VERSION 5.7 ;
BUSBITCHARS "[]" ;
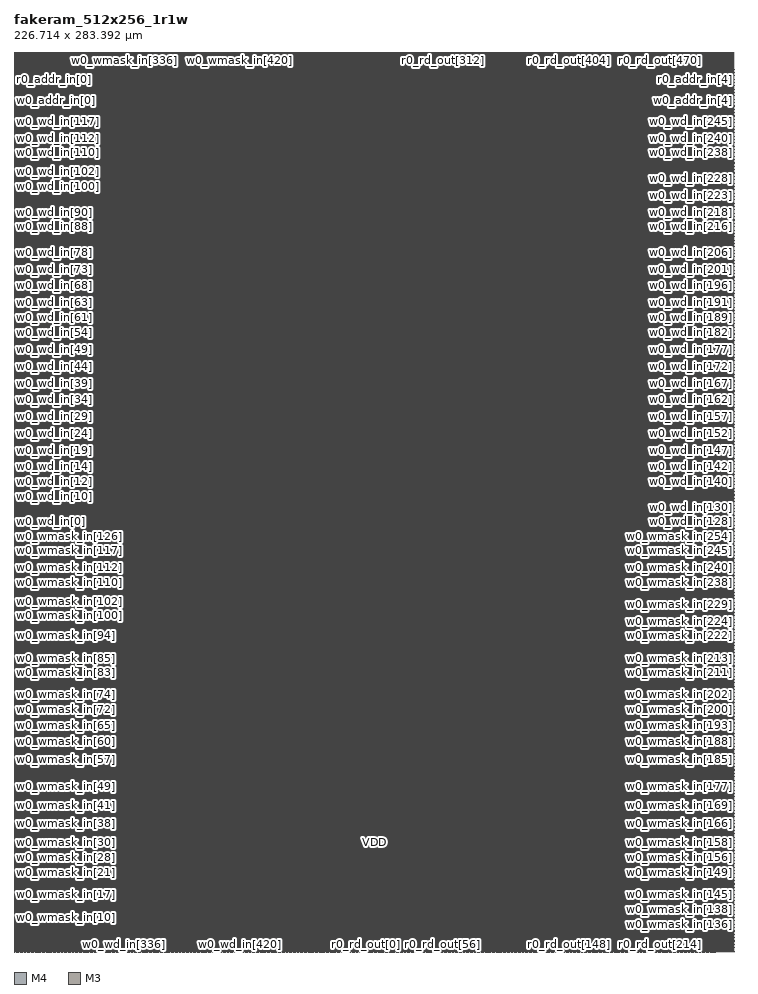
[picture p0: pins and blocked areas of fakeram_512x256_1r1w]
MACRO fakeram_512x256_1r1w
  FOREIGN fakeram_512x256_1r1w 0 0 ;
  SYMMETRY X Y R90 ;
  SIZE 226.714 BY 283.392 ;
  CLASS BLOCK ;
  PIN w0_wmask_in[0]
    DIRECTION INPUT ;
    USE SIGNAL ;
    SHAPE ABUTMENT ;
    PORT
      LAYER M4 ;
      RECT 0.000 0.276 0.072 0.300 ;
    END
  END w0_wmask_in[0]
  PIN w0_wmask_in[1]
    DIRECTION INPUT ;
    USE SIGNAL ;
    SHAPE ABUTMENT ;
    PORT
      LAYER M4 ;
      RECT 0.000 1.332 0.072 1.356 ;
    END
  END w0_wmask_in[1]
  PIN w0_wmask_in[2]
    DIRECTION INPUT ;
    USE SIGNAL ;
    SHAPE ABUTMENT ;
    PORT
      LAYER M4 ;
      RECT 0.000 2.388 0.072 2.412 ;
    END
  END w0_wmask_in[2]
  PIN w0_wmask_in[3]
    DIRECTION INPUT ;
    USE SIGNAL ;
    SHAPE ABUTMENT ;
    PORT
      LAYER M4 ;
      RECT 0.000 3.444 0.072 3.468 ;
    END
  END w0_wmask_in[3]
  PIN w0_wmask_in[4]
    DIRECTION INPUT ;
    USE SIGNAL ;
    SHAPE ABUTMENT ;
    PORT
      LAYER M4 ;
      RECT 0.000 4.500 0.072 4.524 ;
    END
  END w0_wmask_in[4]
  PIN w0_wmask_in[5]
    DIRECTION INPUT ;
    USE SIGNAL ;
    SHAPE ABUTMENT ;
    PORT
      LAYER M4 ;
      RECT 0.000 5.556 0.072 5.580 ;
    END
  END w0_wmask_in[5]
  PIN w0_wmask_in[6]
    DIRECTION INPUT ;
    USE SIGNAL ;
    SHAPE ABUTMENT ;
    PORT
      LAYER M4 ;
      RECT 0.000 6.612 0.072 6.636 ;
    END
  END w0_wmask_in[6]
  PIN w0_wmask_in[7]
    DIRECTION INPUT ;
    USE SIGNAL ;
    SHAPE ABUTMENT ;
    PORT
      LAYER M4 ;
      RECT 0.000 7.668 0.072 7.692 ;
    END
  END w0_wmask_in[7]
  PIN w0_wmask_in[8]
    DIRECTION INPUT ;
    USE SIGNAL ;
    SHAPE ABUTMENT ;
    PORT
      LAYER M4 ;
      RECT 0.000 8.724 0.072 8.748 ;
    END
  END w0_wmask_in[8]
  PIN w0_wmask_in[9]
    DIRECTION INPUT ;
    USE SIGNAL ;
    SHAPE ABUTMENT ;
    PORT
      LAYER M4 ;
      RECT 0.000 9.780 0.072 9.804 ;
    END
  END w0_wmask_in[9]
  PIN w0_wmask_in[10]
    DIRECTION INPUT ;
    USE SIGNAL ;
    SHAPE ABUTMENT ;
    PORT
      LAYER M4 ;
      RECT 0.000 10.836 0.072 10.860 ;
    END
  END w0_wmask_in[10]
  PIN w0_wmask_in[11]
    DIRECTION INPUT ;
    USE SIGNAL ;
    SHAPE ABUTMENT ;
    PORT
      LAYER M4 ;
      RECT 0.000 11.892 0.072 11.916 ;
    END
  END w0_wmask_in[11]
  PIN w0_wmask_in[12]
    DIRECTION INPUT ;
    USE SIGNAL ;
    SHAPE ABUTMENT ;
    PORT
      LAYER M4 ;
      RECT 0.000 12.948 0.072 12.972 ;
    END
  END w0_wmask_in[12]
  PIN w0_wmask_in[13]
    DIRECTION INPUT ;
    USE SIGNAL ;
    SHAPE ABUTMENT ;
    PORT
      LAYER M4 ;
      RECT 0.000 14.004 0.072 14.028 ;
    END
  END w0_wmask_in[13]
  PIN w0_wmask_in[14]
    DIRECTION INPUT ;
    USE SIGNAL ;
    SHAPE ABUTMENT ;
    PORT
      LAYER M4 ;
      RECT 0.000 15.060 0.072 15.084 ;
    END
  END w0_wmask_in[14]
  PIN w0_wmask_in[15]
    DIRECTION INPUT ;
    USE SIGNAL ;
    SHAPE ABUTMENT ;
    PORT
      LAYER M4 ;
      RECT 0.000 16.116 0.072 16.140 ;
    END
  END w0_wmask_in[15]
  PIN w0_wmask_in[16]
    DIRECTION INPUT ;
    USE SIGNAL ;
    SHAPE ABUTMENT ;
    PORT
      LAYER M4 ;
      RECT 0.000 17.172 0.072 17.196 ;
    END
  END w0_wmask_in[16]
  PIN w0_wmask_in[17]
    DIRECTION INPUT ;
    USE SIGNAL ;
    SHAPE ABUTMENT ;
    PORT
      LAYER M4 ;
      RECT 0.000 18.228 0.072 18.252 ;
    END
  END w0_wmask_in[17]
  PIN w0_wmask_in[18]
    DIRECTION INPUT ;
    USE SIGNAL ;
    SHAPE ABUTMENT ;
    PORT
      LAYER M4 ;
      RECT 0.000 19.284 0.072 19.308 ;
    END
  END w0_wmask_in[18]
  PIN w0_wmask_in[19]
    DIRECTION INPUT ;
    USE SIGNAL ;
    SHAPE ABUTMENT ;
    PORT
      LAYER M4 ;
      RECT 0.000 20.340 0.072 20.364 ;
    END
  END w0_wmask_in[19]
  PIN w0_wmask_in[20]
    DIRECTION INPUT ;
    USE SIGNAL ;
    SHAPE ABUTMENT ;
    PORT
      LAYER M4 ;
      RECT 0.000 21.396 0.072 21.420 ;
    END
  END w0_wmask_in[20]
  PIN w0_wmask_in[21]
    DIRECTION INPUT ;
    USE SIGNAL ;
    SHAPE ABUTMENT ;
    PORT
      LAYER M4 ;
      RECT 0.000 22.452 0.072 22.476 ;
    END
  END w0_wmask_in[21]
  PIN w0_wmask_in[22]
    DIRECTION INPUT ;
    USE SIGNAL ;
    SHAPE ABUTMENT ;
    PORT
      LAYER M4 ;
      RECT 0.000 23.508 0.072 23.532 ;
    END
  END w0_wmask_in[22]
  PIN w0_wmask_in[23]
    DIRECTION INPUT ;
    USE SIGNAL ;
    SHAPE ABUTMENT ;
    PORT
      LAYER M4 ;
      RECT 0.000 24.564 0.072 24.588 ;
    END
  END w0_wmask_in[23]
  PIN w0_wmask_in[24]
    DIRECTION INPUT ;
    USE SIGNAL ;
    SHAPE ABUTMENT ;
    PORT
      LAYER M4 ;
      RECT 0.000 25.620 0.072 25.644 ;
    END
  END w0_wmask_in[24]
  PIN w0_wmask_in[25]
    DIRECTION INPUT ;
    USE SIGNAL ;
    SHAPE ABUTMENT ;
    PORT
      LAYER M4 ;
      RECT 0.000 26.676 0.072 26.700 ;
    END
  END w0_wmask_in[25]
  PIN w0_wmask_in[26]
    DIRECTION INPUT ;
    USE SIGNAL ;
    SHAPE ABUTMENT ;
    PORT
      LAYER M4 ;
      RECT 0.000 27.732 0.072 27.756 ;
    END
  END w0_wmask_in[26]
  PIN w0_wmask_in[27]
    DIRECTION INPUT ;
    USE SIGNAL ;
    SHAPE ABUTMENT ;
    PORT
      LAYER M4 ;
      RECT 0.000 28.788 0.072 28.812 ;
    END
  END w0_wmask_in[27]
  PIN w0_wmask_in[28]
    DIRECTION INPUT ;
    USE SIGNAL ;
    SHAPE ABUTMENT ;
    PORT
      LAYER M4 ;
      RECT 0.000 29.844 0.072 29.868 ;
    END
  END w0_wmask_in[28]
  PIN w0_wmask_in[29]
    DIRECTION INPUT ;
    USE SIGNAL ;
    SHAPE ABUTMENT ;
    PORT
      LAYER M4 ;
      RECT 0.000 30.900 0.072 30.924 ;
    END
  END w0_wmask_in[29]
  PIN w0_wmask_in[30]
    DIRECTION INPUT ;
    USE SIGNAL ;
    SHAPE ABUTMENT ;
    PORT
      LAYER M4 ;
      RECT 0.000 31.956 0.072 31.980 ;
    END
  END w0_wmask_in[30]
  PIN w0_wmask_in[31]
    DIRECTION INPUT ;
    USE SIGNAL ;
    SHAPE ABUTMENT ;
    PORT
      LAYER M4 ;
      RECT 0.000 33.012 0.072 33.036 ;
    END
  END w0_wmask_in[31]
  PIN w0_wmask_in[32]
    DIRECTION INPUT ;
    USE SIGNAL ;
    SHAPE ABUTMENT ;
    PORT
      LAYER M4 ;
      RECT 0.000 34.068 0.072 34.092 ;
    END
  END w0_wmask_in[32]
  PIN w0_wmask_in[33]
    DIRECTION INPUT ;
    USE SIGNAL ;
    SHAPE ABUTMENT ;
    PORT
      LAYER M4 ;
      RECT 0.000 35.124 0.072 35.148 ;
    END
  END w0_wmask_in[33]
  PIN w0_wmask_in[34]
    DIRECTION INPUT ;
    USE SIGNAL ;
    SHAPE ABUTMENT ;
    PORT
      LAYER M4 ;
      RECT 0.000 36.180 0.072 36.204 ;
    END
  END w0_wmask_in[34]
  PIN w0_wmask_in[35]
    DIRECTION INPUT ;
    USE SIGNAL ;
    SHAPE ABUTMENT ;
    PORT
      LAYER M4 ;
      RECT 0.000 37.236 0.072 37.260 ;
    END
  END w0_wmask_in[35]
  PIN w0_wmask_in[36]
    DIRECTION INPUT ;
    USE SIGNAL ;
    SHAPE ABUTMENT ;
    PORT
      LAYER M4 ;
      RECT 0.000 38.292 0.072 38.316 ;
    END
  END w0_wmask_in[36]
  PIN w0_wmask_in[37]
    DIRECTION INPUT ;
    USE SIGNAL ;
    SHAPE ABUTMENT ;
    PORT
      LAYER M4 ;
      RECT 0.000 39.348 0.072 39.372 ;
    END
  END w0_wmask_in[37]
  PIN w0_wmask_in[38]
    DIRECTION INPUT ;
    USE SIGNAL ;
    SHAPE ABUTMENT ;
    PORT
      LAYER M4 ;
      RECT 0.000 40.404 0.072 40.428 ;
    END
  END w0_wmask_in[38]
  PIN w0_wmask_in[39]
    DIRECTION INPUT ;
    USE SIGNAL ;
    SHAPE ABUTMENT ;
    PORT
      LAYER M4 ;
      RECT 0.000 41.460 0.072 41.484 ;
    END
  END w0_wmask_in[39]
  PIN w0_wmask_in[40]
    DIRECTION INPUT ;
    USE SIGNAL ;
    SHAPE ABUTMENT ;
    PORT
      LAYER M4 ;
      RECT 0.000 42.516 0.072 42.540 ;
    END
  END w0_wmask_in[40]
  PIN w0_wmask_in[41]
    DIRECTION INPUT ;
    USE SIGNAL ;
    SHAPE ABUTMENT ;
    PORT
      LAYER M4 ;
      RECT 0.000 43.572 0.072 43.596 ;
    END
  END w0_wmask_in[41]
  PIN w0_wmask_in[42]
    DIRECTION INPUT ;
    USE SIGNAL ;
    SHAPE ABUTMENT ;
    PORT
      LAYER M4 ;
      RECT 0.000 44.628 0.072 44.652 ;
    END
  END w0_wmask_in[42]
  PIN w0_wmask_in[43]
    DIRECTION INPUT ;
    USE SIGNAL ;
    SHAPE ABUTMENT ;
    PORT
      LAYER M4 ;
      RECT 0.000 45.684 0.072 45.708 ;
    END
  END w0_wmask_in[43]
  PIN w0_wmask_in[44]
    DIRECTION INPUT ;
    USE SIGNAL ;
    SHAPE ABUTMENT ;
    PORT
      LAYER M4 ;
      RECT 0.000 46.740 0.072 46.764 ;
    END
  END w0_wmask_in[44]
  PIN w0_wmask_in[45]
    DIRECTION INPUT ;
    USE SIGNAL ;
    SHAPE ABUTMENT ;
    PORT
      LAYER M4 ;
      RECT 0.000 47.796 0.072 47.820 ;
    END
  END w0_wmask_in[45]
  PIN w0_wmask_in[46]
    DIRECTION INPUT ;
    USE SIGNAL ;
    SHAPE ABUTMENT ;
    PORT
      LAYER M4 ;
      RECT 0.000 48.852 0.072 48.876 ;
    END
  END w0_wmask_in[46]
  PIN w0_wmask_in[47]
    DIRECTION INPUT ;
    USE SIGNAL ;
    SHAPE ABUTMENT ;
    PORT
      LAYER M4 ;
      RECT 0.000 49.908 0.072 49.932 ;
    END
  END w0_wmask_in[47]
  PIN w0_wmask_in[48]
    DIRECTION INPUT ;
    USE SIGNAL ;
    SHAPE ABUTMENT ;
    PORT
      LAYER M4 ;
      RECT 0.000 50.964 0.072 50.988 ;
    END
  END w0_wmask_in[48]
  PIN w0_wmask_in[49]
    DIRECTION INPUT ;
    USE SIGNAL ;
    SHAPE ABUTMENT ;
    PORT
      LAYER M4 ;
      RECT 0.000 52.020 0.072 52.044 ;
    END
  END w0_wmask_in[49]
  PIN w0_wmask_in[50]
    DIRECTION INPUT ;
    USE SIGNAL ;
    SHAPE ABUTMENT ;
    PORT
      LAYER M4 ;
      RECT 0.000 53.076 0.072 53.100 ;
    END
  END w0_wmask_in[50]
  PIN w0_wmask_in[51]
    DIRECTION INPUT ;
    USE SIGNAL ;
    SHAPE ABUTMENT ;
    PORT
      LAYER M4 ;
      RECT 0.000 54.132 0.072 54.156 ;
    END
  END w0_wmask_in[51]
  PIN w0_wmask_in[52]
    DIRECTION INPUT ;
    USE SIGNAL ;
    SHAPE ABUTMENT ;
    PORT
      LAYER M4 ;
      RECT 0.000 55.188 0.072 55.212 ;
    END
  END w0_wmask_in[52]
  PIN w0_wmask_in[53]
    DIRECTION INPUT ;
    USE SIGNAL ;
    SHAPE ABUTMENT ;
    PORT
      LAYER M4 ;
      RECT 0.000 56.244 0.072 56.268 ;
    END
  END w0_wmask_in[53]
  PIN w0_wmask_in[54]
    DIRECTION INPUT ;
    USE SIGNAL ;
    SHAPE ABUTMENT ;
    PORT
      LAYER M4 ;
      RECT 0.000 57.300 0.072 57.324 ;
    END
  END w0_wmask_in[54]
  PIN w0_wmask_in[55]
    DIRECTION INPUT ;
    USE SIGNAL ;
    SHAPE ABUTMENT ;
    PORT
      LAYER M4 ;
      RECT 0.000 58.356 0.072 58.380 ;
    END
  END w0_wmask_in[55]
  PIN w0_wmask_in[56]
    DIRECTION INPUT ;
    USE SIGNAL ;
    SHAPE ABUTMENT ;
    PORT
      LAYER M4 ;
      RECT 0.000 59.412 0.072 59.436 ;
    END
  END w0_wmask_in[56]
  PIN w0_wmask_in[57]
    DIRECTION INPUT ;
    USE SIGNAL ;
    SHAPE ABUTMENT ;
    PORT
      LAYER M4 ;
      RECT 0.000 60.468 0.072 60.492 ;
    END
  END w0_wmask_in[57]
  PIN w0_wmask_in[58]
    DIRECTION INPUT ;
    USE SIGNAL ;
    SHAPE ABUTMENT ;
    PORT
      LAYER M4 ;
      RECT 0.000 61.524 0.072 61.548 ;
    END
  END w0_wmask_in[58]
  PIN w0_wmask_in[59]
    DIRECTION INPUT ;
    USE SIGNAL ;
    SHAPE ABUTMENT ;
    PORT
      LAYER M4 ;
      RECT 0.000 62.580 0.072 62.604 ;
    END
  END w0_wmask_in[59]
  PIN w0_wmask_in[60]
    DIRECTION INPUT ;
    USE SIGNAL ;
    SHAPE ABUTMENT ;
    PORT
      LAYER M4 ;
      RECT 0.000 63.636 0.072 63.660 ;
    END
  END w0_wmask_in[60]
  PIN w0_wmask_in[61]
    DIRECTION INPUT ;
    USE SIGNAL ;
    SHAPE ABUTMENT ;
    PORT
      LAYER M4 ;
      RECT 0.000 64.692 0.072 64.716 ;
    END
  END w0_wmask_in[61]
  PIN w0_wmask_in[62]
    DIRECTION INPUT ;
    USE SIGNAL ;
    SHAPE ABUTMENT ;
    PORT
      LAYER M4 ;
      RECT 0.000 65.748 0.072 65.772 ;
    END
  END w0_wmask_in[62]
  PIN w0_wmask_in[63]
    DIRECTION INPUT ;
    USE SIGNAL ;
    SHAPE ABUTMENT ;
    PORT
      LAYER M4 ;
      RECT 0.000 66.804 0.072 66.828 ;
    END
  END w0_wmask_in[63]
  PIN w0_wmask_in[64]
    DIRECTION INPUT ;
    USE SIGNAL ;
    SHAPE ABUTMENT ;
    PORT
      LAYER M4 ;
      RECT 0.000 67.860 0.072 67.884 ;
    END
  END w0_wmask_in[64]
  PIN w0_wmask_in[65]
    DIRECTION INPUT ;
    USE SIGNAL ;
    SHAPE ABUTMENT ;
    PORT
      LAYER M4 ;
      RECT 0.000 68.916 0.072 68.940 ;
    END
  END w0_wmask_in[65]
  PIN w0_wmask_in[66]
    DIRECTION INPUT ;
    USE SIGNAL ;
    SHAPE ABUTMENT ;
    PORT
      LAYER M4 ;
      RECT 0.000 69.972 0.072 69.996 ;
    END
  END w0_wmask_in[66]
  PIN w0_wmask_in[67]
    DIRECTION INPUT ;
    USE SIGNAL ;
    SHAPE ABUTMENT ;
    PORT
      LAYER M4 ;
      RECT 0.000 71.028 0.072 71.052 ;
    END
  END w0_wmask_in[67]
  PIN w0_wmask_in[68]
    DIRECTION INPUT ;
    USE SIGNAL ;
    SHAPE ABUTMENT ;
    PORT
      LAYER M4 ;
      RECT 0.000 72.084 0.072 72.108 ;
    END
  END w0_wmask_in[68]
  PIN w0_wmask_in[69]
    DIRECTION INPUT ;
    USE SIGNAL ;
    SHAPE ABUTMENT ;
    PORT
      LAYER M4 ;
      RECT 0.000 73.140 0.072 73.164 ;
    END
  END w0_wmask_in[69]
  PIN w0_wmask_in[70]
    DIRECTION INPUT ;
    USE SIGNAL ;
    SHAPE ABUTMENT ;
    PORT
      LAYER M4 ;
      RECT 0.000 74.196 0.072 74.220 ;
    END
  END w0_wmask_in[70]
  PIN w0_wmask_in[71]
    DIRECTION INPUT ;
    USE SIGNAL ;
    SHAPE ABUTMENT ;
    PORT
      LAYER M4 ;
      RECT 0.000 75.252 0.072 75.276 ;
    END
  END w0_wmask_in[71]
  PIN w0_wmask_in[72]
    DIRECTION INPUT ;
    USE SIGNAL ;
    SHAPE ABUTMENT ;
    PORT
      LAYER M4 ;
      RECT 0.000 76.308 0.072 76.332 ;
    END
  END w0_wmask_in[72]
  PIN w0_wmask_in[73]
    DIRECTION INPUT ;
    USE SIGNAL ;
    SHAPE ABUTMENT ;
    PORT
      LAYER M4 ;
      RECT 0.000 77.364 0.072 77.388 ;
    END
  END w0_wmask_in[73]
  PIN w0_wmask_in[74]
    DIRECTION INPUT ;
    USE SIGNAL ;
    SHAPE ABUTMENT ;
    PORT
      LAYER M4 ;
      RECT 0.000 78.420 0.072 78.444 ;
    END
  END w0_wmask_in[74]
  PIN w0_wmask_in[75]
    DIRECTION INPUT ;
    USE SIGNAL ;
    SHAPE ABUTMENT ;
    PORT
      LAYER M4 ;
      RECT 0.000 79.476 0.072 79.500 ;
    END
  END w0_wmask_in[75]
  PIN w0_wmask_in[76]
    DIRECTION INPUT ;
    USE SIGNAL ;
    SHAPE ABUTMENT ;
    PORT
      LAYER M4 ;
      RECT 0.000 80.532 0.072 80.556 ;
    END
  END w0_wmask_in[76]
  PIN w0_wmask_in[77]
    DIRECTION INPUT ;
    USE SIGNAL ;
    SHAPE ABUTMENT ;
    PORT
      LAYER M4 ;
      RECT 0.000 81.588 0.072 81.612 ;
    END
  END w0_wmask_in[77]
  PIN w0_wmask_in[78]
    DIRECTION INPUT ;
    USE SIGNAL ;
    SHAPE ABUTMENT ;
    PORT
      LAYER M4 ;
      RECT 0.000 82.644 0.072 82.668 ;
    END
  END w0_wmask_in[78]
  PIN w0_wmask_in[79]
    DIRECTION INPUT ;
    USE SIGNAL ;
    SHAPE ABUTMENT ;
    PORT
      LAYER M4 ;
      RECT 0.000 83.700 0.072 83.724 ;
    END
  END w0_wmask_in[79]
  PIN w0_wmask_in[80]
    DIRECTION INPUT ;
    USE SIGNAL ;
    SHAPE ABUTMENT ;
    PORT
      LAYER M4 ;
      RECT 0.000 84.756 0.072 84.780 ;
    END
  END w0_wmask_in[80]
  PIN w0_wmask_in[81]
    DIRECTION INPUT ;
    USE SIGNAL ;
    SHAPE ABUTMENT ;
    PORT
      LAYER M4 ;
      RECT 0.000 85.812 0.072 85.836 ;
    END
  END w0_wmask_in[81]
  PIN w0_wmask_in[82]
    DIRECTION INPUT ;
    USE SIGNAL ;
    SHAPE ABUTMENT ;
    PORT
      LAYER M4 ;
      RECT 0.000 86.868 0.072 86.892 ;
    END
  END w0_wmask_in[82]
  PIN w0_wmask_in[83]
    DIRECTION INPUT ;
    USE SIGNAL ;
    SHAPE ABUTMENT ;
    PORT
      LAYER M4 ;
      RECT 0.000 87.924 0.072 87.948 ;
    END
  END w0_wmask_in[83]
  PIN w0_wmask_in[84]
    DIRECTION INPUT ;
    USE SIGNAL ;
    SHAPE ABUTMENT ;
    PORT
      LAYER M4 ;
      RECT 0.000 88.980 0.072 89.004 ;
    END
  END w0_wmask_in[84]
  PIN w0_wmask_in[85]
    DIRECTION INPUT ;
    USE SIGNAL ;
    SHAPE ABUTMENT ;
    PORT
      LAYER M4 ;
      RECT 0.000 90.036 0.072 90.060 ;
    END
  END w0_wmask_in[85]
  PIN w0_wmask_in[86]
    DIRECTION INPUT ;
    USE SIGNAL ;
    SHAPE ABUTMENT ;
    PORT
      LAYER M4 ;
      RECT 0.000 91.092 0.072 91.116 ;
    END
  END w0_wmask_in[86]
  PIN w0_wmask_in[87]
    DIRECTION INPUT ;
    USE SIGNAL ;
    SHAPE ABUTMENT ;
    PORT
      LAYER M4 ;
      RECT 0.000 92.148 0.072 92.172 ;
    END
  END w0_wmask_in[87]
  PIN w0_wmask_in[88]
    DIRECTION INPUT ;
    USE SIGNAL ;
    SHAPE ABUTMENT ;
    PORT
      LAYER M4 ;
      RECT 0.000 93.204 0.072 93.228 ;
    END
  END w0_wmask_in[88]
  PIN w0_wmask_in[89]
    DIRECTION INPUT ;
    USE SIGNAL ;
    SHAPE ABUTMENT ;
    PORT
      LAYER M4 ;
      RECT 0.000 94.260 0.072 94.284 ;
    END
  END w0_wmask_in[89]
  PIN w0_wmask_in[90]
    DIRECTION INPUT ;
    USE SIGNAL ;
    SHAPE ABUTMENT ;
    PORT
      LAYER M4 ;
      RECT 0.000 95.316 0.072 95.340 ;
    END
  END w0_wmask_in[90]
  PIN w0_wmask_in[91]
    DIRECTION INPUT ;
    USE SIGNAL ;
    SHAPE ABUTMENT ;
    PORT
      LAYER M4 ;
      RECT 0.000 96.372 0.072 96.396 ;
    END
  END w0_wmask_in[91]
  PIN w0_wmask_in[92]
    DIRECTION INPUT ;
    USE SIGNAL ;
    SHAPE ABUTMENT ;
    PORT
      LAYER M4 ;
      RECT 0.000 97.428 0.072 97.452 ;
    END
  END w0_wmask_in[92]
  PIN w0_wmask_in[93]
    DIRECTION INPUT ;
    USE SIGNAL ;
    SHAPE ABUTMENT ;
    PORT
      LAYER M4 ;
      RECT 0.000 98.484 0.072 98.508 ;
    END
  END w0_wmask_in[93]
  PIN w0_wmask_in[94]
    DIRECTION INPUT ;
    USE SIGNAL ;
    SHAPE ABUTMENT ;
    PORT
      LAYER M4 ;
      RECT 0.000 99.540 0.072 99.564 ;
    END
  END w0_wmask_in[94]
  PIN w0_wmask_in[95]
    DIRECTION INPUT ;
    USE SIGNAL ;
    SHAPE ABUTMENT ;
    PORT
      LAYER M4 ;
      RECT 0.000 100.596 0.072 100.620 ;
    END
  END w0_wmask_in[95]
  PIN w0_wmask_in[96]
    DIRECTION INPUT ;
    USE SIGNAL ;
    SHAPE ABUTMENT ;
    PORT
      LAYER M4 ;
      RECT 0.000 101.652 0.072 101.676 ;
    END
  END w0_wmask_in[96]
  PIN w0_wmask_in[97]
    DIRECTION INPUT ;
    USE SIGNAL ;
    SHAPE ABUTMENT ;
    PORT
      LAYER M4 ;
      RECT 0.000 102.708 0.072 102.732 ;
    END
  END w0_wmask_in[97]
  PIN w0_wmask_in[98]
    DIRECTION INPUT ;
    USE SIGNAL ;
    SHAPE ABUTMENT ;
    PORT
      LAYER M4 ;
      RECT 0.000 103.764 0.072 103.788 ;
    END
  END w0_wmask_in[98]
  PIN w0_wmask_in[99]
    DIRECTION INPUT ;
    USE SIGNAL ;
    SHAPE ABUTMENT ;
    PORT
      LAYER M4 ;
      RECT 0.000 104.820 0.072 104.844 ;
    END
  END w0_wmask_in[99]
  PIN w0_wmask_in[100]
    DIRECTION INPUT ;
    USE SIGNAL ;
    SHAPE ABUTMENT ;
    PORT
      LAYER M4 ;
      RECT 0.000 105.876 0.072 105.900 ;
    END
  END w0_wmask_in[100]
  PIN w0_wmask_in[101]
    DIRECTION INPUT ;
    USE SIGNAL ;
    SHAPE ABUTMENT ;
    PORT
      LAYER M4 ;
      RECT 0.000 106.932 0.072 106.956 ;
    END
  END w0_wmask_in[101]
  PIN w0_wmask_in[102]
    DIRECTION INPUT ;
    USE SIGNAL ;
    SHAPE ABUTMENT ;
    PORT
      LAYER M4 ;
      RECT 0.000 107.988 0.072 108.012 ;
    END
  END w0_wmask_in[102]
  PIN w0_wmask_in[103]
    DIRECTION INPUT ;
    USE SIGNAL ;
    SHAPE ABUTMENT ;
    PORT
      LAYER M4 ;
      RECT 0.000 109.044 0.072 109.068 ;
    END
  END w0_wmask_in[103]
  PIN w0_wmask_in[104]
    DIRECTION INPUT ;
    USE SIGNAL ;
    SHAPE ABUTMENT ;
    PORT
      LAYER M4 ;
      RECT 0.000 110.100 0.072 110.124 ;
    END
  END w0_wmask_in[104]
  PIN w0_wmask_in[105]
    DIRECTION INPUT ;
    USE SIGNAL ;
    SHAPE ABUTMENT ;
    PORT
      LAYER M4 ;
      RECT 0.000 111.156 0.072 111.180 ;
    END
  END w0_wmask_in[105]
  PIN w0_wmask_in[106]
    DIRECTION INPUT ;
    USE SIGNAL ;
    SHAPE ABUTMENT ;
    PORT
      LAYER M4 ;
      RECT 0.000 112.212 0.072 112.236 ;
    END
  END w0_wmask_in[106]
  PIN w0_wmask_in[107]
    DIRECTION INPUT ;
    USE SIGNAL ;
    SHAPE ABUTMENT ;
    PORT
      LAYER M4 ;
      RECT 0.000 113.268 0.072 113.292 ;
    END
  END w0_wmask_in[107]
  PIN w0_wmask_in[108]
    DIRECTION INPUT ;
    USE SIGNAL ;
    SHAPE ABUTMENT ;
    PORT
      LAYER M4 ;
      RECT 0.000 114.324 0.072 114.348 ;
    END
  END w0_wmask_in[108]
  PIN w0_wmask_in[109]
    DIRECTION INPUT ;
    USE SIGNAL ;
    SHAPE ABUTMENT ;
    PORT
      LAYER M4 ;
      RECT 0.000 115.380 0.072 115.404 ;
    END
  END w0_wmask_in[109]
  PIN w0_wmask_in[110]
    DIRECTION INPUT ;
    USE SIGNAL ;
    SHAPE ABUTMENT ;
    PORT
      LAYER M4 ;
      RECT 0.000 116.436 0.072 116.460 ;
    END
  END w0_wmask_in[110]
  PIN w0_wmask_in[111]
    DIRECTION INPUT ;
    USE SIGNAL ;
    SHAPE ABUTMENT ;
    PORT
      LAYER M4 ;
      RECT 0.000 117.492 0.072 117.516 ;
    END
  END w0_wmask_in[111]
  PIN w0_wmask_in[112]
    DIRECTION INPUT ;
    USE SIGNAL ;
    SHAPE ABUTMENT ;
    PORT
      LAYER M4 ;
      RECT 0.000 118.548 0.072 118.572 ;
    END
  END w0_wmask_in[112]
  PIN w0_wmask_in[113]
    DIRECTION INPUT ;
    USE SIGNAL ;
    SHAPE ABUTMENT ;
    PORT
      LAYER M4 ;
      RECT 0.000 119.604 0.072 119.628 ;
    END
  END w0_wmask_in[113]
  PIN w0_wmask_in[114]
    DIRECTION INPUT ;
    USE SIGNAL ;
    SHAPE ABUTMENT ;
    PORT
      LAYER M4 ;
      RECT 0.000 120.660 0.072 120.684 ;
    END
  END w0_wmask_in[114]
  PIN w0_wmask_in[115]
    DIRECTION INPUT ;
    USE SIGNAL ;
    SHAPE ABUTMENT ;
    PORT
      LAYER M4 ;
      RECT 0.000 121.716 0.072 121.740 ;
    END
  END w0_wmask_in[115]
  PIN w0_wmask_in[116]
    DIRECTION INPUT ;
    USE SIGNAL ;
    SHAPE ABUTMENT ;
    PORT
      LAYER M4 ;
      RECT 0.000 122.772 0.072 122.796 ;
    END
  END w0_wmask_in[116]
  PIN w0_wmask_in[117]
    DIRECTION INPUT ;
    USE SIGNAL ;
    SHAPE ABUTMENT ;
    PORT
      LAYER M4 ;
      RECT 0.000 123.828 0.072 123.852 ;
    END
  END w0_wmask_in[117]
  PIN w0_wmask_in[118]
    DIRECTION INPUT ;
    USE SIGNAL ;
    SHAPE ABUTMENT ;
    PORT
      LAYER M4 ;
      RECT 0.000 124.884 0.072 124.908 ;
    END
  END w0_wmask_in[118]
  PIN w0_wmask_in[119]
    DIRECTION INPUT ;
    USE SIGNAL ;
    SHAPE ABUTMENT ;
    PORT
      LAYER M4 ;
      RECT 0.000 125.940 0.072 125.964 ;
    END
  END w0_wmask_in[119]
  PIN w0_wmask_in[120]
    DIRECTION INPUT ;
    USE SIGNAL ;
    SHAPE ABUTMENT ;
    PORT
      LAYER M4 ;
      RECT 0.000 126.996 0.072 127.020 ;
    END
  END w0_wmask_in[120]
  PIN w0_wmask_in[121]
    DIRECTION INPUT ;
    USE SIGNAL ;
    SHAPE ABUTMENT ;
    PORT
      LAYER M4 ;
      RECT 0.000 128.052 0.072 128.076 ;
    END
  END w0_wmask_in[121]
  PIN w0_wmask_in[122]
    DIRECTION INPUT ;
    USE SIGNAL ;
    SHAPE ABUTMENT ;
    PORT
      LAYER M4 ;
      RECT 0.000 129.108 0.072 129.132 ;
    END
  END w0_wmask_in[122]
  PIN w0_wmask_in[123]
    DIRECTION INPUT ;
    USE SIGNAL ;
    SHAPE ABUTMENT ;
    PORT
      LAYER M4 ;
      RECT 0.000 130.164 0.072 130.188 ;
    END
  END w0_wmask_in[123]
  PIN w0_wmask_in[124]
    DIRECTION INPUT ;
    USE SIGNAL ;
    SHAPE ABUTMENT ;
    PORT
      LAYER M4 ;
      RECT 0.000 131.220 0.072 131.244 ;
    END
  END w0_wmask_in[124]
  PIN w0_wmask_in[125]
    DIRECTION INPUT ;
    USE SIGNAL ;
    SHAPE ABUTMENT ;
    PORT
      LAYER M4 ;
      RECT 0.000 132.276 0.072 132.300 ;
    END
  END w0_wmask_in[125]
  PIN w0_wmask_in[126]
    DIRECTION INPUT ;
    USE SIGNAL ;
    SHAPE ABUTMENT ;
    PORT
      LAYER M4 ;
      RECT 0.000 133.332 0.072 133.356 ;
    END
  END w0_wmask_in[126]
  PIN w0_wmask_in[127]
    DIRECTION INPUT ;
    USE SIGNAL ;
    SHAPE ABUTMENT ;
    PORT
      LAYER M4 ;
      RECT 0.000 134.388 0.072 134.412 ;
    END
  END w0_wmask_in[127]
  PIN w0_wmask_in[128]
    DIRECTION INPUT ;
    USE SIGNAL ;
    SHAPE ABUTMENT ;
    PORT
      LAYER M4 ;
      RECT 226.642 0.276 226.714 0.300 ;
    END
  END w0_wmask_in[128]
  PIN w0_wmask_in[129]
    DIRECTION INPUT ;
    USE SIGNAL ;
    SHAPE ABUTMENT ;
    PORT
      LAYER M4 ;
      RECT 226.642 1.332 226.714 1.356 ;
    END
  END w0_wmask_in[129]
  PIN w0_wmask_in[130]
    DIRECTION INPUT ;
    USE SIGNAL ;
    SHAPE ABUTMENT ;
    PORT
      LAYER M4 ;
      RECT 226.642 2.388 226.714 2.412 ;
    END
  END w0_wmask_in[130]
  PIN w0_wmask_in[131]
    DIRECTION INPUT ;
    USE SIGNAL ;
    SHAPE ABUTMENT ;
    PORT
      LAYER M4 ;
      RECT 226.642 3.444 226.714 3.468 ;
    END
  END w0_wmask_in[131]
  PIN w0_wmask_in[132]
    DIRECTION INPUT ;
    USE SIGNAL ;
    SHAPE ABUTMENT ;
    PORT
      LAYER M4 ;
      RECT 226.642 4.500 226.714 4.524 ;
    END
  END w0_wmask_in[132]
  PIN w0_wmask_in[133]
    DIRECTION INPUT ;
    USE SIGNAL ;
    SHAPE ABUTMENT ;
    PORT
      LAYER M4 ;
      RECT 226.642 5.556 226.714 5.580 ;
    END
  END w0_wmask_in[133]
  PIN w0_wmask_in[134]
    DIRECTION INPUT ;
    USE SIGNAL ;
    SHAPE ABUTMENT ;
    PORT
      LAYER M4 ;
      RECT 226.642 6.612 226.714 6.636 ;
    END
  END w0_wmask_in[134]
  PIN w0_wmask_in[135]
    DIRECTION INPUT ;
    USE SIGNAL ;
    SHAPE ABUTMENT ;
    PORT
      LAYER M4 ;
      RECT 226.642 7.668 226.714 7.692 ;
    END
  END w0_wmask_in[135]
  PIN w0_wmask_in[136]
    DIRECTION INPUT ;
    USE SIGNAL ;
    SHAPE ABUTMENT ;
    PORT
      LAYER M4 ;
      RECT 226.642 8.724 226.714 8.748 ;
    END
  END w0_wmask_in[136]
  PIN w0_wmask_in[137]
    DIRECTION INPUT ;
    USE SIGNAL ;
    SHAPE ABUTMENT ;
    PORT
      LAYER M4 ;
      RECT 226.642 9.780 226.714 9.804 ;
    END
  END w0_wmask_in[137]
  PIN w0_wmask_in[138]
    DIRECTION INPUT ;
    USE SIGNAL ;
    SHAPE ABUTMENT ;
    PORT
      LAYER M4 ;
      RECT 226.642 10.836 226.714 10.860 ;
    END
  END w0_wmask_in[138]
  PIN w0_wmask_in[139]
    DIRECTION INPUT ;
    USE SIGNAL ;
    SHAPE ABUTMENT ;
    PORT
      LAYER M4 ;
      RECT 226.642 11.892 226.714 11.916 ;
    END
  END w0_wmask_in[139]
  PIN w0_wmask_in[140]
    DIRECTION INPUT ;
    USE SIGNAL ;
    SHAPE ABUTMENT ;
    PORT
      LAYER M4 ;
      RECT 226.642 12.948 226.714 12.972 ;
    END
  END w0_wmask_in[140]
  PIN w0_wmask_in[141]
    DIRECTION INPUT ;
    USE SIGNAL ;
    SHAPE ABUTMENT ;
    PORT
      LAYER M4 ;
      RECT 226.642 14.004 226.714 14.028 ;
    END
  END w0_wmask_in[141]
  PIN w0_wmask_in[142]
    DIRECTION INPUT ;
    USE SIGNAL ;
    SHAPE ABUTMENT ;
    PORT
      LAYER M4 ;
      RECT 226.642 15.060 226.714 15.084 ;
    END
  END w0_wmask_in[142]
  PIN w0_wmask_in[143]
    DIRECTION INPUT ;
    USE SIGNAL ;
    SHAPE ABUTMENT ;
    PORT
      LAYER M4 ;
      RECT 226.642 16.116 226.714 16.140 ;
    END
  END w0_wmask_in[143]
  PIN w0_wmask_in[144]
    DIRECTION INPUT ;
    USE SIGNAL ;
    SHAPE ABUTMENT ;
    PORT
      LAYER M4 ;
      RECT 226.642 17.172 226.714 17.196 ;
    END
  END w0_wmask_in[144]
  PIN w0_wmask_in[145]
    DIRECTION INPUT ;
    USE SIGNAL ;
    SHAPE ABUTMENT ;
    PORT
      LAYER M4 ;
      RECT 226.642 18.228 226.714 18.252 ;
    END
  END w0_wmask_in[145]
  PIN w0_wmask_in[146]
    DIRECTION INPUT ;
    USE SIGNAL ;
    SHAPE ABUTMENT ;
    PORT
      LAYER M4 ;
      RECT 226.642 19.284 226.714 19.308 ;
    END
  END w0_wmask_in[146]
  PIN w0_wmask_in[147]
    DIRECTION INPUT ;
    USE SIGNAL ;
    SHAPE ABUTMENT ;
    PORT
      LAYER M4 ;
      RECT 226.642 20.340 226.714 20.364 ;
    END
  END w0_wmask_in[147]
  PIN w0_wmask_in[148]
    DIRECTION INPUT ;
    USE SIGNAL ;
    SHAPE ABUTMENT ;
    PORT
      LAYER M4 ;
      RECT 226.642 21.396 226.714 21.420 ;
    END
  END w0_wmask_in[148]
  PIN w0_wmask_in[149]
    DIRECTION INPUT ;
    USE SIGNAL ;
    SHAPE ABUTMENT ;
    PORT
      LAYER M4 ;
      RECT 226.642 22.452 226.714 22.476 ;
    END
  END w0_wmask_in[149]
  PIN w0_wmask_in[150]
    DIRECTION INPUT ;
    USE SIGNAL ;
    SHAPE ABUTMENT ;
    PORT
      LAYER M4 ;
      RECT 226.642 23.508 226.714 23.532 ;
    END
  END w0_wmask_in[150]
  PIN w0_wmask_in[151]
    DIRECTION INPUT ;
    USE SIGNAL ;
    SHAPE ABUTMENT ;
    PORT
      LAYER M4 ;
      RECT 226.642 24.564 226.714 24.588 ;
    END
  END w0_wmask_in[151]
  PIN w0_wmask_in[152]
    DIRECTION INPUT ;
    USE SIGNAL ;
    SHAPE ABUTMENT ;
    PORT
      LAYER M4 ;
      RECT 226.642 25.620 226.714 25.644 ;
    END
  END w0_wmask_in[152]
  PIN w0_wmask_in[153]
    DIRECTION INPUT ;
    USE SIGNAL ;
    SHAPE ABUTMENT ;
    PORT
      LAYER M4 ;
      RECT 226.642 26.676 226.714 26.700 ;
    END
  END w0_wmask_in[153]
  PIN w0_wmask_in[154]
    DIRECTION INPUT ;
    USE SIGNAL ;
    SHAPE ABUTMENT ;
    PORT
      LAYER M4 ;
      RECT 226.642 27.732 226.714 27.756 ;
    END
  END w0_wmask_in[154]
  PIN w0_wmask_in[155]
    DIRECTION INPUT ;
    USE SIGNAL ;
    SHAPE ABUTMENT ;
    PORT
      LAYER M4 ;
      RECT 226.642 28.788 226.714 28.812 ;
    END
  END w0_wmask_in[155]
  PIN w0_wmask_in[156]
    DIRECTION INPUT ;
    USE SIGNAL ;
    SHAPE ABUTMENT ;
    PORT
      LAYER M4 ;
      RECT 226.642 29.844 226.714 29.868 ;
    END
  END w0_wmask_in[156]
  PIN w0_wmask_in[157]
    DIRECTION INPUT ;
    USE SIGNAL ;
    SHAPE ABUTMENT ;
    PORT
      LAYER M4 ;
      RECT 226.642 30.900 226.714 30.924 ;
    END
  END w0_wmask_in[157]
  PIN w0_wmask_in[158]
    DIRECTION INPUT ;
    USE SIGNAL ;
    SHAPE ABUTMENT ;
    PORT
      LAYER M4 ;
      RECT 226.642 31.956 226.714 31.980 ;
    END
  END w0_wmask_in[158]
  PIN w0_wmask_in[159]
    DIRECTION INPUT ;
    USE SIGNAL ;
    SHAPE ABUTMENT ;
    PORT
      LAYER M4 ;
      RECT 226.642 33.012 226.714 33.036 ;
    END
  END w0_wmask_in[159]
  PIN w0_wmask_in[160]
    DIRECTION INPUT ;
    USE SIGNAL ;
    SHAPE ABUTMENT ;
    PORT
      LAYER M4 ;
      RECT 226.642 34.068 226.714 34.092 ;
    END
  END w0_wmask_in[160]
  PIN w0_wmask_in[161]
    DIRECTION INPUT ;
    USE SIGNAL ;
    SHAPE ABUTMENT ;
    PORT
      LAYER M4 ;
      RECT 226.642 35.124 226.714 35.148 ;
    END
  END w0_wmask_in[161]
  PIN w0_wmask_in[162]
    DIRECTION INPUT ;
    USE SIGNAL ;
    SHAPE ABUTMENT ;
    PORT
      LAYER M4 ;
      RECT 226.642 36.180 226.714 36.204 ;
    END
  END w0_wmask_in[162]
  PIN w0_wmask_in[163]
    DIRECTION INPUT ;
    USE SIGNAL ;
    SHAPE ABUTMENT ;
    PORT
      LAYER M4 ;
      RECT 226.642 37.236 226.714 37.260 ;
    END
  END w0_wmask_in[163]
  PIN w0_wmask_in[164]
    DIRECTION INPUT ;
    USE SIGNAL ;
    SHAPE ABUTMENT ;
    PORT
      LAYER M4 ;
      RECT 226.642 38.292 226.714 38.316 ;
    END
  END w0_wmask_in[164]
  PIN w0_wmask_in[165]
    DIRECTION INPUT ;
    USE SIGNAL ;
    SHAPE ABUTMENT ;
    PORT
      LAYER M4 ;
      RECT 226.642 39.348 226.714 39.372 ;
    END
  END w0_wmask_in[165]
  PIN w0_wmask_in[166]
    DIRECTION INPUT ;
    USE SIGNAL ;
    SHAPE ABUTMENT ;
    PORT
      LAYER M4 ;
      RECT 226.642 40.404 226.714 40.428 ;
    END
  END w0_wmask_in[166]
  PIN w0_wmask_in[167]
    DIRECTION INPUT ;
    USE SIGNAL ;
    SHAPE ABUTMENT ;
    PORT
      LAYER M4 ;
      RECT 226.642 41.460 226.714 41.484 ;
    END
  END w0_wmask_in[167]
  PIN w0_wmask_in[168]
    DIRECTION INPUT ;
    USE SIGNAL ;
    SHAPE ABUTMENT ;
    PORT
      LAYER M4 ;
      RECT 226.642 42.516 226.714 42.540 ;
    END
  END w0_wmask_in[168]
  PIN w0_wmask_in[169]
    DIRECTION INPUT ;
    USE SIGNAL ;
    SHAPE ABUTMENT ;
    PORT
      LAYER M4 ;
      RECT 226.642 43.572 226.714 43.596 ;
    END
  END w0_wmask_in[169]
  PIN w0_wmask_in[170]
    DIRECTION INPUT ;
    USE SIGNAL ;
    SHAPE ABUTMENT ;
    PORT
      LAYER M4 ;
      RECT 226.642 44.628 226.714 44.652 ;
    END
  END w0_wmask_in[170]
  PIN w0_wmask_in[171]
    DIRECTION INPUT ;
    USE SIGNAL ;
    SHAPE ABUTMENT ;
    PORT
      LAYER M4 ;
      RECT 226.642 45.684 226.714 45.708 ;
    END
  END w0_wmask_in[171]
  PIN w0_wmask_in[172]
    DIRECTION INPUT ;
    USE SIGNAL ;
    SHAPE ABUTMENT ;
    PORT
      LAYER M4 ;
      RECT 226.642 46.740 226.714 46.764 ;
    END
  END w0_wmask_in[172]
  PIN w0_wmask_in[173]
    DIRECTION INPUT ;
    USE SIGNAL ;
    SHAPE ABUTMENT ;
    PORT
      LAYER M4 ;
      RECT 226.642 47.796 226.714 47.820 ;
    END
  END w0_wmask_in[173]
  PIN w0_wmask_in[174]
    DIRECTION INPUT ;
    USE SIGNAL ;
    SHAPE ABUTMENT ;
    PORT
      LAYER M4 ;
      RECT 226.642 48.852 226.714 48.876 ;
    END
  END w0_wmask_in[174]
  PIN w0_wmask_in[175]
    DIRECTION INPUT ;
    USE SIGNAL ;
    SHAPE ABUTMENT ;
    PORT
      LAYER M4 ;
      RECT 226.642 49.908 226.714 49.932 ;
    END
  END w0_wmask_in[175]
  PIN w0_wmask_in[176]
    DIRECTION INPUT ;
    USE SIGNAL ;
    SHAPE ABUTMENT ;
    PORT
      LAYER M4 ;
      RECT 226.642 50.964 226.714 50.988 ;
    END
  END w0_wmask_in[176]
  PIN w0_wmask_in[177]
    DIRECTION INPUT ;
    USE SIGNAL ;
    SHAPE ABUTMENT ;
    PORT
      LAYER M4 ;
      RECT 226.642 52.020 226.714 52.044 ;
    END
  END w0_wmask_in[177]
  PIN w0_wmask_in[178]
    DIRECTION INPUT ;
    USE SIGNAL ;
    SHAPE ABUTMENT ;
    PORT
      LAYER M4 ;
      RECT 226.642 53.076 226.714 53.100 ;
    END
  END w0_wmask_in[178]
  PIN w0_wmask_in[179]
    DIRECTION INPUT ;
    USE SIGNAL ;
    SHAPE ABUTMENT ;
    PORT
      LAYER M4 ;
      RECT 226.642 54.132 226.714 54.156 ;
    END
  END w0_wmask_in[179]
  PIN w0_wmask_in[180]
    DIRECTION INPUT ;
    USE SIGNAL ;
    SHAPE ABUTMENT ;
    PORT
      LAYER M4 ;
      RECT 226.642 55.188 226.714 55.212 ;
    END
  END w0_wmask_in[180]
  PIN w0_wmask_in[181]
    DIRECTION INPUT ;
    USE SIGNAL ;
    SHAPE ABUTMENT ;
    PORT
      LAYER M4 ;
      RECT 226.642 56.244 226.714 56.268 ;
    END
  END w0_wmask_in[181]
  PIN w0_wmask_in[182]
    DIRECTION INPUT ;
    USE SIGNAL ;
    SHAPE ABUTMENT ;
    PORT
      LAYER M4 ;
      RECT 226.642 57.300 226.714 57.324 ;
    END
  END w0_wmask_in[182]
  PIN w0_wmask_in[183]
    DIRECTION INPUT ;
    USE SIGNAL ;
    SHAPE ABUTMENT ;
    PORT
      LAYER M4 ;
      RECT 226.642 58.356 226.714 58.380 ;
    END
  END w0_wmask_in[183]
  PIN w0_wmask_in[184]
    DIRECTION INPUT ;
    USE SIGNAL ;
    SHAPE ABUTMENT ;
    PORT
      LAYER M4 ;
      RECT 226.642 59.412 226.714 59.436 ;
    END
  END w0_wmask_in[184]
  PIN w0_wmask_in[185]
    DIRECTION INPUT ;
    USE SIGNAL ;
    SHAPE ABUTMENT ;
    PORT
      LAYER M4 ;
      RECT 226.642 60.468 226.714 60.492 ;
    END
  END w0_wmask_in[185]
  PIN w0_wmask_in[186]
    DIRECTION INPUT ;
    USE SIGNAL ;
    SHAPE ABUTMENT ;
    PORT
      LAYER M4 ;
      RECT 226.642 61.524 226.714 61.548 ;
    END
  END w0_wmask_in[186]
  PIN w0_wmask_in[187]
    DIRECTION INPUT ;
    USE SIGNAL ;
    SHAPE ABUTMENT ;
    PORT
      LAYER M4 ;
      RECT 226.642 62.580 226.714 62.604 ;
    END
  END w0_wmask_in[187]
  PIN w0_wmask_in[188]
    DIRECTION INPUT ;
    USE SIGNAL ;
    SHAPE ABUTMENT ;
    PORT
      LAYER M4 ;
      RECT 226.642 63.636 226.714 63.660 ;
    END
  END w0_wmask_in[188]
  PIN w0_wmask_in[189]
    DIRECTION INPUT ;
    USE SIGNAL ;
    SHAPE ABUTMENT ;
    PORT
      LAYER M4 ;
      RECT 226.642 64.692 226.714 64.716 ;
    END
  END w0_wmask_in[189]
  PIN w0_wmask_in[190]
    DIRECTION INPUT ;
    USE SIGNAL ;
    SHAPE ABUTMENT ;
    PORT
      LAYER M4 ;
      RECT 226.642 65.748 226.714 65.772 ;
    END
  END w0_wmask_in[190]
  PIN w0_wmask_in[191]
    DIRECTION INPUT ;
    USE SIGNAL ;
    SHAPE ABUTMENT ;
    PORT
      LAYER M4 ;
      RECT 226.642 66.804 226.714 66.828 ;
    END
  END w0_wmask_in[191]
  PIN w0_wmask_in[192]
    DIRECTION INPUT ;
    USE SIGNAL ;
    SHAPE ABUTMENT ;
    PORT
      LAYER M4 ;
      RECT 226.642 67.860 226.714 67.884 ;
    END
  END w0_wmask_in[192]
  PIN w0_wmask_in[193]
    DIRECTION INPUT ;
    USE SIGNAL ;
    SHAPE ABUTMENT ;
    PORT
      LAYER M4 ;
      RECT 226.642 68.916 226.714 68.940 ;
    END
  END w0_wmask_in[193]
  PIN w0_wmask_in[194]
    DIRECTION INPUT ;
    USE SIGNAL ;
    SHAPE ABUTMENT ;
    PORT
      LAYER M4 ;
      RECT 226.642 69.972 226.714 69.996 ;
    END
  END w0_wmask_in[194]
  PIN w0_wmask_in[195]
    DIRECTION INPUT ;
    USE SIGNAL ;
    SHAPE ABUTMENT ;
    PORT
      LAYER M4 ;
      RECT 226.642 71.028 226.714 71.052 ;
    END
  END w0_wmask_in[195]
  PIN w0_wmask_in[196]
    DIRECTION INPUT ;
    USE SIGNAL ;
    SHAPE ABUTMENT ;
    PORT
      LAYER M4 ;
      RECT 226.642 72.084 226.714 72.108 ;
    END
  END w0_wmask_in[196]
  PIN w0_wmask_in[197]
    DIRECTION INPUT ;
    USE SIGNAL ;
    SHAPE ABUTMENT ;
    PORT
      LAYER M4 ;
      RECT 226.642 73.140 226.714 73.164 ;
    END
  END w0_wmask_in[197]
  PIN w0_wmask_in[198]
    DIRECTION INPUT ;
    USE SIGNAL ;
    SHAPE ABUTMENT ;
    PORT
      LAYER M4 ;
      RECT 226.642 74.196 226.714 74.220 ;
    END
  END w0_wmask_in[198]
  PIN w0_wmask_in[199]
    DIRECTION INPUT ;
    USE SIGNAL ;
    SHAPE ABUTMENT ;
    PORT
      LAYER M4 ;
      RECT 226.642 75.252 226.714 75.276 ;
    END
  END w0_wmask_in[199]
  PIN w0_wmask_in[200]
    DIRECTION INPUT ;
    USE SIGNAL ;
    SHAPE ABUTMENT ;
    PORT
      LAYER M4 ;
      RECT 226.642 76.308 226.714 76.332 ;
    END
  END w0_wmask_in[200]
  PIN w0_wmask_in[201]
    DIRECTION INPUT ;
    USE SIGNAL ;
    SHAPE ABUTMENT ;
    PORT
      LAYER M4 ;
      RECT 226.642 77.364 226.714 77.388 ;
    END
  END w0_wmask_in[201]
  PIN w0_wmask_in[202]
    DIRECTION INPUT ;
    USE SIGNAL ;
    SHAPE ABUTMENT ;
    PORT
      LAYER M4 ;
      RECT 226.642 78.420 226.714 78.444 ;
    END
  END w0_wmask_in[202]
  PIN w0_wmask_in[203]
    DIRECTION INPUT ;
    USE SIGNAL ;
    SHAPE ABUTMENT ;
    PORT
      LAYER M4 ;
      RECT 226.642 79.476 226.714 79.500 ;
    END
  END w0_wmask_in[203]
  PIN w0_wmask_in[204]
    DIRECTION INPUT ;
    USE SIGNAL ;
    SHAPE ABUTMENT ;
    PORT
      LAYER M4 ;
      RECT 226.642 80.532 226.714 80.556 ;
    END
  END w0_wmask_in[204]
  PIN w0_wmask_in[205]
    DIRECTION INPUT ;
    USE SIGNAL ;
    SHAPE ABUTMENT ;
    PORT
      LAYER M4 ;
      RECT 226.642 81.588 226.714 81.612 ;
    END
  END w0_wmask_in[205]
  PIN w0_wmask_in[206]
    DIRECTION INPUT ;
    USE SIGNAL ;
    SHAPE ABUTMENT ;
    PORT
      LAYER M4 ;
      RECT 226.642 82.644 226.714 82.668 ;
    END
  END w0_wmask_in[206]
  PIN w0_wmask_in[207]
    DIRECTION INPUT ;
    USE SIGNAL ;
    SHAPE ABUTMENT ;
    PORT
      LAYER M4 ;
      RECT 226.642 83.700 226.714 83.724 ;
    END
  END w0_wmask_in[207]
  PIN w0_wmask_in[208]
    DIRECTION INPUT ;
    USE SIGNAL ;
    SHAPE ABUTMENT ;
    PORT
      LAYER M4 ;
      RECT 226.642 84.756 226.714 84.780 ;
    END
  END w0_wmask_in[208]
  PIN w0_wmask_in[209]
    DIRECTION INPUT ;
    USE SIGNAL ;
    SHAPE ABUTMENT ;
    PORT
      LAYER M4 ;
      RECT 226.642 85.812 226.714 85.836 ;
    END
  END w0_wmask_in[209]
  PIN w0_wmask_in[210]
    DIRECTION INPUT ;
    USE SIGNAL ;
    SHAPE ABUTMENT ;
    PORT
      LAYER M4 ;
      RECT 226.642 86.868 226.714 86.892 ;
    END
  END w0_wmask_in[210]
  PIN w0_wmask_in[211]
    DIRECTION INPUT ;
    USE SIGNAL ;
    SHAPE ABUTMENT ;
    PORT
      LAYER M4 ;
      RECT 226.642 87.924 226.714 87.948 ;
    END
  END w0_wmask_in[211]
  PIN w0_wmask_in[212]
    DIRECTION INPUT ;
    USE SIGNAL ;
    SHAPE ABUTMENT ;
    PORT
      LAYER M4 ;
      RECT 226.642 88.980 226.714 89.004 ;
    END
  END w0_wmask_in[212]
  PIN w0_wmask_in[213]
    DIRECTION INPUT ;
    USE SIGNAL ;
    SHAPE ABUTMENT ;
    PORT
      LAYER M4 ;
      RECT 226.642 90.036 226.714 90.060 ;
    END
  END w0_wmask_in[213]
  PIN w0_wmask_in[214]
    DIRECTION INPUT ;
    USE SIGNAL ;
    SHAPE ABUTMENT ;
    PORT
      LAYER M4 ;
      RECT 226.642 91.092 226.714 91.116 ;
    END
  END w0_wmask_in[214]
  PIN w0_wmask_in[215]
    DIRECTION INPUT ;
    USE SIGNAL ;
    SHAPE ABUTMENT ;
    PORT
      LAYER M4 ;
      RECT 226.642 92.148 226.714 92.172 ;
    END
  END w0_wmask_in[215]
  PIN w0_wmask_in[216]
    DIRECTION INPUT ;
    USE SIGNAL ;
    SHAPE ABUTMENT ;
    PORT
      LAYER M4 ;
      RECT 226.642 93.204 226.714 93.228 ;
    END
  END w0_wmask_in[216]
  PIN w0_wmask_in[217]
    DIRECTION INPUT ;
    USE SIGNAL ;
    SHAPE ABUTMENT ;
    PORT
      LAYER M4 ;
      RECT 226.642 94.260 226.714 94.284 ;
    END
  END w0_wmask_in[217]
  PIN w0_wmask_in[218]
    DIRECTION INPUT ;
    USE SIGNAL ;
    SHAPE ABUTMENT ;
    PORT
      LAYER M4 ;
      RECT 226.642 95.316 226.714 95.340 ;
    END
  END w0_wmask_in[218]
  PIN w0_wmask_in[219]
    DIRECTION INPUT ;
    USE SIGNAL ;
    SHAPE ABUTMENT ;
    PORT
      LAYER M4 ;
      RECT 226.642 96.372 226.714 96.396 ;
    END
  END w0_wmask_in[219]
  PIN w0_wmask_in[220]
    DIRECTION INPUT ;
    USE SIGNAL ;
    SHAPE ABUTMENT ;
    PORT
      LAYER M4 ;
      RECT 226.642 97.428 226.714 97.452 ;
    END
  END w0_wmask_in[220]
  PIN w0_wmask_in[221]
    DIRECTION INPUT ;
    USE SIGNAL ;
    SHAPE ABUTMENT ;
    PORT
      LAYER M4 ;
      RECT 226.642 98.484 226.714 98.508 ;
    END
  END w0_wmask_in[221]
  PIN w0_wmask_in[222]
    DIRECTION INPUT ;
    USE SIGNAL ;
    SHAPE ABUTMENT ;
    PORT
      LAYER M4 ;
      RECT 226.642 99.540 226.714 99.564 ;
    END
  END w0_wmask_in[222]
  PIN w0_wmask_in[223]
    DIRECTION INPUT ;
    USE SIGNAL ;
    SHAPE ABUTMENT ;
    PORT
      LAYER M4 ;
      RECT 226.642 100.596 226.714 100.620 ;
    END
  END w0_wmask_in[223]
  PIN w0_wmask_in[224]
    DIRECTION INPUT ;
    USE SIGNAL ;
    SHAPE ABUTMENT ;
    PORT
      LAYER M4 ;
      RECT 226.642 101.652 226.714 101.676 ;
    END
  END w0_wmask_in[224]
  PIN w0_wmask_in[225]
    DIRECTION INPUT ;
    USE SIGNAL ;
    SHAPE ABUTMENT ;
    PORT
      LAYER M4 ;
      RECT 226.642 102.708 226.714 102.732 ;
    END
  END w0_wmask_in[225]
  PIN w0_wmask_in[226]
    DIRECTION INPUT ;
    USE SIGNAL ;
    SHAPE ABUTMENT ;
    PORT
      LAYER M4 ;
      RECT 226.642 103.764 226.714 103.788 ;
    END
  END w0_wmask_in[226]
  PIN w0_wmask_in[227]
    DIRECTION INPUT ;
    USE SIGNAL ;
    SHAPE ABUTMENT ;
    PORT
      LAYER M4 ;
      RECT 226.642 104.820 226.714 104.844 ;
    END
  END w0_wmask_in[227]
  PIN w0_wmask_in[228]
    DIRECTION INPUT ;
    USE SIGNAL ;
    SHAPE ABUTMENT ;
    PORT
      LAYER M4 ;
      RECT 226.642 105.876 226.714 105.900 ;
    END
  END w0_wmask_in[228]
  PIN w0_wmask_in[229]
    DIRECTION INPUT ;
    USE SIGNAL ;
    SHAPE ABUTMENT ;
    PORT
      LAYER M4 ;
      RECT 226.642 106.932 226.714 106.956 ;
    END
  END w0_wmask_in[229]
  PIN w0_wmask_in[230]
    DIRECTION INPUT ;
    USE SIGNAL ;
    SHAPE ABUTMENT ;
    PORT
      LAYER M4 ;
      RECT 226.642 107.988 226.714 108.012 ;
    END
  END w0_wmask_in[230]
  PIN w0_wmask_in[231]
    DIRECTION INPUT ;
    USE SIGNAL ;
    SHAPE ABUTMENT ;
    PORT
      LAYER M4 ;
      RECT 226.642 109.044 226.714 109.068 ;
    END
  END w0_wmask_in[231]
  PIN w0_wmask_in[232]
    DIRECTION INPUT ;
    USE SIGNAL ;
    SHAPE ABUTMENT ;
    PORT
      LAYER M4 ;
      RECT 226.642 110.100 226.714 110.124 ;
    END
  END w0_wmask_in[232]
  PIN w0_wmask_in[233]
    DIRECTION INPUT ;
    USE SIGNAL ;
    SHAPE ABUTMENT ;
    PORT
      LAYER M4 ;
      RECT 226.642 111.156 226.714 111.180 ;
    END
  END w0_wmask_in[233]
  PIN w0_wmask_in[234]
    DIRECTION INPUT ;
    USE SIGNAL ;
    SHAPE ABUTMENT ;
    PORT
      LAYER M4 ;
      RECT 226.642 112.212 226.714 112.236 ;
    END
  END w0_wmask_in[234]
  PIN w0_wmask_in[235]
    DIRECTION INPUT ;
    USE SIGNAL ;
    SHAPE ABUTMENT ;
    PORT
      LAYER M4 ;
      RECT 226.642 113.268 226.714 113.292 ;
    END
  END w0_wmask_in[235]
  PIN w0_wmask_in[236]
    DIRECTION INPUT ;
    USE SIGNAL ;
    SHAPE ABUTMENT ;
    PORT
      LAYER M4 ;
      RECT 226.642 114.324 226.714 114.348 ;
    END
  END w0_wmask_in[236]
  PIN w0_wmask_in[237]
    DIRECTION INPUT ;
    USE SIGNAL ;
    SHAPE ABUTMENT ;
    PORT
      LAYER M4 ;
      RECT 226.642 115.380 226.714 115.404 ;
    END
  END w0_wmask_in[237]
  PIN w0_wmask_in[238]
    DIRECTION INPUT ;
    USE SIGNAL ;
    SHAPE ABUTMENT ;
    PORT
      LAYER M4 ;
      RECT 226.642 116.436 226.714 116.460 ;
    END
  END w0_wmask_in[238]
  PIN w0_wmask_in[239]
    DIRECTION INPUT ;
    USE SIGNAL ;
    SHAPE ABUTMENT ;
    PORT
      LAYER M4 ;
      RECT 226.642 117.492 226.714 117.516 ;
    END
  END w0_wmask_in[239]
  PIN w0_wmask_in[240]
    DIRECTION INPUT ;
    USE SIGNAL ;
    SHAPE ABUTMENT ;
    PORT
      LAYER M4 ;
      RECT 226.642 118.548 226.714 118.572 ;
    END
  END w0_wmask_in[240]
  PIN w0_wmask_in[241]
    DIRECTION INPUT ;
    USE SIGNAL ;
    SHAPE ABUTMENT ;
    PORT
      LAYER M4 ;
      RECT 226.642 119.604 226.714 119.628 ;
    END
  END w0_wmask_in[241]
  PIN w0_wmask_in[242]
    DIRECTION INPUT ;
    USE SIGNAL ;
    SHAPE ABUTMENT ;
    PORT
      LAYER M4 ;
      RECT 226.642 120.660 226.714 120.684 ;
    END
  END w0_wmask_in[242]
  PIN w0_wmask_in[243]
    DIRECTION INPUT ;
    USE SIGNAL ;
    SHAPE ABUTMENT ;
    PORT
      LAYER M4 ;
      RECT 226.642 121.716 226.714 121.740 ;
    END
  END w0_wmask_in[243]
  PIN w0_wmask_in[244]
    DIRECTION INPUT ;
    USE SIGNAL ;
    SHAPE ABUTMENT ;
    PORT
      LAYER M4 ;
      RECT 226.642 122.772 226.714 122.796 ;
    END
  END w0_wmask_in[244]
  PIN w0_wmask_in[245]
    DIRECTION INPUT ;
    USE SIGNAL ;
    SHAPE ABUTMENT ;
    PORT
      LAYER M4 ;
      RECT 226.642 123.828 226.714 123.852 ;
    END
  END w0_wmask_in[245]
  PIN w0_wmask_in[246]
    DIRECTION INPUT ;
    USE SIGNAL ;
    SHAPE ABUTMENT ;
    PORT
      LAYER M4 ;
      RECT 226.642 124.884 226.714 124.908 ;
    END
  END w0_wmask_in[246]
  PIN w0_wmask_in[247]
    DIRECTION INPUT ;
    USE SIGNAL ;
    SHAPE ABUTMENT ;
    PORT
      LAYER M4 ;
      RECT 226.642 125.940 226.714 125.964 ;
    END
  END w0_wmask_in[247]
  PIN w0_wmask_in[248]
    DIRECTION INPUT ;
    USE SIGNAL ;
    SHAPE ABUTMENT ;
    PORT
      LAYER M4 ;
      RECT 226.642 126.996 226.714 127.020 ;
    END
  END w0_wmask_in[248]
  PIN w0_wmask_in[249]
    DIRECTION INPUT ;
    USE SIGNAL ;
    SHAPE ABUTMENT ;
    PORT
      LAYER M4 ;
      RECT 226.642 128.052 226.714 128.076 ;
    END
  END w0_wmask_in[249]
  PIN w0_wmask_in[250]
    DIRECTION INPUT ;
    USE SIGNAL ;
    SHAPE ABUTMENT ;
    PORT
      LAYER M4 ;
      RECT 226.642 129.108 226.714 129.132 ;
    END
  END w0_wmask_in[250]
  PIN w0_wmask_in[251]
    DIRECTION INPUT ;
    USE SIGNAL ;
    SHAPE ABUTMENT ;
    PORT
      LAYER M4 ;
      RECT 226.642 130.164 226.714 130.188 ;
    END
  END w0_wmask_in[251]
  PIN w0_wmask_in[252]
    DIRECTION INPUT ;
    USE SIGNAL ;
    SHAPE ABUTMENT ;
    PORT
      LAYER M4 ;
      RECT 226.642 131.220 226.714 131.244 ;
    END
  END w0_wmask_in[252]
  PIN w0_wmask_in[253]
    DIRECTION INPUT ;
    USE SIGNAL ;
    SHAPE ABUTMENT ;
    PORT
      LAYER M4 ;
      RECT 226.642 132.276 226.714 132.300 ;
    END
  END w0_wmask_in[253]
  PIN w0_wmask_in[254]
    DIRECTION INPUT ;
    USE SIGNAL ;
    SHAPE ABUTMENT ;
    PORT
      LAYER M4 ;
      RECT 226.642 133.332 226.714 133.356 ;
    END
  END w0_wmask_in[254]
  PIN w0_wmask_in[255]
    DIRECTION INPUT ;
    USE SIGNAL ;
    SHAPE ABUTMENT ;
    PORT
      LAYER M4 ;
      RECT 226.642 134.388 226.714 134.412 ;
    END
  END w0_wmask_in[255]
  PIN w0_wmask_in[256]
    DIRECTION INPUT ;
    USE SIGNAL ;
    SHAPE ABUTMENT ;
    PORT
      LAYER M3 ;
      RECT 0.207 283.338 0.225 283.392 ;
    END
  END w0_wmask_in[256]
  PIN w0_wmask_in[257]
    DIRECTION INPUT ;
    USE SIGNAL ;
    SHAPE ABUTMENT ;
    PORT
      LAYER M3 ;
      RECT 0.639 283.338 0.657 283.392 ;
    END
  END w0_wmask_in[257]
  PIN w0_wmask_in[258]
    DIRECTION INPUT ;
    USE SIGNAL ;
    SHAPE ABUTMENT ;
    PORT
      LAYER M3 ;
      RECT 1.071 283.338 1.089 283.392 ;
    END
  END w0_wmask_in[258]
  PIN w0_wmask_in[259]
    DIRECTION INPUT ;
    USE SIGNAL ;
    SHAPE ABUTMENT ;
    PORT
      LAYER M3 ;
      RECT 1.503 283.338 1.521 283.392 ;
    END
  END w0_wmask_in[259]
  PIN w0_wmask_in[260]
    DIRECTION INPUT ;
    USE SIGNAL ;
    SHAPE ABUTMENT ;
    PORT
      LAYER M3 ;
      RECT 1.935 283.338 1.953 283.392 ;
    END
  END w0_wmask_in[260]
  PIN w0_wmask_in[261]
    DIRECTION INPUT ;
    USE SIGNAL ;
    SHAPE ABUTMENT ;
    PORT
      LAYER M3 ;
      RECT 2.367 283.338 2.385 283.392 ;
    END
  END w0_wmask_in[261]
  PIN w0_wmask_in[262]
    DIRECTION INPUT ;
    USE SIGNAL ;
    SHAPE ABUTMENT ;
    PORT
      LAYER M3 ;
      RECT 2.799 283.338 2.817 283.392 ;
    END
  END w0_wmask_in[262]
  PIN w0_wmask_in[263]
    DIRECTION INPUT ;
    USE SIGNAL ;
    SHAPE ABUTMENT ;
    PORT
      LAYER M3 ;
      RECT 3.231 283.338 3.249 283.392 ;
    END
  END w0_wmask_in[263]
  PIN w0_wmask_in[264]
    DIRECTION INPUT ;
    USE SIGNAL ;
    SHAPE ABUTMENT ;
    PORT
      LAYER M3 ;
      RECT 3.663 283.338 3.681 283.392 ;
    END
  END w0_wmask_in[264]
  PIN w0_wmask_in[265]
    DIRECTION INPUT ;
    USE SIGNAL ;
    SHAPE ABUTMENT ;
    PORT
      LAYER M3 ;
      RECT 4.095 283.338 4.113 283.392 ;
    END
  END w0_wmask_in[265]
  PIN w0_wmask_in[266]
    DIRECTION INPUT ;
    USE SIGNAL ;
    SHAPE ABUTMENT ;
    PORT
      LAYER M3 ;
      RECT 4.527 283.338 4.545 283.392 ;
    END
  END w0_wmask_in[266]
  PIN w0_wmask_in[267]
    DIRECTION INPUT ;
    USE SIGNAL ;
    SHAPE ABUTMENT ;
    PORT
      LAYER M3 ;
      RECT 4.959 283.338 4.977 283.392 ;
    END
  END w0_wmask_in[267]
  PIN w0_wmask_in[268]
    DIRECTION INPUT ;
    USE SIGNAL ;
    SHAPE ABUTMENT ;
    PORT
      LAYER M3 ;
      RECT 5.391 283.338 5.409 283.392 ;
    END
  END w0_wmask_in[268]
  PIN w0_wmask_in[269]
    DIRECTION INPUT ;
    USE SIGNAL ;
    SHAPE ABUTMENT ;
    PORT
      LAYER M3 ;
      RECT 5.823 283.338 5.841 283.392 ;
    END
  END w0_wmask_in[269]
  PIN w0_wmask_in[270]
    DIRECTION INPUT ;
    USE SIGNAL ;
    SHAPE ABUTMENT ;
    PORT
      LAYER M3 ;
      RECT 6.255 283.338 6.273 283.392 ;
    END
  END w0_wmask_in[270]
  PIN w0_wmask_in[271]
    DIRECTION INPUT ;
    USE SIGNAL ;
    SHAPE ABUTMENT ;
    PORT
      LAYER M3 ;
      RECT 6.687 283.338 6.705 283.392 ;
    END
  END w0_wmask_in[271]
  PIN w0_wmask_in[272]
    DIRECTION INPUT ;
    USE SIGNAL ;
    SHAPE ABUTMENT ;
    PORT
      LAYER M3 ;
      RECT 7.119 283.338 7.137 283.392 ;
    END
  END w0_wmask_in[272]
  PIN w0_wmask_in[273]
    DIRECTION INPUT ;
    USE SIGNAL ;
    SHAPE ABUTMENT ;
    PORT
      LAYER M3 ;
      RECT 7.551 283.338 7.569 283.392 ;
    END
  END w0_wmask_in[273]
  PIN w0_wmask_in[274]
    DIRECTION INPUT ;
    USE SIGNAL ;
    SHAPE ABUTMENT ;
    PORT
      LAYER M3 ;
      RECT 7.983 283.338 8.001 283.392 ;
    END
  END w0_wmask_in[274]
  PIN w0_wmask_in[275]
    DIRECTION INPUT ;
    USE SIGNAL ;
    SHAPE ABUTMENT ;
    PORT
      LAYER M3 ;
      RECT 8.415 283.338 8.433 283.392 ;
    END
  END w0_wmask_in[275]
  PIN w0_wmask_in[276]
    DIRECTION INPUT ;
    USE SIGNAL ;
    SHAPE ABUTMENT ;
    PORT
      LAYER M3 ;
      RECT 8.847 283.338 8.865 283.392 ;
    END
  END w0_wmask_in[276]
  PIN w0_wmask_in[277]
    DIRECTION INPUT ;
    USE SIGNAL ;
    SHAPE ABUTMENT ;
    PORT
      LAYER M3 ;
      RECT 9.279 283.338 9.297 283.392 ;
    END
  END w0_wmask_in[277]
  PIN w0_wmask_in[278]
    DIRECTION INPUT ;
    USE SIGNAL ;
    SHAPE ABUTMENT ;
    PORT
      LAYER M3 ;
      RECT 9.711 283.338 9.729 283.392 ;
    END
  END w0_wmask_in[278]
  PIN w0_wmask_in[279]
    DIRECTION INPUT ;
    USE SIGNAL ;
    SHAPE ABUTMENT ;
    PORT
      LAYER M3 ;
      RECT 10.143 283.338 10.161 283.392 ;
    END
  END w0_wmask_in[279]
  PIN w0_wmask_in[280]
    DIRECTION INPUT ;
    USE SIGNAL ;
    SHAPE ABUTMENT ;
    PORT
      LAYER M3 ;
      RECT 10.575 283.338 10.593 283.392 ;
    END
  END w0_wmask_in[280]
  PIN w0_wmask_in[281]
    DIRECTION INPUT ;
    USE SIGNAL ;
    SHAPE ABUTMENT ;
    PORT
      LAYER M3 ;
      RECT 11.007 283.338 11.025 283.392 ;
    END
  END w0_wmask_in[281]
  PIN w0_wmask_in[282]
    DIRECTION INPUT ;
    USE SIGNAL ;
    SHAPE ABUTMENT ;
    PORT
      LAYER M3 ;
      RECT 11.439 283.338 11.457 283.392 ;
    END
  END w0_wmask_in[282]
  PIN w0_wmask_in[283]
    DIRECTION INPUT ;
    USE SIGNAL ;
    SHAPE ABUTMENT ;
    PORT
      LAYER M3 ;
      RECT 11.871 283.338 11.889 283.392 ;
    END
  END w0_wmask_in[283]
  PIN w0_wmask_in[284]
    DIRECTION INPUT ;
    USE SIGNAL ;
    SHAPE ABUTMENT ;
    PORT
      LAYER M3 ;
      RECT 12.303 283.338 12.321 283.392 ;
    END
  END w0_wmask_in[284]
  PIN w0_wmask_in[285]
    DIRECTION INPUT ;
    USE SIGNAL ;
    SHAPE ABUTMENT ;
    PORT
      LAYER M3 ;
      RECT 12.735 283.338 12.753 283.392 ;
    END
  END w0_wmask_in[285]
  PIN w0_wmask_in[286]
    DIRECTION INPUT ;
    USE SIGNAL ;
    SHAPE ABUTMENT ;
    PORT
      LAYER M3 ;
      RECT 13.167 283.338 13.185 283.392 ;
    END
  END w0_wmask_in[286]
  PIN w0_wmask_in[287]
    DIRECTION INPUT ;
    USE SIGNAL ;
    SHAPE ABUTMENT ;
    PORT
      LAYER M3 ;
      RECT 13.599 283.338 13.617 283.392 ;
    END
  END w0_wmask_in[287]
  PIN w0_wmask_in[288]
    DIRECTION INPUT ;
    USE SIGNAL ;
    SHAPE ABUTMENT ;
    PORT
      LAYER M3 ;
      RECT 14.031 283.338 14.049 283.392 ;
    END
  END w0_wmask_in[288]
  PIN w0_wmask_in[289]
    DIRECTION INPUT ;
    USE SIGNAL ;
    SHAPE ABUTMENT ;
    PORT
      LAYER M3 ;
      RECT 14.463 283.338 14.481 283.392 ;
    END
  END w0_wmask_in[289]
  PIN w0_wmask_in[290]
    DIRECTION INPUT ;
    USE SIGNAL ;
    SHAPE ABUTMENT ;
    PORT
      LAYER M3 ;
      RECT 14.895 283.338 14.913 283.392 ;
    END
  END w0_wmask_in[290]
  PIN w0_wmask_in[291]
    DIRECTION INPUT ;
    USE SIGNAL ;
    SHAPE ABUTMENT ;
    PORT
      LAYER M3 ;
      RECT 15.327 283.338 15.345 283.392 ;
    END
  END w0_wmask_in[291]
  PIN w0_wmask_in[292]
    DIRECTION INPUT ;
    USE SIGNAL ;
    SHAPE ABUTMENT ;
    PORT
      LAYER M3 ;
      RECT 15.759 283.338 15.777 283.392 ;
    END
  END w0_wmask_in[292]
  PIN w0_wmask_in[293]
    DIRECTION INPUT ;
    USE SIGNAL ;
    SHAPE ABUTMENT ;
    PORT
      LAYER M3 ;
      RECT 16.191 283.338 16.209 283.392 ;
    END
  END w0_wmask_in[293]
  PIN w0_wmask_in[294]
    DIRECTION INPUT ;
    USE SIGNAL ;
    SHAPE ABUTMENT ;
    PORT
      LAYER M3 ;
      RECT 16.623 283.338 16.641 283.392 ;
    END
  END w0_wmask_in[294]
  PIN w0_wmask_in[295]
    DIRECTION INPUT ;
    USE SIGNAL ;
    SHAPE ABUTMENT ;
    PORT
      LAYER M3 ;
      RECT 17.055 283.338 17.073 283.392 ;
    END
  END w0_wmask_in[295]
  PIN w0_wmask_in[296]
    DIRECTION INPUT ;
    USE SIGNAL ;
    SHAPE ABUTMENT ;
    PORT
      LAYER M3 ;
      RECT 17.487 283.338 17.505 283.392 ;
    END
  END w0_wmask_in[296]
  PIN w0_wmask_in[297]
    DIRECTION INPUT ;
    USE SIGNAL ;
    SHAPE ABUTMENT ;
    PORT
      LAYER M3 ;
      RECT 17.919 283.338 17.937 283.392 ;
    END
  END w0_wmask_in[297]
  PIN w0_wmask_in[298]
    DIRECTION INPUT ;
    USE SIGNAL ;
    SHAPE ABUTMENT ;
    PORT
      LAYER M3 ;
      RECT 18.351 283.338 18.369 283.392 ;
    END
  END w0_wmask_in[298]
  PIN w0_wmask_in[299]
    DIRECTION INPUT ;
    USE SIGNAL ;
    SHAPE ABUTMENT ;
    PORT
      LAYER M3 ;
      RECT 18.783 283.338 18.801 283.392 ;
    END
  END w0_wmask_in[299]
  PIN w0_wmask_in[300]
    DIRECTION INPUT ;
    USE SIGNAL ;
    SHAPE ABUTMENT ;
    PORT
      LAYER M3 ;
      RECT 19.215 283.338 19.233 283.392 ;
    END
  END w0_wmask_in[300]
  PIN w0_wmask_in[301]
    DIRECTION INPUT ;
    USE SIGNAL ;
    SHAPE ABUTMENT ;
    PORT
      LAYER M3 ;
      RECT 19.647 283.338 19.665 283.392 ;
    END
  END w0_wmask_in[301]
  PIN w0_wmask_in[302]
    DIRECTION INPUT ;
    USE SIGNAL ;
    SHAPE ABUTMENT ;
    PORT
      LAYER M3 ;
      RECT 20.079 283.338 20.097 283.392 ;
    END
  END w0_wmask_in[302]
  PIN w0_wmask_in[303]
    DIRECTION INPUT ;
    USE SIGNAL ;
    SHAPE ABUTMENT ;
    PORT
      LAYER M3 ;
      RECT 20.511 283.338 20.529 283.392 ;
    END
  END w0_wmask_in[303]
  PIN w0_wmask_in[304]
    DIRECTION INPUT ;
    USE SIGNAL ;
    SHAPE ABUTMENT ;
    PORT
      LAYER M3 ;
      RECT 20.943 283.338 20.961 283.392 ;
    END
  END w0_wmask_in[304]
  PIN w0_wmask_in[305]
    DIRECTION INPUT ;
    USE SIGNAL ;
    SHAPE ABUTMENT ;
    PORT
      LAYER M3 ;
      RECT 21.375 283.338 21.393 283.392 ;
    END
  END w0_wmask_in[305]
  PIN w0_wmask_in[306]
    DIRECTION INPUT ;
    USE SIGNAL ;
    SHAPE ABUTMENT ;
    PORT
      LAYER M3 ;
      RECT 21.807 283.338 21.825 283.392 ;
    END
  END w0_wmask_in[306]
  PIN w0_wmask_in[307]
    DIRECTION INPUT ;
    USE SIGNAL ;
    SHAPE ABUTMENT ;
    PORT
      LAYER M3 ;
      RECT 22.239 283.338 22.257 283.392 ;
    END
  END w0_wmask_in[307]
  PIN w0_wmask_in[308]
    DIRECTION INPUT ;
    USE SIGNAL ;
    SHAPE ABUTMENT ;
    PORT
      LAYER M3 ;
      RECT 22.671 283.338 22.689 283.392 ;
    END
  END w0_wmask_in[308]
  PIN w0_wmask_in[309]
    DIRECTION INPUT ;
    USE SIGNAL ;
    SHAPE ABUTMENT ;
    PORT
      LAYER M3 ;
      RECT 23.103 283.338 23.121 283.392 ;
    END
  END w0_wmask_in[309]
  PIN w0_wmask_in[310]
    DIRECTION INPUT ;
    USE SIGNAL ;
    SHAPE ABUTMENT ;
    PORT
      LAYER M3 ;
      RECT 23.535 283.338 23.553 283.392 ;
    END
  END w0_wmask_in[310]
  PIN w0_wmask_in[311]
    DIRECTION INPUT ;
    USE SIGNAL ;
    SHAPE ABUTMENT ;
    PORT
      LAYER M3 ;
      RECT 23.967 283.338 23.985 283.392 ;
    END
  END w0_wmask_in[311]
  PIN w0_wmask_in[312]
    DIRECTION INPUT ;
    USE SIGNAL ;
    SHAPE ABUTMENT ;
    PORT
      LAYER M3 ;
      RECT 24.399 283.338 24.417 283.392 ;
    END
  END w0_wmask_in[312]
  PIN w0_wmask_in[313]
    DIRECTION INPUT ;
    USE SIGNAL ;
    SHAPE ABUTMENT ;
    PORT
      LAYER M3 ;
      RECT 24.831 283.338 24.849 283.392 ;
    END
  END w0_wmask_in[313]
  PIN w0_wmask_in[314]
    DIRECTION INPUT ;
    USE SIGNAL ;
    SHAPE ABUTMENT ;
    PORT
      LAYER M3 ;
      RECT 25.263 283.338 25.281 283.392 ;
    END
  END w0_wmask_in[314]
  PIN w0_wmask_in[315]
    DIRECTION INPUT ;
    USE SIGNAL ;
    SHAPE ABUTMENT ;
    PORT
      LAYER M3 ;
      RECT 25.695 283.338 25.713 283.392 ;
    END
  END w0_wmask_in[315]
  PIN w0_wmask_in[316]
    DIRECTION INPUT ;
    USE SIGNAL ;
    SHAPE ABUTMENT ;
    PORT
      LAYER M3 ;
      RECT 26.127 283.338 26.145 283.392 ;
    END
  END w0_wmask_in[316]
  PIN w0_wmask_in[317]
    DIRECTION INPUT ;
    USE SIGNAL ;
    SHAPE ABUTMENT ;
    PORT
      LAYER M3 ;
      RECT 26.559 283.338 26.577 283.392 ;
    END
  END w0_wmask_in[317]
  PIN w0_wmask_in[318]
    DIRECTION INPUT ;
    USE SIGNAL ;
    SHAPE ABUTMENT ;
    PORT
      LAYER M3 ;
      RECT 26.991 283.338 27.009 283.392 ;
    END
  END w0_wmask_in[318]
  PIN w0_wmask_in[319]
    DIRECTION INPUT ;
    USE SIGNAL ;
    SHAPE ABUTMENT ;
    PORT
      LAYER M3 ;
      RECT 27.423 283.338 27.441 283.392 ;
    END
  END w0_wmask_in[319]
  PIN w0_wmask_in[320]
    DIRECTION INPUT ;
    USE SIGNAL ;
    SHAPE ABUTMENT ;
    PORT
      LAYER M3 ;
      RECT 27.855 283.338 27.873 283.392 ;
    END
  END w0_wmask_in[320]
  PIN w0_wmask_in[321]
    DIRECTION INPUT ;
    USE SIGNAL ;
    SHAPE ABUTMENT ;
    PORT
      LAYER M3 ;
      RECT 28.287 283.338 28.305 283.392 ;
    END
  END w0_wmask_in[321]
  PIN w0_wmask_in[322]
    DIRECTION INPUT ;
    USE SIGNAL ;
    SHAPE ABUTMENT ;
    PORT
      LAYER M3 ;
      RECT 28.719 283.338 28.737 283.392 ;
    END
  END w0_wmask_in[322]
  PIN w0_wmask_in[323]
    DIRECTION INPUT ;
    USE SIGNAL ;
    SHAPE ABUTMENT ;
    PORT
      LAYER M3 ;
      RECT 29.151 283.338 29.169 283.392 ;
    END
  END w0_wmask_in[323]
  PIN w0_wmask_in[324]
    DIRECTION INPUT ;
    USE SIGNAL ;
    SHAPE ABUTMENT ;
    PORT
      LAYER M3 ;
      RECT 29.583 283.338 29.601 283.392 ;
    END
  END w0_wmask_in[324]
  PIN w0_wmask_in[325]
    DIRECTION INPUT ;
    USE SIGNAL ;
    SHAPE ABUTMENT ;
    PORT
      LAYER M3 ;
      RECT 30.015 283.338 30.033 283.392 ;
    END
  END w0_wmask_in[325]
  PIN w0_wmask_in[326]
    DIRECTION INPUT ;
    USE SIGNAL ;
    SHAPE ABUTMENT ;
    PORT
      LAYER M3 ;
      RECT 30.447 283.338 30.465 283.392 ;
    END
  END w0_wmask_in[326]
  PIN w0_wmask_in[327]
    DIRECTION INPUT ;
    USE SIGNAL ;
    SHAPE ABUTMENT ;
    PORT
      LAYER M3 ;
      RECT 30.879 283.338 30.897 283.392 ;
    END
  END w0_wmask_in[327]
  PIN w0_wmask_in[328]
    DIRECTION INPUT ;
    USE SIGNAL ;
    SHAPE ABUTMENT ;
    PORT
      LAYER M3 ;
      RECT 31.311 283.338 31.329 283.392 ;
    END
  END w0_wmask_in[328]
  PIN w0_wmask_in[329]
    DIRECTION INPUT ;
    USE SIGNAL ;
    SHAPE ABUTMENT ;
    PORT
      LAYER M3 ;
      RECT 31.743 283.338 31.761 283.392 ;
    END
  END w0_wmask_in[329]
  PIN w0_wmask_in[330]
    DIRECTION INPUT ;
    USE SIGNAL ;
    SHAPE ABUTMENT ;
    PORT
      LAYER M3 ;
      RECT 32.175 283.338 32.193 283.392 ;
    END
  END w0_wmask_in[330]
  PIN w0_wmask_in[331]
    DIRECTION INPUT ;
    USE SIGNAL ;
    SHAPE ABUTMENT ;
    PORT
      LAYER M3 ;
      RECT 32.607 283.338 32.625 283.392 ;
    END
  END w0_wmask_in[331]
  PIN w0_wmask_in[332]
    DIRECTION INPUT ;
    USE SIGNAL ;
    SHAPE ABUTMENT ;
    PORT
      LAYER M3 ;
      RECT 33.039 283.338 33.057 283.392 ;
    END
  END w0_wmask_in[332]
  PIN w0_wmask_in[333]
    DIRECTION INPUT ;
    USE SIGNAL ;
    SHAPE ABUTMENT ;
    PORT
      LAYER M3 ;
      RECT 33.471 283.338 33.489 283.392 ;
    END
  END w0_wmask_in[333]
  PIN w0_wmask_in[334]
    DIRECTION INPUT ;
    USE SIGNAL ;
    SHAPE ABUTMENT ;
    PORT
      LAYER M3 ;
      RECT 33.903 283.338 33.921 283.392 ;
    END
  END w0_wmask_in[334]
  PIN w0_wmask_in[335]
    DIRECTION INPUT ;
    USE SIGNAL ;
    SHAPE ABUTMENT ;
    PORT
      LAYER M3 ;
      RECT 34.335 283.338 34.353 283.392 ;
    END
  END w0_wmask_in[335]
  PIN w0_wmask_in[336]
    DIRECTION INPUT ;
    USE SIGNAL ;
    SHAPE ABUTMENT ;
    PORT
      LAYER M3 ;
      RECT 34.767 283.338 34.785 283.392 ;
    END
  END w0_wmask_in[336]
  PIN w0_wmask_in[337]
    DIRECTION INPUT ;
    USE SIGNAL ;
    SHAPE ABUTMENT ;
    PORT
      LAYER M3 ;
      RECT 35.199 283.338 35.217 283.392 ;
    END
  END w0_wmask_in[337]
  PIN w0_wmask_in[338]
    DIRECTION INPUT ;
    USE SIGNAL ;
    SHAPE ABUTMENT ;
    PORT
      LAYER M3 ;
      RECT 35.631 283.338 35.649 283.392 ;
    END
  END w0_wmask_in[338]
  PIN w0_wmask_in[339]
    DIRECTION INPUT ;
    USE SIGNAL ;
    SHAPE ABUTMENT ;
    PORT
      LAYER M3 ;
      RECT 36.063 283.338 36.081 283.392 ;
    END
  END w0_wmask_in[339]
  PIN w0_wmask_in[340]
    DIRECTION INPUT ;
    USE SIGNAL ;
    SHAPE ABUTMENT ;
    PORT
      LAYER M3 ;
      RECT 36.495 283.338 36.513 283.392 ;
    END
  END w0_wmask_in[340]
  PIN w0_wmask_in[341]
    DIRECTION INPUT ;
    USE SIGNAL ;
    SHAPE ABUTMENT ;
    PORT
      LAYER M3 ;
      RECT 36.927 283.338 36.945 283.392 ;
    END
  END w0_wmask_in[341]
  PIN w0_wmask_in[342]
    DIRECTION INPUT ;
    USE SIGNAL ;
    SHAPE ABUTMENT ;
    PORT
      LAYER M3 ;
      RECT 37.359 283.338 37.377 283.392 ;
    END
  END w0_wmask_in[342]
  PIN w0_wmask_in[343]
    DIRECTION INPUT ;
    USE SIGNAL ;
    SHAPE ABUTMENT ;
    PORT
      LAYER M3 ;
      RECT 37.791 283.338 37.809 283.392 ;
    END
  END w0_wmask_in[343]
  PIN w0_wmask_in[344]
    DIRECTION INPUT ;
    USE SIGNAL ;
    SHAPE ABUTMENT ;
    PORT
      LAYER M3 ;
      RECT 38.223 283.338 38.241 283.392 ;
    END
  END w0_wmask_in[344]
  PIN w0_wmask_in[345]
    DIRECTION INPUT ;
    USE SIGNAL ;
    SHAPE ABUTMENT ;
    PORT
      LAYER M3 ;
      RECT 38.655 283.338 38.673 283.392 ;
    END
  END w0_wmask_in[345]
  PIN w0_wmask_in[346]
    DIRECTION INPUT ;
    USE SIGNAL ;
    SHAPE ABUTMENT ;
    PORT
      LAYER M3 ;
      RECT 39.087 283.338 39.105 283.392 ;
    END
  END w0_wmask_in[346]
  PIN w0_wmask_in[347]
    DIRECTION INPUT ;
    USE SIGNAL ;
    SHAPE ABUTMENT ;
    PORT
      LAYER M3 ;
      RECT 39.519 283.338 39.537 283.392 ;
    END
  END w0_wmask_in[347]
  PIN w0_wmask_in[348]
    DIRECTION INPUT ;
    USE SIGNAL ;
    SHAPE ABUTMENT ;
    PORT
      LAYER M3 ;
      RECT 39.951 283.338 39.969 283.392 ;
    END
  END w0_wmask_in[348]
  PIN w0_wmask_in[349]
    DIRECTION INPUT ;
    USE SIGNAL ;
    SHAPE ABUTMENT ;
    PORT
      LAYER M3 ;
      RECT 40.383 283.338 40.401 283.392 ;
    END
  END w0_wmask_in[349]
  PIN w0_wmask_in[350]
    DIRECTION INPUT ;
    USE SIGNAL ;
    SHAPE ABUTMENT ;
    PORT
      LAYER M3 ;
      RECT 40.815 283.338 40.833 283.392 ;
    END
  END w0_wmask_in[350]
  PIN w0_wmask_in[351]
    DIRECTION INPUT ;
    USE SIGNAL ;
    SHAPE ABUTMENT ;
    PORT
      LAYER M3 ;
      RECT 41.247 283.338 41.265 283.392 ;
    END
  END w0_wmask_in[351]
  PIN w0_wmask_in[352]
    DIRECTION INPUT ;
    USE SIGNAL ;
    SHAPE ABUTMENT ;
    PORT
      LAYER M3 ;
      RECT 41.679 283.338 41.697 283.392 ;
    END
  END w0_wmask_in[352]
  PIN w0_wmask_in[353]
    DIRECTION INPUT ;
    USE SIGNAL ;
    SHAPE ABUTMENT ;
    PORT
      LAYER M3 ;
      RECT 42.111 283.338 42.129 283.392 ;
    END
  END w0_wmask_in[353]
  PIN w0_wmask_in[354]
    DIRECTION INPUT ;
    USE SIGNAL ;
    SHAPE ABUTMENT ;
    PORT
      LAYER M3 ;
      RECT 42.543 283.338 42.561 283.392 ;
    END
  END w0_wmask_in[354]
  PIN w0_wmask_in[355]
    DIRECTION INPUT ;
    USE SIGNAL ;
    SHAPE ABUTMENT ;
    PORT
      LAYER M3 ;
      RECT 42.975 283.338 42.993 283.392 ;
    END
  END w0_wmask_in[355]
  PIN w0_wmask_in[356]
    DIRECTION INPUT ;
    USE SIGNAL ;
    SHAPE ABUTMENT ;
    PORT
      LAYER M3 ;
      RECT 43.407 283.338 43.425 283.392 ;
    END
  END w0_wmask_in[356]
  PIN w0_wmask_in[357]
    DIRECTION INPUT ;
    USE SIGNAL ;
    SHAPE ABUTMENT ;
    PORT
      LAYER M3 ;
      RECT 43.839 283.338 43.857 283.392 ;
    END
  END w0_wmask_in[357]
  PIN w0_wmask_in[358]
    DIRECTION INPUT ;
    USE SIGNAL ;
    SHAPE ABUTMENT ;
    PORT
      LAYER M3 ;
      RECT 44.271 283.338 44.289 283.392 ;
    END
  END w0_wmask_in[358]
  PIN w0_wmask_in[359]
    DIRECTION INPUT ;
    USE SIGNAL ;
    SHAPE ABUTMENT ;
    PORT
      LAYER M3 ;
      RECT 44.703 283.338 44.721 283.392 ;
    END
  END w0_wmask_in[359]
  PIN w0_wmask_in[360]
    DIRECTION INPUT ;
    USE SIGNAL ;
    SHAPE ABUTMENT ;
    PORT
      LAYER M3 ;
      RECT 45.135 283.338 45.153 283.392 ;
    END
  END w0_wmask_in[360]
  PIN w0_wmask_in[361]
    DIRECTION INPUT ;
    USE SIGNAL ;
    SHAPE ABUTMENT ;
    PORT
      LAYER M3 ;
      RECT 45.567 283.338 45.585 283.392 ;
    END
  END w0_wmask_in[361]
  PIN w0_wmask_in[362]
    DIRECTION INPUT ;
    USE SIGNAL ;
    SHAPE ABUTMENT ;
    PORT
      LAYER M3 ;
      RECT 45.999 283.338 46.017 283.392 ;
    END
  END w0_wmask_in[362]
  PIN w0_wmask_in[363]
    DIRECTION INPUT ;
    USE SIGNAL ;
    SHAPE ABUTMENT ;
    PORT
      LAYER M3 ;
      RECT 46.431 283.338 46.449 283.392 ;
    END
  END w0_wmask_in[363]
  PIN w0_wmask_in[364]
    DIRECTION INPUT ;
    USE SIGNAL ;
    SHAPE ABUTMENT ;
    PORT
      LAYER M3 ;
      RECT 46.863 283.338 46.881 283.392 ;
    END
  END w0_wmask_in[364]
  PIN w0_wmask_in[365]
    DIRECTION INPUT ;
    USE SIGNAL ;
    SHAPE ABUTMENT ;
    PORT
      LAYER M3 ;
      RECT 47.295 283.338 47.313 283.392 ;
    END
  END w0_wmask_in[365]
  PIN w0_wmask_in[366]
    DIRECTION INPUT ;
    USE SIGNAL ;
    SHAPE ABUTMENT ;
    PORT
      LAYER M3 ;
      RECT 47.727 283.338 47.745 283.392 ;
    END
  END w0_wmask_in[366]
  PIN w0_wmask_in[367]
    DIRECTION INPUT ;
    USE SIGNAL ;
    SHAPE ABUTMENT ;
    PORT
      LAYER M3 ;
      RECT 48.159 283.338 48.177 283.392 ;
    END
  END w0_wmask_in[367]
  PIN w0_wmask_in[368]
    DIRECTION INPUT ;
    USE SIGNAL ;
    SHAPE ABUTMENT ;
    PORT
      LAYER M3 ;
      RECT 48.591 283.338 48.609 283.392 ;
    END
  END w0_wmask_in[368]
  PIN w0_wmask_in[369]
    DIRECTION INPUT ;
    USE SIGNAL ;
    SHAPE ABUTMENT ;
    PORT
      LAYER M3 ;
      RECT 49.023 283.338 49.041 283.392 ;
    END
  END w0_wmask_in[369]
  PIN w0_wmask_in[370]
    DIRECTION INPUT ;
    USE SIGNAL ;
    SHAPE ABUTMENT ;
    PORT
      LAYER M3 ;
      RECT 49.455 283.338 49.473 283.392 ;
    END
  END w0_wmask_in[370]
  PIN w0_wmask_in[371]
    DIRECTION INPUT ;
    USE SIGNAL ;
    SHAPE ABUTMENT ;
    PORT
      LAYER M3 ;
      RECT 49.887 283.338 49.905 283.392 ;
    END
  END w0_wmask_in[371]
  PIN w0_wmask_in[372]
    DIRECTION INPUT ;
    USE SIGNAL ;
    SHAPE ABUTMENT ;
    PORT
      LAYER M3 ;
      RECT 50.319 283.338 50.337 283.392 ;
    END
  END w0_wmask_in[372]
  PIN w0_wmask_in[373]
    DIRECTION INPUT ;
    USE SIGNAL ;
    SHAPE ABUTMENT ;
    PORT
      LAYER M3 ;
      RECT 50.751 283.338 50.769 283.392 ;
    END
  END w0_wmask_in[373]
  PIN w0_wmask_in[374]
    DIRECTION INPUT ;
    USE SIGNAL ;
    SHAPE ABUTMENT ;
    PORT
      LAYER M3 ;
      RECT 51.183 283.338 51.201 283.392 ;
    END
  END w0_wmask_in[374]
  PIN w0_wmask_in[375]
    DIRECTION INPUT ;
    USE SIGNAL ;
    SHAPE ABUTMENT ;
    PORT
      LAYER M3 ;
      RECT 51.615 283.338 51.633 283.392 ;
    END
  END w0_wmask_in[375]
  PIN w0_wmask_in[376]
    DIRECTION INPUT ;
    USE SIGNAL ;
    SHAPE ABUTMENT ;
    PORT
      LAYER M3 ;
      RECT 52.047 283.338 52.065 283.392 ;
    END
  END w0_wmask_in[376]
  PIN w0_wmask_in[377]
    DIRECTION INPUT ;
    USE SIGNAL ;
    SHAPE ABUTMENT ;
    PORT
      LAYER M3 ;
      RECT 52.479 283.338 52.497 283.392 ;
    END
  END w0_wmask_in[377]
  PIN w0_wmask_in[378]
    DIRECTION INPUT ;
    USE SIGNAL ;
    SHAPE ABUTMENT ;
    PORT
      LAYER M3 ;
      RECT 52.911 283.338 52.929 283.392 ;
    END
  END w0_wmask_in[378]
  PIN w0_wmask_in[379]
    DIRECTION INPUT ;
    USE SIGNAL ;
    SHAPE ABUTMENT ;
    PORT
      LAYER M3 ;
      RECT 53.343 283.338 53.361 283.392 ;
    END
  END w0_wmask_in[379]
  PIN w0_wmask_in[380]
    DIRECTION INPUT ;
    USE SIGNAL ;
    SHAPE ABUTMENT ;
    PORT
      LAYER M3 ;
      RECT 53.775 283.338 53.793 283.392 ;
    END
  END w0_wmask_in[380]
  PIN w0_wmask_in[381]
    DIRECTION INPUT ;
    USE SIGNAL ;
    SHAPE ABUTMENT ;
    PORT
      LAYER M3 ;
      RECT 54.207 283.338 54.225 283.392 ;
    END
  END w0_wmask_in[381]
  PIN w0_wmask_in[382]
    DIRECTION INPUT ;
    USE SIGNAL ;
    SHAPE ABUTMENT ;
    PORT
      LAYER M3 ;
      RECT 54.639 283.338 54.657 283.392 ;
    END
  END w0_wmask_in[382]
  PIN w0_wmask_in[383]
    DIRECTION INPUT ;
    USE SIGNAL ;
    SHAPE ABUTMENT ;
    PORT
      LAYER M3 ;
      RECT 55.071 283.338 55.089 283.392 ;
    END
  END w0_wmask_in[383]
  PIN w0_wmask_in[384]
    DIRECTION INPUT ;
    USE SIGNAL ;
    SHAPE ABUTMENT ;
    PORT
      LAYER M3 ;
      RECT 55.503 283.338 55.521 283.392 ;
    END
  END w0_wmask_in[384]
  PIN w0_wmask_in[385]
    DIRECTION INPUT ;
    USE SIGNAL ;
    SHAPE ABUTMENT ;
    PORT
      LAYER M3 ;
      RECT 55.935 283.338 55.953 283.392 ;
    END
  END w0_wmask_in[385]
  PIN w0_wmask_in[386]
    DIRECTION INPUT ;
    USE SIGNAL ;
    SHAPE ABUTMENT ;
    PORT
      LAYER M3 ;
      RECT 56.367 283.338 56.385 283.392 ;
    END
  END w0_wmask_in[386]
  PIN w0_wmask_in[387]
    DIRECTION INPUT ;
    USE SIGNAL ;
    SHAPE ABUTMENT ;
    PORT
      LAYER M3 ;
      RECT 56.799 283.338 56.817 283.392 ;
    END
  END w0_wmask_in[387]
  PIN w0_wmask_in[388]
    DIRECTION INPUT ;
    USE SIGNAL ;
    SHAPE ABUTMENT ;
    PORT
      LAYER M3 ;
      RECT 57.231 283.338 57.249 283.392 ;
    END
  END w0_wmask_in[388]
  PIN w0_wmask_in[389]
    DIRECTION INPUT ;
    USE SIGNAL ;
    SHAPE ABUTMENT ;
    PORT
      LAYER M3 ;
      RECT 57.663 283.338 57.681 283.392 ;
    END
  END w0_wmask_in[389]
  PIN w0_wmask_in[390]
    DIRECTION INPUT ;
    USE SIGNAL ;
    SHAPE ABUTMENT ;
    PORT
      LAYER M3 ;
      RECT 58.095 283.338 58.113 283.392 ;
    END
  END w0_wmask_in[390]
  PIN w0_wmask_in[391]
    DIRECTION INPUT ;
    USE SIGNAL ;
    SHAPE ABUTMENT ;
    PORT
      LAYER M3 ;
      RECT 58.527 283.338 58.545 283.392 ;
    END
  END w0_wmask_in[391]
  PIN w0_wmask_in[392]
    DIRECTION INPUT ;
    USE SIGNAL ;
    SHAPE ABUTMENT ;
    PORT
      LAYER M3 ;
      RECT 58.959 283.338 58.977 283.392 ;
    END
  END w0_wmask_in[392]
  PIN w0_wmask_in[393]
    DIRECTION INPUT ;
    USE SIGNAL ;
    SHAPE ABUTMENT ;
    PORT
      LAYER M3 ;
      RECT 59.391 283.338 59.409 283.392 ;
    END
  END w0_wmask_in[393]
  PIN w0_wmask_in[394]
    DIRECTION INPUT ;
    USE SIGNAL ;
    SHAPE ABUTMENT ;
    PORT
      LAYER M3 ;
      RECT 59.823 283.338 59.841 283.392 ;
    END
  END w0_wmask_in[394]
  PIN w0_wmask_in[395]
    DIRECTION INPUT ;
    USE SIGNAL ;
    SHAPE ABUTMENT ;
    PORT
      LAYER M3 ;
      RECT 60.255 283.338 60.273 283.392 ;
    END
  END w0_wmask_in[395]
  PIN w0_wmask_in[396]
    DIRECTION INPUT ;
    USE SIGNAL ;
    SHAPE ABUTMENT ;
    PORT
      LAYER M3 ;
      RECT 60.687 283.338 60.705 283.392 ;
    END
  END w0_wmask_in[396]
  PIN w0_wmask_in[397]
    DIRECTION INPUT ;
    USE SIGNAL ;
    SHAPE ABUTMENT ;
    PORT
      LAYER M3 ;
      RECT 61.119 283.338 61.137 283.392 ;
    END
  END w0_wmask_in[397]
  PIN w0_wmask_in[398]
    DIRECTION INPUT ;
    USE SIGNAL ;
    SHAPE ABUTMENT ;
    PORT
      LAYER M3 ;
      RECT 61.551 283.338 61.569 283.392 ;
    END
  END w0_wmask_in[398]
  PIN w0_wmask_in[399]
    DIRECTION INPUT ;
    USE SIGNAL ;
    SHAPE ABUTMENT ;
    PORT
      LAYER M3 ;
      RECT 61.983 283.338 62.001 283.392 ;
    END
  END w0_wmask_in[399]
  PIN w0_wmask_in[400]
    DIRECTION INPUT ;
    USE SIGNAL ;
    SHAPE ABUTMENT ;
    PORT
      LAYER M3 ;
      RECT 62.415 283.338 62.433 283.392 ;
    END
  END w0_wmask_in[400]
  PIN w0_wmask_in[401]
    DIRECTION INPUT ;
    USE SIGNAL ;
    SHAPE ABUTMENT ;
    PORT
      LAYER M3 ;
      RECT 62.847 283.338 62.865 283.392 ;
    END
  END w0_wmask_in[401]
  PIN w0_wmask_in[402]
    DIRECTION INPUT ;
    USE SIGNAL ;
    SHAPE ABUTMENT ;
    PORT
      LAYER M3 ;
      RECT 63.279 283.338 63.297 283.392 ;
    END
  END w0_wmask_in[402]
  PIN w0_wmask_in[403]
    DIRECTION INPUT ;
    USE SIGNAL ;
    SHAPE ABUTMENT ;
    PORT
      LAYER M3 ;
      RECT 63.711 283.338 63.729 283.392 ;
    END
  END w0_wmask_in[403]
  PIN w0_wmask_in[404]
    DIRECTION INPUT ;
    USE SIGNAL ;
    SHAPE ABUTMENT ;
    PORT
      LAYER M3 ;
      RECT 64.143 283.338 64.161 283.392 ;
    END
  END w0_wmask_in[404]
  PIN w0_wmask_in[405]
    DIRECTION INPUT ;
    USE SIGNAL ;
    SHAPE ABUTMENT ;
    PORT
      LAYER M3 ;
      RECT 64.575 283.338 64.593 283.392 ;
    END
  END w0_wmask_in[405]
  PIN w0_wmask_in[406]
    DIRECTION INPUT ;
    USE SIGNAL ;
    SHAPE ABUTMENT ;
    PORT
      LAYER M3 ;
      RECT 65.007 283.338 65.025 283.392 ;
    END
  END w0_wmask_in[406]
  PIN w0_wmask_in[407]
    DIRECTION INPUT ;
    USE SIGNAL ;
    SHAPE ABUTMENT ;
    PORT
      LAYER M3 ;
      RECT 65.439 283.338 65.457 283.392 ;
    END
  END w0_wmask_in[407]
  PIN w0_wmask_in[408]
    DIRECTION INPUT ;
    USE SIGNAL ;
    SHAPE ABUTMENT ;
    PORT
      LAYER M3 ;
      RECT 65.871 283.338 65.889 283.392 ;
    END
  END w0_wmask_in[408]
  PIN w0_wmask_in[409]
    DIRECTION INPUT ;
    USE SIGNAL ;
    SHAPE ABUTMENT ;
    PORT
      LAYER M3 ;
      RECT 66.303 283.338 66.321 283.392 ;
    END
  END w0_wmask_in[409]
  PIN w0_wmask_in[410]
    DIRECTION INPUT ;
    USE SIGNAL ;
    SHAPE ABUTMENT ;
    PORT
      LAYER M3 ;
      RECT 66.735 283.338 66.753 283.392 ;
    END
  END w0_wmask_in[410]
  PIN w0_wmask_in[411]
    DIRECTION INPUT ;
    USE SIGNAL ;
    SHAPE ABUTMENT ;
    PORT
      LAYER M3 ;
      RECT 67.167 283.338 67.185 283.392 ;
    END
  END w0_wmask_in[411]
  PIN w0_wmask_in[412]
    DIRECTION INPUT ;
    USE SIGNAL ;
    SHAPE ABUTMENT ;
    PORT
      LAYER M3 ;
      RECT 67.599 283.338 67.617 283.392 ;
    END
  END w0_wmask_in[412]
  PIN w0_wmask_in[413]
    DIRECTION INPUT ;
    USE SIGNAL ;
    SHAPE ABUTMENT ;
    PORT
      LAYER M3 ;
      RECT 68.031 283.338 68.049 283.392 ;
    END
  END w0_wmask_in[413]
  PIN w0_wmask_in[414]
    DIRECTION INPUT ;
    USE SIGNAL ;
    SHAPE ABUTMENT ;
    PORT
      LAYER M3 ;
      RECT 68.463 283.338 68.481 283.392 ;
    END
  END w0_wmask_in[414]
  PIN w0_wmask_in[415]
    DIRECTION INPUT ;
    USE SIGNAL ;
    SHAPE ABUTMENT ;
    PORT
      LAYER M3 ;
      RECT 68.895 283.338 68.913 283.392 ;
    END
  END w0_wmask_in[415]
  PIN w0_wmask_in[416]
    DIRECTION INPUT ;
    USE SIGNAL ;
    SHAPE ABUTMENT ;
    PORT
      LAYER M3 ;
      RECT 69.327 283.338 69.345 283.392 ;
    END
  END w0_wmask_in[416]
  PIN w0_wmask_in[417]
    DIRECTION INPUT ;
    USE SIGNAL ;
    SHAPE ABUTMENT ;
    PORT
      LAYER M3 ;
      RECT 69.759 283.338 69.777 283.392 ;
    END
  END w0_wmask_in[417]
  PIN w0_wmask_in[418]
    DIRECTION INPUT ;
    USE SIGNAL ;
    SHAPE ABUTMENT ;
    PORT
      LAYER M3 ;
      RECT 70.191 283.338 70.209 283.392 ;
    END
  END w0_wmask_in[418]
  PIN w0_wmask_in[419]
    DIRECTION INPUT ;
    USE SIGNAL ;
    SHAPE ABUTMENT ;
    PORT
      LAYER M3 ;
      RECT 70.623 283.338 70.641 283.392 ;
    END
  END w0_wmask_in[419]
  PIN w0_wmask_in[420]
    DIRECTION INPUT ;
    USE SIGNAL ;
    SHAPE ABUTMENT ;
    PORT
      LAYER M3 ;
      RECT 71.055 283.338 71.073 283.392 ;
    END
  END w0_wmask_in[420]
  PIN w0_wmask_in[421]
    DIRECTION INPUT ;
    USE SIGNAL ;
    SHAPE ABUTMENT ;
    PORT
      LAYER M3 ;
      RECT 71.487 283.338 71.505 283.392 ;
    END
  END w0_wmask_in[421]
  PIN w0_wmask_in[422]
    DIRECTION INPUT ;
    USE SIGNAL ;
    SHAPE ABUTMENT ;
    PORT
      LAYER M3 ;
      RECT 71.919 283.338 71.937 283.392 ;
    END
  END w0_wmask_in[422]
  PIN w0_wmask_in[423]
    DIRECTION INPUT ;
    USE SIGNAL ;
    SHAPE ABUTMENT ;
    PORT
      LAYER M3 ;
      RECT 72.351 283.338 72.369 283.392 ;
    END
  END w0_wmask_in[423]
  PIN w0_wmask_in[424]
    DIRECTION INPUT ;
    USE SIGNAL ;
    SHAPE ABUTMENT ;
    PORT
      LAYER M3 ;
      RECT 72.783 283.338 72.801 283.392 ;
    END
  END w0_wmask_in[424]
  PIN w0_wmask_in[425]
    DIRECTION INPUT ;
    USE SIGNAL ;
    SHAPE ABUTMENT ;
    PORT
      LAYER M3 ;
      RECT 73.215 283.338 73.233 283.392 ;
    END
  END w0_wmask_in[425]
  PIN w0_wmask_in[426]
    DIRECTION INPUT ;
    USE SIGNAL ;
    SHAPE ABUTMENT ;
    PORT
      LAYER M3 ;
      RECT 73.647 283.338 73.665 283.392 ;
    END
  END w0_wmask_in[426]
  PIN w0_wmask_in[427]
    DIRECTION INPUT ;
    USE SIGNAL ;
    SHAPE ABUTMENT ;
    PORT
      LAYER M3 ;
      RECT 74.079 283.338 74.097 283.392 ;
    END
  END w0_wmask_in[427]
  PIN w0_wmask_in[428]
    DIRECTION INPUT ;
    USE SIGNAL ;
    SHAPE ABUTMENT ;
    PORT
      LAYER M3 ;
      RECT 74.511 283.338 74.529 283.392 ;
    END
  END w0_wmask_in[428]
  PIN w0_wmask_in[429]
    DIRECTION INPUT ;
    USE SIGNAL ;
    SHAPE ABUTMENT ;
    PORT
      LAYER M3 ;
      RECT 74.943 283.338 74.961 283.392 ;
    END
  END w0_wmask_in[429]
  PIN w0_wmask_in[430]
    DIRECTION INPUT ;
    USE SIGNAL ;
    SHAPE ABUTMENT ;
    PORT
      LAYER M3 ;
      RECT 75.375 283.338 75.393 283.392 ;
    END
  END w0_wmask_in[430]
  PIN w0_wmask_in[431]
    DIRECTION INPUT ;
    USE SIGNAL ;
    SHAPE ABUTMENT ;
    PORT
      LAYER M3 ;
      RECT 75.807 283.338 75.825 283.392 ;
    END
  END w0_wmask_in[431]
  PIN w0_wmask_in[432]
    DIRECTION INPUT ;
    USE SIGNAL ;
    SHAPE ABUTMENT ;
    PORT
      LAYER M3 ;
      RECT 76.239 283.338 76.257 283.392 ;
    END
  END w0_wmask_in[432]
  PIN w0_wmask_in[433]
    DIRECTION INPUT ;
    USE SIGNAL ;
    SHAPE ABUTMENT ;
    PORT
      LAYER M3 ;
      RECT 76.671 283.338 76.689 283.392 ;
    END
  END w0_wmask_in[433]
  PIN w0_wmask_in[434]
    DIRECTION INPUT ;
    USE SIGNAL ;
    SHAPE ABUTMENT ;
    PORT
      LAYER M3 ;
      RECT 77.103 283.338 77.121 283.392 ;
    END
  END w0_wmask_in[434]
  PIN w0_wmask_in[435]
    DIRECTION INPUT ;
    USE SIGNAL ;
    SHAPE ABUTMENT ;
    PORT
      LAYER M3 ;
      RECT 77.535 283.338 77.553 283.392 ;
    END
  END w0_wmask_in[435]
  PIN w0_wmask_in[436]
    DIRECTION INPUT ;
    USE SIGNAL ;
    SHAPE ABUTMENT ;
    PORT
      LAYER M3 ;
      RECT 77.967 283.338 77.985 283.392 ;
    END
  END w0_wmask_in[436]
  PIN w0_wmask_in[437]
    DIRECTION INPUT ;
    USE SIGNAL ;
    SHAPE ABUTMENT ;
    PORT
      LAYER M3 ;
      RECT 78.399 283.338 78.417 283.392 ;
    END
  END w0_wmask_in[437]
  PIN w0_wmask_in[438]
    DIRECTION INPUT ;
    USE SIGNAL ;
    SHAPE ABUTMENT ;
    PORT
      LAYER M3 ;
      RECT 78.831 283.338 78.849 283.392 ;
    END
  END w0_wmask_in[438]
  PIN w0_wmask_in[439]
    DIRECTION INPUT ;
    USE SIGNAL ;
    SHAPE ABUTMENT ;
    PORT
      LAYER M3 ;
      RECT 79.263 283.338 79.281 283.392 ;
    END
  END w0_wmask_in[439]
  PIN w0_wmask_in[440]
    DIRECTION INPUT ;
    USE SIGNAL ;
    SHAPE ABUTMENT ;
    PORT
      LAYER M3 ;
      RECT 79.695 283.338 79.713 283.392 ;
    END
  END w0_wmask_in[440]
  PIN w0_wmask_in[441]
    DIRECTION INPUT ;
    USE SIGNAL ;
    SHAPE ABUTMENT ;
    PORT
      LAYER M3 ;
      RECT 80.127 283.338 80.145 283.392 ;
    END
  END w0_wmask_in[441]
  PIN w0_wmask_in[442]
    DIRECTION INPUT ;
    USE SIGNAL ;
    SHAPE ABUTMENT ;
    PORT
      LAYER M3 ;
      RECT 80.559 283.338 80.577 283.392 ;
    END
  END w0_wmask_in[442]
  PIN w0_wmask_in[443]
    DIRECTION INPUT ;
    USE SIGNAL ;
    SHAPE ABUTMENT ;
    PORT
      LAYER M3 ;
      RECT 80.991 283.338 81.009 283.392 ;
    END
  END w0_wmask_in[443]
  PIN w0_wmask_in[444]
    DIRECTION INPUT ;
    USE SIGNAL ;
    SHAPE ABUTMENT ;
    PORT
      LAYER M3 ;
      RECT 81.423 283.338 81.441 283.392 ;
    END
  END w0_wmask_in[444]
  PIN w0_wmask_in[445]
    DIRECTION INPUT ;
    USE SIGNAL ;
    SHAPE ABUTMENT ;
    PORT
      LAYER M3 ;
      RECT 81.855 283.338 81.873 283.392 ;
    END
  END w0_wmask_in[445]
  PIN w0_wmask_in[446]
    DIRECTION INPUT ;
    USE SIGNAL ;
    SHAPE ABUTMENT ;
    PORT
      LAYER M3 ;
      RECT 82.287 283.338 82.305 283.392 ;
    END
  END w0_wmask_in[446]
  PIN w0_wmask_in[447]
    DIRECTION INPUT ;
    USE SIGNAL ;
    SHAPE ABUTMENT ;
    PORT
      LAYER M3 ;
      RECT 82.719 283.338 82.737 283.392 ;
    END
  END w0_wmask_in[447]
  PIN w0_wmask_in[448]
    DIRECTION INPUT ;
    USE SIGNAL ;
    SHAPE ABUTMENT ;
    PORT
      LAYER M3 ;
      RECT 83.151 283.338 83.169 283.392 ;
    END
  END w0_wmask_in[448]
  PIN w0_wmask_in[449]
    DIRECTION INPUT ;
    USE SIGNAL ;
    SHAPE ABUTMENT ;
    PORT
      LAYER M3 ;
      RECT 83.583 283.338 83.601 283.392 ;
    END
  END w0_wmask_in[449]
  PIN w0_wmask_in[450]
    DIRECTION INPUT ;
    USE SIGNAL ;
    SHAPE ABUTMENT ;
    PORT
      LAYER M3 ;
      RECT 84.015 283.338 84.033 283.392 ;
    END
  END w0_wmask_in[450]
  PIN w0_wmask_in[451]
    DIRECTION INPUT ;
    USE SIGNAL ;
    SHAPE ABUTMENT ;
    PORT
      LAYER M3 ;
      RECT 84.447 283.338 84.465 283.392 ;
    END
  END w0_wmask_in[451]
  PIN w0_wmask_in[452]
    DIRECTION INPUT ;
    USE SIGNAL ;
    SHAPE ABUTMENT ;
    PORT
      LAYER M3 ;
      RECT 84.879 283.338 84.897 283.392 ;
    END
  END w0_wmask_in[452]
  PIN w0_wmask_in[453]
    DIRECTION INPUT ;
    USE SIGNAL ;
    SHAPE ABUTMENT ;
    PORT
      LAYER M3 ;
      RECT 85.311 283.338 85.329 283.392 ;
    END
  END w0_wmask_in[453]
  PIN w0_wmask_in[454]
    DIRECTION INPUT ;
    USE SIGNAL ;
    SHAPE ABUTMENT ;
    PORT
      LAYER M3 ;
      RECT 85.743 283.338 85.761 283.392 ;
    END
  END w0_wmask_in[454]
  PIN w0_wmask_in[455]
    DIRECTION INPUT ;
    USE SIGNAL ;
    SHAPE ABUTMENT ;
    PORT
      LAYER M3 ;
      RECT 86.175 283.338 86.193 283.392 ;
    END
  END w0_wmask_in[455]
  PIN w0_wmask_in[456]
    DIRECTION INPUT ;
    USE SIGNAL ;
    SHAPE ABUTMENT ;
    PORT
      LAYER M3 ;
      RECT 86.607 283.338 86.625 283.392 ;
    END
  END w0_wmask_in[456]
  PIN w0_wmask_in[457]
    DIRECTION INPUT ;
    USE SIGNAL ;
    SHAPE ABUTMENT ;
    PORT
      LAYER M3 ;
      RECT 87.039 283.338 87.057 283.392 ;
    END
  END w0_wmask_in[457]
  PIN w0_wmask_in[458]
    DIRECTION INPUT ;
    USE SIGNAL ;
    SHAPE ABUTMENT ;
    PORT
      LAYER M3 ;
      RECT 87.471 283.338 87.489 283.392 ;
    END
  END w0_wmask_in[458]
  PIN w0_wmask_in[459]
    DIRECTION INPUT ;
    USE SIGNAL ;
    SHAPE ABUTMENT ;
    PORT
      LAYER M3 ;
      RECT 87.903 283.338 87.921 283.392 ;
    END
  END w0_wmask_in[459]
  PIN w0_wmask_in[460]
    DIRECTION INPUT ;
    USE SIGNAL ;
    SHAPE ABUTMENT ;
    PORT
      LAYER M3 ;
      RECT 88.335 283.338 88.353 283.392 ;
    END
  END w0_wmask_in[460]
  PIN w0_wmask_in[461]
    DIRECTION INPUT ;
    USE SIGNAL ;
    SHAPE ABUTMENT ;
    PORT
      LAYER M3 ;
      RECT 88.767 283.338 88.785 283.392 ;
    END
  END w0_wmask_in[461]
  PIN w0_wmask_in[462]
    DIRECTION INPUT ;
    USE SIGNAL ;
    SHAPE ABUTMENT ;
    PORT
      LAYER M3 ;
      RECT 89.199 283.338 89.217 283.392 ;
    END
  END w0_wmask_in[462]
  PIN w0_wmask_in[463]
    DIRECTION INPUT ;
    USE SIGNAL ;
    SHAPE ABUTMENT ;
    PORT
      LAYER M3 ;
      RECT 89.631 283.338 89.649 283.392 ;
    END
  END w0_wmask_in[463]
  PIN w0_wmask_in[464]
    DIRECTION INPUT ;
    USE SIGNAL ;
    SHAPE ABUTMENT ;
    PORT
      LAYER M3 ;
      RECT 90.063 283.338 90.081 283.392 ;
    END
  END w0_wmask_in[464]
  PIN w0_wmask_in[465]
    DIRECTION INPUT ;
    USE SIGNAL ;
    SHAPE ABUTMENT ;
    PORT
      LAYER M3 ;
      RECT 90.495 283.338 90.513 283.392 ;
    END
  END w0_wmask_in[465]
  PIN w0_wmask_in[466]
    DIRECTION INPUT ;
    USE SIGNAL ;
    SHAPE ABUTMENT ;
    PORT
      LAYER M3 ;
      RECT 90.927 283.338 90.945 283.392 ;
    END
  END w0_wmask_in[466]
  PIN w0_wmask_in[467]
    DIRECTION INPUT ;
    USE SIGNAL ;
    SHAPE ABUTMENT ;
    PORT
      LAYER M3 ;
      RECT 91.359 283.338 91.377 283.392 ;
    END
  END w0_wmask_in[467]
  PIN w0_wmask_in[468]
    DIRECTION INPUT ;
    USE SIGNAL ;
    SHAPE ABUTMENT ;
    PORT
      LAYER M3 ;
      RECT 91.791 283.338 91.809 283.392 ;
    END
  END w0_wmask_in[468]
  PIN w0_wmask_in[469]
    DIRECTION INPUT ;
    USE SIGNAL ;
    SHAPE ABUTMENT ;
    PORT
      LAYER M3 ;
      RECT 92.223 283.338 92.241 283.392 ;
    END
  END w0_wmask_in[469]
  PIN w0_wmask_in[470]
    DIRECTION INPUT ;
    USE SIGNAL ;
    SHAPE ABUTMENT ;
    PORT
      LAYER M3 ;
      RECT 92.655 283.338 92.673 283.392 ;
    END
  END w0_wmask_in[470]
  PIN w0_wmask_in[471]
    DIRECTION INPUT ;
    USE SIGNAL ;
    SHAPE ABUTMENT ;
    PORT
      LAYER M3 ;
      RECT 93.087 283.338 93.105 283.392 ;
    END
  END w0_wmask_in[471]
  PIN w0_wmask_in[472]
    DIRECTION INPUT ;
    USE SIGNAL ;
    SHAPE ABUTMENT ;
    PORT
      LAYER M3 ;
      RECT 93.519 283.338 93.537 283.392 ;
    END
  END w0_wmask_in[472]
  PIN w0_wmask_in[473]
    DIRECTION INPUT ;
    USE SIGNAL ;
    SHAPE ABUTMENT ;
    PORT
      LAYER M3 ;
      RECT 93.951 283.338 93.969 283.392 ;
    END
  END w0_wmask_in[473]
  PIN w0_wmask_in[474]
    DIRECTION INPUT ;
    USE SIGNAL ;
    SHAPE ABUTMENT ;
    PORT
      LAYER M3 ;
      RECT 94.383 283.338 94.401 283.392 ;
    END
  END w0_wmask_in[474]
  PIN w0_wmask_in[475]
    DIRECTION INPUT ;
    USE SIGNAL ;
    SHAPE ABUTMENT ;
    PORT
      LAYER M3 ;
      RECT 94.815 283.338 94.833 283.392 ;
    END
  END w0_wmask_in[475]
  PIN w0_wmask_in[476]
    DIRECTION INPUT ;
    USE SIGNAL ;
    SHAPE ABUTMENT ;
    PORT
      LAYER M3 ;
      RECT 95.247 283.338 95.265 283.392 ;
    END
  END w0_wmask_in[476]
  PIN w0_wmask_in[477]
    DIRECTION INPUT ;
    USE SIGNAL ;
    SHAPE ABUTMENT ;
    PORT
      LAYER M3 ;
      RECT 95.679 283.338 95.697 283.392 ;
    END
  END w0_wmask_in[477]
  PIN w0_wmask_in[478]
    DIRECTION INPUT ;
    USE SIGNAL ;
    SHAPE ABUTMENT ;
    PORT
      LAYER M3 ;
      RECT 96.111 283.338 96.129 283.392 ;
    END
  END w0_wmask_in[478]
  PIN w0_wmask_in[479]
    DIRECTION INPUT ;
    USE SIGNAL ;
    SHAPE ABUTMENT ;
    PORT
      LAYER M3 ;
      RECT 96.543 283.338 96.561 283.392 ;
    END
  END w0_wmask_in[479]
  PIN w0_wmask_in[480]
    DIRECTION INPUT ;
    USE SIGNAL ;
    SHAPE ABUTMENT ;
    PORT
      LAYER M3 ;
      RECT 96.975 283.338 96.993 283.392 ;
    END
  END w0_wmask_in[480]
  PIN w0_wmask_in[481]
    DIRECTION INPUT ;
    USE SIGNAL ;
    SHAPE ABUTMENT ;
    PORT
      LAYER M3 ;
      RECT 97.407 283.338 97.425 283.392 ;
    END
  END w0_wmask_in[481]
  PIN w0_wmask_in[482]
    DIRECTION INPUT ;
    USE SIGNAL ;
    SHAPE ABUTMENT ;
    PORT
      LAYER M3 ;
      RECT 97.839 283.338 97.857 283.392 ;
    END
  END w0_wmask_in[482]
  PIN w0_wmask_in[483]
    DIRECTION INPUT ;
    USE SIGNAL ;
    SHAPE ABUTMENT ;
    PORT
      LAYER M3 ;
      RECT 98.271 283.338 98.289 283.392 ;
    END
  END w0_wmask_in[483]
  PIN w0_wmask_in[484]
    DIRECTION INPUT ;
    USE SIGNAL ;
    SHAPE ABUTMENT ;
    PORT
      LAYER M3 ;
      RECT 98.703 283.338 98.721 283.392 ;
    END
  END w0_wmask_in[484]
  PIN w0_wmask_in[485]
    DIRECTION INPUT ;
    USE SIGNAL ;
    SHAPE ABUTMENT ;
    PORT
      LAYER M3 ;
      RECT 99.135 283.338 99.153 283.392 ;
    END
  END w0_wmask_in[485]
  PIN w0_wmask_in[486]
    DIRECTION INPUT ;
    USE SIGNAL ;
    SHAPE ABUTMENT ;
    PORT
      LAYER M3 ;
      RECT 99.567 283.338 99.585 283.392 ;
    END
  END w0_wmask_in[486]
  PIN w0_wmask_in[487]
    DIRECTION INPUT ;
    USE SIGNAL ;
    SHAPE ABUTMENT ;
    PORT
      LAYER M3 ;
      RECT 99.999 283.338 100.017 283.392 ;
    END
  END w0_wmask_in[487]
  PIN w0_wmask_in[488]
    DIRECTION INPUT ;
    USE SIGNAL ;
    SHAPE ABUTMENT ;
    PORT
      LAYER M3 ;
      RECT 100.431 283.338 100.449 283.392 ;
    END
  END w0_wmask_in[488]
  PIN w0_wmask_in[489]
    DIRECTION INPUT ;
    USE SIGNAL ;
    SHAPE ABUTMENT ;
    PORT
      LAYER M3 ;
      RECT 100.863 283.338 100.881 283.392 ;
    END
  END w0_wmask_in[489]
  PIN w0_wmask_in[490]
    DIRECTION INPUT ;
    USE SIGNAL ;
    SHAPE ABUTMENT ;
    PORT
      LAYER M3 ;
      RECT 101.295 283.338 101.313 283.392 ;
    END
  END w0_wmask_in[490]
  PIN w0_wmask_in[491]
    DIRECTION INPUT ;
    USE SIGNAL ;
    SHAPE ABUTMENT ;
    PORT
      LAYER M3 ;
      RECT 101.727 283.338 101.745 283.392 ;
    END
  END w0_wmask_in[491]
  PIN w0_wmask_in[492]
    DIRECTION INPUT ;
    USE SIGNAL ;
    SHAPE ABUTMENT ;
    PORT
      LAYER M3 ;
      RECT 102.159 283.338 102.177 283.392 ;
    END
  END w0_wmask_in[492]
  PIN w0_wmask_in[493]
    DIRECTION INPUT ;
    USE SIGNAL ;
    SHAPE ABUTMENT ;
    PORT
      LAYER M3 ;
      RECT 102.591 283.338 102.609 283.392 ;
    END
  END w0_wmask_in[493]
  PIN w0_wmask_in[494]
    DIRECTION INPUT ;
    USE SIGNAL ;
    SHAPE ABUTMENT ;
    PORT
      LAYER M3 ;
      RECT 103.023 283.338 103.041 283.392 ;
    END
  END w0_wmask_in[494]
  PIN w0_wmask_in[495]
    DIRECTION INPUT ;
    USE SIGNAL ;
    SHAPE ABUTMENT ;
    PORT
      LAYER M3 ;
      RECT 103.455 283.338 103.473 283.392 ;
    END
  END w0_wmask_in[495]
  PIN w0_wmask_in[496]
    DIRECTION INPUT ;
    USE SIGNAL ;
    SHAPE ABUTMENT ;
    PORT
      LAYER M3 ;
      RECT 103.887 283.338 103.905 283.392 ;
    END
  END w0_wmask_in[496]
  PIN w0_wmask_in[497]
    DIRECTION INPUT ;
    USE SIGNAL ;
    SHAPE ABUTMENT ;
    PORT
      LAYER M3 ;
      RECT 104.319 283.338 104.337 283.392 ;
    END
  END w0_wmask_in[497]
  PIN w0_wmask_in[498]
    DIRECTION INPUT ;
    USE SIGNAL ;
    SHAPE ABUTMENT ;
    PORT
      LAYER M3 ;
      RECT 104.751 283.338 104.769 283.392 ;
    END
  END w0_wmask_in[498]
  PIN w0_wmask_in[499]
    DIRECTION INPUT ;
    USE SIGNAL ;
    SHAPE ABUTMENT ;
    PORT
      LAYER M3 ;
      RECT 105.183 283.338 105.201 283.392 ;
    END
  END w0_wmask_in[499]
  PIN w0_wmask_in[500]
    DIRECTION INPUT ;
    USE SIGNAL ;
    SHAPE ABUTMENT ;
    PORT
      LAYER M3 ;
      RECT 105.615 283.338 105.633 283.392 ;
    END
  END w0_wmask_in[500]
  PIN w0_wmask_in[501]
    DIRECTION INPUT ;
    USE SIGNAL ;
    SHAPE ABUTMENT ;
    PORT
      LAYER M3 ;
      RECT 106.047 283.338 106.065 283.392 ;
    END
  END w0_wmask_in[501]
  PIN w0_wmask_in[502]
    DIRECTION INPUT ;
    USE SIGNAL ;
    SHAPE ABUTMENT ;
    PORT
      LAYER M3 ;
      RECT 106.479 283.338 106.497 283.392 ;
    END
  END w0_wmask_in[502]
  PIN w0_wmask_in[503]
    DIRECTION INPUT ;
    USE SIGNAL ;
    SHAPE ABUTMENT ;
    PORT
      LAYER M3 ;
      RECT 106.911 283.338 106.929 283.392 ;
    END
  END w0_wmask_in[503]
  PIN w0_wmask_in[504]
    DIRECTION INPUT ;
    USE SIGNAL ;
    SHAPE ABUTMENT ;
    PORT
      LAYER M3 ;
      RECT 107.343 283.338 107.361 283.392 ;
    END
  END w0_wmask_in[504]
  PIN w0_wmask_in[505]
    DIRECTION INPUT ;
    USE SIGNAL ;
    SHAPE ABUTMENT ;
    PORT
      LAYER M3 ;
      RECT 107.775 283.338 107.793 283.392 ;
    END
  END w0_wmask_in[505]
  PIN w0_wmask_in[506]
    DIRECTION INPUT ;
    USE SIGNAL ;
    SHAPE ABUTMENT ;
    PORT
      LAYER M3 ;
      RECT 108.207 283.338 108.225 283.392 ;
    END
  END w0_wmask_in[506]
  PIN w0_wmask_in[507]
    DIRECTION INPUT ;
    USE SIGNAL ;
    SHAPE ABUTMENT ;
    PORT
      LAYER M3 ;
      RECT 108.639 283.338 108.657 283.392 ;
    END
  END w0_wmask_in[507]
  PIN w0_wmask_in[508]
    DIRECTION INPUT ;
    USE SIGNAL ;
    SHAPE ABUTMENT ;
    PORT
      LAYER M3 ;
      RECT 109.071 283.338 109.089 283.392 ;
    END
  END w0_wmask_in[508]
  PIN w0_wmask_in[509]
    DIRECTION INPUT ;
    USE SIGNAL ;
    SHAPE ABUTMENT ;
    PORT
      LAYER M3 ;
      RECT 109.503 283.338 109.521 283.392 ;
    END
  END w0_wmask_in[509]
  PIN w0_wmask_in[510]
    DIRECTION INPUT ;
    USE SIGNAL ;
    SHAPE ABUTMENT ;
    PORT
      LAYER M3 ;
      RECT 109.935 283.338 109.953 283.392 ;
    END
  END w0_wmask_in[510]
  PIN w0_wmask_in[511]
    DIRECTION INPUT ;
    USE SIGNAL ;
    SHAPE ABUTMENT ;
    PORT
      LAYER M3 ;
      RECT 110.367 283.338 110.385 283.392 ;
    END
  END w0_wmask_in[511]
  PIN w0_wd_in[0]
    DIRECTION INPUT ;
    USE SIGNAL ;
    SHAPE ABUTMENT ;
    PORT
      LAYER M4 ;
      RECT 0.000 135.444 0.072 135.468 ;
    END
  END w0_wd_in[0]
  PIN w0_wd_in[1]
    DIRECTION INPUT ;
    USE SIGNAL ;
    SHAPE ABUTMENT ;
    PORT
      LAYER M4 ;
      RECT 0.000 136.500 0.072 136.524 ;
    END
  END w0_wd_in[1]
  PIN w0_wd_in[2]
    DIRECTION INPUT ;
    USE SIGNAL ;
    SHAPE ABUTMENT ;
    PORT
      LAYER M4 ;
      RECT 0.000 137.556 0.072 137.580 ;
    END
  END w0_wd_in[2]
  PIN w0_wd_in[3]
    DIRECTION INPUT ;
    USE SIGNAL ;
    SHAPE ABUTMENT ;
    PORT
      LAYER M4 ;
      RECT 0.000 138.612 0.072 138.636 ;
    END
  END w0_wd_in[3]
  PIN w0_wd_in[4]
    DIRECTION INPUT ;
    USE SIGNAL ;
    SHAPE ABUTMENT ;
    PORT
      LAYER M4 ;
      RECT 0.000 139.668 0.072 139.692 ;
    END
  END w0_wd_in[4]
  PIN w0_wd_in[5]
    DIRECTION INPUT ;
    USE SIGNAL ;
    SHAPE ABUTMENT ;
    PORT
      LAYER M4 ;
      RECT 0.000 140.724 0.072 140.748 ;
    END
  END w0_wd_in[5]
  PIN w0_wd_in[6]
    DIRECTION INPUT ;
    USE SIGNAL ;
    SHAPE ABUTMENT ;
    PORT
      LAYER M4 ;
      RECT 0.000 141.780 0.072 141.804 ;
    END
  END w0_wd_in[6]
  PIN w0_wd_in[7]
    DIRECTION INPUT ;
    USE SIGNAL ;
    SHAPE ABUTMENT ;
    PORT
      LAYER M4 ;
      RECT 0.000 142.836 0.072 142.860 ;
    END
  END w0_wd_in[7]
  PIN w0_wd_in[8]
    DIRECTION INPUT ;
    USE SIGNAL ;
    SHAPE ABUTMENT ;
    PORT
      LAYER M4 ;
      RECT 0.000 143.892 0.072 143.916 ;
    END
  END w0_wd_in[8]
  PIN w0_wd_in[9]
    DIRECTION INPUT ;
    USE SIGNAL ;
    SHAPE ABUTMENT ;
    PORT
      LAYER M4 ;
      RECT 0.000 144.948 0.072 144.972 ;
    END
  END w0_wd_in[9]
  PIN w0_wd_in[10]
    DIRECTION INPUT ;
    USE SIGNAL ;
    SHAPE ABUTMENT ;
    PORT
      LAYER M4 ;
      RECT 0.000 146.004 0.072 146.028 ;
    END
  END w0_wd_in[10]
  PIN w0_wd_in[11]
    DIRECTION INPUT ;
    USE SIGNAL ;
    SHAPE ABUTMENT ;
    PORT
      LAYER M4 ;
      RECT 0.000 147.060 0.072 147.084 ;
    END
  END w0_wd_in[11]
  PIN w0_wd_in[12]
    DIRECTION INPUT ;
    USE SIGNAL ;
    SHAPE ABUTMENT ;
    PORT
      LAYER M4 ;
      RECT 0.000 148.116 0.072 148.140 ;
    END
  END w0_wd_in[12]
  PIN w0_wd_in[13]
    DIRECTION INPUT ;
    USE SIGNAL ;
    SHAPE ABUTMENT ;
    PORT
      LAYER M4 ;
      RECT 0.000 149.172 0.072 149.196 ;
    END
  END w0_wd_in[13]
  PIN w0_wd_in[14]
    DIRECTION INPUT ;
    USE SIGNAL ;
    SHAPE ABUTMENT ;
    PORT
      LAYER M4 ;
      RECT 0.000 150.228 0.072 150.252 ;
    END
  END w0_wd_in[14]
  PIN w0_wd_in[15]
    DIRECTION INPUT ;
    USE SIGNAL ;
    SHAPE ABUTMENT ;
    PORT
      LAYER M4 ;
      RECT 0.000 151.284 0.072 151.308 ;
    END
  END w0_wd_in[15]
  PIN w0_wd_in[16]
    DIRECTION INPUT ;
    USE SIGNAL ;
    SHAPE ABUTMENT ;
    PORT
      LAYER M4 ;
      RECT 0.000 152.340 0.072 152.364 ;
    END
  END w0_wd_in[16]
  PIN w0_wd_in[17]
    DIRECTION INPUT ;
    USE SIGNAL ;
    SHAPE ABUTMENT ;
    PORT
      LAYER M4 ;
      RECT 0.000 153.396 0.072 153.420 ;
    END
  END w0_wd_in[17]
  PIN w0_wd_in[18]
    DIRECTION INPUT ;
    USE SIGNAL ;
    SHAPE ABUTMENT ;
    PORT
      LAYER M4 ;
      RECT 0.000 154.452 0.072 154.476 ;
    END
  END w0_wd_in[18]
  PIN w0_wd_in[19]
    DIRECTION INPUT ;
    USE SIGNAL ;
    SHAPE ABUTMENT ;
    PORT
      LAYER M4 ;
      RECT 0.000 155.508 0.072 155.532 ;
    END
  END w0_wd_in[19]
  PIN w0_wd_in[20]
    DIRECTION INPUT ;
    USE SIGNAL ;
    SHAPE ABUTMENT ;
    PORT
      LAYER M4 ;
      RECT 0.000 156.564 0.072 156.588 ;
    END
  END w0_wd_in[20]
  PIN w0_wd_in[21]
    DIRECTION INPUT ;
    USE SIGNAL ;
    SHAPE ABUTMENT ;
    PORT
      LAYER M4 ;
      RECT 0.000 157.620 0.072 157.644 ;
    END
  END w0_wd_in[21]
  PIN w0_wd_in[22]
    DIRECTION INPUT ;
    USE SIGNAL ;
    SHAPE ABUTMENT ;
    PORT
      LAYER M4 ;
      RECT 0.000 158.676 0.072 158.700 ;
    END
  END w0_wd_in[22]
  PIN w0_wd_in[23]
    DIRECTION INPUT ;
    USE SIGNAL ;
    SHAPE ABUTMENT ;
    PORT
      LAYER M4 ;
      RECT 0.000 159.732 0.072 159.756 ;
    END
  END w0_wd_in[23]
  PIN w0_wd_in[24]
    DIRECTION INPUT ;
    USE SIGNAL ;
    SHAPE ABUTMENT ;
    PORT
      LAYER M4 ;
      RECT 0.000 160.788 0.072 160.812 ;
    END
  END w0_wd_in[24]
  PIN w0_wd_in[25]
    DIRECTION INPUT ;
    USE SIGNAL ;
    SHAPE ABUTMENT ;
    PORT
      LAYER M4 ;
      RECT 0.000 161.844 0.072 161.868 ;
    END
  END w0_wd_in[25]
  PIN w0_wd_in[26]
    DIRECTION INPUT ;
    USE SIGNAL ;
    SHAPE ABUTMENT ;
    PORT
      LAYER M4 ;
      RECT 0.000 162.900 0.072 162.924 ;
    END
  END w0_wd_in[26]
  PIN w0_wd_in[27]
    DIRECTION INPUT ;
    USE SIGNAL ;
    SHAPE ABUTMENT ;
    PORT
      LAYER M4 ;
      RECT 0.000 163.956 0.072 163.980 ;
    END
  END w0_wd_in[27]
  PIN w0_wd_in[28]
    DIRECTION INPUT ;
    USE SIGNAL ;
    SHAPE ABUTMENT ;
    PORT
      LAYER M4 ;
      RECT 0.000 165.012 0.072 165.036 ;
    END
  END w0_wd_in[28]
  PIN w0_wd_in[29]
    DIRECTION INPUT ;
    USE SIGNAL ;
    SHAPE ABUTMENT ;
    PORT
      LAYER M4 ;
      RECT 0.000 166.068 0.072 166.092 ;
    END
  END w0_wd_in[29]
  PIN w0_wd_in[30]
    DIRECTION INPUT ;
    USE SIGNAL ;
    SHAPE ABUTMENT ;
    PORT
      LAYER M4 ;
      RECT 0.000 167.124 0.072 167.148 ;
    END
  END w0_wd_in[30]
  PIN w0_wd_in[31]
    DIRECTION INPUT ;
    USE SIGNAL ;
    SHAPE ABUTMENT ;
    PORT
      LAYER M4 ;
      RECT 0.000 168.180 0.072 168.204 ;
    END
  END w0_wd_in[31]
  PIN w0_wd_in[32]
    DIRECTION INPUT ;
    USE SIGNAL ;
    SHAPE ABUTMENT ;
    PORT
      LAYER M4 ;
      RECT 0.000 169.236 0.072 169.260 ;
    END
  END w0_wd_in[32]
  PIN w0_wd_in[33]
    DIRECTION INPUT ;
    USE SIGNAL ;
    SHAPE ABUTMENT ;
    PORT
      LAYER M4 ;
      RECT 0.000 170.292 0.072 170.316 ;
    END
  END w0_wd_in[33]
  PIN w0_wd_in[34]
    DIRECTION INPUT ;
    USE SIGNAL ;
    SHAPE ABUTMENT ;
    PORT
      LAYER M4 ;
      RECT 0.000 171.348 0.072 171.372 ;
    END
  END w0_wd_in[34]
  PIN w0_wd_in[35]
    DIRECTION INPUT ;
    USE SIGNAL ;
    SHAPE ABUTMENT ;
    PORT
      LAYER M4 ;
      RECT 0.000 172.404 0.072 172.428 ;
    END
  END w0_wd_in[35]
  PIN w0_wd_in[36]
    DIRECTION INPUT ;
    USE SIGNAL ;
    SHAPE ABUTMENT ;
    PORT
      LAYER M4 ;
      RECT 0.000 173.460 0.072 173.484 ;
    END
  END w0_wd_in[36]
  PIN w0_wd_in[37]
    DIRECTION INPUT ;
    USE SIGNAL ;
    SHAPE ABUTMENT ;
    PORT
      LAYER M4 ;
      RECT 0.000 174.516 0.072 174.540 ;
    END
  END w0_wd_in[37]
  PIN w0_wd_in[38]
    DIRECTION INPUT ;
    USE SIGNAL ;
    SHAPE ABUTMENT ;
    PORT
      LAYER M4 ;
      RECT 0.000 175.572 0.072 175.596 ;
    END
  END w0_wd_in[38]
  PIN w0_wd_in[39]
    DIRECTION INPUT ;
    USE SIGNAL ;
    SHAPE ABUTMENT ;
    PORT
      LAYER M4 ;
      RECT 0.000 176.628 0.072 176.652 ;
    END
  END w0_wd_in[39]
  PIN w0_wd_in[40]
    DIRECTION INPUT ;
    USE SIGNAL ;
    SHAPE ABUTMENT ;
    PORT
      LAYER M4 ;
      RECT 0.000 177.684 0.072 177.708 ;
    END
  END w0_wd_in[40]
  PIN w0_wd_in[41]
    DIRECTION INPUT ;
    USE SIGNAL ;
    SHAPE ABUTMENT ;
    PORT
      LAYER M4 ;
      RECT 0.000 178.740 0.072 178.764 ;
    END
  END w0_wd_in[41]
  PIN w0_wd_in[42]
    DIRECTION INPUT ;
    USE SIGNAL ;
    SHAPE ABUTMENT ;
    PORT
      LAYER M4 ;
      RECT 0.000 179.796 0.072 179.820 ;
    END
  END w0_wd_in[42]
  PIN w0_wd_in[43]
    DIRECTION INPUT ;
    USE SIGNAL ;
    SHAPE ABUTMENT ;
    PORT
      LAYER M4 ;
      RECT 0.000 180.852 0.072 180.876 ;
    END
  END w0_wd_in[43]
  PIN w0_wd_in[44]
    DIRECTION INPUT ;
    USE SIGNAL ;
    SHAPE ABUTMENT ;
    PORT
      LAYER M4 ;
      RECT 0.000 181.908 0.072 181.932 ;
    END
  END w0_wd_in[44]
  PIN w0_wd_in[45]
    DIRECTION INPUT ;
    USE SIGNAL ;
    SHAPE ABUTMENT ;
    PORT
      LAYER M4 ;
      RECT 0.000 182.964 0.072 182.988 ;
    END
  END w0_wd_in[45]
  PIN w0_wd_in[46]
    DIRECTION INPUT ;
    USE SIGNAL ;
    SHAPE ABUTMENT ;
    PORT
      LAYER M4 ;
      RECT 0.000 184.020 0.072 184.044 ;
    END
  END w0_wd_in[46]
  PIN w0_wd_in[47]
    DIRECTION INPUT ;
    USE SIGNAL ;
    SHAPE ABUTMENT ;
    PORT
      LAYER M4 ;
      RECT 0.000 185.076 0.072 185.100 ;
    END
  END w0_wd_in[47]
  PIN w0_wd_in[48]
    DIRECTION INPUT ;
    USE SIGNAL ;
    SHAPE ABUTMENT ;
    PORT
      LAYER M4 ;
      RECT 0.000 186.132 0.072 186.156 ;
    END
  END w0_wd_in[48]
  PIN w0_wd_in[49]
    DIRECTION INPUT ;
    USE SIGNAL ;
    SHAPE ABUTMENT ;
    PORT
      LAYER M4 ;
      RECT 0.000 187.188 0.072 187.212 ;
    END
  END w0_wd_in[49]
  PIN w0_wd_in[50]
    DIRECTION INPUT ;
    USE SIGNAL ;
    SHAPE ABUTMENT ;
    PORT
      LAYER M4 ;
      RECT 0.000 188.244 0.072 188.268 ;
    END
  END w0_wd_in[50]
  PIN w0_wd_in[51]
    DIRECTION INPUT ;
    USE SIGNAL ;
    SHAPE ABUTMENT ;
    PORT
      LAYER M4 ;
      RECT 0.000 189.300 0.072 189.324 ;
    END
  END w0_wd_in[51]
  PIN w0_wd_in[52]
    DIRECTION INPUT ;
    USE SIGNAL ;
    SHAPE ABUTMENT ;
    PORT
      LAYER M4 ;
      RECT 0.000 190.356 0.072 190.380 ;
    END
  END w0_wd_in[52]
  PIN w0_wd_in[53]
    DIRECTION INPUT ;
    USE SIGNAL ;
    SHAPE ABUTMENT ;
    PORT
      LAYER M4 ;
      RECT 0.000 191.412 0.072 191.436 ;
    END
  END w0_wd_in[53]
  PIN w0_wd_in[54]
    DIRECTION INPUT ;
    USE SIGNAL ;
    SHAPE ABUTMENT ;
    PORT
      LAYER M4 ;
      RECT 0.000 192.468 0.072 192.492 ;
    END
  END w0_wd_in[54]
  PIN w0_wd_in[55]
    DIRECTION INPUT ;
    USE SIGNAL ;
    SHAPE ABUTMENT ;
    PORT
      LAYER M4 ;
      RECT 0.000 193.524 0.072 193.548 ;
    END
  END w0_wd_in[55]
  PIN w0_wd_in[56]
    DIRECTION INPUT ;
    USE SIGNAL ;
    SHAPE ABUTMENT ;
    PORT
      LAYER M4 ;
      RECT 0.000 194.580 0.072 194.604 ;
    END
  END w0_wd_in[56]
  PIN w0_wd_in[57]
    DIRECTION INPUT ;
    USE SIGNAL ;
    SHAPE ABUTMENT ;
    PORT
      LAYER M4 ;
      RECT 0.000 195.636 0.072 195.660 ;
    END
  END w0_wd_in[57]
  PIN w0_wd_in[58]
    DIRECTION INPUT ;
    USE SIGNAL ;
    SHAPE ABUTMENT ;
    PORT
      LAYER M4 ;
      RECT 0.000 196.692 0.072 196.716 ;
    END
  END w0_wd_in[58]
  PIN w0_wd_in[59]
    DIRECTION INPUT ;
    USE SIGNAL ;
    SHAPE ABUTMENT ;
    PORT
      LAYER M4 ;
      RECT 0.000 197.748 0.072 197.772 ;
    END
  END w0_wd_in[59]
  PIN w0_wd_in[60]
    DIRECTION INPUT ;
    USE SIGNAL ;
    SHAPE ABUTMENT ;
    PORT
      LAYER M4 ;
      RECT 0.000 198.804 0.072 198.828 ;
    END
  END w0_wd_in[60]
  PIN w0_wd_in[61]
    DIRECTION INPUT ;
    USE SIGNAL ;
    SHAPE ABUTMENT ;
    PORT
      LAYER M4 ;
      RECT 0.000 199.860 0.072 199.884 ;
    END
  END w0_wd_in[61]
  PIN w0_wd_in[62]
    DIRECTION INPUT ;
    USE SIGNAL ;
    SHAPE ABUTMENT ;
    PORT
      LAYER M4 ;
      RECT 0.000 200.916 0.072 200.940 ;
    END
  END w0_wd_in[62]
  PIN w0_wd_in[63]
    DIRECTION INPUT ;
    USE SIGNAL ;
    SHAPE ABUTMENT ;
    PORT
      LAYER M4 ;
      RECT 0.000 201.972 0.072 201.996 ;
    END
  END w0_wd_in[63]
  PIN w0_wd_in[64]
    DIRECTION INPUT ;
    USE SIGNAL ;
    SHAPE ABUTMENT ;
    PORT
      LAYER M4 ;
      RECT 0.000 203.028 0.072 203.052 ;
    END
  END w0_wd_in[64]
  PIN w0_wd_in[65]
    DIRECTION INPUT ;
    USE SIGNAL ;
    SHAPE ABUTMENT ;
    PORT
      LAYER M4 ;
      RECT 0.000 204.084 0.072 204.108 ;
    END
  END w0_wd_in[65]
  PIN w0_wd_in[66]
    DIRECTION INPUT ;
    USE SIGNAL ;
    SHAPE ABUTMENT ;
    PORT
      LAYER M4 ;
      RECT 0.000 205.140 0.072 205.164 ;
    END
  END w0_wd_in[66]
  PIN w0_wd_in[67]
    DIRECTION INPUT ;
    USE SIGNAL ;
    SHAPE ABUTMENT ;
    PORT
      LAYER M4 ;
      RECT 0.000 206.196 0.072 206.220 ;
    END
  END w0_wd_in[67]
  PIN w0_wd_in[68]
    DIRECTION INPUT ;
    USE SIGNAL ;
    SHAPE ABUTMENT ;
    PORT
      LAYER M4 ;
      RECT 0.000 207.252 0.072 207.276 ;
    END
  END w0_wd_in[68]
  PIN w0_wd_in[69]
    DIRECTION INPUT ;
    USE SIGNAL ;
    SHAPE ABUTMENT ;
    PORT
      LAYER M4 ;
      RECT 0.000 208.308 0.072 208.332 ;
    END
  END w0_wd_in[69]
  PIN w0_wd_in[70]
    DIRECTION INPUT ;
    USE SIGNAL ;
    SHAPE ABUTMENT ;
    PORT
      LAYER M4 ;
      RECT 0.000 209.364 0.072 209.388 ;
    END
  END w0_wd_in[70]
  PIN w0_wd_in[71]
    DIRECTION INPUT ;
    USE SIGNAL ;
    SHAPE ABUTMENT ;
    PORT
      LAYER M4 ;
      RECT 0.000 210.420 0.072 210.444 ;
    END
  END w0_wd_in[71]
  PIN w0_wd_in[72]
    DIRECTION INPUT ;
    USE SIGNAL ;
    SHAPE ABUTMENT ;
    PORT
      LAYER M4 ;
      RECT 0.000 211.476 0.072 211.500 ;
    END
  END w0_wd_in[72]
  PIN w0_wd_in[73]
    DIRECTION INPUT ;
    USE SIGNAL ;
    SHAPE ABUTMENT ;
    PORT
      LAYER M4 ;
      RECT 0.000 212.532 0.072 212.556 ;
    END
  END w0_wd_in[73]
  PIN w0_wd_in[74]
    DIRECTION INPUT ;
    USE SIGNAL ;
    SHAPE ABUTMENT ;
    PORT
      LAYER M4 ;
      RECT 0.000 213.588 0.072 213.612 ;
    END
  END w0_wd_in[74]
  PIN w0_wd_in[75]
    DIRECTION INPUT ;
    USE SIGNAL ;
    SHAPE ABUTMENT ;
    PORT
      LAYER M4 ;
      RECT 0.000 214.644 0.072 214.668 ;
    END
  END w0_wd_in[75]
  PIN w0_wd_in[76]
    DIRECTION INPUT ;
    USE SIGNAL ;
    SHAPE ABUTMENT ;
    PORT
      LAYER M4 ;
      RECT 0.000 215.700 0.072 215.724 ;
    END
  END w0_wd_in[76]
  PIN w0_wd_in[77]
    DIRECTION INPUT ;
    USE SIGNAL ;
    SHAPE ABUTMENT ;
    PORT
      LAYER M4 ;
      RECT 0.000 216.756 0.072 216.780 ;
    END
  END w0_wd_in[77]
  PIN w0_wd_in[78]
    DIRECTION INPUT ;
    USE SIGNAL ;
    SHAPE ABUTMENT ;
    PORT
      LAYER M4 ;
      RECT 0.000 217.812 0.072 217.836 ;
    END
  END w0_wd_in[78]
  PIN w0_wd_in[79]
    DIRECTION INPUT ;
    USE SIGNAL ;
    SHAPE ABUTMENT ;
    PORT
      LAYER M4 ;
      RECT 0.000 218.868 0.072 218.892 ;
    END
  END w0_wd_in[79]
  PIN w0_wd_in[80]
    DIRECTION INPUT ;
    USE SIGNAL ;
    SHAPE ABUTMENT ;
    PORT
      LAYER M4 ;
      RECT 0.000 219.924 0.072 219.948 ;
    END
  END w0_wd_in[80]
  PIN w0_wd_in[81]
    DIRECTION INPUT ;
    USE SIGNAL ;
    SHAPE ABUTMENT ;
    PORT
      LAYER M4 ;
      RECT 0.000 220.980 0.072 221.004 ;
    END
  END w0_wd_in[81]
  PIN w0_wd_in[82]
    DIRECTION INPUT ;
    USE SIGNAL ;
    SHAPE ABUTMENT ;
    PORT
      LAYER M4 ;
      RECT 0.000 222.036 0.072 222.060 ;
    END
  END w0_wd_in[82]
  PIN w0_wd_in[83]
    DIRECTION INPUT ;
    USE SIGNAL ;
    SHAPE ABUTMENT ;
    PORT
      LAYER M4 ;
      RECT 0.000 223.092 0.072 223.116 ;
    END
  END w0_wd_in[83]
  PIN w0_wd_in[84]
    DIRECTION INPUT ;
    USE SIGNAL ;
    SHAPE ABUTMENT ;
    PORT
      LAYER M4 ;
      RECT 0.000 224.148 0.072 224.172 ;
    END
  END w0_wd_in[84]
  PIN w0_wd_in[85]
    DIRECTION INPUT ;
    USE SIGNAL ;
    SHAPE ABUTMENT ;
    PORT
      LAYER M4 ;
      RECT 0.000 225.204 0.072 225.228 ;
    END
  END w0_wd_in[85]
  PIN w0_wd_in[86]
    DIRECTION INPUT ;
    USE SIGNAL ;
    SHAPE ABUTMENT ;
    PORT
      LAYER M4 ;
      RECT 0.000 226.260 0.072 226.284 ;
    END
  END w0_wd_in[86]
  PIN w0_wd_in[87]
    DIRECTION INPUT ;
    USE SIGNAL ;
    SHAPE ABUTMENT ;
    PORT
      LAYER M4 ;
      RECT 0.000 227.316 0.072 227.340 ;
    END
  END w0_wd_in[87]
  PIN w0_wd_in[88]
    DIRECTION INPUT ;
    USE SIGNAL ;
    SHAPE ABUTMENT ;
    PORT
      LAYER M4 ;
      RECT 0.000 228.372 0.072 228.396 ;
    END
  END w0_wd_in[88]
  PIN w0_wd_in[89]
    DIRECTION INPUT ;
    USE SIGNAL ;
    SHAPE ABUTMENT ;
    PORT
      LAYER M4 ;
      RECT 0.000 229.428 0.072 229.452 ;
    END
  END w0_wd_in[89]
  PIN w0_wd_in[90]
    DIRECTION INPUT ;
    USE SIGNAL ;
    SHAPE ABUTMENT ;
    PORT
      LAYER M4 ;
      RECT 0.000 230.484 0.072 230.508 ;
    END
  END w0_wd_in[90]
  PIN w0_wd_in[91]
    DIRECTION INPUT ;
    USE SIGNAL ;
    SHAPE ABUTMENT ;
    PORT
      LAYER M4 ;
      RECT 0.000 231.540 0.072 231.564 ;
    END
  END w0_wd_in[91]
  PIN w0_wd_in[92]
    DIRECTION INPUT ;
    USE SIGNAL ;
    SHAPE ABUTMENT ;
    PORT
      LAYER M4 ;
      RECT 0.000 232.596 0.072 232.620 ;
    END
  END w0_wd_in[92]
  PIN w0_wd_in[93]
    DIRECTION INPUT ;
    USE SIGNAL ;
    SHAPE ABUTMENT ;
    PORT
      LAYER M4 ;
      RECT 0.000 233.652 0.072 233.676 ;
    END
  END w0_wd_in[93]
  PIN w0_wd_in[94]
    DIRECTION INPUT ;
    USE SIGNAL ;
    SHAPE ABUTMENT ;
    PORT
      LAYER M4 ;
      RECT 0.000 234.708 0.072 234.732 ;
    END
  END w0_wd_in[94]
  PIN w0_wd_in[95]
    DIRECTION INPUT ;
    USE SIGNAL ;
    SHAPE ABUTMENT ;
    PORT
      LAYER M4 ;
      RECT 0.000 235.764 0.072 235.788 ;
    END
  END w0_wd_in[95]
  PIN w0_wd_in[96]
    DIRECTION INPUT ;
    USE SIGNAL ;
    SHAPE ABUTMENT ;
    PORT
      LAYER M4 ;
      RECT 0.000 236.820 0.072 236.844 ;
    END
  END w0_wd_in[96]
  PIN w0_wd_in[97]
    DIRECTION INPUT ;
    USE SIGNAL ;
    SHAPE ABUTMENT ;
    PORT
      LAYER M4 ;
      RECT 0.000 237.876 0.072 237.900 ;
    END
  END w0_wd_in[97]
  PIN w0_wd_in[98]
    DIRECTION INPUT ;
    USE SIGNAL ;
    SHAPE ABUTMENT ;
    PORT
      LAYER M4 ;
      RECT 0.000 238.932 0.072 238.956 ;
    END
  END w0_wd_in[98]
  PIN w0_wd_in[99]
    DIRECTION INPUT ;
    USE SIGNAL ;
    SHAPE ABUTMENT ;
    PORT
      LAYER M4 ;
      RECT 0.000 239.988 0.072 240.012 ;
    END
  END w0_wd_in[99]
  PIN w0_wd_in[100]
    DIRECTION INPUT ;
    USE SIGNAL ;
    SHAPE ABUTMENT ;
    PORT
      LAYER M4 ;
      RECT 0.000 241.044 0.072 241.068 ;
    END
  END w0_wd_in[100]
  PIN w0_wd_in[101]
    DIRECTION INPUT ;
    USE SIGNAL ;
    SHAPE ABUTMENT ;
    PORT
      LAYER M4 ;
      RECT 0.000 242.100 0.072 242.124 ;
    END
  END w0_wd_in[101]
  PIN w0_wd_in[102]
    DIRECTION INPUT ;
    USE SIGNAL ;
    SHAPE ABUTMENT ;
    PORT
      LAYER M4 ;
      RECT 0.000 243.156 0.072 243.180 ;
    END
  END w0_wd_in[102]
  PIN w0_wd_in[103]
    DIRECTION INPUT ;
    USE SIGNAL ;
    SHAPE ABUTMENT ;
    PORT
      LAYER M4 ;
      RECT 0.000 244.212 0.072 244.236 ;
    END
  END w0_wd_in[103]
  PIN w0_wd_in[104]
    DIRECTION INPUT ;
    USE SIGNAL ;
    SHAPE ABUTMENT ;
    PORT
      LAYER M4 ;
      RECT 0.000 245.268 0.072 245.292 ;
    END
  END w0_wd_in[104]
  PIN w0_wd_in[105]
    DIRECTION INPUT ;
    USE SIGNAL ;
    SHAPE ABUTMENT ;
    PORT
      LAYER M4 ;
      RECT 0.000 246.324 0.072 246.348 ;
    END
  END w0_wd_in[105]
  PIN w0_wd_in[106]
    DIRECTION INPUT ;
    USE SIGNAL ;
    SHAPE ABUTMENT ;
    PORT
      LAYER M4 ;
      RECT 0.000 247.380 0.072 247.404 ;
    END
  END w0_wd_in[106]
  PIN w0_wd_in[107]
    DIRECTION INPUT ;
    USE SIGNAL ;
    SHAPE ABUTMENT ;
    PORT
      LAYER M4 ;
      RECT 0.000 248.436 0.072 248.460 ;
    END
  END w0_wd_in[107]
  PIN w0_wd_in[108]
    DIRECTION INPUT ;
    USE SIGNAL ;
    SHAPE ABUTMENT ;
    PORT
      LAYER M4 ;
      RECT 0.000 249.492 0.072 249.516 ;
    END
  END w0_wd_in[108]
  PIN w0_wd_in[109]
    DIRECTION INPUT ;
    USE SIGNAL ;
    SHAPE ABUTMENT ;
    PORT
      LAYER M4 ;
      RECT 0.000 250.548 0.072 250.572 ;
    END
  END w0_wd_in[109]
  PIN w0_wd_in[110]
    DIRECTION INPUT ;
    USE SIGNAL ;
    SHAPE ABUTMENT ;
    PORT
      LAYER M4 ;
      RECT 0.000 251.604 0.072 251.628 ;
    END
  END w0_wd_in[110]
  PIN w0_wd_in[111]
    DIRECTION INPUT ;
    USE SIGNAL ;
    SHAPE ABUTMENT ;
    PORT
      LAYER M4 ;
      RECT 0.000 252.660 0.072 252.684 ;
    END
  END w0_wd_in[111]
  PIN w0_wd_in[112]
    DIRECTION INPUT ;
    USE SIGNAL ;
    SHAPE ABUTMENT ;
    PORT
      LAYER M4 ;
      RECT 0.000 253.716 0.072 253.740 ;
    END
  END w0_wd_in[112]
  PIN w0_wd_in[113]
    DIRECTION INPUT ;
    USE SIGNAL ;
    SHAPE ABUTMENT ;
    PORT
      LAYER M4 ;
      RECT 0.000 254.772 0.072 254.796 ;
    END
  END w0_wd_in[113]
  PIN w0_wd_in[114]
    DIRECTION INPUT ;
    USE SIGNAL ;
    SHAPE ABUTMENT ;
    PORT
      LAYER M4 ;
      RECT 0.000 255.828 0.072 255.852 ;
    END
  END w0_wd_in[114]
  PIN w0_wd_in[115]
    DIRECTION INPUT ;
    USE SIGNAL ;
    SHAPE ABUTMENT ;
    PORT
      LAYER M4 ;
      RECT 0.000 256.884 0.072 256.908 ;
    END
  END w0_wd_in[115]
  PIN w0_wd_in[116]
    DIRECTION INPUT ;
    USE SIGNAL ;
    SHAPE ABUTMENT ;
    PORT
      LAYER M4 ;
      RECT 0.000 257.940 0.072 257.964 ;
    END
  END w0_wd_in[116]
  PIN w0_wd_in[117]
    DIRECTION INPUT ;
    USE SIGNAL ;
    SHAPE ABUTMENT ;
    PORT
      LAYER M4 ;
      RECT 0.000 258.996 0.072 259.020 ;
    END
  END w0_wd_in[117]
  PIN w0_wd_in[118]
    DIRECTION INPUT ;
    USE SIGNAL ;
    SHAPE ABUTMENT ;
    PORT
      LAYER M4 ;
      RECT 0.000 260.052 0.072 260.076 ;
    END
  END w0_wd_in[118]
  PIN w0_wd_in[119]
    DIRECTION INPUT ;
    USE SIGNAL ;
    SHAPE ABUTMENT ;
    PORT
      LAYER M4 ;
      RECT 0.000 261.108 0.072 261.132 ;
    END
  END w0_wd_in[119]
  PIN w0_wd_in[120]
    DIRECTION INPUT ;
    USE SIGNAL ;
    SHAPE ABUTMENT ;
    PORT
      LAYER M4 ;
      RECT 0.000 262.164 0.072 262.188 ;
    END
  END w0_wd_in[120]
  PIN w0_wd_in[121]
    DIRECTION INPUT ;
    USE SIGNAL ;
    SHAPE ABUTMENT ;
    PORT
      LAYER M4 ;
      RECT 0.000 263.220 0.072 263.244 ;
    END
  END w0_wd_in[121]
  PIN w0_wd_in[122]
    DIRECTION INPUT ;
    USE SIGNAL ;
    SHAPE ABUTMENT ;
    PORT
      LAYER M4 ;
      RECT 0.000 264.276 0.072 264.300 ;
    END
  END w0_wd_in[122]
  PIN w0_wd_in[123]
    DIRECTION INPUT ;
    USE SIGNAL ;
    SHAPE ABUTMENT ;
    PORT
      LAYER M4 ;
      RECT 0.000 265.332 0.072 265.356 ;
    END
  END w0_wd_in[123]
  PIN w0_wd_in[124]
    DIRECTION INPUT ;
    USE SIGNAL ;
    SHAPE ABUTMENT ;
    PORT
      LAYER M4 ;
      RECT 0.000 266.388 0.072 266.412 ;
    END
  END w0_wd_in[124]
  PIN w0_wd_in[125]
    DIRECTION INPUT ;
    USE SIGNAL ;
    SHAPE ABUTMENT ;
    PORT
      LAYER M4 ;
      RECT 0.000 267.444 0.072 267.468 ;
    END
  END w0_wd_in[125]
  PIN w0_wd_in[126]
    DIRECTION INPUT ;
    USE SIGNAL ;
    SHAPE ABUTMENT ;
    PORT
      LAYER M4 ;
      RECT 0.000 268.500 0.072 268.524 ;
    END
  END w0_wd_in[126]
  PIN w0_wd_in[127]
    DIRECTION INPUT ;
    USE SIGNAL ;
    SHAPE ABUTMENT ;
    PORT
      LAYER M4 ;
      RECT 0.000 269.556 0.072 269.580 ;
    END
  END w0_wd_in[127]
  PIN w0_wd_in[128]
    DIRECTION INPUT ;
    USE SIGNAL ;
    SHAPE ABUTMENT ;
    PORT
      LAYER M4 ;
      RECT 226.642 135.444 226.714 135.468 ;
    END
  END w0_wd_in[128]
  PIN w0_wd_in[129]
    DIRECTION INPUT ;
    USE SIGNAL ;
    SHAPE ABUTMENT ;
    PORT
      LAYER M4 ;
      RECT 226.642 136.500 226.714 136.524 ;
    END
  END w0_wd_in[129]
  PIN w0_wd_in[130]
    DIRECTION INPUT ;
    USE SIGNAL ;
    SHAPE ABUTMENT ;
    PORT
      LAYER M4 ;
      RECT 226.642 137.556 226.714 137.580 ;
    END
  END w0_wd_in[130]
  PIN w0_wd_in[131]
    DIRECTION INPUT ;
    USE SIGNAL ;
    SHAPE ABUTMENT ;
    PORT
      LAYER M4 ;
      RECT 226.642 138.612 226.714 138.636 ;
    END
  END w0_wd_in[131]
  PIN w0_wd_in[132]
    DIRECTION INPUT ;
    USE SIGNAL ;
    SHAPE ABUTMENT ;
    PORT
      LAYER M4 ;
      RECT 226.642 139.668 226.714 139.692 ;
    END
  END w0_wd_in[132]
  PIN w0_wd_in[133]
    DIRECTION INPUT ;
    USE SIGNAL ;
    SHAPE ABUTMENT ;
    PORT
      LAYER M4 ;
      RECT 226.642 140.724 226.714 140.748 ;
    END
  END w0_wd_in[133]
  PIN w0_wd_in[134]
    DIRECTION INPUT ;
    USE SIGNAL ;
    SHAPE ABUTMENT ;
    PORT
      LAYER M4 ;
      RECT 226.642 141.780 226.714 141.804 ;
    END
  END w0_wd_in[134]
  PIN w0_wd_in[135]
    DIRECTION INPUT ;
    USE SIGNAL ;
    SHAPE ABUTMENT ;
    PORT
      LAYER M4 ;
      RECT 226.642 142.836 226.714 142.860 ;
    END
  END w0_wd_in[135]
  PIN w0_wd_in[136]
    DIRECTION INPUT ;
    USE SIGNAL ;
    SHAPE ABUTMENT ;
    PORT
      LAYER M4 ;
      RECT 226.642 143.892 226.714 143.916 ;
    END
  END w0_wd_in[136]
  PIN w0_wd_in[137]
    DIRECTION INPUT ;
    USE SIGNAL ;
    SHAPE ABUTMENT ;
    PORT
      LAYER M4 ;
      RECT 226.642 144.948 226.714 144.972 ;
    END
  END w0_wd_in[137]
  PIN w0_wd_in[138]
    DIRECTION INPUT ;
    USE SIGNAL ;
    SHAPE ABUTMENT ;
    PORT
      LAYER M4 ;
      RECT 226.642 146.004 226.714 146.028 ;
    END
  END w0_wd_in[138]
  PIN w0_wd_in[139]
    DIRECTION INPUT ;
    USE SIGNAL ;
    SHAPE ABUTMENT ;
    PORT
      LAYER M4 ;
      RECT 226.642 147.060 226.714 147.084 ;
    END
  END w0_wd_in[139]
  PIN w0_wd_in[140]
    DIRECTION INPUT ;
    USE SIGNAL ;
    SHAPE ABUTMENT ;
    PORT
      LAYER M4 ;
      RECT 226.642 148.116 226.714 148.140 ;
    END
  END w0_wd_in[140]
  PIN w0_wd_in[141]
    DIRECTION INPUT ;
    USE SIGNAL ;
    SHAPE ABUTMENT ;
    PORT
      LAYER M4 ;
      RECT 226.642 149.172 226.714 149.196 ;
    END
  END w0_wd_in[141]
  PIN w0_wd_in[142]
    DIRECTION INPUT ;
    USE SIGNAL ;
    SHAPE ABUTMENT ;
    PORT
      LAYER M4 ;
      RECT 226.642 150.228 226.714 150.252 ;
    END
  END w0_wd_in[142]
  PIN w0_wd_in[143]
    DIRECTION INPUT ;
    USE SIGNAL ;
    SHAPE ABUTMENT ;
    PORT
      LAYER M4 ;
      RECT 226.642 151.284 226.714 151.308 ;
    END
  END w0_wd_in[143]
  PIN w0_wd_in[144]
    DIRECTION INPUT ;
    USE SIGNAL ;
    SHAPE ABUTMENT ;
    PORT
      LAYER M4 ;
      RECT 226.642 152.340 226.714 152.364 ;
    END
  END w0_wd_in[144]
  PIN w0_wd_in[145]
    DIRECTION INPUT ;
    USE SIGNAL ;
    SHAPE ABUTMENT ;
    PORT
      LAYER M4 ;
      RECT 226.642 153.396 226.714 153.420 ;
    END
  END w0_wd_in[145]
  PIN w0_wd_in[146]
    DIRECTION INPUT ;
    USE SIGNAL ;
    SHAPE ABUTMENT ;
    PORT
      LAYER M4 ;
      RECT 226.642 154.452 226.714 154.476 ;
    END
  END w0_wd_in[146]
  PIN w0_wd_in[147]
    DIRECTION INPUT ;
    USE SIGNAL ;
    SHAPE ABUTMENT ;
    PORT
      LAYER M4 ;
      RECT 226.642 155.508 226.714 155.532 ;
    END
  END w0_wd_in[147]
  PIN w0_wd_in[148]
    DIRECTION INPUT ;
    USE SIGNAL ;
    SHAPE ABUTMENT ;
    PORT
      LAYER M4 ;
      RECT 226.642 156.564 226.714 156.588 ;
    END
  END w0_wd_in[148]
  PIN w0_wd_in[149]
    DIRECTION INPUT ;
    USE SIGNAL ;
    SHAPE ABUTMENT ;
    PORT
      LAYER M4 ;
      RECT 226.642 157.620 226.714 157.644 ;
    END
  END w0_wd_in[149]
  PIN w0_wd_in[150]
    DIRECTION INPUT ;
    USE SIGNAL ;
    SHAPE ABUTMENT ;
    PORT
      LAYER M4 ;
      RECT 226.642 158.676 226.714 158.700 ;
    END
  END w0_wd_in[150]
  PIN w0_wd_in[151]
    DIRECTION INPUT ;
    USE SIGNAL ;
    SHAPE ABUTMENT ;
    PORT
      LAYER M4 ;
      RECT 226.642 159.732 226.714 159.756 ;
    END
  END w0_wd_in[151]
  PIN w0_wd_in[152]
    DIRECTION INPUT ;
    USE SIGNAL ;
    SHAPE ABUTMENT ;
    PORT
      LAYER M4 ;
      RECT 226.642 160.788 226.714 160.812 ;
    END
  END w0_wd_in[152]
  PIN w0_wd_in[153]
    DIRECTION INPUT ;
    USE SIGNAL ;
    SHAPE ABUTMENT ;
    PORT
      LAYER M4 ;
      RECT 226.642 161.844 226.714 161.868 ;
    END
  END w0_wd_in[153]
  PIN w0_wd_in[154]
    DIRECTION INPUT ;
    USE SIGNAL ;
    SHAPE ABUTMENT ;
    PORT
      LAYER M4 ;
      RECT 226.642 162.900 226.714 162.924 ;
    END
  END w0_wd_in[154]
  PIN w0_wd_in[155]
    DIRECTION INPUT ;
    USE SIGNAL ;
    SHAPE ABUTMENT ;
    PORT
      LAYER M4 ;
      RECT 226.642 163.956 226.714 163.980 ;
    END
  END w0_wd_in[155]
  PIN w0_wd_in[156]
    DIRECTION INPUT ;
    USE SIGNAL ;
    SHAPE ABUTMENT ;
    PORT
      LAYER M4 ;
      RECT 226.642 165.012 226.714 165.036 ;
    END
  END w0_wd_in[156]
  PIN w0_wd_in[157]
    DIRECTION INPUT ;
    USE SIGNAL ;
    SHAPE ABUTMENT ;
    PORT
      LAYER M4 ;
      RECT 226.642 166.068 226.714 166.092 ;
    END
  END w0_wd_in[157]
  PIN w0_wd_in[158]
    DIRECTION INPUT ;
    USE SIGNAL ;
    SHAPE ABUTMENT ;
    PORT
      LAYER M4 ;
      RECT 226.642 167.124 226.714 167.148 ;
    END
  END w0_wd_in[158]
  PIN w0_wd_in[159]
    DIRECTION INPUT ;
    USE SIGNAL ;
    SHAPE ABUTMENT ;
    PORT
      LAYER M4 ;
      RECT 226.642 168.180 226.714 168.204 ;
    END
  END w0_wd_in[159]
  PIN w0_wd_in[160]
    DIRECTION INPUT ;
    USE SIGNAL ;
    SHAPE ABUTMENT ;
    PORT
      LAYER M4 ;
      RECT 226.642 169.236 226.714 169.260 ;
    END
  END w0_wd_in[160]
  PIN w0_wd_in[161]
    DIRECTION INPUT ;
    USE SIGNAL ;
    SHAPE ABUTMENT ;
    PORT
      LAYER M4 ;
      RECT 226.642 170.292 226.714 170.316 ;
    END
  END w0_wd_in[161]
  PIN w0_wd_in[162]
    DIRECTION INPUT ;
    USE SIGNAL ;
    SHAPE ABUTMENT ;
    PORT
      LAYER M4 ;
      RECT 226.642 171.348 226.714 171.372 ;
    END
  END w0_wd_in[162]
  PIN w0_wd_in[163]
    DIRECTION INPUT ;
    USE SIGNAL ;
    SHAPE ABUTMENT ;
    PORT
      LAYER M4 ;
      RECT 226.642 172.404 226.714 172.428 ;
    END
  END w0_wd_in[163]
  PIN w0_wd_in[164]
    DIRECTION INPUT ;
    USE SIGNAL ;
    SHAPE ABUTMENT ;
    PORT
      LAYER M4 ;
      RECT 226.642 173.460 226.714 173.484 ;
    END
  END w0_wd_in[164]
  PIN w0_wd_in[165]
    DIRECTION INPUT ;
    USE SIGNAL ;
    SHAPE ABUTMENT ;
    PORT
      LAYER M4 ;
      RECT 226.642 174.516 226.714 174.540 ;
    END
  END w0_wd_in[165]
  PIN w0_wd_in[166]
    DIRECTION INPUT ;
    USE SIGNAL ;
    SHAPE ABUTMENT ;
    PORT
      LAYER M4 ;
      RECT 226.642 175.572 226.714 175.596 ;
    END
  END w0_wd_in[166]
  PIN w0_wd_in[167]
    DIRECTION INPUT ;
    USE SIGNAL ;
    SHAPE ABUTMENT ;
    PORT
      LAYER M4 ;
      RECT 226.642 176.628 226.714 176.652 ;
    END
  END w0_wd_in[167]
  PIN w0_wd_in[168]
    DIRECTION INPUT ;
    USE SIGNAL ;
    SHAPE ABUTMENT ;
    PORT
      LAYER M4 ;
      RECT 226.642 177.684 226.714 177.708 ;
    END
  END w0_wd_in[168]
  PIN w0_wd_in[169]
    DIRECTION INPUT ;
    USE SIGNAL ;
    SHAPE ABUTMENT ;
    PORT
      LAYER M4 ;
      RECT 226.642 178.740 226.714 178.764 ;
    END
  END w0_wd_in[169]
  PIN w0_wd_in[170]
    DIRECTION INPUT ;
    USE SIGNAL ;
    SHAPE ABUTMENT ;
    PORT
      LAYER M4 ;
      RECT 226.642 179.796 226.714 179.820 ;
    END
  END w0_wd_in[170]
  PIN w0_wd_in[171]
    DIRECTION INPUT ;
    USE SIGNAL ;
    SHAPE ABUTMENT ;
    PORT
      LAYER M4 ;
      RECT 226.642 180.852 226.714 180.876 ;
    END
  END w0_wd_in[171]
  PIN w0_wd_in[172]
    DIRECTION INPUT ;
    USE SIGNAL ;
    SHAPE ABUTMENT ;
    PORT
      LAYER M4 ;
      RECT 226.642 181.908 226.714 181.932 ;
    END
  END w0_wd_in[172]
  PIN w0_wd_in[173]
    DIRECTION INPUT ;
    USE SIGNAL ;
    SHAPE ABUTMENT ;
    PORT
      LAYER M4 ;
      RECT 226.642 182.964 226.714 182.988 ;
    END
  END w0_wd_in[173]
  PIN w0_wd_in[174]
    DIRECTION INPUT ;
    USE SIGNAL ;
    SHAPE ABUTMENT ;
    PORT
      LAYER M4 ;
      RECT 226.642 184.020 226.714 184.044 ;
    END
  END w0_wd_in[174]
  PIN w0_wd_in[175]
    DIRECTION INPUT ;
    USE SIGNAL ;
    SHAPE ABUTMENT ;
    PORT
      LAYER M4 ;
      RECT 226.642 185.076 226.714 185.100 ;
    END
  END w0_wd_in[175]
  PIN w0_wd_in[176]
    DIRECTION INPUT ;
    USE SIGNAL ;
    SHAPE ABUTMENT ;
    PORT
      LAYER M4 ;
      RECT 226.642 186.132 226.714 186.156 ;
    END
  END w0_wd_in[176]
  PIN w0_wd_in[177]
    DIRECTION INPUT ;
    USE SIGNAL ;
    SHAPE ABUTMENT ;
    PORT
      LAYER M4 ;
      RECT 226.642 187.188 226.714 187.212 ;
    END
  END w0_wd_in[177]
  PIN w0_wd_in[178]
    DIRECTION INPUT ;
    USE SIGNAL ;
    SHAPE ABUTMENT ;
    PORT
      LAYER M4 ;
      RECT 226.642 188.244 226.714 188.268 ;
    END
  END w0_wd_in[178]
  PIN w0_wd_in[179]
    DIRECTION INPUT ;
    USE SIGNAL ;
    SHAPE ABUTMENT ;
    PORT
      LAYER M4 ;
      RECT 226.642 189.300 226.714 189.324 ;
    END
  END w0_wd_in[179]
  PIN w0_wd_in[180]
    DIRECTION INPUT ;
    USE SIGNAL ;
    SHAPE ABUTMENT ;
    PORT
      LAYER M4 ;
      RECT 226.642 190.356 226.714 190.380 ;
    END
  END w0_wd_in[180]
  PIN w0_wd_in[181]
    DIRECTION INPUT ;
    USE SIGNAL ;
    SHAPE ABUTMENT ;
    PORT
      LAYER M4 ;
      RECT 226.642 191.412 226.714 191.436 ;
    END
  END w0_wd_in[181]
  PIN w0_wd_in[182]
    DIRECTION INPUT ;
    USE SIGNAL ;
    SHAPE ABUTMENT ;
    PORT
      LAYER M4 ;
      RECT 226.642 192.468 226.714 192.492 ;
    END
  END w0_wd_in[182]
  PIN w0_wd_in[183]
    DIRECTION INPUT ;
    USE SIGNAL ;
    SHAPE ABUTMENT ;
    PORT
      LAYER M4 ;
      RECT 226.642 193.524 226.714 193.548 ;
    END
  END w0_wd_in[183]
  PIN w0_wd_in[184]
    DIRECTION INPUT ;
    USE SIGNAL ;
    SHAPE ABUTMENT ;
    PORT
      LAYER M4 ;
      RECT 226.642 194.580 226.714 194.604 ;
    END
  END w0_wd_in[184]
  PIN w0_wd_in[185]
    DIRECTION INPUT ;
    USE SIGNAL ;
    SHAPE ABUTMENT ;
    PORT
      LAYER M4 ;
      RECT 226.642 195.636 226.714 195.660 ;
    END
  END w0_wd_in[185]
  PIN w0_wd_in[186]
    DIRECTION INPUT ;
    USE SIGNAL ;
    SHAPE ABUTMENT ;
    PORT
      LAYER M4 ;
      RECT 226.642 196.692 226.714 196.716 ;
    END
  END w0_wd_in[186]
  PIN w0_wd_in[187]
    DIRECTION INPUT ;
    USE SIGNAL ;
    SHAPE ABUTMENT ;
    PORT
      LAYER M4 ;
      RECT 226.642 197.748 226.714 197.772 ;
    END
  END w0_wd_in[187]
  PIN w0_wd_in[188]
    DIRECTION INPUT ;
    USE SIGNAL ;
    SHAPE ABUTMENT ;
    PORT
      LAYER M4 ;
      RECT 226.642 198.804 226.714 198.828 ;
    END
  END w0_wd_in[188]
  PIN w0_wd_in[189]
    DIRECTION INPUT ;
    USE SIGNAL ;
    SHAPE ABUTMENT ;
    PORT
      LAYER M4 ;
      RECT 226.642 199.860 226.714 199.884 ;
    END
  END w0_wd_in[189]
  PIN w0_wd_in[190]
    DIRECTION INPUT ;
    USE SIGNAL ;
    SHAPE ABUTMENT ;
    PORT
      LAYER M4 ;
      RECT 226.642 200.916 226.714 200.940 ;
    END
  END w0_wd_in[190]
  PIN w0_wd_in[191]
    DIRECTION INPUT ;
    USE SIGNAL ;
    SHAPE ABUTMENT ;
    PORT
      LAYER M4 ;
      RECT 226.642 201.972 226.714 201.996 ;
    END
  END w0_wd_in[191]
  PIN w0_wd_in[192]
    DIRECTION INPUT ;
    USE SIGNAL ;
    SHAPE ABUTMENT ;
    PORT
      LAYER M4 ;
      RECT 226.642 203.028 226.714 203.052 ;
    END
  END w0_wd_in[192]
  PIN w0_wd_in[193]
    DIRECTION INPUT ;
    USE SIGNAL ;
    SHAPE ABUTMENT ;
    PORT
      LAYER M4 ;
      RECT 226.642 204.084 226.714 204.108 ;
    END
  END w0_wd_in[193]
  PIN w0_wd_in[194]
    DIRECTION INPUT ;
    USE SIGNAL ;
    SHAPE ABUTMENT ;
    PORT
      LAYER M4 ;
      RECT 226.642 205.140 226.714 205.164 ;
    END
  END w0_wd_in[194]
  PIN w0_wd_in[195]
    DIRECTION INPUT ;
    USE SIGNAL ;
    SHAPE ABUTMENT ;
    PORT
      LAYER M4 ;
      RECT 226.642 206.196 226.714 206.220 ;
    END
  END w0_wd_in[195]
  PIN w0_wd_in[196]
    DIRECTION INPUT ;
    USE SIGNAL ;
    SHAPE ABUTMENT ;
    PORT
      LAYER M4 ;
      RECT 226.642 207.252 226.714 207.276 ;
    END
  END w0_wd_in[196]
  PIN w0_wd_in[197]
    DIRECTION INPUT ;
    USE SIGNAL ;
    SHAPE ABUTMENT ;
    PORT
      LAYER M4 ;
      RECT 226.642 208.308 226.714 208.332 ;
    END
  END w0_wd_in[197]
  PIN w0_wd_in[198]
    DIRECTION INPUT ;
    USE SIGNAL ;
    SHAPE ABUTMENT ;
    PORT
      LAYER M4 ;
      RECT 226.642 209.364 226.714 209.388 ;
    END
  END w0_wd_in[198]
  PIN w0_wd_in[199]
    DIRECTION INPUT ;
    USE SIGNAL ;
    SHAPE ABUTMENT ;
    PORT
      LAYER M4 ;
      RECT 226.642 210.420 226.714 210.444 ;
    END
  END w0_wd_in[199]
  PIN w0_wd_in[200]
    DIRECTION INPUT ;
    USE SIGNAL ;
    SHAPE ABUTMENT ;
    PORT
      LAYER M4 ;
      RECT 226.642 211.476 226.714 211.500 ;
    END
  END w0_wd_in[200]
  PIN w0_wd_in[201]
    DIRECTION INPUT ;
    USE SIGNAL ;
    SHAPE ABUTMENT ;
    PORT
      LAYER M4 ;
      RECT 226.642 212.532 226.714 212.556 ;
    END
  END w0_wd_in[201]
  PIN w0_wd_in[202]
    DIRECTION INPUT ;
    USE SIGNAL ;
    SHAPE ABUTMENT ;
    PORT
      LAYER M4 ;
      RECT 226.642 213.588 226.714 213.612 ;
    END
  END w0_wd_in[202]
  PIN w0_wd_in[203]
    DIRECTION INPUT ;
    USE SIGNAL ;
    SHAPE ABUTMENT ;
    PORT
      LAYER M4 ;
      RECT 226.642 214.644 226.714 214.668 ;
    END
  END w0_wd_in[203]
  PIN w0_wd_in[204]
    DIRECTION INPUT ;
    USE SIGNAL ;
    SHAPE ABUTMENT ;
    PORT
      LAYER M4 ;
      RECT 226.642 215.700 226.714 215.724 ;
    END
  END w0_wd_in[204]
  PIN w0_wd_in[205]
    DIRECTION INPUT ;
    USE SIGNAL ;
    SHAPE ABUTMENT ;
    PORT
      LAYER M4 ;
      RECT 226.642 216.756 226.714 216.780 ;
    END
  END w0_wd_in[205]
  PIN w0_wd_in[206]
    DIRECTION INPUT ;
    USE SIGNAL ;
    SHAPE ABUTMENT ;
    PORT
      LAYER M4 ;
      RECT 226.642 217.812 226.714 217.836 ;
    END
  END w0_wd_in[206]
  PIN w0_wd_in[207]
    DIRECTION INPUT ;
    USE SIGNAL ;
    SHAPE ABUTMENT ;
    PORT
      LAYER M4 ;
      RECT 226.642 218.868 226.714 218.892 ;
    END
  END w0_wd_in[207]
  PIN w0_wd_in[208]
    DIRECTION INPUT ;
    USE SIGNAL ;
    SHAPE ABUTMENT ;
    PORT
      LAYER M4 ;
      RECT 226.642 219.924 226.714 219.948 ;
    END
  END w0_wd_in[208]
  PIN w0_wd_in[209]
    DIRECTION INPUT ;
    USE SIGNAL ;
    SHAPE ABUTMENT ;
    PORT
      LAYER M4 ;
      RECT 226.642 220.980 226.714 221.004 ;
    END
  END w0_wd_in[209]
  PIN w0_wd_in[210]
    DIRECTION INPUT ;
    USE SIGNAL ;
    SHAPE ABUTMENT ;
    PORT
      LAYER M4 ;
      RECT 226.642 222.036 226.714 222.060 ;
    END
  END w0_wd_in[210]
  PIN w0_wd_in[211]
    DIRECTION INPUT ;
    USE SIGNAL ;
    SHAPE ABUTMENT ;
    PORT
      LAYER M4 ;
      RECT 226.642 223.092 226.714 223.116 ;
    END
  END w0_wd_in[211]
  PIN w0_wd_in[212]
    DIRECTION INPUT ;
    USE SIGNAL ;
    SHAPE ABUTMENT ;
    PORT
      LAYER M4 ;
      RECT 226.642 224.148 226.714 224.172 ;
    END
  END w0_wd_in[212]
  PIN w0_wd_in[213]
    DIRECTION INPUT ;
    USE SIGNAL ;
    SHAPE ABUTMENT ;
    PORT
      LAYER M4 ;
      RECT 226.642 225.204 226.714 225.228 ;
    END
  END w0_wd_in[213]
  PIN w0_wd_in[214]
    DIRECTION INPUT ;
    USE SIGNAL ;
    SHAPE ABUTMENT ;
    PORT
      LAYER M4 ;
      RECT 226.642 226.260 226.714 226.284 ;
    END
  END w0_wd_in[214]
  PIN w0_wd_in[215]
    DIRECTION INPUT ;
    USE SIGNAL ;
    SHAPE ABUTMENT ;
    PORT
      LAYER M4 ;
      RECT 226.642 227.316 226.714 227.340 ;
    END
  END w0_wd_in[215]
  PIN w0_wd_in[216]
    DIRECTION INPUT ;
    USE SIGNAL ;
    SHAPE ABUTMENT ;
    PORT
      LAYER M4 ;
      RECT 226.642 228.372 226.714 228.396 ;
    END
  END w0_wd_in[216]
  PIN w0_wd_in[217]
    DIRECTION INPUT ;
    USE SIGNAL ;
    SHAPE ABUTMENT ;
    PORT
      LAYER M4 ;
      RECT 226.642 229.428 226.714 229.452 ;
    END
  END w0_wd_in[217]
  PIN w0_wd_in[218]
    DIRECTION INPUT ;
    USE SIGNAL ;
    SHAPE ABUTMENT ;
    PORT
      LAYER M4 ;
      RECT 226.642 230.484 226.714 230.508 ;
    END
  END w0_wd_in[218]
  PIN w0_wd_in[219]
    DIRECTION INPUT ;
    USE SIGNAL ;
    SHAPE ABUTMENT ;
    PORT
      LAYER M4 ;
      RECT 226.642 231.540 226.714 231.564 ;
    END
  END w0_wd_in[219]
  PIN w0_wd_in[220]
    DIRECTION INPUT ;
    USE SIGNAL ;
    SHAPE ABUTMENT ;
    PORT
      LAYER M4 ;
      RECT 226.642 232.596 226.714 232.620 ;
    END
  END w0_wd_in[220]
  PIN w0_wd_in[221]
    DIRECTION INPUT ;
    USE SIGNAL ;
    SHAPE ABUTMENT ;
    PORT
      LAYER M4 ;
      RECT 226.642 233.652 226.714 233.676 ;
    END
  END w0_wd_in[221]
  PIN w0_wd_in[222]
    DIRECTION INPUT ;
    USE SIGNAL ;
    SHAPE ABUTMENT ;
    PORT
      LAYER M4 ;
      RECT 226.642 234.708 226.714 234.732 ;
    END
  END w0_wd_in[222]
  PIN w0_wd_in[223]
    DIRECTION INPUT ;
    USE SIGNAL ;
    SHAPE ABUTMENT ;
    PORT
      LAYER M4 ;
      RECT 226.642 235.764 226.714 235.788 ;
    END
  END w0_wd_in[223]
  PIN w0_wd_in[224]
    DIRECTION INPUT ;
    USE SIGNAL ;
    SHAPE ABUTMENT ;
    PORT
      LAYER M4 ;
      RECT 226.642 236.820 226.714 236.844 ;
    END
  END w0_wd_in[224]
  PIN w0_wd_in[225]
    DIRECTION INPUT ;
    USE SIGNAL ;
    SHAPE ABUTMENT ;
    PORT
      LAYER M4 ;
      RECT 226.642 237.876 226.714 237.900 ;
    END
  END w0_wd_in[225]
  PIN w0_wd_in[226]
    DIRECTION INPUT ;
    USE SIGNAL ;
    SHAPE ABUTMENT ;
    PORT
      LAYER M4 ;
      RECT 226.642 238.932 226.714 238.956 ;
    END
  END w0_wd_in[226]
  PIN w0_wd_in[227]
    DIRECTION INPUT ;
    USE SIGNAL ;
    SHAPE ABUTMENT ;
    PORT
      LAYER M4 ;
      RECT 226.642 239.988 226.714 240.012 ;
    END
  END w0_wd_in[227]
  PIN w0_wd_in[228]
    DIRECTION INPUT ;
    USE SIGNAL ;
    SHAPE ABUTMENT ;
    PORT
      LAYER M4 ;
      RECT 226.642 241.044 226.714 241.068 ;
    END
  END w0_wd_in[228]
  PIN w0_wd_in[229]
    DIRECTION INPUT ;
    USE SIGNAL ;
    SHAPE ABUTMENT ;
    PORT
      LAYER M4 ;
      RECT 226.642 242.100 226.714 242.124 ;
    END
  END w0_wd_in[229]
  PIN w0_wd_in[230]
    DIRECTION INPUT ;
    USE SIGNAL ;
    SHAPE ABUTMENT ;
    PORT
      LAYER M4 ;
      RECT 226.642 243.156 226.714 243.180 ;
    END
  END w0_wd_in[230]
  PIN w0_wd_in[231]
    DIRECTION INPUT ;
    USE SIGNAL ;
    SHAPE ABUTMENT ;
    PORT
      LAYER M4 ;
      RECT 226.642 244.212 226.714 244.236 ;
    END
  END w0_wd_in[231]
  PIN w0_wd_in[232]
    DIRECTION INPUT ;
    USE SIGNAL ;
    SHAPE ABUTMENT ;
    PORT
      LAYER M4 ;
      RECT 226.642 245.268 226.714 245.292 ;
    END
  END w0_wd_in[232]
  PIN w0_wd_in[233]
    DIRECTION INPUT ;
    USE SIGNAL ;
    SHAPE ABUTMENT ;
    PORT
      LAYER M4 ;
      RECT 226.642 246.324 226.714 246.348 ;
    END
  END w0_wd_in[233]
  PIN w0_wd_in[234]
    DIRECTION INPUT ;
    USE SIGNAL ;
    SHAPE ABUTMENT ;
    PORT
      LAYER M4 ;
      RECT 226.642 247.380 226.714 247.404 ;
    END
  END w0_wd_in[234]
  PIN w0_wd_in[235]
    DIRECTION INPUT ;
    USE SIGNAL ;
    SHAPE ABUTMENT ;
    PORT
      LAYER M4 ;
      RECT 226.642 248.436 226.714 248.460 ;
    END
  END w0_wd_in[235]
  PIN w0_wd_in[236]
    DIRECTION INPUT ;
    USE SIGNAL ;
    SHAPE ABUTMENT ;
    PORT
      LAYER M4 ;
      RECT 226.642 249.492 226.714 249.516 ;
    END
  END w0_wd_in[236]
  PIN w0_wd_in[237]
    DIRECTION INPUT ;
    USE SIGNAL ;
    SHAPE ABUTMENT ;
    PORT
      LAYER M4 ;
      RECT 226.642 250.548 226.714 250.572 ;
    END
  END w0_wd_in[237]
  PIN w0_wd_in[238]
    DIRECTION INPUT ;
    USE SIGNAL ;
    SHAPE ABUTMENT ;
    PORT
      LAYER M4 ;
      RECT 226.642 251.604 226.714 251.628 ;
    END
  END w0_wd_in[238]
  PIN w0_wd_in[239]
    DIRECTION INPUT ;
    USE SIGNAL ;
    SHAPE ABUTMENT ;
    PORT
      LAYER M4 ;
      RECT 226.642 252.660 226.714 252.684 ;
    END
  END w0_wd_in[239]
  PIN w0_wd_in[240]
    DIRECTION INPUT ;
    USE SIGNAL ;
    SHAPE ABUTMENT ;
    PORT
      LAYER M4 ;
      RECT 226.642 253.716 226.714 253.740 ;
    END
  END w0_wd_in[240]
  PIN w0_wd_in[241]
    DIRECTION INPUT ;
    USE SIGNAL ;
    SHAPE ABUTMENT ;
    PORT
      LAYER M4 ;
      RECT 226.642 254.772 226.714 254.796 ;
    END
  END w0_wd_in[241]
  PIN w0_wd_in[242]
    DIRECTION INPUT ;
    USE SIGNAL ;
    SHAPE ABUTMENT ;
    PORT
      LAYER M4 ;
      RECT 226.642 255.828 226.714 255.852 ;
    END
  END w0_wd_in[242]
  PIN w0_wd_in[243]
    DIRECTION INPUT ;
    USE SIGNAL ;
    SHAPE ABUTMENT ;
    PORT
      LAYER M4 ;
      RECT 226.642 256.884 226.714 256.908 ;
    END
  END w0_wd_in[243]
  PIN w0_wd_in[244]
    DIRECTION INPUT ;
    USE SIGNAL ;
    SHAPE ABUTMENT ;
    PORT
      LAYER M4 ;
      RECT 226.642 257.940 226.714 257.964 ;
    END
  END w0_wd_in[244]
  PIN w0_wd_in[245]
    DIRECTION INPUT ;
    USE SIGNAL ;
    SHAPE ABUTMENT ;
    PORT
      LAYER M4 ;
      RECT 226.642 258.996 226.714 259.020 ;
    END
  END w0_wd_in[245]
  PIN w0_wd_in[246]
    DIRECTION INPUT ;
    USE SIGNAL ;
    SHAPE ABUTMENT ;
    PORT
      LAYER M4 ;
      RECT 226.642 260.052 226.714 260.076 ;
    END
  END w0_wd_in[246]
  PIN w0_wd_in[247]
    DIRECTION INPUT ;
    USE SIGNAL ;
    SHAPE ABUTMENT ;
    PORT
      LAYER M4 ;
      RECT 226.642 261.108 226.714 261.132 ;
    END
  END w0_wd_in[247]
  PIN w0_wd_in[248]
    DIRECTION INPUT ;
    USE SIGNAL ;
    SHAPE ABUTMENT ;
    PORT
      LAYER M4 ;
      RECT 226.642 262.164 226.714 262.188 ;
    END
  END w0_wd_in[248]
  PIN w0_wd_in[249]
    DIRECTION INPUT ;
    USE SIGNAL ;
    SHAPE ABUTMENT ;
    PORT
      LAYER M4 ;
      RECT 226.642 263.220 226.714 263.244 ;
    END
  END w0_wd_in[249]
  PIN w0_wd_in[250]
    DIRECTION INPUT ;
    USE SIGNAL ;
    SHAPE ABUTMENT ;
    PORT
      LAYER M4 ;
      RECT 226.642 264.276 226.714 264.300 ;
    END
  END w0_wd_in[250]
  PIN w0_wd_in[251]
    DIRECTION INPUT ;
    USE SIGNAL ;
    SHAPE ABUTMENT ;
    PORT
      LAYER M4 ;
      RECT 226.642 265.332 226.714 265.356 ;
    END
  END w0_wd_in[251]
  PIN w0_wd_in[252]
    DIRECTION INPUT ;
    USE SIGNAL ;
    SHAPE ABUTMENT ;
    PORT
      LAYER M4 ;
      RECT 226.642 266.388 226.714 266.412 ;
    END
  END w0_wd_in[252]
  PIN w0_wd_in[253]
    DIRECTION INPUT ;
    USE SIGNAL ;
    SHAPE ABUTMENT ;
    PORT
      LAYER M4 ;
      RECT 226.642 267.444 226.714 267.468 ;
    END
  END w0_wd_in[253]
  PIN w0_wd_in[254]
    DIRECTION INPUT ;
    USE SIGNAL ;
    SHAPE ABUTMENT ;
    PORT
      LAYER M4 ;
      RECT 226.642 268.500 226.714 268.524 ;
    END
  END w0_wd_in[254]
  PIN w0_wd_in[255]
    DIRECTION INPUT ;
    USE SIGNAL ;
    SHAPE ABUTMENT ;
    PORT
      LAYER M4 ;
      RECT 226.642 269.556 226.714 269.580 ;
    END
  END w0_wd_in[255]
  PIN w0_wd_in[256]
    DIRECTION INPUT ;
    USE SIGNAL ;
    SHAPE ABUTMENT ;
    PORT
      LAYER M3 ;
      RECT 0.207 0.000 0.225 0.054 ;
    END
  END w0_wd_in[256]
  PIN w0_wd_in[257]
    DIRECTION INPUT ;
    USE SIGNAL ;
    SHAPE ABUTMENT ;
    PORT
      LAYER M3 ;
      RECT 0.639 0.000 0.657 0.054 ;
    END
  END w0_wd_in[257]
  PIN w0_wd_in[258]
    DIRECTION INPUT ;
    USE SIGNAL ;
    SHAPE ABUTMENT ;
    PORT
      LAYER M3 ;
      RECT 1.071 0.000 1.089 0.054 ;
    END
  END w0_wd_in[258]
  PIN w0_wd_in[259]
    DIRECTION INPUT ;
    USE SIGNAL ;
    SHAPE ABUTMENT ;
    PORT
      LAYER M3 ;
      RECT 1.503 0.000 1.521 0.054 ;
    END
  END w0_wd_in[259]
  PIN w0_wd_in[260]
    DIRECTION INPUT ;
    USE SIGNAL ;
    SHAPE ABUTMENT ;
    PORT
      LAYER M3 ;
      RECT 1.935 0.000 1.953 0.054 ;
    END
  END w0_wd_in[260]
  PIN w0_wd_in[261]
    DIRECTION INPUT ;
    USE SIGNAL ;
    SHAPE ABUTMENT ;
    PORT
      LAYER M3 ;
      RECT 2.367 0.000 2.385 0.054 ;
    END
  END w0_wd_in[261]
  PIN w0_wd_in[262]
    DIRECTION INPUT ;
    USE SIGNAL ;
    SHAPE ABUTMENT ;
    PORT
      LAYER M3 ;
      RECT 2.799 0.000 2.817 0.054 ;
    END
  END w0_wd_in[262]
  PIN w0_wd_in[263]
    DIRECTION INPUT ;
    USE SIGNAL ;
    SHAPE ABUTMENT ;
    PORT
      LAYER M3 ;
      RECT 3.231 0.000 3.249 0.054 ;
    END
  END w0_wd_in[263]
  PIN w0_wd_in[264]
    DIRECTION INPUT ;
    USE SIGNAL ;
    SHAPE ABUTMENT ;
    PORT
      LAYER M3 ;
      RECT 3.663 0.000 3.681 0.054 ;
    END
  END w0_wd_in[264]
  PIN w0_wd_in[265]
    DIRECTION INPUT ;
    USE SIGNAL ;
    SHAPE ABUTMENT ;
    PORT
      LAYER M3 ;
      RECT 4.095 0.000 4.113 0.054 ;
    END
  END w0_wd_in[265]
  PIN w0_wd_in[266]
    DIRECTION INPUT ;
    USE SIGNAL ;
    SHAPE ABUTMENT ;
    PORT
      LAYER M3 ;
      RECT 4.527 0.000 4.545 0.054 ;
    END
  END w0_wd_in[266]
  PIN w0_wd_in[267]
    DIRECTION INPUT ;
    USE SIGNAL ;
    SHAPE ABUTMENT ;
    PORT
      LAYER M3 ;
      RECT 4.959 0.000 4.977 0.054 ;
    END
  END w0_wd_in[267]
  PIN w0_wd_in[268]
    DIRECTION INPUT ;
    USE SIGNAL ;
    SHAPE ABUTMENT ;
    PORT
      LAYER M3 ;
      RECT 5.391 0.000 5.409 0.054 ;
    END
  END w0_wd_in[268]
  PIN w0_wd_in[269]
    DIRECTION INPUT ;
    USE SIGNAL ;
    SHAPE ABUTMENT ;
    PORT
      LAYER M3 ;
      RECT 5.823 0.000 5.841 0.054 ;
    END
  END w0_wd_in[269]
  PIN w0_wd_in[270]
    DIRECTION INPUT ;
    USE SIGNAL ;
    SHAPE ABUTMENT ;
    PORT
      LAYER M3 ;
      RECT 6.255 0.000 6.273 0.054 ;
    END
  END w0_wd_in[270]
  PIN w0_wd_in[271]
    DIRECTION INPUT ;
    USE SIGNAL ;
    SHAPE ABUTMENT ;
    PORT
      LAYER M3 ;
      RECT 6.687 0.000 6.705 0.054 ;
    END
  END w0_wd_in[271]
  PIN w0_wd_in[272]
    DIRECTION INPUT ;
    USE SIGNAL ;
    SHAPE ABUTMENT ;
    PORT
      LAYER M3 ;
      RECT 7.119 0.000 7.137 0.054 ;
    END
  END w0_wd_in[272]
  PIN w0_wd_in[273]
    DIRECTION INPUT ;
    USE SIGNAL ;
    SHAPE ABUTMENT ;
    PORT
      LAYER M3 ;
      RECT 7.551 0.000 7.569 0.054 ;
    END
  END w0_wd_in[273]
  PIN w0_wd_in[274]
    DIRECTION INPUT ;
    USE SIGNAL ;
    SHAPE ABUTMENT ;
    PORT
      LAYER M3 ;
      RECT 7.983 0.000 8.001 0.054 ;
    END
  END w0_wd_in[274]
  PIN w0_wd_in[275]
    DIRECTION INPUT ;
    USE SIGNAL ;
    SHAPE ABUTMENT ;
    PORT
      LAYER M3 ;
      RECT 8.415 0.000 8.433 0.054 ;
    END
  END w0_wd_in[275]
  PIN w0_wd_in[276]
    DIRECTION INPUT ;
    USE SIGNAL ;
    SHAPE ABUTMENT ;
    PORT
      LAYER M3 ;
      RECT 8.847 0.000 8.865 0.054 ;
    END
  END w0_wd_in[276]
  PIN w0_wd_in[277]
    DIRECTION INPUT ;
    USE SIGNAL ;
    SHAPE ABUTMENT ;
    PORT
      LAYER M3 ;
      RECT 9.279 0.000 9.297 0.054 ;
    END
  END w0_wd_in[277]
  PIN w0_wd_in[278]
    DIRECTION INPUT ;
    USE SIGNAL ;
    SHAPE ABUTMENT ;
    PORT
      LAYER M3 ;
      RECT 9.711 0.000 9.729 0.054 ;
    END
  END w0_wd_in[278]
  PIN w0_wd_in[279]
    DIRECTION INPUT ;
    USE SIGNAL ;
    SHAPE ABUTMENT ;
    PORT
      LAYER M3 ;
      RECT 10.143 0.000 10.161 0.054 ;
    END
  END w0_wd_in[279]
  PIN w0_wd_in[280]
    DIRECTION INPUT ;
    USE SIGNAL ;
    SHAPE ABUTMENT ;
    PORT
      LAYER M3 ;
      RECT 10.575 0.000 10.593 0.054 ;
    END
  END w0_wd_in[280]
  PIN w0_wd_in[281]
    DIRECTION INPUT ;
    USE SIGNAL ;
    SHAPE ABUTMENT ;
    PORT
      LAYER M3 ;
      RECT 11.007 0.000 11.025 0.054 ;
    END
  END w0_wd_in[281]
  PIN w0_wd_in[282]
    DIRECTION INPUT ;
    USE SIGNAL ;
    SHAPE ABUTMENT ;
    PORT
      LAYER M3 ;
      RECT 11.439 0.000 11.457 0.054 ;
    END
  END w0_wd_in[282]
  PIN w0_wd_in[283]
    DIRECTION INPUT ;
    USE SIGNAL ;
    SHAPE ABUTMENT ;
    PORT
      LAYER M3 ;
      RECT 11.871 0.000 11.889 0.054 ;
    END
  END w0_wd_in[283]
  PIN w0_wd_in[284]
    DIRECTION INPUT ;
    USE SIGNAL ;
    SHAPE ABUTMENT ;
    PORT
      LAYER M3 ;
      RECT 12.303 0.000 12.321 0.054 ;
    END
  END w0_wd_in[284]
  PIN w0_wd_in[285]
    DIRECTION INPUT ;
    USE SIGNAL ;
    SHAPE ABUTMENT ;
    PORT
      LAYER M3 ;
      RECT 12.735 0.000 12.753 0.054 ;
    END
  END w0_wd_in[285]
  PIN w0_wd_in[286]
    DIRECTION INPUT ;
    USE SIGNAL ;
    SHAPE ABUTMENT ;
    PORT
      LAYER M3 ;
      RECT 13.167 0.000 13.185 0.054 ;
    END
  END w0_wd_in[286]
  PIN w0_wd_in[287]
    DIRECTION INPUT ;
    USE SIGNAL ;
    SHAPE ABUTMENT ;
    PORT
      LAYER M3 ;
      RECT 13.599 0.000 13.617 0.054 ;
    END
  END w0_wd_in[287]
  PIN w0_wd_in[288]
    DIRECTION INPUT ;
    USE SIGNAL ;
    SHAPE ABUTMENT ;
    PORT
      LAYER M3 ;
      RECT 14.031 0.000 14.049 0.054 ;
    END
  END w0_wd_in[288]
  PIN w0_wd_in[289]
    DIRECTION INPUT ;
    USE SIGNAL ;
    SHAPE ABUTMENT ;
    PORT
      LAYER M3 ;
      RECT 14.463 0.000 14.481 0.054 ;
    END
  END w0_wd_in[289]
  PIN w0_wd_in[290]
    DIRECTION INPUT ;
    USE SIGNAL ;
    SHAPE ABUTMENT ;
    PORT
      LAYER M3 ;
      RECT 14.895 0.000 14.913 0.054 ;
    END
  END w0_wd_in[290]
  PIN w0_wd_in[291]
    DIRECTION INPUT ;
    USE SIGNAL ;
    SHAPE ABUTMENT ;
    PORT
      LAYER M3 ;
      RECT 15.327 0.000 15.345 0.054 ;
    END
  END w0_wd_in[291]
  PIN w0_wd_in[292]
    DIRECTION INPUT ;
    USE SIGNAL ;
    SHAPE ABUTMENT ;
    PORT
      LAYER M3 ;
      RECT 15.759 0.000 15.777 0.054 ;
    END
  END w0_wd_in[292]
  PIN w0_wd_in[293]
    DIRECTION INPUT ;
    USE SIGNAL ;
    SHAPE ABUTMENT ;
    PORT
      LAYER M3 ;
      RECT 16.191 0.000 16.209 0.054 ;
    END
  END w0_wd_in[293]
  PIN w0_wd_in[294]
    DIRECTION INPUT ;
    USE SIGNAL ;
    SHAPE ABUTMENT ;
    PORT
      LAYER M3 ;
      RECT 16.623 0.000 16.641 0.054 ;
    END
  END w0_wd_in[294]
  PIN w0_wd_in[295]
    DIRECTION INPUT ;
    USE SIGNAL ;
    SHAPE ABUTMENT ;
    PORT
      LAYER M3 ;
      RECT 17.055 0.000 17.073 0.054 ;
    END
  END w0_wd_in[295]
  PIN w0_wd_in[296]
    DIRECTION INPUT ;
    USE SIGNAL ;
    SHAPE ABUTMENT ;
    PORT
      LAYER M3 ;
      RECT 17.487 0.000 17.505 0.054 ;
    END
  END w0_wd_in[296]
  PIN w0_wd_in[297]
    DIRECTION INPUT ;
    USE SIGNAL ;
    SHAPE ABUTMENT ;
    PORT
      LAYER M3 ;
      RECT 17.919 0.000 17.937 0.054 ;
    END
  END w0_wd_in[297]
  PIN w0_wd_in[298]
    DIRECTION INPUT ;
    USE SIGNAL ;
    SHAPE ABUTMENT ;
    PORT
      LAYER M3 ;
      RECT 18.351 0.000 18.369 0.054 ;
    END
  END w0_wd_in[298]
  PIN w0_wd_in[299]
    DIRECTION INPUT ;
    USE SIGNAL ;
    SHAPE ABUTMENT ;
    PORT
      LAYER M3 ;
      RECT 18.783 0.000 18.801 0.054 ;
    END
  END w0_wd_in[299]
  PIN w0_wd_in[300]
    DIRECTION INPUT ;
    USE SIGNAL ;
    SHAPE ABUTMENT ;
    PORT
      LAYER M3 ;
      RECT 19.215 0.000 19.233 0.054 ;
    END
  END w0_wd_in[300]
  PIN w0_wd_in[301]
    DIRECTION INPUT ;
    USE SIGNAL ;
    SHAPE ABUTMENT ;
    PORT
      LAYER M3 ;
      RECT 19.647 0.000 19.665 0.054 ;
    END
  END w0_wd_in[301]
  PIN w0_wd_in[302]
    DIRECTION INPUT ;
    USE SIGNAL ;
    SHAPE ABUTMENT ;
    PORT
      LAYER M3 ;
      RECT 20.079 0.000 20.097 0.054 ;
    END
  END w0_wd_in[302]
  PIN w0_wd_in[303]
    DIRECTION INPUT ;
    USE SIGNAL ;
    SHAPE ABUTMENT ;
    PORT
      LAYER M3 ;
      RECT 20.511 0.000 20.529 0.054 ;
    END
  END w0_wd_in[303]
  PIN w0_wd_in[304]
    DIRECTION INPUT ;
    USE SIGNAL ;
    SHAPE ABUTMENT ;
    PORT
      LAYER M3 ;
      RECT 20.943 0.000 20.961 0.054 ;
    END
  END w0_wd_in[304]
  PIN w0_wd_in[305]
    DIRECTION INPUT ;
    USE SIGNAL ;
    SHAPE ABUTMENT ;
    PORT
      LAYER M3 ;
      RECT 21.375 0.000 21.393 0.054 ;
    END
  END w0_wd_in[305]
  PIN w0_wd_in[306]
    DIRECTION INPUT ;
    USE SIGNAL ;
    SHAPE ABUTMENT ;
    PORT
      LAYER M3 ;
      RECT 21.807 0.000 21.825 0.054 ;
    END
  END w0_wd_in[306]
  PIN w0_wd_in[307]
    DIRECTION INPUT ;
    USE SIGNAL ;
    SHAPE ABUTMENT ;
    PORT
      LAYER M3 ;
      RECT 22.239 0.000 22.257 0.054 ;
    END
  END w0_wd_in[307]
  PIN w0_wd_in[308]
    DIRECTION INPUT ;
    USE SIGNAL ;
    SHAPE ABUTMENT ;
    PORT
      LAYER M3 ;
      RECT 22.671 0.000 22.689 0.054 ;
    END
  END w0_wd_in[308]
  PIN w0_wd_in[309]
    DIRECTION INPUT ;
    USE SIGNAL ;
    SHAPE ABUTMENT ;
    PORT
      LAYER M3 ;
      RECT 23.103 0.000 23.121 0.054 ;
    END
  END w0_wd_in[309]
  PIN w0_wd_in[310]
    DIRECTION INPUT ;
    USE SIGNAL ;
    SHAPE ABUTMENT ;
    PORT
      LAYER M3 ;
      RECT 23.535 0.000 23.553 0.054 ;
    END
  END w0_wd_in[310]
  PIN w0_wd_in[311]
    DIRECTION INPUT ;
    USE SIGNAL ;
    SHAPE ABUTMENT ;
    PORT
      LAYER M3 ;
      RECT 23.967 0.000 23.985 0.054 ;
    END
  END w0_wd_in[311]
  PIN w0_wd_in[312]
    DIRECTION INPUT ;
    USE SIGNAL ;
    SHAPE ABUTMENT ;
    PORT
      LAYER M3 ;
      RECT 24.399 0.000 24.417 0.054 ;
    END
  END w0_wd_in[312]
  PIN w0_wd_in[313]
    DIRECTION INPUT ;
    USE SIGNAL ;
    SHAPE ABUTMENT ;
    PORT
      LAYER M3 ;
      RECT 24.831 0.000 24.849 0.054 ;
    END
  END w0_wd_in[313]
  PIN w0_wd_in[314]
    DIRECTION INPUT ;
    USE SIGNAL ;
    SHAPE ABUTMENT ;
    PORT
      LAYER M3 ;
      RECT 25.263 0.000 25.281 0.054 ;
    END
  END w0_wd_in[314]
  PIN w0_wd_in[315]
    DIRECTION INPUT ;
    USE SIGNAL ;
    SHAPE ABUTMENT ;
    PORT
      LAYER M3 ;
      RECT 25.695 0.000 25.713 0.054 ;
    END
  END w0_wd_in[315]
  PIN w0_wd_in[316]
    DIRECTION INPUT ;
    USE SIGNAL ;
    SHAPE ABUTMENT ;
    PORT
      LAYER M3 ;
      RECT 26.127 0.000 26.145 0.054 ;
    END
  END w0_wd_in[316]
  PIN w0_wd_in[317]
    DIRECTION INPUT ;
    USE SIGNAL ;
    SHAPE ABUTMENT ;
    PORT
      LAYER M3 ;
      RECT 26.559 0.000 26.577 0.054 ;
    END
  END w0_wd_in[317]
  PIN w0_wd_in[318]
    DIRECTION INPUT ;
    USE SIGNAL ;
    SHAPE ABUTMENT ;
    PORT
      LAYER M3 ;
      RECT 26.991 0.000 27.009 0.054 ;
    END
  END w0_wd_in[318]
  PIN w0_wd_in[319]
    DIRECTION INPUT ;
    USE SIGNAL ;
    SHAPE ABUTMENT ;
    PORT
      LAYER M3 ;
      RECT 27.423 0.000 27.441 0.054 ;
    END
  END w0_wd_in[319]
  PIN w0_wd_in[320]
    DIRECTION INPUT ;
    USE SIGNAL ;
    SHAPE ABUTMENT ;
    PORT
      LAYER M3 ;
      RECT 27.855 0.000 27.873 0.054 ;
    END
  END w0_wd_in[320]
  PIN w0_wd_in[321]
    DIRECTION INPUT ;
    USE SIGNAL ;
    SHAPE ABUTMENT ;
    PORT
      LAYER M3 ;
      RECT 28.287 0.000 28.305 0.054 ;
    END
  END w0_wd_in[321]
  PIN w0_wd_in[322]
    DIRECTION INPUT ;
    USE SIGNAL ;
    SHAPE ABUTMENT ;
    PORT
      LAYER M3 ;
      RECT 28.719 0.000 28.737 0.054 ;
    END
  END w0_wd_in[322]
  PIN w0_wd_in[323]
    DIRECTION INPUT ;
    USE SIGNAL ;
    SHAPE ABUTMENT ;
    PORT
      LAYER M3 ;
      RECT 29.151 0.000 29.169 0.054 ;
    END
  END w0_wd_in[323]
  PIN w0_wd_in[324]
    DIRECTION INPUT ;
    USE SIGNAL ;
    SHAPE ABUTMENT ;
    PORT
      LAYER M3 ;
      RECT 29.583 0.000 29.601 0.054 ;
    END
  END w0_wd_in[324]
  PIN w0_wd_in[325]
    DIRECTION INPUT ;
    USE SIGNAL ;
    SHAPE ABUTMENT ;
    PORT
      LAYER M3 ;
      RECT 30.015 0.000 30.033 0.054 ;
    END
  END w0_wd_in[325]
  PIN w0_wd_in[326]
    DIRECTION INPUT ;
    USE SIGNAL ;
    SHAPE ABUTMENT ;
    PORT
      LAYER M3 ;
      RECT 30.447 0.000 30.465 0.054 ;
    END
  END w0_wd_in[326]
  PIN w0_wd_in[327]
    DIRECTION INPUT ;
    USE SIGNAL ;
    SHAPE ABUTMENT ;
    PORT
      LAYER M3 ;
      RECT 30.879 0.000 30.897 0.054 ;
    END
  END w0_wd_in[327]
  PIN w0_wd_in[328]
    DIRECTION INPUT ;
    USE SIGNAL ;
    SHAPE ABUTMENT ;
    PORT
      LAYER M3 ;
      RECT 31.311 0.000 31.329 0.054 ;
    END
  END w0_wd_in[328]
  PIN w0_wd_in[329]
    DIRECTION INPUT ;
    USE SIGNAL ;
    SHAPE ABUTMENT ;
    PORT
      LAYER M3 ;
      RECT 31.743 0.000 31.761 0.054 ;
    END
  END w0_wd_in[329]
  PIN w0_wd_in[330]
    DIRECTION INPUT ;
    USE SIGNAL ;
    SHAPE ABUTMENT ;
    PORT
      LAYER M3 ;
      RECT 32.175 0.000 32.193 0.054 ;
    END
  END w0_wd_in[330]
  PIN w0_wd_in[331]
    DIRECTION INPUT ;
    USE SIGNAL ;
    SHAPE ABUTMENT ;
    PORT
      LAYER M3 ;
      RECT 32.607 0.000 32.625 0.054 ;
    END
  END w0_wd_in[331]
  PIN w0_wd_in[332]
    DIRECTION INPUT ;
    USE SIGNAL ;
    SHAPE ABUTMENT ;
    PORT
      LAYER M3 ;
      RECT 33.039 0.000 33.057 0.054 ;
    END
  END w0_wd_in[332]
  PIN w0_wd_in[333]
    DIRECTION INPUT ;
    USE SIGNAL ;
    SHAPE ABUTMENT ;
    PORT
      LAYER M3 ;
      RECT 33.471 0.000 33.489 0.054 ;
    END
  END w0_wd_in[333]
  PIN w0_wd_in[334]
    DIRECTION INPUT ;
    USE SIGNAL ;
    SHAPE ABUTMENT ;
    PORT
      LAYER M3 ;
      RECT 33.903 0.000 33.921 0.054 ;
    END
  END w0_wd_in[334]
  PIN w0_wd_in[335]
    DIRECTION INPUT ;
    USE SIGNAL ;
    SHAPE ABUTMENT ;
    PORT
      LAYER M3 ;
      RECT 34.335 0.000 34.353 0.054 ;
    END
  END w0_wd_in[335]
  PIN w0_wd_in[336]
    DIRECTION INPUT ;
    USE SIGNAL ;
    SHAPE ABUTMENT ;
    PORT
      LAYER M3 ;
      RECT 34.767 0.000 34.785 0.054 ;
    END
  END w0_wd_in[336]
  PIN w0_wd_in[337]
    DIRECTION INPUT ;
    USE SIGNAL ;
    SHAPE ABUTMENT ;
    PORT
      LAYER M3 ;
      RECT 35.199 0.000 35.217 0.054 ;
    END
  END w0_wd_in[337]
  PIN w0_wd_in[338]
    DIRECTION INPUT ;
    USE SIGNAL ;
    SHAPE ABUTMENT ;
    PORT
      LAYER M3 ;
      RECT 35.631 0.000 35.649 0.054 ;
    END
  END w0_wd_in[338]
  PIN w0_wd_in[339]
    DIRECTION INPUT ;
    USE SIGNAL ;
    SHAPE ABUTMENT ;
    PORT
      LAYER M3 ;
      RECT 36.063 0.000 36.081 0.054 ;
    END
  END w0_wd_in[339]
  PIN w0_wd_in[340]
    DIRECTION INPUT ;
    USE SIGNAL ;
    SHAPE ABUTMENT ;
    PORT
      LAYER M3 ;
      RECT 36.495 0.000 36.513 0.054 ;
    END
  END w0_wd_in[340]
  PIN w0_wd_in[341]
    DIRECTION INPUT ;
    USE SIGNAL ;
    SHAPE ABUTMENT ;
    PORT
      LAYER M3 ;
      RECT 36.927 0.000 36.945 0.054 ;
    END
  END w0_wd_in[341]
  PIN w0_wd_in[342]
    DIRECTION INPUT ;
    USE SIGNAL ;
    SHAPE ABUTMENT ;
    PORT
      LAYER M3 ;
      RECT 37.359 0.000 37.377 0.054 ;
    END
  END w0_wd_in[342]
  PIN w0_wd_in[343]
    DIRECTION INPUT ;
    USE SIGNAL ;
    SHAPE ABUTMENT ;
    PORT
      LAYER M3 ;
      RECT 37.791 0.000 37.809 0.054 ;
    END
  END w0_wd_in[343]
  PIN w0_wd_in[344]
    DIRECTION INPUT ;
    USE SIGNAL ;
    SHAPE ABUTMENT ;
    PORT
      LAYER M3 ;
      RECT 38.223 0.000 38.241 0.054 ;
    END
  END w0_wd_in[344]
  PIN w0_wd_in[345]
    DIRECTION INPUT ;
    USE SIGNAL ;
    SHAPE ABUTMENT ;
    PORT
      LAYER M3 ;
      RECT 38.655 0.000 38.673 0.054 ;
    END
  END w0_wd_in[345]
  PIN w0_wd_in[346]
    DIRECTION INPUT ;
    USE SIGNAL ;
    SHAPE ABUTMENT ;
    PORT
      LAYER M3 ;
      RECT 39.087 0.000 39.105 0.054 ;
    END
  END w0_wd_in[346]
  PIN w0_wd_in[347]
    DIRECTION INPUT ;
    USE SIGNAL ;
    SHAPE ABUTMENT ;
    PORT
      LAYER M3 ;
      RECT 39.519 0.000 39.537 0.054 ;
    END
  END w0_wd_in[347]
  PIN w0_wd_in[348]
    DIRECTION INPUT ;
    USE SIGNAL ;
    SHAPE ABUTMENT ;
    PORT
      LAYER M3 ;
      RECT 39.951 0.000 39.969 0.054 ;
    END
  END w0_wd_in[348]
  PIN w0_wd_in[349]
    DIRECTION INPUT ;
    USE SIGNAL ;
    SHAPE ABUTMENT ;
    PORT
      LAYER M3 ;
      RECT 40.383 0.000 40.401 0.054 ;
    END
  END w0_wd_in[349]
  PIN w0_wd_in[350]
    DIRECTION INPUT ;
    USE SIGNAL ;
    SHAPE ABUTMENT ;
    PORT
      LAYER M3 ;
      RECT 40.815 0.000 40.833 0.054 ;
    END
  END w0_wd_in[350]
  PIN w0_wd_in[351]
    DIRECTION INPUT ;
    USE SIGNAL ;
    SHAPE ABUTMENT ;
    PORT
      LAYER M3 ;
      RECT 41.247 0.000 41.265 0.054 ;
    END
  END w0_wd_in[351]
  PIN w0_wd_in[352]
    DIRECTION INPUT ;
    USE SIGNAL ;
    SHAPE ABUTMENT ;
    PORT
      LAYER M3 ;
      RECT 41.679 0.000 41.697 0.054 ;
    END
  END w0_wd_in[352]
  PIN w0_wd_in[353]
    DIRECTION INPUT ;
    USE SIGNAL ;
    SHAPE ABUTMENT ;
    PORT
      LAYER M3 ;
      RECT 42.111 0.000 42.129 0.054 ;
    END
  END w0_wd_in[353]
  PIN w0_wd_in[354]
    DIRECTION INPUT ;
    USE SIGNAL ;
    SHAPE ABUTMENT ;
    PORT
      LAYER M3 ;
      RECT 42.543 0.000 42.561 0.054 ;
    END
  END w0_wd_in[354]
  PIN w0_wd_in[355]
    DIRECTION INPUT ;
    USE SIGNAL ;
    SHAPE ABUTMENT ;
    PORT
      LAYER M3 ;
      RECT 42.975 0.000 42.993 0.054 ;
    END
  END w0_wd_in[355]
  PIN w0_wd_in[356]
    DIRECTION INPUT ;
    USE SIGNAL ;
    SHAPE ABUTMENT ;
    PORT
      LAYER M3 ;
      RECT 43.407 0.000 43.425 0.054 ;
    END
  END w0_wd_in[356]
  PIN w0_wd_in[357]
    DIRECTION INPUT ;
    USE SIGNAL ;
    SHAPE ABUTMENT ;
    PORT
      LAYER M3 ;
      RECT 43.839 0.000 43.857 0.054 ;
    END
  END w0_wd_in[357]
  PIN w0_wd_in[358]
    DIRECTION INPUT ;
    USE SIGNAL ;
    SHAPE ABUTMENT ;
    PORT
      LAYER M3 ;
      RECT 44.271 0.000 44.289 0.054 ;
    END
  END w0_wd_in[358]
  PIN w0_wd_in[359]
    DIRECTION INPUT ;
    USE SIGNAL ;
    SHAPE ABUTMENT ;
    PORT
      LAYER M3 ;
      RECT 44.703 0.000 44.721 0.054 ;
    END
  END w0_wd_in[359]
  PIN w0_wd_in[360]
    DIRECTION INPUT ;
    USE SIGNAL ;
    SHAPE ABUTMENT ;
    PORT
      LAYER M3 ;
      RECT 45.135 0.000 45.153 0.054 ;
    END
  END w0_wd_in[360]
  PIN w0_wd_in[361]
    DIRECTION INPUT ;
    USE SIGNAL ;
    SHAPE ABUTMENT ;
    PORT
      LAYER M3 ;
      RECT 45.567 0.000 45.585 0.054 ;
    END
  END w0_wd_in[361]
  PIN w0_wd_in[362]
    DIRECTION INPUT ;
    USE SIGNAL ;
    SHAPE ABUTMENT ;
    PORT
      LAYER M3 ;
      RECT 45.999 0.000 46.017 0.054 ;
    END
  END w0_wd_in[362]
  PIN w0_wd_in[363]
    DIRECTION INPUT ;
    USE SIGNAL ;
    SHAPE ABUTMENT ;
    PORT
      LAYER M3 ;
      RECT 46.431 0.000 46.449 0.054 ;
    END
  END w0_wd_in[363]
  PIN w0_wd_in[364]
    DIRECTION INPUT ;
    USE SIGNAL ;
    SHAPE ABUTMENT ;
    PORT
      LAYER M3 ;
      RECT 46.863 0.000 46.881 0.054 ;
    END
  END w0_wd_in[364]
  PIN w0_wd_in[365]
    DIRECTION INPUT ;
    USE SIGNAL ;
    SHAPE ABUTMENT ;
    PORT
      LAYER M3 ;
      RECT 47.295 0.000 47.313 0.054 ;
    END
  END w0_wd_in[365]
  PIN w0_wd_in[366]
    DIRECTION INPUT ;
    USE SIGNAL ;
    SHAPE ABUTMENT ;
    PORT
      LAYER M3 ;
      RECT 47.727 0.000 47.745 0.054 ;
    END
  END w0_wd_in[366]
  PIN w0_wd_in[367]
    DIRECTION INPUT ;
    USE SIGNAL ;
    SHAPE ABUTMENT ;
    PORT
      LAYER M3 ;
      RECT 48.159 0.000 48.177 0.054 ;
    END
  END w0_wd_in[367]
  PIN w0_wd_in[368]
    DIRECTION INPUT ;
    USE SIGNAL ;
    SHAPE ABUTMENT ;
    PORT
      LAYER M3 ;
      RECT 48.591 0.000 48.609 0.054 ;
    END
  END w0_wd_in[368]
  PIN w0_wd_in[369]
    DIRECTION INPUT ;
    USE SIGNAL ;
    SHAPE ABUTMENT ;
    PORT
      LAYER M3 ;
      RECT 49.023 0.000 49.041 0.054 ;
    END
  END w0_wd_in[369]
  PIN w0_wd_in[370]
    DIRECTION INPUT ;
    USE SIGNAL ;
    SHAPE ABUTMENT ;
    PORT
      LAYER M3 ;
      RECT 49.455 0.000 49.473 0.054 ;
    END
  END w0_wd_in[370]
  PIN w0_wd_in[371]
    DIRECTION INPUT ;
    USE SIGNAL ;
    SHAPE ABUTMENT ;
    PORT
      LAYER M3 ;
      RECT 49.887 0.000 49.905 0.054 ;
    END
  END w0_wd_in[371]
  PIN w0_wd_in[372]
    DIRECTION INPUT ;
    USE SIGNAL ;
    SHAPE ABUTMENT ;
    PORT
      LAYER M3 ;
      RECT 50.319 0.000 50.337 0.054 ;
    END
  END w0_wd_in[372]
  PIN w0_wd_in[373]
    DIRECTION INPUT ;
    USE SIGNAL ;
    SHAPE ABUTMENT ;
    PORT
      LAYER M3 ;
      RECT 50.751 0.000 50.769 0.054 ;
    END
  END w0_wd_in[373]
  PIN w0_wd_in[374]
    DIRECTION INPUT ;
    USE SIGNAL ;
    SHAPE ABUTMENT ;
    PORT
      LAYER M3 ;
      RECT 51.183 0.000 51.201 0.054 ;
    END
  END w0_wd_in[374]
  PIN w0_wd_in[375]
    DIRECTION INPUT ;
    USE SIGNAL ;
    SHAPE ABUTMENT ;
    PORT
      LAYER M3 ;
      RECT 51.615 0.000 51.633 0.054 ;
    END
  END w0_wd_in[375]
  PIN w0_wd_in[376]
    DIRECTION INPUT ;
    USE SIGNAL ;
    SHAPE ABUTMENT ;
    PORT
      LAYER M3 ;
      RECT 52.047 0.000 52.065 0.054 ;
    END
  END w0_wd_in[376]
  PIN w0_wd_in[377]
    DIRECTION INPUT ;
    USE SIGNAL ;
    SHAPE ABUTMENT ;
    PORT
      LAYER M3 ;
      RECT 52.479 0.000 52.497 0.054 ;
    END
  END w0_wd_in[377]
  PIN w0_wd_in[378]
    DIRECTION INPUT ;
    USE SIGNAL ;
    SHAPE ABUTMENT ;
    PORT
      LAYER M3 ;
      RECT 52.911 0.000 52.929 0.054 ;
    END
  END w0_wd_in[378]
  PIN w0_wd_in[379]
    DIRECTION INPUT ;
    USE SIGNAL ;
    SHAPE ABUTMENT ;
    PORT
      LAYER M3 ;
      RECT 53.343 0.000 53.361 0.054 ;
    END
  END w0_wd_in[379]
  PIN w0_wd_in[380]
    DIRECTION INPUT ;
    USE SIGNAL ;
    SHAPE ABUTMENT ;
    PORT
      LAYER M3 ;
      RECT 53.775 0.000 53.793 0.054 ;
    END
  END w0_wd_in[380]
  PIN w0_wd_in[381]
    DIRECTION INPUT ;
    USE SIGNAL ;
    SHAPE ABUTMENT ;
    PORT
      LAYER M3 ;
      RECT 54.207 0.000 54.225 0.054 ;
    END
  END w0_wd_in[381]
  PIN w0_wd_in[382]
    DIRECTION INPUT ;
    USE SIGNAL ;
    SHAPE ABUTMENT ;
    PORT
      LAYER M3 ;
      RECT 54.639 0.000 54.657 0.054 ;
    END
  END w0_wd_in[382]
  PIN w0_wd_in[383]
    DIRECTION INPUT ;
    USE SIGNAL ;
    SHAPE ABUTMENT ;
    PORT
      LAYER M3 ;
      RECT 55.071 0.000 55.089 0.054 ;
    END
  END w0_wd_in[383]
  PIN w0_wd_in[384]
    DIRECTION INPUT ;
    USE SIGNAL ;
    SHAPE ABUTMENT ;
    PORT
      LAYER M3 ;
      RECT 55.503 0.000 55.521 0.054 ;
    END
  END w0_wd_in[384]
  PIN w0_wd_in[385]
    DIRECTION INPUT ;
    USE SIGNAL ;
    SHAPE ABUTMENT ;
    PORT
      LAYER M3 ;
      RECT 55.935 0.000 55.953 0.054 ;
    END
  END w0_wd_in[385]
  PIN w0_wd_in[386]
    DIRECTION INPUT ;
    USE SIGNAL ;
    SHAPE ABUTMENT ;
    PORT
      LAYER M3 ;
      RECT 56.367 0.000 56.385 0.054 ;
    END
  END w0_wd_in[386]
  PIN w0_wd_in[387]
    DIRECTION INPUT ;
    USE SIGNAL ;
    SHAPE ABUTMENT ;
    PORT
      LAYER M3 ;
      RECT 56.799 0.000 56.817 0.054 ;
    END
  END w0_wd_in[387]
  PIN w0_wd_in[388]
    DIRECTION INPUT ;
    USE SIGNAL ;
    SHAPE ABUTMENT ;
    PORT
      LAYER M3 ;
      RECT 57.231 0.000 57.249 0.054 ;
    END
  END w0_wd_in[388]
  PIN w0_wd_in[389]
    DIRECTION INPUT ;
    USE SIGNAL ;
    SHAPE ABUTMENT ;
    PORT
      LAYER M3 ;
      RECT 57.663 0.000 57.681 0.054 ;
    END
  END w0_wd_in[389]
  PIN w0_wd_in[390]
    DIRECTION INPUT ;
    USE SIGNAL ;
    SHAPE ABUTMENT ;
    PORT
      LAYER M3 ;
      RECT 58.095 0.000 58.113 0.054 ;
    END
  END w0_wd_in[390]
  PIN w0_wd_in[391]
    DIRECTION INPUT ;
    USE SIGNAL ;
    SHAPE ABUTMENT ;
    PORT
      LAYER M3 ;
      RECT 58.527 0.000 58.545 0.054 ;
    END
  END w0_wd_in[391]
  PIN w0_wd_in[392]
    DIRECTION INPUT ;
    USE SIGNAL ;
    SHAPE ABUTMENT ;
    PORT
      LAYER M3 ;
      RECT 58.959 0.000 58.977 0.054 ;
    END
  END w0_wd_in[392]
  PIN w0_wd_in[393]
    DIRECTION INPUT ;
    USE SIGNAL ;
    SHAPE ABUTMENT ;
    PORT
      LAYER M3 ;
      RECT 59.391 0.000 59.409 0.054 ;
    END
  END w0_wd_in[393]
  PIN w0_wd_in[394]
    DIRECTION INPUT ;
    USE SIGNAL ;
    SHAPE ABUTMENT ;
    PORT
      LAYER M3 ;
      RECT 59.823 0.000 59.841 0.054 ;
    END
  END w0_wd_in[394]
  PIN w0_wd_in[395]
    DIRECTION INPUT ;
    USE SIGNAL ;
    SHAPE ABUTMENT ;
    PORT
      LAYER M3 ;
      RECT 60.255 0.000 60.273 0.054 ;
    END
  END w0_wd_in[395]
  PIN w0_wd_in[396]
    DIRECTION INPUT ;
    USE SIGNAL ;
    SHAPE ABUTMENT ;
    PORT
      LAYER M3 ;
      RECT 60.687 0.000 60.705 0.054 ;
    END
  END w0_wd_in[396]
  PIN w0_wd_in[397]
    DIRECTION INPUT ;
    USE SIGNAL ;
    SHAPE ABUTMENT ;
    PORT
      LAYER M3 ;
      RECT 61.119 0.000 61.137 0.054 ;
    END
  END w0_wd_in[397]
  PIN w0_wd_in[398]
    DIRECTION INPUT ;
    USE SIGNAL ;
    SHAPE ABUTMENT ;
    PORT
      LAYER M3 ;
      RECT 61.551 0.000 61.569 0.054 ;
    END
  END w0_wd_in[398]
  PIN w0_wd_in[399]
    DIRECTION INPUT ;
    USE SIGNAL ;
    SHAPE ABUTMENT ;
    PORT
      LAYER M3 ;
      RECT 61.983 0.000 62.001 0.054 ;
    END
  END w0_wd_in[399]
  PIN w0_wd_in[400]
    DIRECTION INPUT ;
    USE SIGNAL ;
    SHAPE ABUTMENT ;
    PORT
      LAYER M3 ;
      RECT 62.415 0.000 62.433 0.054 ;
    END
  END w0_wd_in[400]
  PIN w0_wd_in[401]
    DIRECTION INPUT ;
    USE SIGNAL ;
    SHAPE ABUTMENT ;
    PORT
      LAYER M3 ;
      RECT 62.847 0.000 62.865 0.054 ;
    END
  END w0_wd_in[401]
  PIN w0_wd_in[402]
    DIRECTION INPUT ;
    USE SIGNAL ;
    SHAPE ABUTMENT ;
    PORT
      LAYER M3 ;
      RECT 63.279 0.000 63.297 0.054 ;
    END
  END w0_wd_in[402]
  PIN w0_wd_in[403]
    DIRECTION INPUT ;
    USE SIGNAL ;
    SHAPE ABUTMENT ;
    PORT
      LAYER M3 ;
      RECT 63.711 0.000 63.729 0.054 ;
    END
  END w0_wd_in[403]
  PIN w0_wd_in[404]
    DIRECTION INPUT ;
    USE SIGNAL ;
    SHAPE ABUTMENT ;
    PORT
      LAYER M3 ;
      RECT 64.143 0.000 64.161 0.054 ;
    END
  END w0_wd_in[404]
  PIN w0_wd_in[405]
    DIRECTION INPUT ;
    USE SIGNAL ;
    SHAPE ABUTMENT ;
    PORT
      LAYER M3 ;
      RECT 64.575 0.000 64.593 0.054 ;
    END
  END w0_wd_in[405]
  PIN w0_wd_in[406]
    DIRECTION INPUT ;
    USE SIGNAL ;
    SHAPE ABUTMENT ;
    PORT
      LAYER M3 ;
      RECT 65.007 0.000 65.025 0.054 ;
    END
  END w0_wd_in[406]
  PIN w0_wd_in[407]
    DIRECTION INPUT ;
    USE SIGNAL ;
    SHAPE ABUTMENT ;
    PORT
      LAYER M3 ;
      RECT 65.439 0.000 65.457 0.054 ;
    END
  END w0_wd_in[407]
  PIN w0_wd_in[408]
    DIRECTION INPUT ;
    USE SIGNAL ;
    SHAPE ABUTMENT ;
    PORT
      LAYER M3 ;
      RECT 65.871 0.000 65.889 0.054 ;
    END
  END w0_wd_in[408]
  PIN w0_wd_in[409]
    DIRECTION INPUT ;
    USE SIGNAL ;
    SHAPE ABUTMENT ;
    PORT
      LAYER M3 ;
      RECT 66.303 0.000 66.321 0.054 ;
    END
  END w0_wd_in[409]
  PIN w0_wd_in[410]
    DIRECTION INPUT ;
    USE SIGNAL ;
    SHAPE ABUTMENT ;
    PORT
      LAYER M3 ;
      RECT 66.735 0.000 66.753 0.054 ;
    END
  END w0_wd_in[410]
  PIN w0_wd_in[411]
    DIRECTION INPUT ;
    USE SIGNAL ;
    SHAPE ABUTMENT ;
    PORT
      LAYER M3 ;
      RECT 67.167 0.000 67.185 0.054 ;
    END
  END w0_wd_in[411]
  PIN w0_wd_in[412]
    DIRECTION INPUT ;
    USE SIGNAL ;
    SHAPE ABUTMENT ;
    PORT
      LAYER M3 ;
      RECT 67.599 0.000 67.617 0.054 ;
    END
  END w0_wd_in[412]
  PIN w0_wd_in[413]
    DIRECTION INPUT ;
    USE SIGNAL ;
    SHAPE ABUTMENT ;
    PORT
      LAYER M3 ;
      RECT 68.031 0.000 68.049 0.054 ;
    END
  END w0_wd_in[413]
  PIN w0_wd_in[414]
    DIRECTION INPUT ;
    USE SIGNAL ;
    SHAPE ABUTMENT ;
    PORT
      LAYER M3 ;
      RECT 68.463 0.000 68.481 0.054 ;
    END
  END w0_wd_in[414]
  PIN w0_wd_in[415]
    DIRECTION INPUT ;
    USE SIGNAL ;
    SHAPE ABUTMENT ;
    PORT
      LAYER M3 ;
      RECT 68.895 0.000 68.913 0.054 ;
    END
  END w0_wd_in[415]
  PIN w0_wd_in[416]
    DIRECTION INPUT ;
    USE SIGNAL ;
    SHAPE ABUTMENT ;
    PORT
      LAYER M3 ;
      RECT 69.327 0.000 69.345 0.054 ;
    END
  END w0_wd_in[416]
  PIN w0_wd_in[417]
    DIRECTION INPUT ;
    USE SIGNAL ;
    SHAPE ABUTMENT ;
    PORT
      LAYER M3 ;
      RECT 69.759 0.000 69.777 0.054 ;
    END
  END w0_wd_in[417]
  PIN w0_wd_in[418]
    DIRECTION INPUT ;
    USE SIGNAL ;
    SHAPE ABUTMENT ;
    PORT
      LAYER M3 ;
      RECT 70.191 0.000 70.209 0.054 ;
    END
  END w0_wd_in[418]
  PIN w0_wd_in[419]
    DIRECTION INPUT ;
    USE SIGNAL ;
    SHAPE ABUTMENT ;
    PORT
      LAYER M3 ;
      RECT 70.623 0.000 70.641 0.054 ;
    END
  END w0_wd_in[419]
  PIN w0_wd_in[420]
    DIRECTION INPUT ;
    USE SIGNAL ;
    SHAPE ABUTMENT ;
    PORT
      LAYER M3 ;
      RECT 71.055 0.000 71.073 0.054 ;
    END
  END w0_wd_in[420]
  PIN w0_wd_in[421]
    DIRECTION INPUT ;
    USE SIGNAL ;
    SHAPE ABUTMENT ;
    PORT
      LAYER M3 ;
      RECT 71.487 0.000 71.505 0.054 ;
    END
  END w0_wd_in[421]
  PIN w0_wd_in[422]
    DIRECTION INPUT ;
    USE SIGNAL ;
    SHAPE ABUTMENT ;
    PORT
      LAYER M3 ;
      RECT 71.919 0.000 71.937 0.054 ;
    END
  END w0_wd_in[422]
  PIN w0_wd_in[423]
    DIRECTION INPUT ;
    USE SIGNAL ;
    SHAPE ABUTMENT ;
    PORT
      LAYER M3 ;
      RECT 72.351 0.000 72.369 0.054 ;
    END
  END w0_wd_in[423]
  PIN w0_wd_in[424]
    DIRECTION INPUT ;
    USE SIGNAL ;
    SHAPE ABUTMENT ;
    PORT
      LAYER M3 ;
      RECT 72.783 0.000 72.801 0.054 ;
    END
  END w0_wd_in[424]
  PIN w0_wd_in[425]
    DIRECTION INPUT ;
    USE SIGNAL ;
    SHAPE ABUTMENT ;
    PORT
      LAYER M3 ;
      RECT 73.215 0.000 73.233 0.054 ;
    END
  END w0_wd_in[425]
  PIN w0_wd_in[426]
    DIRECTION INPUT ;
    USE SIGNAL ;
    SHAPE ABUTMENT ;
    PORT
      LAYER M3 ;
      RECT 73.647 0.000 73.665 0.054 ;
    END
  END w0_wd_in[426]
  PIN w0_wd_in[427]
    DIRECTION INPUT ;
    USE SIGNAL ;
    SHAPE ABUTMENT ;
    PORT
      LAYER M3 ;
      RECT 74.079 0.000 74.097 0.054 ;
    END
  END w0_wd_in[427]
  PIN w0_wd_in[428]
    DIRECTION INPUT ;
    USE SIGNAL ;
    SHAPE ABUTMENT ;
    PORT
      LAYER M3 ;
      RECT 74.511 0.000 74.529 0.054 ;
    END
  END w0_wd_in[428]
  PIN w0_wd_in[429]
    DIRECTION INPUT ;
    USE SIGNAL ;
    SHAPE ABUTMENT ;
    PORT
      LAYER M3 ;
      RECT 74.943 0.000 74.961 0.054 ;
    END
  END w0_wd_in[429]
  PIN w0_wd_in[430]
    DIRECTION INPUT ;
    USE SIGNAL ;
    SHAPE ABUTMENT ;
    PORT
      LAYER M3 ;
      RECT 75.375 0.000 75.393 0.054 ;
    END
  END w0_wd_in[430]
  PIN w0_wd_in[431]
    DIRECTION INPUT ;
    USE SIGNAL ;
    SHAPE ABUTMENT ;
    PORT
      LAYER M3 ;
      RECT 75.807 0.000 75.825 0.054 ;
    END
  END w0_wd_in[431]
  PIN w0_wd_in[432]
    DIRECTION INPUT ;
    USE SIGNAL ;
    SHAPE ABUTMENT ;
    PORT
      LAYER M3 ;
      RECT 76.239 0.000 76.257 0.054 ;
    END
  END w0_wd_in[432]
  PIN w0_wd_in[433]
    DIRECTION INPUT ;
    USE SIGNAL ;
    SHAPE ABUTMENT ;
    PORT
      LAYER M3 ;
      RECT 76.671 0.000 76.689 0.054 ;
    END
  END w0_wd_in[433]
  PIN w0_wd_in[434]
    DIRECTION INPUT ;
    USE SIGNAL ;
    SHAPE ABUTMENT ;
    PORT
      LAYER M3 ;
      RECT 77.103 0.000 77.121 0.054 ;
    END
  END w0_wd_in[434]
  PIN w0_wd_in[435]
    DIRECTION INPUT ;
    USE SIGNAL ;
    SHAPE ABUTMENT ;
    PORT
      LAYER M3 ;
      RECT 77.535 0.000 77.553 0.054 ;
    END
  END w0_wd_in[435]
  PIN w0_wd_in[436]
    DIRECTION INPUT ;
    USE SIGNAL ;
    SHAPE ABUTMENT ;
    PORT
      LAYER M3 ;
      RECT 77.967 0.000 77.985 0.054 ;
    END
  END w0_wd_in[436]
  PIN w0_wd_in[437]
    DIRECTION INPUT ;
    USE SIGNAL ;
    SHAPE ABUTMENT ;
    PORT
      LAYER M3 ;
      RECT 78.399 0.000 78.417 0.054 ;
    END
  END w0_wd_in[437]
  PIN w0_wd_in[438]
    DIRECTION INPUT ;
    USE SIGNAL ;
    SHAPE ABUTMENT ;
    PORT
      LAYER M3 ;
      RECT 78.831 0.000 78.849 0.054 ;
    END
  END w0_wd_in[438]
  PIN w0_wd_in[439]
    DIRECTION INPUT ;
    USE SIGNAL ;
    SHAPE ABUTMENT ;
    PORT
      LAYER M3 ;
      RECT 79.263 0.000 79.281 0.054 ;
    END
  END w0_wd_in[439]
  PIN w0_wd_in[440]
    DIRECTION INPUT ;
    USE SIGNAL ;
    SHAPE ABUTMENT ;
    PORT
      LAYER M3 ;
      RECT 79.695 0.000 79.713 0.054 ;
    END
  END w0_wd_in[440]
  PIN w0_wd_in[441]
    DIRECTION INPUT ;
    USE SIGNAL ;
    SHAPE ABUTMENT ;
    PORT
      LAYER M3 ;
      RECT 80.127 0.000 80.145 0.054 ;
    END
  END w0_wd_in[441]
  PIN w0_wd_in[442]
    DIRECTION INPUT ;
    USE SIGNAL ;
    SHAPE ABUTMENT ;
    PORT
      LAYER M3 ;
      RECT 80.559 0.000 80.577 0.054 ;
    END
  END w0_wd_in[442]
  PIN w0_wd_in[443]
    DIRECTION INPUT ;
    USE SIGNAL ;
    SHAPE ABUTMENT ;
    PORT
      LAYER M3 ;
      RECT 80.991 0.000 81.009 0.054 ;
    END
  END w0_wd_in[443]
  PIN w0_wd_in[444]
    DIRECTION INPUT ;
    USE SIGNAL ;
    SHAPE ABUTMENT ;
    PORT
      LAYER M3 ;
      RECT 81.423 0.000 81.441 0.054 ;
    END
  END w0_wd_in[444]
  PIN w0_wd_in[445]
    DIRECTION INPUT ;
    USE SIGNAL ;
    SHAPE ABUTMENT ;
    PORT
      LAYER M3 ;
      RECT 81.855 0.000 81.873 0.054 ;
    END
  END w0_wd_in[445]
  PIN w0_wd_in[446]
    DIRECTION INPUT ;
    USE SIGNAL ;
    SHAPE ABUTMENT ;
    PORT
      LAYER M3 ;
      RECT 82.287 0.000 82.305 0.054 ;
    END
  END w0_wd_in[446]
  PIN w0_wd_in[447]
    DIRECTION INPUT ;
    USE SIGNAL ;
    SHAPE ABUTMENT ;
    PORT
      LAYER M3 ;
      RECT 82.719 0.000 82.737 0.054 ;
    END
  END w0_wd_in[447]
  PIN w0_wd_in[448]
    DIRECTION INPUT ;
    USE SIGNAL ;
    SHAPE ABUTMENT ;
    PORT
      LAYER M3 ;
      RECT 83.151 0.000 83.169 0.054 ;
    END
  END w0_wd_in[448]
  PIN w0_wd_in[449]
    DIRECTION INPUT ;
    USE SIGNAL ;
    SHAPE ABUTMENT ;
    PORT
      LAYER M3 ;
      RECT 83.583 0.000 83.601 0.054 ;
    END
  END w0_wd_in[449]
  PIN w0_wd_in[450]
    DIRECTION INPUT ;
    USE SIGNAL ;
    SHAPE ABUTMENT ;
    PORT
      LAYER M3 ;
      RECT 84.015 0.000 84.033 0.054 ;
    END
  END w0_wd_in[450]
  PIN w0_wd_in[451]
    DIRECTION INPUT ;
    USE SIGNAL ;
    SHAPE ABUTMENT ;
    PORT
      LAYER M3 ;
      RECT 84.447 0.000 84.465 0.054 ;
    END
  END w0_wd_in[451]
  PIN w0_wd_in[452]
    DIRECTION INPUT ;
    USE SIGNAL ;
    SHAPE ABUTMENT ;
    PORT
      LAYER M3 ;
      RECT 84.879 0.000 84.897 0.054 ;
    END
  END w0_wd_in[452]
  PIN w0_wd_in[453]
    DIRECTION INPUT ;
    USE SIGNAL ;
    SHAPE ABUTMENT ;
    PORT
      LAYER M3 ;
      RECT 85.311 0.000 85.329 0.054 ;
    END
  END w0_wd_in[453]
  PIN w0_wd_in[454]
    DIRECTION INPUT ;
    USE SIGNAL ;
    SHAPE ABUTMENT ;
    PORT
      LAYER M3 ;
      RECT 85.743 0.000 85.761 0.054 ;
    END
  END w0_wd_in[454]
  PIN w0_wd_in[455]
    DIRECTION INPUT ;
    USE SIGNAL ;
    SHAPE ABUTMENT ;
    PORT
      LAYER M3 ;
      RECT 86.175 0.000 86.193 0.054 ;
    END
  END w0_wd_in[455]
  PIN w0_wd_in[456]
    DIRECTION INPUT ;
    USE SIGNAL ;
    SHAPE ABUTMENT ;
    PORT
      LAYER M3 ;
      RECT 86.607 0.000 86.625 0.054 ;
    END
  END w0_wd_in[456]
  PIN w0_wd_in[457]
    DIRECTION INPUT ;
    USE SIGNAL ;
    SHAPE ABUTMENT ;
    PORT
      LAYER M3 ;
      RECT 87.039 0.000 87.057 0.054 ;
    END
  END w0_wd_in[457]
  PIN w0_wd_in[458]
    DIRECTION INPUT ;
    USE SIGNAL ;
    SHAPE ABUTMENT ;
    PORT
      LAYER M3 ;
      RECT 87.471 0.000 87.489 0.054 ;
    END
  END w0_wd_in[458]
  PIN w0_wd_in[459]
    DIRECTION INPUT ;
    USE SIGNAL ;
    SHAPE ABUTMENT ;
    PORT
      LAYER M3 ;
      RECT 87.903 0.000 87.921 0.054 ;
    END
  END w0_wd_in[459]
  PIN w0_wd_in[460]
    DIRECTION INPUT ;
    USE SIGNAL ;
    SHAPE ABUTMENT ;
    PORT
      LAYER M3 ;
      RECT 88.335 0.000 88.353 0.054 ;
    END
  END w0_wd_in[460]
  PIN w0_wd_in[461]
    DIRECTION INPUT ;
    USE SIGNAL ;
    SHAPE ABUTMENT ;
    PORT
      LAYER M3 ;
      RECT 88.767 0.000 88.785 0.054 ;
    END
  END w0_wd_in[461]
  PIN w0_wd_in[462]
    DIRECTION INPUT ;
    USE SIGNAL ;
    SHAPE ABUTMENT ;
    PORT
      LAYER M3 ;
      RECT 89.199 0.000 89.217 0.054 ;
    END
  END w0_wd_in[462]
  PIN w0_wd_in[463]
    DIRECTION INPUT ;
    USE SIGNAL ;
    SHAPE ABUTMENT ;
    PORT
      LAYER M3 ;
      RECT 89.631 0.000 89.649 0.054 ;
    END
  END w0_wd_in[463]
  PIN w0_wd_in[464]
    DIRECTION INPUT ;
    USE SIGNAL ;
    SHAPE ABUTMENT ;
    PORT
      LAYER M3 ;
      RECT 90.063 0.000 90.081 0.054 ;
    END
  END w0_wd_in[464]
  PIN w0_wd_in[465]
    DIRECTION INPUT ;
    USE SIGNAL ;
    SHAPE ABUTMENT ;
    PORT
      LAYER M3 ;
      RECT 90.495 0.000 90.513 0.054 ;
    END
  END w0_wd_in[465]
  PIN w0_wd_in[466]
    DIRECTION INPUT ;
    USE SIGNAL ;
    SHAPE ABUTMENT ;
    PORT
      LAYER M3 ;
      RECT 90.927 0.000 90.945 0.054 ;
    END
  END w0_wd_in[466]
  PIN w0_wd_in[467]
    DIRECTION INPUT ;
    USE SIGNAL ;
    SHAPE ABUTMENT ;
    PORT
      LAYER M3 ;
      RECT 91.359 0.000 91.377 0.054 ;
    END
  END w0_wd_in[467]
  PIN w0_wd_in[468]
    DIRECTION INPUT ;
    USE SIGNAL ;
    SHAPE ABUTMENT ;
    PORT
      LAYER M3 ;
      RECT 91.791 0.000 91.809 0.054 ;
    END
  END w0_wd_in[468]
  PIN w0_wd_in[469]
    DIRECTION INPUT ;
    USE SIGNAL ;
    SHAPE ABUTMENT ;
    PORT
      LAYER M3 ;
      RECT 92.223 0.000 92.241 0.054 ;
    END
  END w0_wd_in[469]
  PIN w0_wd_in[470]
    DIRECTION INPUT ;
    USE SIGNAL ;
    SHAPE ABUTMENT ;
    PORT
      LAYER M3 ;
      RECT 92.655 0.000 92.673 0.054 ;
    END
  END w0_wd_in[470]
  PIN w0_wd_in[471]
    DIRECTION INPUT ;
    USE SIGNAL ;
    SHAPE ABUTMENT ;
    PORT
      LAYER M3 ;
      RECT 93.087 0.000 93.105 0.054 ;
    END
  END w0_wd_in[471]
  PIN w0_wd_in[472]
    DIRECTION INPUT ;
    USE SIGNAL ;
    SHAPE ABUTMENT ;
    PORT
      LAYER M3 ;
      RECT 93.519 0.000 93.537 0.054 ;
    END
  END w0_wd_in[472]
  PIN w0_wd_in[473]
    DIRECTION INPUT ;
    USE SIGNAL ;
    SHAPE ABUTMENT ;
    PORT
      LAYER M3 ;
      RECT 93.951 0.000 93.969 0.054 ;
    END
  END w0_wd_in[473]
  PIN w0_wd_in[474]
    DIRECTION INPUT ;
    USE SIGNAL ;
    SHAPE ABUTMENT ;
    PORT
      LAYER M3 ;
      RECT 94.383 0.000 94.401 0.054 ;
    END
  END w0_wd_in[474]
  PIN w0_wd_in[475]
    DIRECTION INPUT ;
    USE SIGNAL ;
    SHAPE ABUTMENT ;
    PORT
      LAYER M3 ;
      RECT 94.815 0.000 94.833 0.054 ;
    END
  END w0_wd_in[475]
  PIN w0_wd_in[476]
    DIRECTION INPUT ;
    USE SIGNAL ;
    SHAPE ABUTMENT ;
    PORT
      LAYER M3 ;
      RECT 95.247 0.000 95.265 0.054 ;
    END
  END w0_wd_in[476]
  PIN w0_wd_in[477]
    DIRECTION INPUT ;
    USE SIGNAL ;
    SHAPE ABUTMENT ;
    PORT
      LAYER M3 ;
      RECT 95.679 0.000 95.697 0.054 ;
    END
  END w0_wd_in[477]
  PIN w0_wd_in[478]
    DIRECTION INPUT ;
    USE SIGNAL ;
    SHAPE ABUTMENT ;
    PORT
      LAYER M3 ;
      RECT 96.111 0.000 96.129 0.054 ;
    END
  END w0_wd_in[478]
  PIN w0_wd_in[479]
    DIRECTION INPUT ;
    USE SIGNAL ;
    SHAPE ABUTMENT ;
    PORT
      LAYER M3 ;
      RECT 96.543 0.000 96.561 0.054 ;
    END
  END w0_wd_in[479]
  PIN w0_wd_in[480]
    DIRECTION INPUT ;
    USE SIGNAL ;
    SHAPE ABUTMENT ;
    PORT
      LAYER M3 ;
      RECT 96.975 0.000 96.993 0.054 ;
    END
  END w0_wd_in[480]
  PIN w0_wd_in[481]
    DIRECTION INPUT ;
    USE SIGNAL ;
    SHAPE ABUTMENT ;
    PORT
      LAYER M3 ;
      RECT 97.407 0.000 97.425 0.054 ;
    END
  END w0_wd_in[481]
  PIN w0_wd_in[482]
    DIRECTION INPUT ;
    USE SIGNAL ;
    SHAPE ABUTMENT ;
    PORT
      LAYER M3 ;
      RECT 97.839 0.000 97.857 0.054 ;
    END
  END w0_wd_in[482]
  PIN w0_wd_in[483]
    DIRECTION INPUT ;
    USE SIGNAL ;
    SHAPE ABUTMENT ;
    PORT
      LAYER M3 ;
      RECT 98.271 0.000 98.289 0.054 ;
    END
  END w0_wd_in[483]
  PIN w0_wd_in[484]
    DIRECTION INPUT ;
    USE SIGNAL ;
    SHAPE ABUTMENT ;
    PORT
      LAYER M3 ;
      RECT 98.703 0.000 98.721 0.054 ;
    END
  END w0_wd_in[484]
  PIN w0_wd_in[485]
    DIRECTION INPUT ;
    USE SIGNAL ;
    SHAPE ABUTMENT ;
    PORT
      LAYER M3 ;
      RECT 99.135 0.000 99.153 0.054 ;
    END
  END w0_wd_in[485]
  PIN w0_wd_in[486]
    DIRECTION INPUT ;
    USE SIGNAL ;
    SHAPE ABUTMENT ;
    PORT
      LAYER M3 ;
      RECT 99.567 0.000 99.585 0.054 ;
    END
  END w0_wd_in[486]
  PIN w0_wd_in[487]
    DIRECTION INPUT ;
    USE SIGNAL ;
    SHAPE ABUTMENT ;
    PORT
      LAYER M3 ;
      RECT 99.999 0.000 100.017 0.054 ;
    END
  END w0_wd_in[487]
  PIN w0_wd_in[488]
    DIRECTION INPUT ;
    USE SIGNAL ;
    SHAPE ABUTMENT ;
    PORT
      LAYER M3 ;
      RECT 100.431 0.000 100.449 0.054 ;
    END
  END w0_wd_in[488]
  PIN w0_wd_in[489]
    DIRECTION INPUT ;
    USE SIGNAL ;
    SHAPE ABUTMENT ;
    PORT
      LAYER M3 ;
      RECT 100.863 0.000 100.881 0.054 ;
    END
  END w0_wd_in[489]
  PIN w0_wd_in[490]
    DIRECTION INPUT ;
    USE SIGNAL ;
    SHAPE ABUTMENT ;
    PORT
      LAYER M3 ;
      RECT 101.295 0.000 101.313 0.054 ;
    END
  END w0_wd_in[490]
  PIN w0_wd_in[491]
    DIRECTION INPUT ;
    USE SIGNAL ;
    SHAPE ABUTMENT ;
    PORT
      LAYER M3 ;
      RECT 101.727 0.000 101.745 0.054 ;
    END
  END w0_wd_in[491]
  PIN w0_wd_in[492]
    DIRECTION INPUT ;
    USE SIGNAL ;
    SHAPE ABUTMENT ;
    PORT
      LAYER M3 ;
      RECT 102.159 0.000 102.177 0.054 ;
    END
  END w0_wd_in[492]
  PIN w0_wd_in[493]
    DIRECTION INPUT ;
    USE SIGNAL ;
    SHAPE ABUTMENT ;
    PORT
      LAYER M3 ;
      RECT 102.591 0.000 102.609 0.054 ;
    END
  END w0_wd_in[493]
  PIN w0_wd_in[494]
    DIRECTION INPUT ;
    USE SIGNAL ;
    SHAPE ABUTMENT ;
    PORT
      LAYER M3 ;
      RECT 103.023 0.000 103.041 0.054 ;
    END
  END w0_wd_in[494]
  PIN w0_wd_in[495]
    DIRECTION INPUT ;
    USE SIGNAL ;
    SHAPE ABUTMENT ;
    PORT
      LAYER M3 ;
      RECT 103.455 0.000 103.473 0.054 ;
    END
  END w0_wd_in[495]
  PIN w0_wd_in[496]
    DIRECTION INPUT ;
    USE SIGNAL ;
    SHAPE ABUTMENT ;
    PORT
      LAYER M3 ;
      RECT 103.887 0.000 103.905 0.054 ;
    END
  END w0_wd_in[496]
  PIN w0_wd_in[497]
    DIRECTION INPUT ;
    USE SIGNAL ;
    SHAPE ABUTMENT ;
    PORT
      LAYER M3 ;
      RECT 104.319 0.000 104.337 0.054 ;
    END
  END w0_wd_in[497]
  PIN w0_wd_in[498]
    DIRECTION INPUT ;
    USE SIGNAL ;
    SHAPE ABUTMENT ;
    PORT
      LAYER M3 ;
      RECT 104.751 0.000 104.769 0.054 ;
    END
  END w0_wd_in[498]
  PIN w0_wd_in[499]
    DIRECTION INPUT ;
    USE SIGNAL ;
    SHAPE ABUTMENT ;
    PORT
      LAYER M3 ;
      RECT 105.183 0.000 105.201 0.054 ;
    END
  END w0_wd_in[499]
  PIN w0_wd_in[500]
    DIRECTION INPUT ;
    USE SIGNAL ;
    SHAPE ABUTMENT ;
    PORT
      LAYER M3 ;
      RECT 105.615 0.000 105.633 0.054 ;
    END
  END w0_wd_in[500]
  PIN w0_wd_in[501]
    DIRECTION INPUT ;
    USE SIGNAL ;
    SHAPE ABUTMENT ;
    PORT
      LAYER M3 ;
      RECT 106.047 0.000 106.065 0.054 ;
    END
  END w0_wd_in[501]
  PIN w0_wd_in[502]
    DIRECTION INPUT ;
    USE SIGNAL ;
    SHAPE ABUTMENT ;
    PORT
      LAYER M3 ;
      RECT 106.479 0.000 106.497 0.054 ;
    END
  END w0_wd_in[502]
  PIN w0_wd_in[503]
    DIRECTION INPUT ;
    USE SIGNAL ;
    SHAPE ABUTMENT ;
    PORT
      LAYER M3 ;
      RECT 106.911 0.000 106.929 0.054 ;
    END
  END w0_wd_in[503]
  PIN w0_wd_in[504]
    DIRECTION INPUT ;
    USE SIGNAL ;
    SHAPE ABUTMENT ;
    PORT
      LAYER M3 ;
      RECT 107.343 0.000 107.361 0.054 ;
    END
  END w0_wd_in[504]
  PIN w0_wd_in[505]
    DIRECTION INPUT ;
    USE SIGNAL ;
    SHAPE ABUTMENT ;
    PORT
      LAYER M3 ;
      RECT 107.775 0.000 107.793 0.054 ;
    END
  END w0_wd_in[505]
  PIN w0_wd_in[506]
    DIRECTION INPUT ;
    USE SIGNAL ;
    SHAPE ABUTMENT ;
    PORT
      LAYER M3 ;
      RECT 108.207 0.000 108.225 0.054 ;
    END
  END w0_wd_in[506]
  PIN w0_wd_in[507]
    DIRECTION INPUT ;
    USE SIGNAL ;
    SHAPE ABUTMENT ;
    PORT
      LAYER M3 ;
      RECT 108.639 0.000 108.657 0.054 ;
    END
  END w0_wd_in[507]
  PIN w0_wd_in[508]
    DIRECTION INPUT ;
    USE SIGNAL ;
    SHAPE ABUTMENT ;
    PORT
      LAYER M3 ;
      RECT 109.071 0.000 109.089 0.054 ;
    END
  END w0_wd_in[508]
  PIN w0_wd_in[509]
    DIRECTION INPUT ;
    USE SIGNAL ;
    SHAPE ABUTMENT ;
    PORT
      LAYER M3 ;
      RECT 109.503 0.000 109.521 0.054 ;
    END
  END w0_wd_in[509]
  PIN w0_wd_in[510]
    DIRECTION INPUT ;
    USE SIGNAL ;
    SHAPE ABUTMENT ;
    PORT
      LAYER M3 ;
      RECT 109.935 0.000 109.953 0.054 ;
    END
  END w0_wd_in[510]
  PIN w0_wd_in[511]
    DIRECTION INPUT ;
    USE SIGNAL ;
    SHAPE ABUTMENT ;
    PORT
      LAYER M3 ;
      RECT 110.367 0.000 110.385 0.054 ;
    END
  END w0_wd_in[511]
  PIN r0_rd_out[0]
    DIRECTION OUTPUT ;
    USE SIGNAL ;
    SHAPE ABUTMENT ;
    PORT
      LAYER M3 ;
      RECT 110.799 0.000 110.817 0.054 ;
    END
  END r0_rd_out[0]
  PIN r0_rd_out[1]
    DIRECTION OUTPUT ;
    USE SIGNAL ;
    SHAPE ABUTMENT ;
    PORT
      LAYER M3 ;
      RECT 111.231 0.000 111.249 0.054 ;
    END
  END r0_rd_out[1]
  PIN r0_rd_out[2]
    DIRECTION OUTPUT ;
    USE SIGNAL ;
    SHAPE ABUTMENT ;
    PORT
      LAYER M3 ;
      RECT 111.663 0.000 111.681 0.054 ;
    END
  END r0_rd_out[2]
  PIN r0_rd_out[3]
    DIRECTION OUTPUT ;
    USE SIGNAL ;
    SHAPE ABUTMENT ;
    PORT
      LAYER M3 ;
      RECT 112.095 0.000 112.113 0.054 ;
    END
  END r0_rd_out[3]
  PIN r0_rd_out[4]
    DIRECTION OUTPUT ;
    USE SIGNAL ;
    SHAPE ABUTMENT ;
    PORT
      LAYER M3 ;
      RECT 112.527 0.000 112.545 0.054 ;
    END
  END r0_rd_out[4]
  PIN r0_rd_out[5]
    DIRECTION OUTPUT ;
    USE SIGNAL ;
    SHAPE ABUTMENT ;
    PORT
      LAYER M3 ;
      RECT 112.959 0.000 112.977 0.054 ;
    END
  END r0_rd_out[5]
  PIN r0_rd_out[6]
    DIRECTION OUTPUT ;
    USE SIGNAL ;
    SHAPE ABUTMENT ;
    PORT
      LAYER M3 ;
      RECT 113.391 0.000 113.409 0.054 ;
    END
  END r0_rd_out[6]
  PIN r0_rd_out[7]
    DIRECTION OUTPUT ;
    USE SIGNAL ;
    SHAPE ABUTMENT ;
    PORT
      LAYER M3 ;
      RECT 113.823 0.000 113.841 0.054 ;
    END
  END r0_rd_out[7]
  PIN r0_rd_out[8]
    DIRECTION OUTPUT ;
    USE SIGNAL ;
    SHAPE ABUTMENT ;
    PORT
      LAYER M3 ;
      RECT 114.255 0.000 114.273 0.054 ;
    END
  END r0_rd_out[8]
  PIN r0_rd_out[9]
    DIRECTION OUTPUT ;
    USE SIGNAL ;
    SHAPE ABUTMENT ;
    PORT
      LAYER M3 ;
      RECT 114.687 0.000 114.705 0.054 ;
    END
  END r0_rd_out[9]
  PIN r0_rd_out[10]
    DIRECTION OUTPUT ;
    USE SIGNAL ;
    SHAPE ABUTMENT ;
    PORT
      LAYER M3 ;
      RECT 115.119 0.000 115.137 0.054 ;
    END
  END r0_rd_out[10]
  PIN r0_rd_out[11]
    DIRECTION OUTPUT ;
    USE SIGNAL ;
    SHAPE ABUTMENT ;
    PORT
      LAYER M3 ;
      RECT 115.551 0.000 115.569 0.054 ;
    END
  END r0_rd_out[11]
  PIN r0_rd_out[12]
    DIRECTION OUTPUT ;
    USE SIGNAL ;
    SHAPE ABUTMENT ;
    PORT
      LAYER M3 ;
      RECT 115.983 0.000 116.001 0.054 ;
    END
  END r0_rd_out[12]
  PIN r0_rd_out[13]
    DIRECTION OUTPUT ;
    USE SIGNAL ;
    SHAPE ABUTMENT ;
    PORT
      LAYER M3 ;
      RECT 116.415 0.000 116.433 0.054 ;
    END
  END r0_rd_out[13]
  PIN r0_rd_out[14]
    DIRECTION OUTPUT ;
    USE SIGNAL ;
    SHAPE ABUTMENT ;
    PORT
      LAYER M3 ;
      RECT 116.847 0.000 116.865 0.054 ;
    END
  END r0_rd_out[14]
  PIN r0_rd_out[15]
    DIRECTION OUTPUT ;
    USE SIGNAL ;
    SHAPE ABUTMENT ;
    PORT
      LAYER M3 ;
      RECT 117.279 0.000 117.297 0.054 ;
    END
  END r0_rd_out[15]
  PIN r0_rd_out[16]
    DIRECTION OUTPUT ;
    USE SIGNAL ;
    SHAPE ABUTMENT ;
    PORT
      LAYER M3 ;
      RECT 117.711 0.000 117.729 0.054 ;
    END
  END r0_rd_out[16]
  PIN r0_rd_out[17]
    DIRECTION OUTPUT ;
    USE SIGNAL ;
    SHAPE ABUTMENT ;
    PORT
      LAYER M3 ;
      RECT 118.143 0.000 118.161 0.054 ;
    END
  END r0_rd_out[17]
  PIN r0_rd_out[18]
    DIRECTION OUTPUT ;
    USE SIGNAL ;
    SHAPE ABUTMENT ;
    PORT
      LAYER M3 ;
      RECT 118.575 0.000 118.593 0.054 ;
    END
  END r0_rd_out[18]
  PIN r0_rd_out[19]
    DIRECTION OUTPUT ;
    USE SIGNAL ;
    SHAPE ABUTMENT ;
    PORT
      LAYER M3 ;
      RECT 119.007 0.000 119.025 0.054 ;
    END
  END r0_rd_out[19]
  PIN r0_rd_out[20]
    DIRECTION OUTPUT ;
    USE SIGNAL ;
    SHAPE ABUTMENT ;
    PORT
      LAYER M3 ;
      RECT 119.439 0.000 119.457 0.054 ;
    END
  END r0_rd_out[20]
  PIN r0_rd_out[21]
    DIRECTION OUTPUT ;
    USE SIGNAL ;
    SHAPE ABUTMENT ;
    PORT
      LAYER M3 ;
      RECT 119.871 0.000 119.889 0.054 ;
    END
  END r0_rd_out[21]
  PIN r0_rd_out[22]
    DIRECTION OUTPUT ;
    USE SIGNAL ;
    SHAPE ABUTMENT ;
    PORT
      LAYER M3 ;
      RECT 120.303 0.000 120.321 0.054 ;
    END
  END r0_rd_out[22]
  PIN r0_rd_out[23]
    DIRECTION OUTPUT ;
    USE SIGNAL ;
    SHAPE ABUTMENT ;
    PORT
      LAYER M3 ;
      RECT 120.735 0.000 120.753 0.054 ;
    END
  END r0_rd_out[23]
  PIN r0_rd_out[24]
    DIRECTION OUTPUT ;
    USE SIGNAL ;
    SHAPE ABUTMENT ;
    PORT
      LAYER M3 ;
      RECT 121.167 0.000 121.185 0.054 ;
    END
  END r0_rd_out[24]
  PIN r0_rd_out[25]
    DIRECTION OUTPUT ;
    USE SIGNAL ;
    SHAPE ABUTMENT ;
    PORT
      LAYER M3 ;
      RECT 121.599 0.000 121.617 0.054 ;
    END
  END r0_rd_out[25]
  PIN r0_rd_out[26]
    DIRECTION OUTPUT ;
    USE SIGNAL ;
    SHAPE ABUTMENT ;
    PORT
      LAYER M3 ;
      RECT 122.031 0.000 122.049 0.054 ;
    END
  END r0_rd_out[26]
  PIN r0_rd_out[27]
    DIRECTION OUTPUT ;
    USE SIGNAL ;
    SHAPE ABUTMENT ;
    PORT
      LAYER M3 ;
      RECT 122.463 0.000 122.481 0.054 ;
    END
  END r0_rd_out[27]
  PIN r0_rd_out[28]
    DIRECTION OUTPUT ;
    USE SIGNAL ;
    SHAPE ABUTMENT ;
    PORT
      LAYER M3 ;
      RECT 122.895 0.000 122.913 0.054 ;
    END
  END r0_rd_out[28]
  PIN r0_rd_out[29]
    DIRECTION OUTPUT ;
    USE SIGNAL ;
    SHAPE ABUTMENT ;
    PORT
      LAYER M3 ;
      RECT 123.327 0.000 123.345 0.054 ;
    END
  END r0_rd_out[29]
  PIN r0_rd_out[30]
    DIRECTION OUTPUT ;
    USE SIGNAL ;
    SHAPE ABUTMENT ;
    PORT
      LAYER M3 ;
      RECT 123.759 0.000 123.777 0.054 ;
    END
  END r0_rd_out[30]
  PIN r0_rd_out[31]
    DIRECTION OUTPUT ;
    USE SIGNAL ;
    SHAPE ABUTMENT ;
    PORT
      LAYER M3 ;
      RECT 124.191 0.000 124.209 0.054 ;
    END
  END r0_rd_out[31]
  PIN r0_rd_out[32]
    DIRECTION OUTPUT ;
    USE SIGNAL ;
    SHAPE ABUTMENT ;
    PORT
      LAYER M3 ;
      RECT 124.623 0.000 124.641 0.054 ;
    END
  END r0_rd_out[32]
  PIN r0_rd_out[33]
    DIRECTION OUTPUT ;
    USE SIGNAL ;
    SHAPE ABUTMENT ;
    PORT
      LAYER M3 ;
      RECT 125.055 0.000 125.073 0.054 ;
    END
  END r0_rd_out[33]
  PIN r0_rd_out[34]
    DIRECTION OUTPUT ;
    USE SIGNAL ;
    SHAPE ABUTMENT ;
    PORT
      LAYER M3 ;
      RECT 125.487 0.000 125.505 0.054 ;
    END
  END r0_rd_out[34]
  PIN r0_rd_out[35]
    DIRECTION OUTPUT ;
    USE SIGNAL ;
    SHAPE ABUTMENT ;
    PORT
      LAYER M3 ;
      RECT 125.919 0.000 125.937 0.054 ;
    END
  END r0_rd_out[35]
  PIN r0_rd_out[36]
    DIRECTION OUTPUT ;
    USE SIGNAL ;
    SHAPE ABUTMENT ;
    PORT
      LAYER M3 ;
      RECT 126.351 0.000 126.369 0.054 ;
    END
  END r0_rd_out[36]
  PIN r0_rd_out[37]
    DIRECTION OUTPUT ;
    USE SIGNAL ;
    SHAPE ABUTMENT ;
    PORT
      LAYER M3 ;
      RECT 126.783 0.000 126.801 0.054 ;
    END
  END r0_rd_out[37]
  PIN r0_rd_out[38]
    DIRECTION OUTPUT ;
    USE SIGNAL ;
    SHAPE ABUTMENT ;
    PORT
      LAYER M3 ;
      RECT 127.215 0.000 127.233 0.054 ;
    END
  END r0_rd_out[38]
  PIN r0_rd_out[39]
    DIRECTION OUTPUT ;
    USE SIGNAL ;
    SHAPE ABUTMENT ;
    PORT
      LAYER M3 ;
      RECT 127.647 0.000 127.665 0.054 ;
    END
  END r0_rd_out[39]
  PIN r0_rd_out[40]
    DIRECTION OUTPUT ;
    USE SIGNAL ;
    SHAPE ABUTMENT ;
    PORT
      LAYER M3 ;
      RECT 128.079 0.000 128.097 0.054 ;
    END
  END r0_rd_out[40]
  PIN r0_rd_out[41]
    DIRECTION OUTPUT ;
    USE SIGNAL ;
    SHAPE ABUTMENT ;
    PORT
      LAYER M3 ;
      RECT 128.511 0.000 128.529 0.054 ;
    END
  END r0_rd_out[41]
  PIN r0_rd_out[42]
    DIRECTION OUTPUT ;
    USE SIGNAL ;
    SHAPE ABUTMENT ;
    PORT
      LAYER M3 ;
      RECT 128.943 0.000 128.961 0.054 ;
    END
  END r0_rd_out[42]
  PIN r0_rd_out[43]
    DIRECTION OUTPUT ;
    USE SIGNAL ;
    SHAPE ABUTMENT ;
    PORT
      LAYER M3 ;
      RECT 129.375 0.000 129.393 0.054 ;
    END
  END r0_rd_out[43]
  PIN r0_rd_out[44]
    DIRECTION OUTPUT ;
    USE SIGNAL ;
    SHAPE ABUTMENT ;
    PORT
      LAYER M3 ;
      RECT 129.807 0.000 129.825 0.054 ;
    END
  END r0_rd_out[44]
  PIN r0_rd_out[45]
    DIRECTION OUTPUT ;
    USE SIGNAL ;
    SHAPE ABUTMENT ;
    PORT
      LAYER M3 ;
      RECT 130.239 0.000 130.257 0.054 ;
    END
  END r0_rd_out[45]
  PIN r0_rd_out[46]
    DIRECTION OUTPUT ;
    USE SIGNAL ;
    SHAPE ABUTMENT ;
    PORT
      LAYER M3 ;
      RECT 130.671 0.000 130.689 0.054 ;
    END
  END r0_rd_out[46]
  PIN r0_rd_out[47]
    DIRECTION OUTPUT ;
    USE SIGNAL ;
    SHAPE ABUTMENT ;
    PORT
      LAYER M3 ;
      RECT 131.103 0.000 131.121 0.054 ;
    END
  END r0_rd_out[47]
  PIN r0_rd_out[48]
    DIRECTION OUTPUT ;
    USE SIGNAL ;
    SHAPE ABUTMENT ;
    PORT
      LAYER M3 ;
      RECT 131.535 0.000 131.553 0.054 ;
    END
  END r0_rd_out[48]
  PIN r0_rd_out[49]
    DIRECTION OUTPUT ;
    USE SIGNAL ;
    SHAPE ABUTMENT ;
    PORT
      LAYER M3 ;
      RECT 131.967 0.000 131.985 0.054 ;
    END
  END r0_rd_out[49]
  PIN r0_rd_out[50]
    DIRECTION OUTPUT ;
    USE SIGNAL ;
    SHAPE ABUTMENT ;
    PORT
      LAYER M3 ;
      RECT 132.399 0.000 132.417 0.054 ;
    END
  END r0_rd_out[50]
  PIN r0_rd_out[51]
    DIRECTION OUTPUT ;
    USE SIGNAL ;
    SHAPE ABUTMENT ;
    PORT
      LAYER M3 ;
      RECT 132.831 0.000 132.849 0.054 ;
    END
  END r0_rd_out[51]
  PIN r0_rd_out[52]
    DIRECTION OUTPUT ;
    USE SIGNAL ;
    SHAPE ABUTMENT ;
    PORT
      LAYER M3 ;
      RECT 133.263 0.000 133.281 0.054 ;
    END
  END r0_rd_out[52]
  PIN r0_rd_out[53]
    DIRECTION OUTPUT ;
    USE SIGNAL ;
    SHAPE ABUTMENT ;
    PORT
      LAYER M3 ;
      RECT 133.695 0.000 133.713 0.054 ;
    END
  END r0_rd_out[53]
  PIN r0_rd_out[54]
    DIRECTION OUTPUT ;
    USE SIGNAL ;
    SHAPE ABUTMENT ;
    PORT
      LAYER M3 ;
      RECT 134.127 0.000 134.145 0.054 ;
    END
  END r0_rd_out[54]
  PIN r0_rd_out[55]
    DIRECTION OUTPUT ;
    USE SIGNAL ;
    SHAPE ABUTMENT ;
    PORT
      LAYER M3 ;
      RECT 134.559 0.000 134.577 0.054 ;
    END
  END r0_rd_out[55]
  PIN r0_rd_out[56]
    DIRECTION OUTPUT ;
    USE SIGNAL ;
    SHAPE ABUTMENT ;
    PORT
      LAYER M3 ;
      RECT 134.991 0.000 135.009 0.054 ;
    END
  END r0_rd_out[56]
  PIN r0_rd_out[57]
    DIRECTION OUTPUT ;
    USE SIGNAL ;
    SHAPE ABUTMENT ;
    PORT
      LAYER M3 ;
      RECT 135.423 0.000 135.441 0.054 ;
    END
  END r0_rd_out[57]
  PIN r0_rd_out[58]
    DIRECTION OUTPUT ;
    USE SIGNAL ;
    SHAPE ABUTMENT ;
    PORT
      LAYER M3 ;
      RECT 135.855 0.000 135.873 0.054 ;
    END
  END r0_rd_out[58]
  PIN r0_rd_out[59]
    DIRECTION OUTPUT ;
    USE SIGNAL ;
    SHAPE ABUTMENT ;
    PORT
      LAYER M3 ;
      RECT 136.287 0.000 136.305 0.054 ;
    END
  END r0_rd_out[59]
  PIN r0_rd_out[60]
    DIRECTION OUTPUT ;
    USE SIGNAL ;
    SHAPE ABUTMENT ;
    PORT
      LAYER M3 ;
      RECT 136.719 0.000 136.737 0.054 ;
    END
  END r0_rd_out[60]
  PIN r0_rd_out[61]
    DIRECTION OUTPUT ;
    USE SIGNAL ;
    SHAPE ABUTMENT ;
    PORT
      LAYER M3 ;
      RECT 137.151 0.000 137.169 0.054 ;
    END
  END r0_rd_out[61]
  PIN r0_rd_out[62]
    DIRECTION OUTPUT ;
    USE SIGNAL ;
    SHAPE ABUTMENT ;
    PORT
      LAYER M3 ;
      RECT 137.583 0.000 137.601 0.054 ;
    END
  END r0_rd_out[62]
  PIN r0_rd_out[63]
    DIRECTION OUTPUT ;
    USE SIGNAL ;
    SHAPE ABUTMENT ;
    PORT
      LAYER M3 ;
      RECT 138.015 0.000 138.033 0.054 ;
    END
  END r0_rd_out[63]
  PIN r0_rd_out[64]
    DIRECTION OUTPUT ;
    USE SIGNAL ;
    SHAPE ABUTMENT ;
    PORT
      LAYER M3 ;
      RECT 138.447 0.000 138.465 0.054 ;
    END
  END r0_rd_out[64]
  PIN r0_rd_out[65]
    DIRECTION OUTPUT ;
    USE SIGNAL ;
    SHAPE ABUTMENT ;
    PORT
      LAYER M3 ;
      RECT 138.879 0.000 138.897 0.054 ;
    END
  END r0_rd_out[65]
  PIN r0_rd_out[66]
    DIRECTION OUTPUT ;
    USE SIGNAL ;
    SHAPE ABUTMENT ;
    PORT
      LAYER M3 ;
      RECT 139.311 0.000 139.329 0.054 ;
    END
  END r0_rd_out[66]
  PIN r0_rd_out[67]
    DIRECTION OUTPUT ;
    USE SIGNAL ;
    SHAPE ABUTMENT ;
    PORT
      LAYER M3 ;
      RECT 139.743 0.000 139.761 0.054 ;
    END
  END r0_rd_out[67]
  PIN r0_rd_out[68]
    DIRECTION OUTPUT ;
    USE SIGNAL ;
    SHAPE ABUTMENT ;
    PORT
      LAYER M3 ;
      RECT 140.175 0.000 140.193 0.054 ;
    END
  END r0_rd_out[68]
  PIN r0_rd_out[69]
    DIRECTION OUTPUT ;
    USE SIGNAL ;
    SHAPE ABUTMENT ;
    PORT
      LAYER M3 ;
      RECT 140.607 0.000 140.625 0.054 ;
    END
  END r0_rd_out[69]
  PIN r0_rd_out[70]
    DIRECTION OUTPUT ;
    USE SIGNAL ;
    SHAPE ABUTMENT ;
    PORT
      LAYER M3 ;
      RECT 141.039 0.000 141.057 0.054 ;
    END
  END r0_rd_out[70]
  PIN r0_rd_out[71]
    DIRECTION OUTPUT ;
    USE SIGNAL ;
    SHAPE ABUTMENT ;
    PORT
      LAYER M3 ;
      RECT 141.471 0.000 141.489 0.054 ;
    END
  END r0_rd_out[71]
  PIN r0_rd_out[72]
    DIRECTION OUTPUT ;
    USE SIGNAL ;
    SHAPE ABUTMENT ;
    PORT
      LAYER M3 ;
      RECT 141.903 0.000 141.921 0.054 ;
    END
  END r0_rd_out[72]
  PIN r0_rd_out[73]
    DIRECTION OUTPUT ;
    USE SIGNAL ;
    SHAPE ABUTMENT ;
    PORT
      LAYER M3 ;
      RECT 142.335 0.000 142.353 0.054 ;
    END
  END r0_rd_out[73]
  PIN r0_rd_out[74]
    DIRECTION OUTPUT ;
    USE SIGNAL ;
    SHAPE ABUTMENT ;
    PORT
      LAYER M3 ;
      RECT 142.767 0.000 142.785 0.054 ;
    END
  END r0_rd_out[74]
  PIN r0_rd_out[75]
    DIRECTION OUTPUT ;
    USE SIGNAL ;
    SHAPE ABUTMENT ;
    PORT
      LAYER M3 ;
      RECT 143.199 0.000 143.217 0.054 ;
    END
  END r0_rd_out[75]
  PIN r0_rd_out[76]
    DIRECTION OUTPUT ;
    USE SIGNAL ;
    SHAPE ABUTMENT ;
    PORT
      LAYER M3 ;
      RECT 143.631 0.000 143.649 0.054 ;
    END
  END r0_rd_out[76]
  PIN r0_rd_out[77]
    DIRECTION OUTPUT ;
    USE SIGNAL ;
    SHAPE ABUTMENT ;
    PORT
      LAYER M3 ;
      RECT 144.063 0.000 144.081 0.054 ;
    END
  END r0_rd_out[77]
  PIN r0_rd_out[78]
    DIRECTION OUTPUT ;
    USE SIGNAL ;
    SHAPE ABUTMENT ;
    PORT
      LAYER M3 ;
      RECT 144.495 0.000 144.513 0.054 ;
    END
  END r0_rd_out[78]
  PIN r0_rd_out[79]
    DIRECTION OUTPUT ;
    USE SIGNAL ;
    SHAPE ABUTMENT ;
    PORT
      LAYER M3 ;
      RECT 144.927 0.000 144.945 0.054 ;
    END
  END r0_rd_out[79]
  PIN r0_rd_out[80]
    DIRECTION OUTPUT ;
    USE SIGNAL ;
    SHAPE ABUTMENT ;
    PORT
      LAYER M3 ;
      RECT 145.359 0.000 145.377 0.054 ;
    END
  END r0_rd_out[80]
  PIN r0_rd_out[81]
    DIRECTION OUTPUT ;
    USE SIGNAL ;
    SHAPE ABUTMENT ;
    PORT
      LAYER M3 ;
      RECT 145.791 0.000 145.809 0.054 ;
    END
  END r0_rd_out[81]
  PIN r0_rd_out[82]
    DIRECTION OUTPUT ;
    USE SIGNAL ;
    SHAPE ABUTMENT ;
    PORT
      LAYER M3 ;
      RECT 146.223 0.000 146.241 0.054 ;
    END
  END r0_rd_out[82]
  PIN r0_rd_out[83]
    DIRECTION OUTPUT ;
    USE SIGNAL ;
    SHAPE ABUTMENT ;
    PORT
      LAYER M3 ;
      RECT 146.655 0.000 146.673 0.054 ;
    END
  END r0_rd_out[83]
  PIN r0_rd_out[84]
    DIRECTION OUTPUT ;
    USE SIGNAL ;
    SHAPE ABUTMENT ;
    PORT
      LAYER M3 ;
      RECT 147.087 0.000 147.105 0.054 ;
    END
  END r0_rd_out[84]
  PIN r0_rd_out[85]
    DIRECTION OUTPUT ;
    USE SIGNAL ;
    SHAPE ABUTMENT ;
    PORT
      LAYER M3 ;
      RECT 147.519 0.000 147.537 0.054 ;
    END
  END r0_rd_out[85]
  PIN r0_rd_out[86]
    DIRECTION OUTPUT ;
    USE SIGNAL ;
    SHAPE ABUTMENT ;
    PORT
      LAYER M3 ;
      RECT 147.951 0.000 147.969 0.054 ;
    END
  END r0_rd_out[86]
  PIN r0_rd_out[87]
    DIRECTION OUTPUT ;
    USE SIGNAL ;
    SHAPE ABUTMENT ;
    PORT
      LAYER M3 ;
      RECT 148.383 0.000 148.401 0.054 ;
    END
  END r0_rd_out[87]
  PIN r0_rd_out[88]
    DIRECTION OUTPUT ;
    USE SIGNAL ;
    SHAPE ABUTMENT ;
    PORT
      LAYER M3 ;
      RECT 148.815 0.000 148.833 0.054 ;
    END
  END r0_rd_out[88]
  PIN r0_rd_out[89]
    DIRECTION OUTPUT ;
    USE SIGNAL ;
    SHAPE ABUTMENT ;
    PORT
      LAYER M3 ;
      RECT 149.247 0.000 149.265 0.054 ;
    END
  END r0_rd_out[89]
  PIN r0_rd_out[90]
    DIRECTION OUTPUT ;
    USE SIGNAL ;
    SHAPE ABUTMENT ;
    PORT
      LAYER M3 ;
      RECT 149.679 0.000 149.697 0.054 ;
    END
  END r0_rd_out[90]
  PIN r0_rd_out[91]
    DIRECTION OUTPUT ;
    USE SIGNAL ;
    SHAPE ABUTMENT ;
    PORT
      LAYER M3 ;
      RECT 150.111 0.000 150.129 0.054 ;
    END
  END r0_rd_out[91]
  PIN r0_rd_out[92]
    DIRECTION OUTPUT ;
    USE SIGNAL ;
    SHAPE ABUTMENT ;
    PORT
      LAYER M3 ;
      RECT 150.543 0.000 150.561 0.054 ;
    END
  END r0_rd_out[92]
  PIN r0_rd_out[93]
    DIRECTION OUTPUT ;
    USE SIGNAL ;
    SHAPE ABUTMENT ;
    PORT
      LAYER M3 ;
      RECT 150.975 0.000 150.993 0.054 ;
    END
  END r0_rd_out[93]
  PIN r0_rd_out[94]
    DIRECTION OUTPUT ;
    USE SIGNAL ;
    SHAPE ABUTMENT ;
    PORT
      LAYER M3 ;
      RECT 151.407 0.000 151.425 0.054 ;
    END
  END r0_rd_out[94]
  PIN r0_rd_out[95]
    DIRECTION OUTPUT ;
    USE SIGNAL ;
    SHAPE ABUTMENT ;
    PORT
      LAYER M3 ;
      RECT 151.839 0.000 151.857 0.054 ;
    END
  END r0_rd_out[95]
  PIN r0_rd_out[96]
    DIRECTION OUTPUT ;
    USE SIGNAL ;
    SHAPE ABUTMENT ;
    PORT
      LAYER M3 ;
      RECT 152.271 0.000 152.289 0.054 ;
    END
  END r0_rd_out[96]
  PIN r0_rd_out[97]
    DIRECTION OUTPUT ;
    USE SIGNAL ;
    SHAPE ABUTMENT ;
    PORT
      LAYER M3 ;
      RECT 152.703 0.000 152.721 0.054 ;
    END
  END r0_rd_out[97]
  PIN r0_rd_out[98]
    DIRECTION OUTPUT ;
    USE SIGNAL ;
    SHAPE ABUTMENT ;
    PORT
      LAYER M3 ;
      RECT 153.135 0.000 153.153 0.054 ;
    END
  END r0_rd_out[98]
  PIN r0_rd_out[99]
    DIRECTION OUTPUT ;
    USE SIGNAL ;
    SHAPE ABUTMENT ;
    PORT
      LAYER M3 ;
      RECT 153.567 0.000 153.585 0.054 ;
    END
  END r0_rd_out[99]
  PIN r0_rd_out[100]
    DIRECTION OUTPUT ;
    USE SIGNAL ;
    SHAPE ABUTMENT ;
    PORT
      LAYER M3 ;
      RECT 153.999 0.000 154.017 0.054 ;
    END
  END r0_rd_out[100]
  PIN r0_rd_out[101]
    DIRECTION OUTPUT ;
    USE SIGNAL ;
    SHAPE ABUTMENT ;
    PORT
      LAYER M3 ;
      RECT 154.431 0.000 154.449 0.054 ;
    END
  END r0_rd_out[101]
  PIN r0_rd_out[102]
    DIRECTION OUTPUT ;
    USE SIGNAL ;
    SHAPE ABUTMENT ;
    PORT
      LAYER M3 ;
      RECT 154.863 0.000 154.881 0.054 ;
    END
  END r0_rd_out[102]
  PIN r0_rd_out[103]
    DIRECTION OUTPUT ;
    USE SIGNAL ;
    SHAPE ABUTMENT ;
    PORT
      LAYER M3 ;
      RECT 155.295 0.000 155.313 0.054 ;
    END
  END r0_rd_out[103]
  PIN r0_rd_out[104]
    DIRECTION OUTPUT ;
    USE SIGNAL ;
    SHAPE ABUTMENT ;
    PORT
      LAYER M3 ;
      RECT 155.727 0.000 155.745 0.054 ;
    END
  END r0_rd_out[104]
  PIN r0_rd_out[105]
    DIRECTION OUTPUT ;
    USE SIGNAL ;
    SHAPE ABUTMENT ;
    PORT
      LAYER M3 ;
      RECT 156.159 0.000 156.177 0.054 ;
    END
  END r0_rd_out[105]
  PIN r0_rd_out[106]
    DIRECTION OUTPUT ;
    USE SIGNAL ;
    SHAPE ABUTMENT ;
    PORT
      LAYER M3 ;
      RECT 156.591 0.000 156.609 0.054 ;
    END
  END r0_rd_out[106]
  PIN r0_rd_out[107]
    DIRECTION OUTPUT ;
    USE SIGNAL ;
    SHAPE ABUTMENT ;
    PORT
      LAYER M3 ;
      RECT 157.023 0.000 157.041 0.054 ;
    END
  END r0_rd_out[107]
  PIN r0_rd_out[108]
    DIRECTION OUTPUT ;
    USE SIGNAL ;
    SHAPE ABUTMENT ;
    PORT
      LAYER M3 ;
      RECT 157.455 0.000 157.473 0.054 ;
    END
  END r0_rd_out[108]
  PIN r0_rd_out[109]
    DIRECTION OUTPUT ;
    USE SIGNAL ;
    SHAPE ABUTMENT ;
    PORT
      LAYER M3 ;
      RECT 157.887 0.000 157.905 0.054 ;
    END
  END r0_rd_out[109]
  PIN r0_rd_out[110]
    DIRECTION OUTPUT ;
    USE SIGNAL ;
    SHAPE ABUTMENT ;
    PORT
      LAYER M3 ;
      RECT 158.319 0.000 158.337 0.054 ;
    END
  END r0_rd_out[110]
  PIN r0_rd_out[111]
    DIRECTION OUTPUT ;
    USE SIGNAL ;
    SHAPE ABUTMENT ;
    PORT
      LAYER M3 ;
      RECT 158.751 0.000 158.769 0.054 ;
    END
  END r0_rd_out[111]
  PIN r0_rd_out[112]
    DIRECTION OUTPUT ;
    USE SIGNAL ;
    SHAPE ABUTMENT ;
    PORT
      LAYER M3 ;
      RECT 159.183 0.000 159.201 0.054 ;
    END
  END r0_rd_out[112]
  PIN r0_rd_out[113]
    DIRECTION OUTPUT ;
    USE SIGNAL ;
    SHAPE ABUTMENT ;
    PORT
      LAYER M3 ;
      RECT 159.615 0.000 159.633 0.054 ;
    END
  END r0_rd_out[113]
  PIN r0_rd_out[114]
    DIRECTION OUTPUT ;
    USE SIGNAL ;
    SHAPE ABUTMENT ;
    PORT
      LAYER M3 ;
      RECT 160.047 0.000 160.065 0.054 ;
    END
  END r0_rd_out[114]
  PIN r0_rd_out[115]
    DIRECTION OUTPUT ;
    USE SIGNAL ;
    SHAPE ABUTMENT ;
    PORT
      LAYER M3 ;
      RECT 160.479 0.000 160.497 0.054 ;
    END
  END r0_rd_out[115]
  PIN r0_rd_out[116]
    DIRECTION OUTPUT ;
    USE SIGNAL ;
    SHAPE ABUTMENT ;
    PORT
      LAYER M3 ;
      RECT 160.911 0.000 160.929 0.054 ;
    END
  END r0_rd_out[116]
  PIN r0_rd_out[117]
    DIRECTION OUTPUT ;
    USE SIGNAL ;
    SHAPE ABUTMENT ;
    PORT
      LAYER M3 ;
      RECT 161.343 0.000 161.361 0.054 ;
    END
  END r0_rd_out[117]
  PIN r0_rd_out[118]
    DIRECTION OUTPUT ;
    USE SIGNAL ;
    SHAPE ABUTMENT ;
    PORT
      LAYER M3 ;
      RECT 161.775 0.000 161.793 0.054 ;
    END
  END r0_rd_out[118]
  PIN r0_rd_out[119]
    DIRECTION OUTPUT ;
    USE SIGNAL ;
    SHAPE ABUTMENT ;
    PORT
      LAYER M3 ;
      RECT 162.207 0.000 162.225 0.054 ;
    END
  END r0_rd_out[119]
  PIN r0_rd_out[120]
    DIRECTION OUTPUT ;
    USE SIGNAL ;
    SHAPE ABUTMENT ;
    PORT
      LAYER M3 ;
      RECT 162.639 0.000 162.657 0.054 ;
    END
  END r0_rd_out[120]
  PIN r0_rd_out[121]
    DIRECTION OUTPUT ;
    USE SIGNAL ;
    SHAPE ABUTMENT ;
    PORT
      LAYER M3 ;
      RECT 163.071 0.000 163.089 0.054 ;
    END
  END r0_rd_out[121]
  PIN r0_rd_out[122]
    DIRECTION OUTPUT ;
    USE SIGNAL ;
    SHAPE ABUTMENT ;
    PORT
      LAYER M3 ;
      RECT 163.503 0.000 163.521 0.054 ;
    END
  END r0_rd_out[122]
  PIN r0_rd_out[123]
    DIRECTION OUTPUT ;
    USE SIGNAL ;
    SHAPE ABUTMENT ;
    PORT
      LAYER M3 ;
      RECT 163.935 0.000 163.953 0.054 ;
    END
  END r0_rd_out[123]
  PIN r0_rd_out[124]
    DIRECTION OUTPUT ;
    USE SIGNAL ;
    SHAPE ABUTMENT ;
    PORT
      LAYER M3 ;
      RECT 164.367 0.000 164.385 0.054 ;
    END
  END r0_rd_out[124]
  PIN r0_rd_out[125]
    DIRECTION OUTPUT ;
    USE SIGNAL ;
    SHAPE ABUTMENT ;
    PORT
      LAYER M3 ;
      RECT 164.799 0.000 164.817 0.054 ;
    END
  END r0_rd_out[125]
  PIN r0_rd_out[126]
    DIRECTION OUTPUT ;
    USE SIGNAL ;
    SHAPE ABUTMENT ;
    PORT
      LAYER M3 ;
      RECT 165.231 0.000 165.249 0.054 ;
    END
  END r0_rd_out[126]
  PIN r0_rd_out[127]
    DIRECTION OUTPUT ;
    USE SIGNAL ;
    SHAPE ABUTMENT ;
    PORT
      LAYER M3 ;
      RECT 165.663 0.000 165.681 0.054 ;
    END
  END r0_rd_out[127]
  PIN r0_rd_out[128]
    DIRECTION OUTPUT ;
    USE SIGNAL ;
    SHAPE ABUTMENT ;
    PORT
      LAYER M3 ;
      RECT 166.095 0.000 166.113 0.054 ;
    END
  END r0_rd_out[128]
  PIN r0_rd_out[129]
    DIRECTION OUTPUT ;
    USE SIGNAL ;
    SHAPE ABUTMENT ;
    PORT
      LAYER M3 ;
      RECT 166.527 0.000 166.545 0.054 ;
    END
  END r0_rd_out[129]
  PIN r0_rd_out[130]
    DIRECTION OUTPUT ;
    USE SIGNAL ;
    SHAPE ABUTMENT ;
    PORT
      LAYER M3 ;
      RECT 166.959 0.000 166.977 0.054 ;
    END
  END r0_rd_out[130]
  PIN r0_rd_out[131]
    DIRECTION OUTPUT ;
    USE SIGNAL ;
    SHAPE ABUTMENT ;
    PORT
      LAYER M3 ;
      RECT 167.391 0.000 167.409 0.054 ;
    END
  END r0_rd_out[131]
  PIN r0_rd_out[132]
    DIRECTION OUTPUT ;
    USE SIGNAL ;
    SHAPE ABUTMENT ;
    PORT
      LAYER M3 ;
      RECT 167.823 0.000 167.841 0.054 ;
    END
  END r0_rd_out[132]
  PIN r0_rd_out[133]
    DIRECTION OUTPUT ;
    USE SIGNAL ;
    SHAPE ABUTMENT ;
    PORT
      LAYER M3 ;
      RECT 168.255 0.000 168.273 0.054 ;
    END
  END r0_rd_out[133]
  PIN r0_rd_out[134]
    DIRECTION OUTPUT ;
    USE SIGNAL ;
    SHAPE ABUTMENT ;
    PORT
      LAYER M3 ;
      RECT 168.687 0.000 168.705 0.054 ;
    END
  END r0_rd_out[134]
  PIN r0_rd_out[135]
    DIRECTION OUTPUT ;
    USE SIGNAL ;
    SHAPE ABUTMENT ;
    PORT
      LAYER M3 ;
      RECT 169.119 0.000 169.137 0.054 ;
    END
  END r0_rd_out[135]
  PIN r0_rd_out[136]
    DIRECTION OUTPUT ;
    USE SIGNAL ;
    SHAPE ABUTMENT ;
    PORT
      LAYER M3 ;
      RECT 169.551 0.000 169.569 0.054 ;
    END
  END r0_rd_out[136]
  PIN r0_rd_out[137]
    DIRECTION OUTPUT ;
    USE SIGNAL ;
    SHAPE ABUTMENT ;
    PORT
      LAYER M3 ;
      RECT 169.983 0.000 170.001 0.054 ;
    END
  END r0_rd_out[137]
  PIN r0_rd_out[138]
    DIRECTION OUTPUT ;
    USE SIGNAL ;
    SHAPE ABUTMENT ;
    PORT
      LAYER M3 ;
      RECT 170.415 0.000 170.433 0.054 ;
    END
  END r0_rd_out[138]
  PIN r0_rd_out[139]
    DIRECTION OUTPUT ;
    USE SIGNAL ;
    SHAPE ABUTMENT ;
    PORT
      LAYER M3 ;
      RECT 170.847 0.000 170.865 0.054 ;
    END
  END r0_rd_out[139]
  PIN r0_rd_out[140]
    DIRECTION OUTPUT ;
    USE SIGNAL ;
    SHAPE ABUTMENT ;
    PORT
      LAYER M3 ;
      RECT 171.279 0.000 171.297 0.054 ;
    END
  END r0_rd_out[140]
  PIN r0_rd_out[141]
    DIRECTION OUTPUT ;
    USE SIGNAL ;
    SHAPE ABUTMENT ;
    PORT
      LAYER M3 ;
      RECT 171.711 0.000 171.729 0.054 ;
    END
  END r0_rd_out[141]
  PIN r0_rd_out[142]
    DIRECTION OUTPUT ;
    USE SIGNAL ;
    SHAPE ABUTMENT ;
    PORT
      LAYER M3 ;
      RECT 172.143 0.000 172.161 0.054 ;
    END
  END r0_rd_out[142]
  PIN r0_rd_out[143]
    DIRECTION OUTPUT ;
    USE SIGNAL ;
    SHAPE ABUTMENT ;
    PORT
      LAYER M3 ;
      RECT 172.575 0.000 172.593 0.054 ;
    END
  END r0_rd_out[143]
  PIN r0_rd_out[144]
    DIRECTION OUTPUT ;
    USE SIGNAL ;
    SHAPE ABUTMENT ;
    PORT
      LAYER M3 ;
      RECT 173.007 0.000 173.025 0.054 ;
    END
  END r0_rd_out[144]
  PIN r0_rd_out[145]
    DIRECTION OUTPUT ;
    USE SIGNAL ;
    SHAPE ABUTMENT ;
    PORT
      LAYER M3 ;
      RECT 173.439 0.000 173.457 0.054 ;
    END
  END r0_rd_out[145]
  PIN r0_rd_out[146]
    DIRECTION OUTPUT ;
    USE SIGNAL ;
    SHAPE ABUTMENT ;
    PORT
      LAYER M3 ;
      RECT 173.871 0.000 173.889 0.054 ;
    END
  END r0_rd_out[146]
  PIN r0_rd_out[147]
    DIRECTION OUTPUT ;
    USE SIGNAL ;
    SHAPE ABUTMENT ;
    PORT
      LAYER M3 ;
      RECT 174.303 0.000 174.321 0.054 ;
    END
  END r0_rd_out[147]
  PIN r0_rd_out[148]
    DIRECTION OUTPUT ;
    USE SIGNAL ;
    SHAPE ABUTMENT ;
    PORT
      LAYER M3 ;
      RECT 174.735 0.000 174.753 0.054 ;
    END
  END r0_rd_out[148]
  PIN r0_rd_out[149]
    DIRECTION OUTPUT ;
    USE SIGNAL ;
    SHAPE ABUTMENT ;
    PORT
      LAYER M3 ;
      RECT 175.167 0.000 175.185 0.054 ;
    END
  END r0_rd_out[149]
  PIN r0_rd_out[150]
    DIRECTION OUTPUT ;
    USE SIGNAL ;
    SHAPE ABUTMENT ;
    PORT
      LAYER M3 ;
      RECT 175.599 0.000 175.617 0.054 ;
    END
  END r0_rd_out[150]
  PIN r0_rd_out[151]
    DIRECTION OUTPUT ;
    USE SIGNAL ;
    SHAPE ABUTMENT ;
    PORT
      LAYER M3 ;
      RECT 176.031 0.000 176.049 0.054 ;
    END
  END r0_rd_out[151]
  PIN r0_rd_out[152]
    DIRECTION OUTPUT ;
    USE SIGNAL ;
    SHAPE ABUTMENT ;
    PORT
      LAYER M3 ;
      RECT 176.463 0.000 176.481 0.054 ;
    END
  END r0_rd_out[152]
  PIN r0_rd_out[153]
    DIRECTION OUTPUT ;
    USE SIGNAL ;
    SHAPE ABUTMENT ;
    PORT
      LAYER M3 ;
      RECT 176.895 0.000 176.913 0.054 ;
    END
  END r0_rd_out[153]
  PIN r0_rd_out[154]
    DIRECTION OUTPUT ;
    USE SIGNAL ;
    SHAPE ABUTMENT ;
    PORT
      LAYER M3 ;
      RECT 177.327 0.000 177.345 0.054 ;
    END
  END r0_rd_out[154]
  PIN r0_rd_out[155]
    DIRECTION OUTPUT ;
    USE SIGNAL ;
    SHAPE ABUTMENT ;
    PORT
      LAYER M3 ;
      RECT 177.759 0.000 177.777 0.054 ;
    END
  END r0_rd_out[155]
  PIN r0_rd_out[156]
    DIRECTION OUTPUT ;
    USE SIGNAL ;
    SHAPE ABUTMENT ;
    PORT
      LAYER M3 ;
      RECT 178.191 0.000 178.209 0.054 ;
    END
  END r0_rd_out[156]
  PIN r0_rd_out[157]
    DIRECTION OUTPUT ;
    USE SIGNAL ;
    SHAPE ABUTMENT ;
    PORT
      LAYER M3 ;
      RECT 178.623 0.000 178.641 0.054 ;
    END
  END r0_rd_out[157]
  PIN r0_rd_out[158]
    DIRECTION OUTPUT ;
    USE SIGNAL ;
    SHAPE ABUTMENT ;
    PORT
      LAYER M3 ;
      RECT 179.055 0.000 179.073 0.054 ;
    END
  END r0_rd_out[158]
  PIN r0_rd_out[159]
    DIRECTION OUTPUT ;
    USE SIGNAL ;
    SHAPE ABUTMENT ;
    PORT
      LAYER M3 ;
      RECT 179.487 0.000 179.505 0.054 ;
    END
  END r0_rd_out[159]
  PIN r0_rd_out[160]
    DIRECTION OUTPUT ;
    USE SIGNAL ;
    SHAPE ABUTMENT ;
    PORT
      LAYER M3 ;
      RECT 179.919 0.000 179.937 0.054 ;
    END
  END r0_rd_out[160]
  PIN r0_rd_out[161]
    DIRECTION OUTPUT ;
    USE SIGNAL ;
    SHAPE ABUTMENT ;
    PORT
      LAYER M3 ;
      RECT 180.351 0.000 180.369 0.054 ;
    END
  END r0_rd_out[161]
  PIN r0_rd_out[162]
    DIRECTION OUTPUT ;
    USE SIGNAL ;
    SHAPE ABUTMENT ;
    PORT
      LAYER M3 ;
      RECT 180.783 0.000 180.801 0.054 ;
    END
  END r0_rd_out[162]
  PIN r0_rd_out[163]
    DIRECTION OUTPUT ;
    USE SIGNAL ;
    SHAPE ABUTMENT ;
    PORT
      LAYER M3 ;
      RECT 181.215 0.000 181.233 0.054 ;
    END
  END r0_rd_out[163]
  PIN r0_rd_out[164]
    DIRECTION OUTPUT ;
    USE SIGNAL ;
    SHAPE ABUTMENT ;
    PORT
      LAYER M3 ;
      RECT 181.647 0.000 181.665 0.054 ;
    END
  END r0_rd_out[164]
  PIN r0_rd_out[165]
    DIRECTION OUTPUT ;
    USE SIGNAL ;
    SHAPE ABUTMENT ;
    PORT
      LAYER M3 ;
      RECT 182.079 0.000 182.097 0.054 ;
    END
  END r0_rd_out[165]
  PIN r0_rd_out[166]
    DIRECTION OUTPUT ;
    USE SIGNAL ;
    SHAPE ABUTMENT ;
    PORT
      LAYER M3 ;
      RECT 182.511 0.000 182.529 0.054 ;
    END
  END r0_rd_out[166]
  PIN r0_rd_out[167]
    DIRECTION OUTPUT ;
    USE SIGNAL ;
    SHAPE ABUTMENT ;
    PORT
      LAYER M3 ;
      RECT 182.943 0.000 182.961 0.054 ;
    END
  END r0_rd_out[167]
  PIN r0_rd_out[168]
    DIRECTION OUTPUT ;
    USE SIGNAL ;
    SHAPE ABUTMENT ;
    PORT
      LAYER M3 ;
      RECT 183.375 0.000 183.393 0.054 ;
    END
  END r0_rd_out[168]
  PIN r0_rd_out[169]
    DIRECTION OUTPUT ;
    USE SIGNAL ;
    SHAPE ABUTMENT ;
    PORT
      LAYER M3 ;
      RECT 183.807 0.000 183.825 0.054 ;
    END
  END r0_rd_out[169]
  PIN r0_rd_out[170]
    DIRECTION OUTPUT ;
    USE SIGNAL ;
    SHAPE ABUTMENT ;
    PORT
      LAYER M3 ;
      RECT 184.239 0.000 184.257 0.054 ;
    END
  END r0_rd_out[170]
  PIN r0_rd_out[171]
    DIRECTION OUTPUT ;
    USE SIGNAL ;
    SHAPE ABUTMENT ;
    PORT
      LAYER M3 ;
      RECT 184.671 0.000 184.689 0.054 ;
    END
  END r0_rd_out[171]
  PIN r0_rd_out[172]
    DIRECTION OUTPUT ;
    USE SIGNAL ;
    SHAPE ABUTMENT ;
    PORT
      LAYER M3 ;
      RECT 185.103 0.000 185.121 0.054 ;
    END
  END r0_rd_out[172]
  PIN r0_rd_out[173]
    DIRECTION OUTPUT ;
    USE SIGNAL ;
    SHAPE ABUTMENT ;
    PORT
      LAYER M3 ;
      RECT 185.535 0.000 185.553 0.054 ;
    END
  END r0_rd_out[173]
  PIN r0_rd_out[174]
    DIRECTION OUTPUT ;
    USE SIGNAL ;
    SHAPE ABUTMENT ;
    PORT
      LAYER M3 ;
      RECT 185.967 0.000 185.985 0.054 ;
    END
  END r0_rd_out[174]
  PIN r0_rd_out[175]
    DIRECTION OUTPUT ;
    USE SIGNAL ;
    SHAPE ABUTMENT ;
    PORT
      LAYER M3 ;
      RECT 186.399 0.000 186.417 0.054 ;
    END
  END r0_rd_out[175]
  PIN r0_rd_out[176]
    DIRECTION OUTPUT ;
    USE SIGNAL ;
    SHAPE ABUTMENT ;
    PORT
      LAYER M3 ;
      RECT 186.831 0.000 186.849 0.054 ;
    END
  END r0_rd_out[176]
  PIN r0_rd_out[177]
    DIRECTION OUTPUT ;
    USE SIGNAL ;
    SHAPE ABUTMENT ;
    PORT
      LAYER M3 ;
      RECT 187.263 0.000 187.281 0.054 ;
    END
  END r0_rd_out[177]
  PIN r0_rd_out[178]
    DIRECTION OUTPUT ;
    USE SIGNAL ;
    SHAPE ABUTMENT ;
    PORT
      LAYER M3 ;
      RECT 187.695 0.000 187.713 0.054 ;
    END
  END r0_rd_out[178]
  PIN r0_rd_out[179]
    DIRECTION OUTPUT ;
    USE SIGNAL ;
    SHAPE ABUTMENT ;
    PORT
      LAYER M3 ;
      RECT 188.127 0.000 188.145 0.054 ;
    END
  END r0_rd_out[179]
  PIN r0_rd_out[180]
    DIRECTION OUTPUT ;
    USE SIGNAL ;
    SHAPE ABUTMENT ;
    PORT
      LAYER M3 ;
      RECT 188.559 0.000 188.577 0.054 ;
    END
  END r0_rd_out[180]
  PIN r0_rd_out[181]
    DIRECTION OUTPUT ;
    USE SIGNAL ;
    SHAPE ABUTMENT ;
    PORT
      LAYER M3 ;
      RECT 188.991 0.000 189.009 0.054 ;
    END
  END r0_rd_out[181]
  PIN r0_rd_out[182]
    DIRECTION OUTPUT ;
    USE SIGNAL ;
    SHAPE ABUTMENT ;
    PORT
      LAYER M3 ;
      RECT 189.423 0.000 189.441 0.054 ;
    END
  END r0_rd_out[182]
  PIN r0_rd_out[183]
    DIRECTION OUTPUT ;
    USE SIGNAL ;
    SHAPE ABUTMENT ;
    PORT
      LAYER M3 ;
      RECT 189.855 0.000 189.873 0.054 ;
    END
  END r0_rd_out[183]
  PIN r0_rd_out[184]
    DIRECTION OUTPUT ;
    USE SIGNAL ;
    SHAPE ABUTMENT ;
    PORT
      LAYER M3 ;
      RECT 190.287 0.000 190.305 0.054 ;
    END
  END r0_rd_out[184]
  PIN r0_rd_out[185]
    DIRECTION OUTPUT ;
    USE SIGNAL ;
    SHAPE ABUTMENT ;
    PORT
      LAYER M3 ;
      RECT 190.719 0.000 190.737 0.054 ;
    END
  END r0_rd_out[185]
  PIN r0_rd_out[186]
    DIRECTION OUTPUT ;
    USE SIGNAL ;
    SHAPE ABUTMENT ;
    PORT
      LAYER M3 ;
      RECT 191.151 0.000 191.169 0.054 ;
    END
  END r0_rd_out[186]
  PIN r0_rd_out[187]
    DIRECTION OUTPUT ;
    USE SIGNAL ;
    SHAPE ABUTMENT ;
    PORT
      LAYER M3 ;
      RECT 191.583 0.000 191.601 0.054 ;
    END
  END r0_rd_out[187]
  PIN r0_rd_out[188]
    DIRECTION OUTPUT ;
    USE SIGNAL ;
    SHAPE ABUTMENT ;
    PORT
      LAYER M3 ;
      RECT 192.015 0.000 192.033 0.054 ;
    END
  END r0_rd_out[188]
  PIN r0_rd_out[189]
    DIRECTION OUTPUT ;
    USE SIGNAL ;
    SHAPE ABUTMENT ;
    PORT
      LAYER M3 ;
      RECT 192.447 0.000 192.465 0.054 ;
    END
  END r0_rd_out[189]
  PIN r0_rd_out[190]
    DIRECTION OUTPUT ;
    USE SIGNAL ;
    SHAPE ABUTMENT ;
    PORT
      LAYER M3 ;
      RECT 192.879 0.000 192.897 0.054 ;
    END
  END r0_rd_out[190]
  PIN r0_rd_out[191]
    DIRECTION OUTPUT ;
    USE SIGNAL ;
    SHAPE ABUTMENT ;
    PORT
      LAYER M3 ;
      RECT 193.311 0.000 193.329 0.054 ;
    END
  END r0_rd_out[191]
  PIN r0_rd_out[192]
    DIRECTION OUTPUT ;
    USE SIGNAL ;
    SHAPE ABUTMENT ;
    PORT
      LAYER M3 ;
      RECT 193.743 0.000 193.761 0.054 ;
    END
  END r0_rd_out[192]
  PIN r0_rd_out[193]
    DIRECTION OUTPUT ;
    USE SIGNAL ;
    SHAPE ABUTMENT ;
    PORT
      LAYER M3 ;
      RECT 194.175 0.000 194.193 0.054 ;
    END
  END r0_rd_out[193]
  PIN r0_rd_out[194]
    DIRECTION OUTPUT ;
    USE SIGNAL ;
    SHAPE ABUTMENT ;
    PORT
      LAYER M3 ;
      RECT 194.607 0.000 194.625 0.054 ;
    END
  END r0_rd_out[194]
  PIN r0_rd_out[195]
    DIRECTION OUTPUT ;
    USE SIGNAL ;
    SHAPE ABUTMENT ;
    PORT
      LAYER M3 ;
      RECT 195.039 0.000 195.057 0.054 ;
    END
  END r0_rd_out[195]
  PIN r0_rd_out[196]
    DIRECTION OUTPUT ;
    USE SIGNAL ;
    SHAPE ABUTMENT ;
    PORT
      LAYER M3 ;
      RECT 195.471 0.000 195.489 0.054 ;
    END
  END r0_rd_out[196]
  PIN r0_rd_out[197]
    DIRECTION OUTPUT ;
    USE SIGNAL ;
    SHAPE ABUTMENT ;
    PORT
      LAYER M3 ;
      RECT 195.903 0.000 195.921 0.054 ;
    END
  END r0_rd_out[197]
  PIN r0_rd_out[198]
    DIRECTION OUTPUT ;
    USE SIGNAL ;
    SHAPE ABUTMENT ;
    PORT
      LAYER M3 ;
      RECT 196.335 0.000 196.353 0.054 ;
    END
  END r0_rd_out[198]
  PIN r0_rd_out[199]
    DIRECTION OUTPUT ;
    USE SIGNAL ;
    SHAPE ABUTMENT ;
    PORT
      LAYER M3 ;
      RECT 196.767 0.000 196.785 0.054 ;
    END
  END r0_rd_out[199]
  PIN r0_rd_out[200]
    DIRECTION OUTPUT ;
    USE SIGNAL ;
    SHAPE ABUTMENT ;
    PORT
      LAYER M3 ;
      RECT 197.199 0.000 197.217 0.054 ;
    END
  END r0_rd_out[200]
  PIN r0_rd_out[201]
    DIRECTION OUTPUT ;
    USE SIGNAL ;
    SHAPE ABUTMENT ;
    PORT
      LAYER M3 ;
      RECT 197.631 0.000 197.649 0.054 ;
    END
  END r0_rd_out[201]
  PIN r0_rd_out[202]
    DIRECTION OUTPUT ;
    USE SIGNAL ;
    SHAPE ABUTMENT ;
    PORT
      LAYER M3 ;
      RECT 198.063 0.000 198.081 0.054 ;
    END
  END r0_rd_out[202]
  PIN r0_rd_out[203]
    DIRECTION OUTPUT ;
    USE SIGNAL ;
    SHAPE ABUTMENT ;
    PORT
      LAYER M3 ;
      RECT 198.495 0.000 198.513 0.054 ;
    END
  END r0_rd_out[203]
  PIN r0_rd_out[204]
    DIRECTION OUTPUT ;
    USE SIGNAL ;
    SHAPE ABUTMENT ;
    PORT
      LAYER M3 ;
      RECT 198.927 0.000 198.945 0.054 ;
    END
  END r0_rd_out[204]
  PIN r0_rd_out[205]
    DIRECTION OUTPUT ;
    USE SIGNAL ;
    SHAPE ABUTMENT ;
    PORT
      LAYER M3 ;
      RECT 199.359 0.000 199.377 0.054 ;
    END
  END r0_rd_out[205]
  PIN r0_rd_out[206]
    DIRECTION OUTPUT ;
    USE SIGNAL ;
    SHAPE ABUTMENT ;
    PORT
      LAYER M3 ;
      RECT 199.791 0.000 199.809 0.054 ;
    END
  END r0_rd_out[206]
  PIN r0_rd_out[207]
    DIRECTION OUTPUT ;
    USE SIGNAL ;
    SHAPE ABUTMENT ;
    PORT
      LAYER M3 ;
      RECT 200.223 0.000 200.241 0.054 ;
    END
  END r0_rd_out[207]
  PIN r0_rd_out[208]
    DIRECTION OUTPUT ;
    USE SIGNAL ;
    SHAPE ABUTMENT ;
    PORT
      LAYER M3 ;
      RECT 200.655 0.000 200.673 0.054 ;
    END
  END r0_rd_out[208]
  PIN r0_rd_out[209]
    DIRECTION OUTPUT ;
    USE SIGNAL ;
    SHAPE ABUTMENT ;
    PORT
      LAYER M3 ;
      RECT 201.087 0.000 201.105 0.054 ;
    END
  END r0_rd_out[209]
  PIN r0_rd_out[210]
    DIRECTION OUTPUT ;
    USE SIGNAL ;
    SHAPE ABUTMENT ;
    PORT
      LAYER M3 ;
      RECT 201.519 0.000 201.537 0.054 ;
    END
  END r0_rd_out[210]
  PIN r0_rd_out[211]
    DIRECTION OUTPUT ;
    USE SIGNAL ;
    SHAPE ABUTMENT ;
    PORT
      LAYER M3 ;
      RECT 201.951 0.000 201.969 0.054 ;
    END
  END r0_rd_out[211]
  PIN r0_rd_out[212]
    DIRECTION OUTPUT ;
    USE SIGNAL ;
    SHAPE ABUTMENT ;
    PORT
      LAYER M3 ;
      RECT 202.383 0.000 202.401 0.054 ;
    END
  END r0_rd_out[212]
  PIN r0_rd_out[213]
    DIRECTION OUTPUT ;
    USE SIGNAL ;
    SHAPE ABUTMENT ;
    PORT
      LAYER M3 ;
      RECT 202.815 0.000 202.833 0.054 ;
    END
  END r0_rd_out[213]
  PIN r0_rd_out[214]
    DIRECTION OUTPUT ;
    USE SIGNAL ;
    SHAPE ABUTMENT ;
    PORT
      LAYER M3 ;
      RECT 203.247 0.000 203.265 0.054 ;
    END
  END r0_rd_out[214]
  PIN r0_rd_out[215]
    DIRECTION OUTPUT ;
    USE SIGNAL ;
    SHAPE ABUTMENT ;
    PORT
      LAYER M3 ;
      RECT 203.679 0.000 203.697 0.054 ;
    END
  END r0_rd_out[215]
  PIN r0_rd_out[216]
    DIRECTION OUTPUT ;
    USE SIGNAL ;
    SHAPE ABUTMENT ;
    PORT
      LAYER M3 ;
      RECT 204.111 0.000 204.129 0.054 ;
    END
  END r0_rd_out[216]
  PIN r0_rd_out[217]
    DIRECTION OUTPUT ;
    USE SIGNAL ;
    SHAPE ABUTMENT ;
    PORT
      LAYER M3 ;
      RECT 204.543 0.000 204.561 0.054 ;
    END
  END r0_rd_out[217]
  PIN r0_rd_out[218]
    DIRECTION OUTPUT ;
    USE SIGNAL ;
    SHAPE ABUTMENT ;
    PORT
      LAYER M3 ;
      RECT 204.975 0.000 204.993 0.054 ;
    END
  END r0_rd_out[218]
  PIN r0_rd_out[219]
    DIRECTION OUTPUT ;
    USE SIGNAL ;
    SHAPE ABUTMENT ;
    PORT
      LAYER M3 ;
      RECT 205.407 0.000 205.425 0.054 ;
    END
  END r0_rd_out[219]
  PIN r0_rd_out[220]
    DIRECTION OUTPUT ;
    USE SIGNAL ;
    SHAPE ABUTMENT ;
    PORT
      LAYER M3 ;
      RECT 205.839 0.000 205.857 0.054 ;
    END
  END r0_rd_out[220]
  PIN r0_rd_out[221]
    DIRECTION OUTPUT ;
    USE SIGNAL ;
    SHAPE ABUTMENT ;
    PORT
      LAYER M3 ;
      RECT 206.271 0.000 206.289 0.054 ;
    END
  END r0_rd_out[221]
  PIN r0_rd_out[222]
    DIRECTION OUTPUT ;
    USE SIGNAL ;
    SHAPE ABUTMENT ;
    PORT
      LAYER M3 ;
      RECT 206.703 0.000 206.721 0.054 ;
    END
  END r0_rd_out[222]
  PIN r0_rd_out[223]
    DIRECTION OUTPUT ;
    USE SIGNAL ;
    SHAPE ABUTMENT ;
    PORT
      LAYER M3 ;
      RECT 207.135 0.000 207.153 0.054 ;
    END
  END r0_rd_out[223]
  PIN r0_rd_out[224]
    DIRECTION OUTPUT ;
    USE SIGNAL ;
    SHAPE ABUTMENT ;
    PORT
      LAYER M3 ;
      RECT 207.567 0.000 207.585 0.054 ;
    END
  END r0_rd_out[224]
  PIN r0_rd_out[225]
    DIRECTION OUTPUT ;
    USE SIGNAL ;
    SHAPE ABUTMENT ;
    PORT
      LAYER M3 ;
      RECT 207.999 0.000 208.017 0.054 ;
    END
  END r0_rd_out[225]
  PIN r0_rd_out[226]
    DIRECTION OUTPUT ;
    USE SIGNAL ;
    SHAPE ABUTMENT ;
    PORT
      LAYER M3 ;
      RECT 208.431 0.000 208.449 0.054 ;
    END
  END r0_rd_out[226]
  PIN r0_rd_out[227]
    DIRECTION OUTPUT ;
    USE SIGNAL ;
    SHAPE ABUTMENT ;
    PORT
      LAYER M3 ;
      RECT 208.863 0.000 208.881 0.054 ;
    END
  END r0_rd_out[227]
  PIN r0_rd_out[228]
    DIRECTION OUTPUT ;
    USE SIGNAL ;
    SHAPE ABUTMENT ;
    PORT
      LAYER M3 ;
      RECT 209.295 0.000 209.313 0.054 ;
    END
  END r0_rd_out[228]
  PIN r0_rd_out[229]
    DIRECTION OUTPUT ;
    USE SIGNAL ;
    SHAPE ABUTMENT ;
    PORT
      LAYER M3 ;
      RECT 209.727 0.000 209.745 0.054 ;
    END
  END r0_rd_out[229]
  PIN r0_rd_out[230]
    DIRECTION OUTPUT ;
    USE SIGNAL ;
    SHAPE ABUTMENT ;
    PORT
      LAYER M3 ;
      RECT 210.159 0.000 210.177 0.054 ;
    END
  END r0_rd_out[230]
  PIN r0_rd_out[231]
    DIRECTION OUTPUT ;
    USE SIGNAL ;
    SHAPE ABUTMENT ;
    PORT
      LAYER M3 ;
      RECT 210.591 0.000 210.609 0.054 ;
    END
  END r0_rd_out[231]
  PIN r0_rd_out[232]
    DIRECTION OUTPUT ;
    USE SIGNAL ;
    SHAPE ABUTMENT ;
    PORT
      LAYER M3 ;
      RECT 211.023 0.000 211.041 0.054 ;
    END
  END r0_rd_out[232]
  PIN r0_rd_out[233]
    DIRECTION OUTPUT ;
    USE SIGNAL ;
    SHAPE ABUTMENT ;
    PORT
      LAYER M3 ;
      RECT 211.455 0.000 211.473 0.054 ;
    END
  END r0_rd_out[233]
  PIN r0_rd_out[234]
    DIRECTION OUTPUT ;
    USE SIGNAL ;
    SHAPE ABUTMENT ;
    PORT
      LAYER M3 ;
      RECT 211.887 0.000 211.905 0.054 ;
    END
  END r0_rd_out[234]
  PIN r0_rd_out[235]
    DIRECTION OUTPUT ;
    USE SIGNAL ;
    SHAPE ABUTMENT ;
    PORT
      LAYER M3 ;
      RECT 212.319 0.000 212.337 0.054 ;
    END
  END r0_rd_out[235]
  PIN r0_rd_out[236]
    DIRECTION OUTPUT ;
    USE SIGNAL ;
    SHAPE ABUTMENT ;
    PORT
      LAYER M3 ;
      RECT 212.751 0.000 212.769 0.054 ;
    END
  END r0_rd_out[236]
  PIN r0_rd_out[237]
    DIRECTION OUTPUT ;
    USE SIGNAL ;
    SHAPE ABUTMENT ;
    PORT
      LAYER M3 ;
      RECT 213.183 0.000 213.201 0.054 ;
    END
  END r0_rd_out[237]
  PIN r0_rd_out[238]
    DIRECTION OUTPUT ;
    USE SIGNAL ;
    SHAPE ABUTMENT ;
    PORT
      LAYER M3 ;
      RECT 213.615 0.000 213.633 0.054 ;
    END
  END r0_rd_out[238]
  PIN r0_rd_out[239]
    DIRECTION OUTPUT ;
    USE SIGNAL ;
    SHAPE ABUTMENT ;
    PORT
      LAYER M3 ;
      RECT 214.047 0.000 214.065 0.054 ;
    END
  END r0_rd_out[239]
  PIN r0_rd_out[240]
    DIRECTION OUTPUT ;
    USE SIGNAL ;
    SHAPE ABUTMENT ;
    PORT
      LAYER M3 ;
      RECT 214.479 0.000 214.497 0.054 ;
    END
  END r0_rd_out[240]
  PIN r0_rd_out[241]
    DIRECTION OUTPUT ;
    USE SIGNAL ;
    SHAPE ABUTMENT ;
    PORT
      LAYER M3 ;
      RECT 214.911 0.000 214.929 0.054 ;
    END
  END r0_rd_out[241]
  PIN r0_rd_out[242]
    DIRECTION OUTPUT ;
    USE SIGNAL ;
    SHAPE ABUTMENT ;
    PORT
      LAYER M3 ;
      RECT 215.343 0.000 215.361 0.054 ;
    END
  END r0_rd_out[242]
  PIN r0_rd_out[243]
    DIRECTION OUTPUT ;
    USE SIGNAL ;
    SHAPE ABUTMENT ;
    PORT
      LAYER M3 ;
      RECT 215.775 0.000 215.793 0.054 ;
    END
  END r0_rd_out[243]
  PIN r0_rd_out[244]
    DIRECTION OUTPUT ;
    USE SIGNAL ;
    SHAPE ABUTMENT ;
    PORT
      LAYER M3 ;
      RECT 216.207 0.000 216.225 0.054 ;
    END
  END r0_rd_out[244]
  PIN r0_rd_out[245]
    DIRECTION OUTPUT ;
    USE SIGNAL ;
    SHAPE ABUTMENT ;
    PORT
      LAYER M3 ;
      RECT 216.639 0.000 216.657 0.054 ;
    END
  END r0_rd_out[245]
  PIN r0_rd_out[246]
    DIRECTION OUTPUT ;
    USE SIGNAL ;
    SHAPE ABUTMENT ;
    PORT
      LAYER M3 ;
      RECT 217.071 0.000 217.089 0.054 ;
    END
  END r0_rd_out[246]
  PIN r0_rd_out[247]
    DIRECTION OUTPUT ;
    USE SIGNAL ;
    SHAPE ABUTMENT ;
    PORT
      LAYER M3 ;
      RECT 217.503 0.000 217.521 0.054 ;
    END
  END r0_rd_out[247]
  PIN r0_rd_out[248]
    DIRECTION OUTPUT ;
    USE SIGNAL ;
    SHAPE ABUTMENT ;
    PORT
      LAYER M3 ;
      RECT 217.935 0.000 217.953 0.054 ;
    END
  END r0_rd_out[248]
  PIN r0_rd_out[249]
    DIRECTION OUTPUT ;
    USE SIGNAL ;
    SHAPE ABUTMENT ;
    PORT
      LAYER M3 ;
      RECT 218.367 0.000 218.385 0.054 ;
    END
  END r0_rd_out[249]
  PIN r0_rd_out[250]
    DIRECTION OUTPUT ;
    USE SIGNAL ;
    SHAPE ABUTMENT ;
    PORT
      LAYER M3 ;
      RECT 218.799 0.000 218.817 0.054 ;
    END
  END r0_rd_out[250]
  PIN r0_rd_out[251]
    DIRECTION OUTPUT ;
    USE SIGNAL ;
    SHAPE ABUTMENT ;
    PORT
      LAYER M3 ;
      RECT 219.231 0.000 219.249 0.054 ;
    END
  END r0_rd_out[251]
  PIN r0_rd_out[252]
    DIRECTION OUTPUT ;
    USE SIGNAL ;
    SHAPE ABUTMENT ;
    PORT
      LAYER M3 ;
      RECT 219.663 0.000 219.681 0.054 ;
    END
  END r0_rd_out[252]
  PIN r0_rd_out[253]
    DIRECTION OUTPUT ;
    USE SIGNAL ;
    SHAPE ABUTMENT ;
    PORT
      LAYER M3 ;
      RECT 220.095 0.000 220.113 0.054 ;
    END
  END r0_rd_out[253]
  PIN r0_rd_out[254]
    DIRECTION OUTPUT ;
    USE SIGNAL ;
    SHAPE ABUTMENT ;
    PORT
      LAYER M3 ;
      RECT 220.527 0.000 220.545 0.054 ;
    END
  END r0_rd_out[254]
  PIN r0_rd_out[255]
    DIRECTION OUTPUT ;
    USE SIGNAL ;
    SHAPE ABUTMENT ;
    PORT
      LAYER M3 ;
      RECT 220.959 0.000 220.977 0.054 ;
    END
  END r0_rd_out[255]
  PIN r0_rd_out[256]
    DIRECTION OUTPUT ;
    USE SIGNAL ;
    SHAPE ABUTMENT ;
    PORT
      LAYER M3 ;
      RECT 110.799 283.338 110.817 283.392 ;
    END
  END r0_rd_out[256]
  PIN r0_rd_out[257]
    DIRECTION OUTPUT ;
    USE SIGNAL ;
    SHAPE ABUTMENT ;
    PORT
      LAYER M3 ;
      RECT 111.231 283.338 111.249 283.392 ;
    END
  END r0_rd_out[257]
  PIN r0_rd_out[258]
    DIRECTION OUTPUT ;
    USE SIGNAL ;
    SHAPE ABUTMENT ;
    PORT
      LAYER M3 ;
      RECT 111.663 283.338 111.681 283.392 ;
    END
  END r0_rd_out[258]
  PIN r0_rd_out[259]
    DIRECTION OUTPUT ;
    USE SIGNAL ;
    SHAPE ABUTMENT ;
    PORT
      LAYER M3 ;
      RECT 112.095 283.338 112.113 283.392 ;
    END
  END r0_rd_out[259]
  PIN r0_rd_out[260]
    DIRECTION OUTPUT ;
    USE SIGNAL ;
    SHAPE ABUTMENT ;
    PORT
      LAYER M3 ;
      RECT 112.527 283.338 112.545 283.392 ;
    END
  END r0_rd_out[260]
  PIN r0_rd_out[261]
    DIRECTION OUTPUT ;
    USE SIGNAL ;
    SHAPE ABUTMENT ;
    PORT
      LAYER M3 ;
      RECT 112.959 283.338 112.977 283.392 ;
    END
  END r0_rd_out[261]
  PIN r0_rd_out[262]
    DIRECTION OUTPUT ;
    USE SIGNAL ;
    SHAPE ABUTMENT ;
    PORT
      LAYER M3 ;
      RECT 113.391 283.338 113.409 283.392 ;
    END
  END r0_rd_out[262]
  PIN r0_rd_out[263]
    DIRECTION OUTPUT ;
    USE SIGNAL ;
    SHAPE ABUTMENT ;
    PORT
      LAYER M3 ;
      RECT 113.823 283.338 113.841 283.392 ;
    END
  END r0_rd_out[263]
  PIN r0_rd_out[264]
    DIRECTION OUTPUT ;
    USE SIGNAL ;
    SHAPE ABUTMENT ;
    PORT
      LAYER M3 ;
      RECT 114.255 283.338 114.273 283.392 ;
    END
  END r0_rd_out[264]
  PIN r0_rd_out[265]
    DIRECTION OUTPUT ;
    USE SIGNAL ;
    SHAPE ABUTMENT ;
    PORT
      LAYER M3 ;
      RECT 114.687 283.338 114.705 283.392 ;
    END
  END r0_rd_out[265]
  PIN r0_rd_out[266]
    DIRECTION OUTPUT ;
    USE SIGNAL ;
    SHAPE ABUTMENT ;
    PORT
      LAYER M3 ;
      RECT 115.119 283.338 115.137 283.392 ;
    END
  END r0_rd_out[266]
  PIN r0_rd_out[267]
    DIRECTION OUTPUT ;
    USE SIGNAL ;
    SHAPE ABUTMENT ;
    PORT
      LAYER M3 ;
      RECT 115.551 283.338 115.569 283.392 ;
    END
  END r0_rd_out[267]
  PIN r0_rd_out[268]
    DIRECTION OUTPUT ;
    USE SIGNAL ;
    SHAPE ABUTMENT ;
    PORT
      LAYER M3 ;
      RECT 115.983 283.338 116.001 283.392 ;
    END
  END r0_rd_out[268]
  PIN r0_rd_out[269]
    DIRECTION OUTPUT ;
    USE SIGNAL ;
    SHAPE ABUTMENT ;
    PORT
      LAYER M3 ;
      RECT 116.415 283.338 116.433 283.392 ;
    END
  END r0_rd_out[269]
  PIN r0_rd_out[270]
    DIRECTION OUTPUT ;
    USE SIGNAL ;
    SHAPE ABUTMENT ;
    PORT
      LAYER M3 ;
      RECT 116.847 283.338 116.865 283.392 ;
    END
  END r0_rd_out[270]
  PIN r0_rd_out[271]
    DIRECTION OUTPUT ;
    USE SIGNAL ;
    SHAPE ABUTMENT ;
    PORT
      LAYER M3 ;
      RECT 117.279 283.338 117.297 283.392 ;
    END
  END r0_rd_out[271]
  PIN r0_rd_out[272]
    DIRECTION OUTPUT ;
    USE SIGNAL ;
    SHAPE ABUTMENT ;
    PORT
      LAYER M3 ;
      RECT 117.711 283.338 117.729 283.392 ;
    END
  END r0_rd_out[272]
  PIN r0_rd_out[273]
    DIRECTION OUTPUT ;
    USE SIGNAL ;
    SHAPE ABUTMENT ;
    PORT
      LAYER M3 ;
      RECT 118.143 283.338 118.161 283.392 ;
    END
  END r0_rd_out[273]
  PIN r0_rd_out[274]
    DIRECTION OUTPUT ;
    USE SIGNAL ;
    SHAPE ABUTMENT ;
    PORT
      LAYER M3 ;
      RECT 118.575 283.338 118.593 283.392 ;
    END
  END r0_rd_out[274]
  PIN r0_rd_out[275]
    DIRECTION OUTPUT ;
    USE SIGNAL ;
    SHAPE ABUTMENT ;
    PORT
      LAYER M3 ;
      RECT 119.007 283.338 119.025 283.392 ;
    END
  END r0_rd_out[275]
  PIN r0_rd_out[276]
    DIRECTION OUTPUT ;
    USE SIGNAL ;
    SHAPE ABUTMENT ;
    PORT
      LAYER M3 ;
      RECT 119.439 283.338 119.457 283.392 ;
    END
  END r0_rd_out[276]
  PIN r0_rd_out[277]
    DIRECTION OUTPUT ;
    USE SIGNAL ;
    SHAPE ABUTMENT ;
    PORT
      LAYER M3 ;
      RECT 119.871 283.338 119.889 283.392 ;
    END
  END r0_rd_out[277]
  PIN r0_rd_out[278]
    DIRECTION OUTPUT ;
    USE SIGNAL ;
    SHAPE ABUTMENT ;
    PORT
      LAYER M3 ;
      RECT 120.303 283.338 120.321 283.392 ;
    END
  END r0_rd_out[278]
  PIN r0_rd_out[279]
    DIRECTION OUTPUT ;
    USE SIGNAL ;
    SHAPE ABUTMENT ;
    PORT
      LAYER M3 ;
      RECT 120.735 283.338 120.753 283.392 ;
    END
  END r0_rd_out[279]
  PIN r0_rd_out[280]
    DIRECTION OUTPUT ;
    USE SIGNAL ;
    SHAPE ABUTMENT ;
    PORT
      LAYER M3 ;
      RECT 121.167 283.338 121.185 283.392 ;
    END
  END r0_rd_out[280]
  PIN r0_rd_out[281]
    DIRECTION OUTPUT ;
    USE SIGNAL ;
    SHAPE ABUTMENT ;
    PORT
      LAYER M3 ;
      RECT 121.599 283.338 121.617 283.392 ;
    END
  END r0_rd_out[281]
  PIN r0_rd_out[282]
    DIRECTION OUTPUT ;
    USE SIGNAL ;
    SHAPE ABUTMENT ;
    PORT
      LAYER M3 ;
      RECT 122.031 283.338 122.049 283.392 ;
    END
  END r0_rd_out[282]
  PIN r0_rd_out[283]
    DIRECTION OUTPUT ;
    USE SIGNAL ;
    SHAPE ABUTMENT ;
    PORT
      LAYER M3 ;
      RECT 122.463 283.338 122.481 283.392 ;
    END
  END r0_rd_out[283]
  PIN r0_rd_out[284]
    DIRECTION OUTPUT ;
    USE SIGNAL ;
    SHAPE ABUTMENT ;
    PORT
      LAYER M3 ;
      RECT 122.895 283.338 122.913 283.392 ;
    END
  END r0_rd_out[284]
  PIN r0_rd_out[285]
    DIRECTION OUTPUT ;
    USE SIGNAL ;
    SHAPE ABUTMENT ;
    PORT
      LAYER M3 ;
      RECT 123.327 283.338 123.345 283.392 ;
    END
  END r0_rd_out[285]
  PIN r0_rd_out[286]
    DIRECTION OUTPUT ;
    USE SIGNAL ;
    SHAPE ABUTMENT ;
    PORT
      LAYER M3 ;
      RECT 123.759 283.338 123.777 283.392 ;
    END
  END r0_rd_out[286]
  PIN r0_rd_out[287]
    DIRECTION OUTPUT ;
    USE SIGNAL ;
    SHAPE ABUTMENT ;
    PORT
      LAYER M3 ;
      RECT 124.191 283.338 124.209 283.392 ;
    END
  END r0_rd_out[287]
  PIN r0_rd_out[288]
    DIRECTION OUTPUT ;
    USE SIGNAL ;
    SHAPE ABUTMENT ;
    PORT
      LAYER M3 ;
      RECT 124.623 283.338 124.641 283.392 ;
    END
  END r0_rd_out[288]
  PIN r0_rd_out[289]
    DIRECTION OUTPUT ;
    USE SIGNAL ;
    SHAPE ABUTMENT ;
    PORT
      LAYER M3 ;
      RECT 125.055 283.338 125.073 283.392 ;
    END
  END r0_rd_out[289]
  PIN r0_rd_out[290]
    DIRECTION OUTPUT ;
    USE SIGNAL ;
    SHAPE ABUTMENT ;
    PORT
      LAYER M3 ;
      RECT 125.487 283.338 125.505 283.392 ;
    END
  END r0_rd_out[290]
  PIN r0_rd_out[291]
    DIRECTION OUTPUT ;
    USE SIGNAL ;
    SHAPE ABUTMENT ;
    PORT
      LAYER M3 ;
      RECT 125.919 283.338 125.937 283.392 ;
    END
  END r0_rd_out[291]
  PIN r0_rd_out[292]
    DIRECTION OUTPUT ;
    USE SIGNAL ;
    SHAPE ABUTMENT ;
    PORT
      LAYER M3 ;
      RECT 126.351 283.338 126.369 283.392 ;
    END
  END r0_rd_out[292]
  PIN r0_rd_out[293]
    DIRECTION OUTPUT ;
    USE SIGNAL ;
    SHAPE ABUTMENT ;
    PORT
      LAYER M3 ;
      RECT 126.783 283.338 126.801 283.392 ;
    END
  END r0_rd_out[293]
  PIN r0_rd_out[294]
    DIRECTION OUTPUT ;
    USE SIGNAL ;
    SHAPE ABUTMENT ;
    PORT
      LAYER M3 ;
      RECT 127.215 283.338 127.233 283.392 ;
    END
  END r0_rd_out[294]
  PIN r0_rd_out[295]
    DIRECTION OUTPUT ;
    USE SIGNAL ;
    SHAPE ABUTMENT ;
    PORT
      LAYER M3 ;
      RECT 127.647 283.338 127.665 283.392 ;
    END
  END r0_rd_out[295]
  PIN r0_rd_out[296]
    DIRECTION OUTPUT ;
    USE SIGNAL ;
    SHAPE ABUTMENT ;
    PORT
      LAYER M3 ;
      RECT 128.079 283.338 128.097 283.392 ;
    END
  END r0_rd_out[296]
  PIN r0_rd_out[297]
    DIRECTION OUTPUT ;
    USE SIGNAL ;
    SHAPE ABUTMENT ;
    PORT
      LAYER M3 ;
      RECT 128.511 283.338 128.529 283.392 ;
    END
  END r0_rd_out[297]
  PIN r0_rd_out[298]
    DIRECTION OUTPUT ;
    USE SIGNAL ;
    SHAPE ABUTMENT ;
    PORT
      LAYER M3 ;
      RECT 128.943 283.338 128.961 283.392 ;
    END
  END r0_rd_out[298]
  PIN r0_rd_out[299]
    DIRECTION OUTPUT ;
    USE SIGNAL ;
    SHAPE ABUTMENT ;
    PORT
      LAYER M3 ;
      RECT 129.375 283.338 129.393 283.392 ;
    END
  END r0_rd_out[299]
  PIN r0_rd_out[300]
    DIRECTION OUTPUT ;
    USE SIGNAL ;
    SHAPE ABUTMENT ;
    PORT
      LAYER M3 ;
      RECT 129.807 283.338 129.825 283.392 ;
    END
  END r0_rd_out[300]
  PIN r0_rd_out[301]
    DIRECTION OUTPUT ;
    USE SIGNAL ;
    SHAPE ABUTMENT ;
    PORT
      LAYER M3 ;
      RECT 130.239 283.338 130.257 283.392 ;
    END
  END r0_rd_out[301]
  PIN r0_rd_out[302]
    DIRECTION OUTPUT ;
    USE SIGNAL ;
    SHAPE ABUTMENT ;
    PORT
      LAYER M3 ;
      RECT 130.671 283.338 130.689 283.392 ;
    END
  END r0_rd_out[302]
  PIN r0_rd_out[303]
    DIRECTION OUTPUT ;
    USE SIGNAL ;
    SHAPE ABUTMENT ;
    PORT
      LAYER M3 ;
      RECT 131.103 283.338 131.121 283.392 ;
    END
  END r0_rd_out[303]
  PIN r0_rd_out[304]
    DIRECTION OUTPUT ;
    USE SIGNAL ;
    SHAPE ABUTMENT ;
    PORT
      LAYER M3 ;
      RECT 131.535 283.338 131.553 283.392 ;
    END
  END r0_rd_out[304]
  PIN r0_rd_out[305]
    DIRECTION OUTPUT ;
    USE SIGNAL ;
    SHAPE ABUTMENT ;
    PORT
      LAYER M3 ;
      RECT 131.967 283.338 131.985 283.392 ;
    END
  END r0_rd_out[305]
  PIN r0_rd_out[306]
    DIRECTION OUTPUT ;
    USE SIGNAL ;
    SHAPE ABUTMENT ;
    PORT
      LAYER M3 ;
      RECT 132.399 283.338 132.417 283.392 ;
    END
  END r0_rd_out[306]
  PIN r0_rd_out[307]
    DIRECTION OUTPUT ;
    USE SIGNAL ;
    SHAPE ABUTMENT ;
    PORT
      LAYER M3 ;
      RECT 132.831 283.338 132.849 283.392 ;
    END
  END r0_rd_out[307]
  PIN r0_rd_out[308]
    DIRECTION OUTPUT ;
    USE SIGNAL ;
    SHAPE ABUTMENT ;
    PORT
      LAYER M3 ;
      RECT 133.263 283.338 133.281 283.392 ;
    END
  END r0_rd_out[308]
  PIN r0_rd_out[309]
    DIRECTION OUTPUT ;
    USE SIGNAL ;
    SHAPE ABUTMENT ;
    PORT
      LAYER M3 ;
      RECT 133.695 283.338 133.713 283.392 ;
    END
  END r0_rd_out[309]
  PIN r0_rd_out[310]
    DIRECTION OUTPUT ;
    USE SIGNAL ;
    SHAPE ABUTMENT ;
    PORT
      LAYER M3 ;
      RECT 134.127 283.338 134.145 283.392 ;
    END
  END r0_rd_out[310]
  PIN r0_rd_out[311]
    DIRECTION OUTPUT ;
    USE SIGNAL ;
    SHAPE ABUTMENT ;
    PORT
      LAYER M3 ;
      RECT 134.559 283.338 134.577 283.392 ;
    END
  END r0_rd_out[311]
  PIN r0_rd_out[312]
    DIRECTION OUTPUT ;
    USE SIGNAL ;
    SHAPE ABUTMENT ;
    PORT
      LAYER M3 ;
      RECT 134.991 283.338 135.009 283.392 ;
    END
  END r0_rd_out[312]
  PIN r0_rd_out[313]
    DIRECTION OUTPUT ;
    USE SIGNAL ;
    SHAPE ABUTMENT ;
    PORT
      LAYER M3 ;
      RECT 135.423 283.338 135.441 283.392 ;
    END
  END r0_rd_out[313]
  PIN r0_rd_out[314]
    DIRECTION OUTPUT ;
    USE SIGNAL ;
    SHAPE ABUTMENT ;
    PORT
      LAYER M3 ;
      RECT 135.855 283.338 135.873 283.392 ;
    END
  END r0_rd_out[314]
  PIN r0_rd_out[315]
    DIRECTION OUTPUT ;
    USE SIGNAL ;
    SHAPE ABUTMENT ;
    PORT
      LAYER M3 ;
      RECT 136.287 283.338 136.305 283.392 ;
    END
  END r0_rd_out[315]
  PIN r0_rd_out[316]
    DIRECTION OUTPUT ;
    USE SIGNAL ;
    SHAPE ABUTMENT ;
    PORT
      LAYER M3 ;
      RECT 136.719 283.338 136.737 283.392 ;
    END
  END r0_rd_out[316]
  PIN r0_rd_out[317]
    DIRECTION OUTPUT ;
    USE SIGNAL ;
    SHAPE ABUTMENT ;
    PORT
      LAYER M3 ;
      RECT 137.151 283.338 137.169 283.392 ;
    END
  END r0_rd_out[317]
  PIN r0_rd_out[318]
    DIRECTION OUTPUT ;
    USE SIGNAL ;
    SHAPE ABUTMENT ;
    PORT
      LAYER M3 ;
      RECT 137.583 283.338 137.601 283.392 ;
    END
  END r0_rd_out[318]
  PIN r0_rd_out[319]
    DIRECTION OUTPUT ;
    USE SIGNAL ;
    SHAPE ABUTMENT ;
    PORT
      LAYER M3 ;
      RECT 138.015 283.338 138.033 283.392 ;
    END
  END r0_rd_out[319]
  PIN r0_rd_out[320]
    DIRECTION OUTPUT ;
    USE SIGNAL ;
    SHAPE ABUTMENT ;
    PORT
      LAYER M3 ;
      RECT 138.447 283.338 138.465 283.392 ;
    END
  END r0_rd_out[320]
  PIN r0_rd_out[321]
    DIRECTION OUTPUT ;
    USE SIGNAL ;
    SHAPE ABUTMENT ;
    PORT
      LAYER M3 ;
      RECT 138.879 283.338 138.897 283.392 ;
    END
  END r0_rd_out[321]
  PIN r0_rd_out[322]
    DIRECTION OUTPUT ;
    USE SIGNAL ;
    SHAPE ABUTMENT ;
    PORT
      LAYER M3 ;
      RECT 139.311 283.338 139.329 283.392 ;
    END
  END r0_rd_out[322]
  PIN r0_rd_out[323]
    DIRECTION OUTPUT ;
    USE SIGNAL ;
    SHAPE ABUTMENT ;
    PORT
      LAYER M3 ;
      RECT 139.743 283.338 139.761 283.392 ;
    END
  END r0_rd_out[323]
  PIN r0_rd_out[324]
    DIRECTION OUTPUT ;
    USE SIGNAL ;
    SHAPE ABUTMENT ;
    PORT
      LAYER M3 ;
      RECT 140.175 283.338 140.193 283.392 ;
    END
  END r0_rd_out[324]
  PIN r0_rd_out[325]
    DIRECTION OUTPUT ;
    USE SIGNAL ;
    SHAPE ABUTMENT ;
    PORT
      LAYER M3 ;
      RECT 140.607 283.338 140.625 283.392 ;
    END
  END r0_rd_out[325]
  PIN r0_rd_out[326]
    DIRECTION OUTPUT ;
    USE SIGNAL ;
    SHAPE ABUTMENT ;
    PORT
      LAYER M3 ;
      RECT 141.039 283.338 141.057 283.392 ;
    END
  END r0_rd_out[326]
  PIN r0_rd_out[327]
    DIRECTION OUTPUT ;
    USE SIGNAL ;
    SHAPE ABUTMENT ;
    PORT
      LAYER M3 ;
      RECT 141.471 283.338 141.489 283.392 ;
    END
  END r0_rd_out[327]
  PIN r0_rd_out[328]
    DIRECTION OUTPUT ;
    USE SIGNAL ;
    SHAPE ABUTMENT ;
    PORT
      LAYER M3 ;
      RECT 141.903 283.338 141.921 283.392 ;
    END
  END r0_rd_out[328]
  PIN r0_rd_out[329]
    DIRECTION OUTPUT ;
    USE SIGNAL ;
    SHAPE ABUTMENT ;
    PORT
      LAYER M3 ;
      RECT 142.335 283.338 142.353 283.392 ;
    END
  END r0_rd_out[329]
  PIN r0_rd_out[330]
    DIRECTION OUTPUT ;
    USE SIGNAL ;
    SHAPE ABUTMENT ;
    PORT
      LAYER M3 ;
      RECT 142.767 283.338 142.785 283.392 ;
    END
  END r0_rd_out[330]
  PIN r0_rd_out[331]
    DIRECTION OUTPUT ;
    USE SIGNAL ;
    SHAPE ABUTMENT ;
    PORT
      LAYER M3 ;
      RECT 143.199 283.338 143.217 283.392 ;
    END
  END r0_rd_out[331]
  PIN r0_rd_out[332]
    DIRECTION OUTPUT ;
    USE SIGNAL ;
    SHAPE ABUTMENT ;
    PORT
      LAYER M3 ;
      RECT 143.631 283.338 143.649 283.392 ;
    END
  END r0_rd_out[332]
  PIN r0_rd_out[333]
    DIRECTION OUTPUT ;
    USE SIGNAL ;
    SHAPE ABUTMENT ;
    PORT
      LAYER M3 ;
      RECT 144.063 283.338 144.081 283.392 ;
    END
  END r0_rd_out[333]
  PIN r0_rd_out[334]
    DIRECTION OUTPUT ;
    USE SIGNAL ;
    SHAPE ABUTMENT ;
    PORT
      LAYER M3 ;
      RECT 144.495 283.338 144.513 283.392 ;
    END
  END r0_rd_out[334]
  PIN r0_rd_out[335]
    DIRECTION OUTPUT ;
    USE SIGNAL ;
    SHAPE ABUTMENT ;
    PORT
      LAYER M3 ;
      RECT 144.927 283.338 144.945 283.392 ;
    END
  END r0_rd_out[335]
  PIN r0_rd_out[336]
    DIRECTION OUTPUT ;
    USE SIGNAL ;
    SHAPE ABUTMENT ;
    PORT
      LAYER M3 ;
      RECT 145.359 283.338 145.377 283.392 ;
    END
  END r0_rd_out[336]
  PIN r0_rd_out[337]
    DIRECTION OUTPUT ;
    USE SIGNAL ;
    SHAPE ABUTMENT ;
    PORT
      LAYER M3 ;
      RECT 145.791 283.338 145.809 283.392 ;
    END
  END r0_rd_out[337]
  PIN r0_rd_out[338]
    DIRECTION OUTPUT ;
    USE SIGNAL ;
    SHAPE ABUTMENT ;
    PORT
      LAYER M3 ;
      RECT 146.223 283.338 146.241 283.392 ;
    END
  END r0_rd_out[338]
  PIN r0_rd_out[339]
    DIRECTION OUTPUT ;
    USE SIGNAL ;
    SHAPE ABUTMENT ;
    PORT
      LAYER M3 ;
      RECT 146.655 283.338 146.673 283.392 ;
    END
  END r0_rd_out[339]
  PIN r0_rd_out[340]
    DIRECTION OUTPUT ;
    USE SIGNAL ;
    SHAPE ABUTMENT ;
    PORT
      LAYER M3 ;
      RECT 147.087 283.338 147.105 283.392 ;
    END
  END r0_rd_out[340]
  PIN r0_rd_out[341]
    DIRECTION OUTPUT ;
    USE SIGNAL ;
    SHAPE ABUTMENT ;
    PORT
      LAYER M3 ;
      RECT 147.519 283.338 147.537 283.392 ;
    END
  END r0_rd_out[341]
  PIN r0_rd_out[342]
    DIRECTION OUTPUT ;
    USE SIGNAL ;
    SHAPE ABUTMENT ;
    PORT
      LAYER M3 ;
      RECT 147.951 283.338 147.969 283.392 ;
    END
  END r0_rd_out[342]
  PIN r0_rd_out[343]
    DIRECTION OUTPUT ;
    USE SIGNAL ;
    SHAPE ABUTMENT ;
    PORT
      LAYER M3 ;
      RECT 148.383 283.338 148.401 283.392 ;
    END
  END r0_rd_out[343]
  PIN r0_rd_out[344]
    DIRECTION OUTPUT ;
    USE SIGNAL ;
    SHAPE ABUTMENT ;
    PORT
      LAYER M3 ;
      RECT 148.815 283.338 148.833 283.392 ;
    END
  END r0_rd_out[344]
  PIN r0_rd_out[345]
    DIRECTION OUTPUT ;
    USE SIGNAL ;
    SHAPE ABUTMENT ;
    PORT
      LAYER M3 ;
      RECT 149.247 283.338 149.265 283.392 ;
    END
  END r0_rd_out[345]
  PIN r0_rd_out[346]
    DIRECTION OUTPUT ;
    USE SIGNAL ;
    SHAPE ABUTMENT ;
    PORT
      LAYER M3 ;
      RECT 149.679 283.338 149.697 283.392 ;
    END
  END r0_rd_out[346]
  PIN r0_rd_out[347]
    DIRECTION OUTPUT ;
    USE SIGNAL ;
    SHAPE ABUTMENT ;
    PORT
      LAYER M3 ;
      RECT 150.111 283.338 150.129 283.392 ;
    END
  END r0_rd_out[347]
  PIN r0_rd_out[348]
    DIRECTION OUTPUT ;
    USE SIGNAL ;
    SHAPE ABUTMENT ;
    PORT
      LAYER M3 ;
      RECT 150.543 283.338 150.561 283.392 ;
    END
  END r0_rd_out[348]
  PIN r0_rd_out[349]
    DIRECTION OUTPUT ;
    USE SIGNAL ;
    SHAPE ABUTMENT ;
    PORT
      LAYER M3 ;
      RECT 150.975 283.338 150.993 283.392 ;
    END
  END r0_rd_out[349]
  PIN r0_rd_out[350]
    DIRECTION OUTPUT ;
    USE SIGNAL ;
    SHAPE ABUTMENT ;
    PORT
      LAYER M3 ;
      RECT 151.407 283.338 151.425 283.392 ;
    END
  END r0_rd_out[350]
  PIN r0_rd_out[351]
    DIRECTION OUTPUT ;
    USE SIGNAL ;
    SHAPE ABUTMENT ;
    PORT
      LAYER M3 ;
      RECT 151.839 283.338 151.857 283.392 ;
    END
  END r0_rd_out[351]
  PIN r0_rd_out[352]
    DIRECTION OUTPUT ;
    USE SIGNAL ;
    SHAPE ABUTMENT ;
    PORT
      LAYER M3 ;
      RECT 152.271 283.338 152.289 283.392 ;
    END
  END r0_rd_out[352]
  PIN r0_rd_out[353]
    DIRECTION OUTPUT ;
    USE SIGNAL ;
    SHAPE ABUTMENT ;
    PORT
      LAYER M3 ;
      RECT 152.703 283.338 152.721 283.392 ;
    END
  END r0_rd_out[353]
  PIN r0_rd_out[354]
    DIRECTION OUTPUT ;
    USE SIGNAL ;
    SHAPE ABUTMENT ;
    PORT
      LAYER M3 ;
      RECT 153.135 283.338 153.153 283.392 ;
    END
  END r0_rd_out[354]
  PIN r0_rd_out[355]
    DIRECTION OUTPUT ;
    USE SIGNAL ;
    SHAPE ABUTMENT ;
    PORT
      LAYER M3 ;
      RECT 153.567 283.338 153.585 283.392 ;
    END
  END r0_rd_out[355]
  PIN r0_rd_out[356]
    DIRECTION OUTPUT ;
    USE SIGNAL ;
    SHAPE ABUTMENT ;
    PORT
      LAYER M3 ;
      RECT 153.999 283.338 154.017 283.392 ;
    END
  END r0_rd_out[356]
  PIN r0_rd_out[357]
    DIRECTION OUTPUT ;
    USE SIGNAL ;
    SHAPE ABUTMENT ;
    PORT
      LAYER M3 ;
      RECT 154.431 283.338 154.449 283.392 ;
    END
  END r0_rd_out[357]
  PIN r0_rd_out[358]
    DIRECTION OUTPUT ;
    USE SIGNAL ;
    SHAPE ABUTMENT ;
    PORT
      LAYER M3 ;
      RECT 154.863 283.338 154.881 283.392 ;
    END
  END r0_rd_out[358]
  PIN r0_rd_out[359]
    DIRECTION OUTPUT ;
    USE SIGNAL ;
    SHAPE ABUTMENT ;
    PORT
      LAYER M3 ;
      RECT 155.295 283.338 155.313 283.392 ;
    END
  END r0_rd_out[359]
  PIN r0_rd_out[360]
    DIRECTION OUTPUT ;
    USE SIGNAL ;
    SHAPE ABUTMENT ;
    PORT
      LAYER M3 ;
      RECT 155.727 283.338 155.745 283.392 ;
    END
  END r0_rd_out[360]
  PIN r0_rd_out[361]
    DIRECTION OUTPUT ;
    USE SIGNAL ;
    SHAPE ABUTMENT ;
    PORT
      LAYER M3 ;
      RECT 156.159 283.338 156.177 283.392 ;
    END
  END r0_rd_out[361]
  PIN r0_rd_out[362]
    DIRECTION OUTPUT ;
    USE SIGNAL ;
    SHAPE ABUTMENT ;
    PORT
      LAYER M3 ;
      RECT 156.591 283.338 156.609 283.392 ;
    END
  END r0_rd_out[362]
  PIN r0_rd_out[363]
    DIRECTION OUTPUT ;
    USE SIGNAL ;
    SHAPE ABUTMENT ;
    PORT
      LAYER M3 ;
      RECT 157.023 283.338 157.041 283.392 ;
    END
  END r0_rd_out[363]
  PIN r0_rd_out[364]
    DIRECTION OUTPUT ;
    USE SIGNAL ;
    SHAPE ABUTMENT ;
    PORT
      LAYER M3 ;
      RECT 157.455 283.338 157.473 283.392 ;
    END
  END r0_rd_out[364]
  PIN r0_rd_out[365]
    DIRECTION OUTPUT ;
    USE SIGNAL ;
    SHAPE ABUTMENT ;
    PORT
      LAYER M3 ;
      RECT 157.887 283.338 157.905 283.392 ;
    END
  END r0_rd_out[365]
  PIN r0_rd_out[366]
    DIRECTION OUTPUT ;
    USE SIGNAL ;
    SHAPE ABUTMENT ;
    PORT
      LAYER M3 ;
      RECT 158.319 283.338 158.337 283.392 ;
    END
  END r0_rd_out[366]
  PIN r0_rd_out[367]
    DIRECTION OUTPUT ;
    USE SIGNAL ;
    SHAPE ABUTMENT ;
    PORT
      LAYER M3 ;
      RECT 158.751 283.338 158.769 283.392 ;
    END
  END r0_rd_out[367]
  PIN r0_rd_out[368]
    DIRECTION OUTPUT ;
    USE SIGNAL ;
    SHAPE ABUTMENT ;
    PORT
      LAYER M3 ;
      RECT 159.183 283.338 159.201 283.392 ;
    END
  END r0_rd_out[368]
  PIN r0_rd_out[369]
    DIRECTION OUTPUT ;
    USE SIGNAL ;
    SHAPE ABUTMENT ;
    PORT
      LAYER M3 ;
      RECT 159.615 283.338 159.633 283.392 ;
    END
  END r0_rd_out[369]
  PIN r0_rd_out[370]
    DIRECTION OUTPUT ;
    USE SIGNAL ;
    SHAPE ABUTMENT ;
    PORT
      LAYER M3 ;
      RECT 160.047 283.338 160.065 283.392 ;
    END
  END r0_rd_out[370]
  PIN r0_rd_out[371]
    DIRECTION OUTPUT ;
    USE SIGNAL ;
    SHAPE ABUTMENT ;
    PORT
      LAYER M3 ;
      RECT 160.479 283.338 160.497 283.392 ;
    END
  END r0_rd_out[371]
  PIN r0_rd_out[372]
    DIRECTION OUTPUT ;
    USE SIGNAL ;
    SHAPE ABUTMENT ;
    PORT
      LAYER M3 ;
      RECT 160.911 283.338 160.929 283.392 ;
    END
  END r0_rd_out[372]
  PIN r0_rd_out[373]
    DIRECTION OUTPUT ;
    USE SIGNAL ;
    SHAPE ABUTMENT ;
    PORT
      LAYER M3 ;
      RECT 161.343 283.338 161.361 283.392 ;
    END
  END r0_rd_out[373]
  PIN r0_rd_out[374]
    DIRECTION OUTPUT ;
    USE SIGNAL ;
    SHAPE ABUTMENT ;
    PORT
      LAYER M3 ;
      RECT 161.775 283.338 161.793 283.392 ;
    END
  END r0_rd_out[374]
  PIN r0_rd_out[375]
    DIRECTION OUTPUT ;
    USE SIGNAL ;
    SHAPE ABUTMENT ;
    PORT
      LAYER M3 ;
      RECT 162.207 283.338 162.225 283.392 ;
    END
  END r0_rd_out[375]
  PIN r0_rd_out[376]
    DIRECTION OUTPUT ;
    USE SIGNAL ;
    SHAPE ABUTMENT ;
    PORT
      LAYER M3 ;
      RECT 162.639 283.338 162.657 283.392 ;
    END
  END r0_rd_out[376]
  PIN r0_rd_out[377]
    DIRECTION OUTPUT ;
    USE SIGNAL ;
    SHAPE ABUTMENT ;
    PORT
      LAYER M3 ;
      RECT 163.071 283.338 163.089 283.392 ;
    END
  END r0_rd_out[377]
  PIN r0_rd_out[378]
    DIRECTION OUTPUT ;
    USE SIGNAL ;
    SHAPE ABUTMENT ;
    PORT
      LAYER M3 ;
      RECT 163.503 283.338 163.521 283.392 ;
    END
  END r0_rd_out[378]
  PIN r0_rd_out[379]
    DIRECTION OUTPUT ;
    USE SIGNAL ;
    SHAPE ABUTMENT ;
    PORT
      LAYER M3 ;
      RECT 163.935 283.338 163.953 283.392 ;
    END
  END r0_rd_out[379]
  PIN r0_rd_out[380]
    DIRECTION OUTPUT ;
    USE SIGNAL ;
    SHAPE ABUTMENT ;
    PORT
      LAYER M3 ;
      RECT 164.367 283.338 164.385 283.392 ;
    END
  END r0_rd_out[380]
  PIN r0_rd_out[381]
    DIRECTION OUTPUT ;
    USE SIGNAL ;
    SHAPE ABUTMENT ;
    PORT
      LAYER M3 ;
      RECT 164.799 283.338 164.817 283.392 ;
    END
  END r0_rd_out[381]
  PIN r0_rd_out[382]
    DIRECTION OUTPUT ;
    USE SIGNAL ;
    SHAPE ABUTMENT ;
    PORT
      LAYER M3 ;
      RECT 165.231 283.338 165.249 283.392 ;
    END
  END r0_rd_out[382]
  PIN r0_rd_out[383]
    DIRECTION OUTPUT ;
    USE SIGNAL ;
    SHAPE ABUTMENT ;
    PORT
      LAYER M3 ;
      RECT 165.663 283.338 165.681 283.392 ;
    END
  END r0_rd_out[383]
  PIN r0_rd_out[384]
    DIRECTION OUTPUT ;
    USE SIGNAL ;
    SHAPE ABUTMENT ;
    PORT
      LAYER M3 ;
      RECT 166.095 283.338 166.113 283.392 ;
    END
  END r0_rd_out[384]
  PIN r0_rd_out[385]
    DIRECTION OUTPUT ;
    USE SIGNAL ;
    SHAPE ABUTMENT ;
    PORT
      LAYER M3 ;
      RECT 166.527 283.338 166.545 283.392 ;
    END
  END r0_rd_out[385]
  PIN r0_rd_out[386]
    DIRECTION OUTPUT ;
    USE SIGNAL ;
    SHAPE ABUTMENT ;
    PORT
      LAYER M3 ;
      RECT 166.959 283.338 166.977 283.392 ;
    END
  END r0_rd_out[386]
  PIN r0_rd_out[387]
    DIRECTION OUTPUT ;
    USE SIGNAL ;
    SHAPE ABUTMENT ;
    PORT
      LAYER M3 ;
      RECT 167.391 283.338 167.409 283.392 ;
    END
  END r0_rd_out[387]
  PIN r0_rd_out[388]
    DIRECTION OUTPUT ;
    USE SIGNAL ;
    SHAPE ABUTMENT ;
    PORT
      LAYER M3 ;
      RECT 167.823 283.338 167.841 283.392 ;
    END
  END r0_rd_out[388]
  PIN r0_rd_out[389]
    DIRECTION OUTPUT ;
    USE SIGNAL ;
    SHAPE ABUTMENT ;
    PORT
      LAYER M3 ;
      RECT 168.255 283.338 168.273 283.392 ;
    END
  END r0_rd_out[389]
  PIN r0_rd_out[390]
    DIRECTION OUTPUT ;
    USE SIGNAL ;
    SHAPE ABUTMENT ;
    PORT
      LAYER M3 ;
      RECT 168.687 283.338 168.705 283.392 ;
    END
  END r0_rd_out[390]
  PIN r0_rd_out[391]
    DIRECTION OUTPUT ;
    USE SIGNAL ;
    SHAPE ABUTMENT ;
    PORT
      LAYER M3 ;
      RECT 169.119 283.338 169.137 283.392 ;
    END
  END r0_rd_out[391]
  PIN r0_rd_out[392]
    DIRECTION OUTPUT ;
    USE SIGNAL ;
    SHAPE ABUTMENT ;
    PORT
      LAYER M3 ;
      RECT 169.551 283.338 169.569 283.392 ;
    END
  END r0_rd_out[392]
  PIN r0_rd_out[393]
    DIRECTION OUTPUT ;
    USE SIGNAL ;
    SHAPE ABUTMENT ;
    PORT
      LAYER M3 ;
      RECT 169.983 283.338 170.001 283.392 ;
    END
  END r0_rd_out[393]
  PIN r0_rd_out[394]
    DIRECTION OUTPUT ;
    USE SIGNAL ;
    SHAPE ABUTMENT ;
    PORT
      LAYER M3 ;
      RECT 170.415 283.338 170.433 283.392 ;
    END
  END r0_rd_out[394]
  PIN r0_rd_out[395]
    DIRECTION OUTPUT ;
    USE SIGNAL ;
    SHAPE ABUTMENT ;
    PORT
      LAYER M3 ;
      RECT 170.847 283.338 170.865 283.392 ;
    END
  END r0_rd_out[395]
  PIN r0_rd_out[396]
    DIRECTION OUTPUT ;
    USE SIGNAL ;
    SHAPE ABUTMENT ;
    PORT
      LAYER M3 ;
      RECT 171.279 283.338 171.297 283.392 ;
    END
  END r0_rd_out[396]
  PIN r0_rd_out[397]
    DIRECTION OUTPUT ;
    USE SIGNAL ;
    SHAPE ABUTMENT ;
    PORT
      LAYER M3 ;
      RECT 171.711 283.338 171.729 283.392 ;
    END
  END r0_rd_out[397]
  PIN r0_rd_out[398]
    DIRECTION OUTPUT ;
    USE SIGNAL ;
    SHAPE ABUTMENT ;
    PORT
      LAYER M3 ;
      RECT 172.143 283.338 172.161 283.392 ;
    END
  END r0_rd_out[398]
  PIN r0_rd_out[399]
    DIRECTION OUTPUT ;
    USE SIGNAL ;
    SHAPE ABUTMENT ;
    PORT
      LAYER M3 ;
      RECT 172.575 283.338 172.593 283.392 ;
    END
  END r0_rd_out[399]
  PIN r0_rd_out[400]
    DIRECTION OUTPUT ;
    USE SIGNAL ;
    SHAPE ABUTMENT ;
    PORT
      LAYER M3 ;
      RECT 173.007 283.338 173.025 283.392 ;
    END
  END r0_rd_out[400]
  PIN r0_rd_out[401]
    DIRECTION OUTPUT ;
    USE SIGNAL ;
    SHAPE ABUTMENT ;
    PORT
      LAYER M3 ;
      RECT 173.439 283.338 173.457 283.392 ;
    END
  END r0_rd_out[401]
  PIN r0_rd_out[402]
    DIRECTION OUTPUT ;
    USE SIGNAL ;
    SHAPE ABUTMENT ;
    PORT
      LAYER M3 ;
      RECT 173.871 283.338 173.889 283.392 ;
    END
  END r0_rd_out[402]
  PIN r0_rd_out[403]
    DIRECTION OUTPUT ;
    USE SIGNAL ;
    SHAPE ABUTMENT ;
    PORT
      LAYER M3 ;
      RECT 174.303 283.338 174.321 283.392 ;
    END
  END r0_rd_out[403]
  PIN r0_rd_out[404]
    DIRECTION OUTPUT ;
    USE SIGNAL ;
    SHAPE ABUTMENT ;
    PORT
      LAYER M3 ;
      RECT 174.735 283.338 174.753 283.392 ;
    END
  END r0_rd_out[404]
  PIN r0_rd_out[405]
    DIRECTION OUTPUT ;
    USE SIGNAL ;
    SHAPE ABUTMENT ;
    PORT
      LAYER M3 ;
      RECT 175.167 283.338 175.185 283.392 ;
    END
  END r0_rd_out[405]
  PIN r0_rd_out[406]
    DIRECTION OUTPUT ;
    USE SIGNAL ;
    SHAPE ABUTMENT ;
    PORT
      LAYER M3 ;
      RECT 175.599 283.338 175.617 283.392 ;
    END
  END r0_rd_out[406]
  PIN r0_rd_out[407]
    DIRECTION OUTPUT ;
    USE SIGNAL ;
    SHAPE ABUTMENT ;
    PORT
      LAYER M3 ;
      RECT 176.031 283.338 176.049 283.392 ;
    END
  END r0_rd_out[407]
  PIN r0_rd_out[408]
    DIRECTION OUTPUT ;
    USE SIGNAL ;
    SHAPE ABUTMENT ;
    PORT
      LAYER M3 ;
      RECT 176.463 283.338 176.481 283.392 ;
    END
  END r0_rd_out[408]
  PIN r0_rd_out[409]
    DIRECTION OUTPUT ;
    USE SIGNAL ;
    SHAPE ABUTMENT ;
    PORT
      LAYER M3 ;
      RECT 176.895 283.338 176.913 283.392 ;
    END
  END r0_rd_out[409]
  PIN r0_rd_out[410]
    DIRECTION OUTPUT ;
    USE SIGNAL ;
    SHAPE ABUTMENT ;
    PORT
      LAYER M3 ;
      RECT 177.327 283.338 177.345 283.392 ;
    END
  END r0_rd_out[410]
  PIN r0_rd_out[411]
    DIRECTION OUTPUT ;
    USE SIGNAL ;
    SHAPE ABUTMENT ;
    PORT
      LAYER M3 ;
      RECT 177.759 283.338 177.777 283.392 ;
    END
  END r0_rd_out[411]
  PIN r0_rd_out[412]
    DIRECTION OUTPUT ;
    USE SIGNAL ;
    SHAPE ABUTMENT ;
    PORT
      LAYER M3 ;
      RECT 178.191 283.338 178.209 283.392 ;
    END
  END r0_rd_out[412]
  PIN r0_rd_out[413]
    DIRECTION OUTPUT ;
    USE SIGNAL ;
    SHAPE ABUTMENT ;
    PORT
      LAYER M3 ;
      RECT 178.623 283.338 178.641 283.392 ;
    END
  END r0_rd_out[413]
  PIN r0_rd_out[414]
    DIRECTION OUTPUT ;
    USE SIGNAL ;
    SHAPE ABUTMENT ;
    PORT
      LAYER M3 ;
      RECT 179.055 283.338 179.073 283.392 ;
    END
  END r0_rd_out[414]
  PIN r0_rd_out[415]
    DIRECTION OUTPUT ;
    USE SIGNAL ;
    SHAPE ABUTMENT ;
    PORT
      LAYER M3 ;
      RECT 179.487 283.338 179.505 283.392 ;
    END
  END r0_rd_out[415]
  PIN r0_rd_out[416]
    DIRECTION OUTPUT ;
    USE SIGNAL ;
    SHAPE ABUTMENT ;
    PORT
      LAYER M3 ;
      RECT 179.919 283.338 179.937 283.392 ;
    END
  END r0_rd_out[416]
  PIN r0_rd_out[417]
    DIRECTION OUTPUT ;
    USE SIGNAL ;
    SHAPE ABUTMENT ;
    PORT
      LAYER M3 ;
      RECT 180.351 283.338 180.369 283.392 ;
    END
  END r0_rd_out[417]
  PIN r0_rd_out[418]
    DIRECTION OUTPUT ;
    USE SIGNAL ;
    SHAPE ABUTMENT ;
    PORT
      LAYER M3 ;
      RECT 180.783 283.338 180.801 283.392 ;
    END
  END r0_rd_out[418]
  PIN r0_rd_out[419]
    DIRECTION OUTPUT ;
    USE SIGNAL ;
    SHAPE ABUTMENT ;
    PORT
      LAYER M3 ;
      RECT 181.215 283.338 181.233 283.392 ;
    END
  END r0_rd_out[419]
  PIN r0_rd_out[420]
    DIRECTION OUTPUT ;
    USE SIGNAL ;
    SHAPE ABUTMENT ;
    PORT
      LAYER M3 ;
      RECT 181.647 283.338 181.665 283.392 ;
    END
  END r0_rd_out[420]
  PIN r0_rd_out[421]
    DIRECTION OUTPUT ;
    USE SIGNAL ;
    SHAPE ABUTMENT ;
    PORT
      LAYER M3 ;
      RECT 182.079 283.338 182.097 283.392 ;
    END
  END r0_rd_out[421]
  PIN r0_rd_out[422]
    DIRECTION OUTPUT ;
    USE SIGNAL ;
    SHAPE ABUTMENT ;
    PORT
      LAYER M3 ;
      RECT 182.511 283.338 182.529 283.392 ;
    END
  END r0_rd_out[422]
  PIN r0_rd_out[423]
    DIRECTION OUTPUT ;
    USE SIGNAL ;
    SHAPE ABUTMENT ;
    PORT
      LAYER M3 ;
      RECT 182.943 283.338 182.961 283.392 ;
    END
  END r0_rd_out[423]
  PIN r0_rd_out[424]
    DIRECTION OUTPUT ;
    USE SIGNAL ;
    SHAPE ABUTMENT ;
    PORT
      LAYER M3 ;
      RECT 183.375 283.338 183.393 283.392 ;
    END
  END r0_rd_out[424]
  PIN r0_rd_out[425]
    DIRECTION OUTPUT ;
    USE SIGNAL ;
    SHAPE ABUTMENT ;
    PORT
      LAYER M3 ;
      RECT 183.807 283.338 183.825 283.392 ;
    END
  END r0_rd_out[425]
  PIN r0_rd_out[426]
    DIRECTION OUTPUT ;
    USE SIGNAL ;
    SHAPE ABUTMENT ;
    PORT
      LAYER M3 ;
      RECT 184.239 283.338 184.257 283.392 ;
    END
  END r0_rd_out[426]
  PIN r0_rd_out[427]
    DIRECTION OUTPUT ;
    USE SIGNAL ;
    SHAPE ABUTMENT ;
    PORT
      LAYER M3 ;
      RECT 184.671 283.338 184.689 283.392 ;
    END
  END r0_rd_out[427]
  PIN r0_rd_out[428]
    DIRECTION OUTPUT ;
    USE SIGNAL ;
    SHAPE ABUTMENT ;
    PORT
      LAYER M3 ;
      RECT 185.103 283.338 185.121 283.392 ;
    END
  END r0_rd_out[428]
  PIN r0_rd_out[429]
    DIRECTION OUTPUT ;
    USE SIGNAL ;
    SHAPE ABUTMENT ;
    PORT
      LAYER M3 ;
      RECT 185.535 283.338 185.553 283.392 ;
    END
  END r0_rd_out[429]
  PIN r0_rd_out[430]
    DIRECTION OUTPUT ;
    USE SIGNAL ;
    SHAPE ABUTMENT ;
    PORT
      LAYER M3 ;
      RECT 185.967 283.338 185.985 283.392 ;
    END
  END r0_rd_out[430]
  PIN r0_rd_out[431]
    DIRECTION OUTPUT ;
    USE SIGNAL ;
    SHAPE ABUTMENT ;
    PORT
      LAYER M3 ;
      RECT 186.399 283.338 186.417 283.392 ;
    END
  END r0_rd_out[431]
  PIN r0_rd_out[432]
    DIRECTION OUTPUT ;
    USE SIGNAL ;
    SHAPE ABUTMENT ;
    PORT
      LAYER M3 ;
      RECT 186.831 283.338 186.849 283.392 ;
    END
  END r0_rd_out[432]
  PIN r0_rd_out[433]
    DIRECTION OUTPUT ;
    USE SIGNAL ;
    SHAPE ABUTMENT ;
    PORT
      LAYER M3 ;
      RECT 187.263 283.338 187.281 283.392 ;
    END
  END r0_rd_out[433]
  PIN r0_rd_out[434]
    DIRECTION OUTPUT ;
    USE SIGNAL ;
    SHAPE ABUTMENT ;
    PORT
      LAYER M3 ;
      RECT 187.695 283.338 187.713 283.392 ;
    END
  END r0_rd_out[434]
  PIN r0_rd_out[435]
    DIRECTION OUTPUT ;
    USE SIGNAL ;
    SHAPE ABUTMENT ;
    PORT
      LAYER M3 ;
      RECT 188.127 283.338 188.145 283.392 ;
    END
  END r0_rd_out[435]
  PIN r0_rd_out[436]
    DIRECTION OUTPUT ;
    USE SIGNAL ;
    SHAPE ABUTMENT ;
    PORT
      LAYER M3 ;
      RECT 188.559 283.338 188.577 283.392 ;
    END
  END r0_rd_out[436]
  PIN r0_rd_out[437]
    DIRECTION OUTPUT ;
    USE SIGNAL ;
    SHAPE ABUTMENT ;
    PORT
      LAYER M3 ;
      RECT 188.991 283.338 189.009 283.392 ;
    END
  END r0_rd_out[437]
  PIN r0_rd_out[438]
    DIRECTION OUTPUT ;
    USE SIGNAL ;
    SHAPE ABUTMENT ;
    PORT
      LAYER M3 ;
      RECT 189.423 283.338 189.441 283.392 ;
    END
  END r0_rd_out[438]
  PIN r0_rd_out[439]
    DIRECTION OUTPUT ;
    USE SIGNAL ;
    SHAPE ABUTMENT ;
    PORT
      LAYER M3 ;
      RECT 189.855 283.338 189.873 283.392 ;
    END
  END r0_rd_out[439]
  PIN r0_rd_out[440]
    DIRECTION OUTPUT ;
    USE SIGNAL ;
    SHAPE ABUTMENT ;
    PORT
      LAYER M3 ;
      RECT 190.287 283.338 190.305 283.392 ;
    END
  END r0_rd_out[440]
  PIN r0_rd_out[441]
    DIRECTION OUTPUT ;
    USE SIGNAL ;
    SHAPE ABUTMENT ;
    PORT
      LAYER M3 ;
      RECT 190.719 283.338 190.737 283.392 ;
    END
  END r0_rd_out[441]
  PIN r0_rd_out[442]
    DIRECTION OUTPUT ;
    USE SIGNAL ;
    SHAPE ABUTMENT ;
    PORT
      LAYER M3 ;
      RECT 191.151 283.338 191.169 283.392 ;
    END
  END r0_rd_out[442]
  PIN r0_rd_out[443]
    DIRECTION OUTPUT ;
    USE SIGNAL ;
    SHAPE ABUTMENT ;
    PORT
      LAYER M3 ;
      RECT 191.583 283.338 191.601 283.392 ;
    END
  END r0_rd_out[443]
  PIN r0_rd_out[444]
    DIRECTION OUTPUT ;
    USE SIGNAL ;
    SHAPE ABUTMENT ;
    PORT
      LAYER M3 ;
      RECT 192.015 283.338 192.033 283.392 ;
    END
  END r0_rd_out[444]
  PIN r0_rd_out[445]
    DIRECTION OUTPUT ;
    USE SIGNAL ;
    SHAPE ABUTMENT ;
    PORT
      LAYER M3 ;
      RECT 192.447 283.338 192.465 283.392 ;
    END
  END r0_rd_out[445]
  PIN r0_rd_out[446]
    DIRECTION OUTPUT ;
    USE SIGNAL ;
    SHAPE ABUTMENT ;
    PORT
      LAYER M3 ;
      RECT 192.879 283.338 192.897 283.392 ;
    END
  END r0_rd_out[446]
  PIN r0_rd_out[447]
    DIRECTION OUTPUT ;
    USE SIGNAL ;
    SHAPE ABUTMENT ;
    PORT
      LAYER M3 ;
      RECT 193.311 283.338 193.329 283.392 ;
    END
  END r0_rd_out[447]
  PIN r0_rd_out[448]
    DIRECTION OUTPUT ;
    USE SIGNAL ;
    SHAPE ABUTMENT ;
    PORT
      LAYER M3 ;
      RECT 193.743 283.338 193.761 283.392 ;
    END
  END r0_rd_out[448]
  PIN r0_rd_out[449]
    DIRECTION OUTPUT ;
    USE SIGNAL ;
    SHAPE ABUTMENT ;
    PORT
      LAYER M3 ;
      RECT 194.175 283.338 194.193 283.392 ;
    END
  END r0_rd_out[449]
  PIN r0_rd_out[450]
    DIRECTION OUTPUT ;
    USE SIGNAL ;
    SHAPE ABUTMENT ;
    PORT
      LAYER M3 ;
      RECT 194.607 283.338 194.625 283.392 ;
    END
  END r0_rd_out[450]
  PIN r0_rd_out[451]
    DIRECTION OUTPUT ;
    USE SIGNAL ;
    SHAPE ABUTMENT ;
    PORT
      LAYER M3 ;
      RECT 195.039 283.338 195.057 283.392 ;
    END
  END r0_rd_out[451]
  PIN r0_rd_out[452]
    DIRECTION OUTPUT ;
    USE SIGNAL ;
    SHAPE ABUTMENT ;
    PORT
      LAYER M3 ;
      RECT 195.471 283.338 195.489 283.392 ;
    END
  END r0_rd_out[452]
  PIN r0_rd_out[453]
    DIRECTION OUTPUT ;
    USE SIGNAL ;
    SHAPE ABUTMENT ;
    PORT
      LAYER M3 ;
      RECT 195.903 283.338 195.921 283.392 ;
    END
  END r0_rd_out[453]
  PIN r0_rd_out[454]
    DIRECTION OUTPUT ;
    USE SIGNAL ;
    SHAPE ABUTMENT ;
    PORT
      LAYER M3 ;
      RECT 196.335 283.338 196.353 283.392 ;
    END
  END r0_rd_out[454]
  PIN r0_rd_out[455]
    DIRECTION OUTPUT ;
    USE SIGNAL ;
    SHAPE ABUTMENT ;
    PORT
      LAYER M3 ;
      RECT 196.767 283.338 196.785 283.392 ;
    END
  END r0_rd_out[455]
  PIN r0_rd_out[456]
    DIRECTION OUTPUT ;
    USE SIGNAL ;
    SHAPE ABUTMENT ;
    PORT
      LAYER M3 ;
      RECT 197.199 283.338 197.217 283.392 ;
    END
  END r0_rd_out[456]
  PIN r0_rd_out[457]
    DIRECTION OUTPUT ;
    USE SIGNAL ;
    SHAPE ABUTMENT ;
    PORT
      LAYER M3 ;
      RECT 197.631 283.338 197.649 283.392 ;
    END
  END r0_rd_out[457]
  PIN r0_rd_out[458]
    DIRECTION OUTPUT ;
    USE SIGNAL ;
    SHAPE ABUTMENT ;
    PORT
      LAYER M3 ;
      RECT 198.063 283.338 198.081 283.392 ;
    END
  END r0_rd_out[458]
  PIN r0_rd_out[459]
    DIRECTION OUTPUT ;
    USE SIGNAL ;
    SHAPE ABUTMENT ;
    PORT
      LAYER M3 ;
      RECT 198.495 283.338 198.513 283.392 ;
    END
  END r0_rd_out[459]
  PIN r0_rd_out[460]
    DIRECTION OUTPUT ;
    USE SIGNAL ;
    SHAPE ABUTMENT ;
    PORT
      LAYER M3 ;
      RECT 198.927 283.338 198.945 283.392 ;
    END
  END r0_rd_out[460]
  PIN r0_rd_out[461]
    DIRECTION OUTPUT ;
    USE SIGNAL ;
    SHAPE ABUTMENT ;
    PORT
      LAYER M3 ;
      RECT 199.359 283.338 199.377 283.392 ;
    END
  END r0_rd_out[461]
  PIN r0_rd_out[462]
    DIRECTION OUTPUT ;
    USE SIGNAL ;
    SHAPE ABUTMENT ;
    PORT
      LAYER M3 ;
      RECT 199.791 283.338 199.809 283.392 ;
    END
  END r0_rd_out[462]
  PIN r0_rd_out[463]
    DIRECTION OUTPUT ;
    USE SIGNAL ;
    SHAPE ABUTMENT ;
    PORT
      LAYER M3 ;
      RECT 200.223 283.338 200.241 283.392 ;
    END
  END r0_rd_out[463]
  PIN r0_rd_out[464]
    DIRECTION OUTPUT ;
    USE SIGNAL ;
    SHAPE ABUTMENT ;
    PORT
      LAYER M3 ;
      RECT 200.655 283.338 200.673 283.392 ;
    END
  END r0_rd_out[464]
  PIN r0_rd_out[465]
    DIRECTION OUTPUT ;
    USE SIGNAL ;
    SHAPE ABUTMENT ;
    PORT
      LAYER M3 ;
      RECT 201.087 283.338 201.105 283.392 ;
    END
  END r0_rd_out[465]
  PIN r0_rd_out[466]
    DIRECTION OUTPUT ;
    USE SIGNAL ;
    SHAPE ABUTMENT ;
    PORT
      LAYER M3 ;
      RECT 201.519 283.338 201.537 283.392 ;
    END
  END r0_rd_out[466]
  PIN r0_rd_out[467]
    DIRECTION OUTPUT ;
    USE SIGNAL ;
    SHAPE ABUTMENT ;
    PORT
      LAYER M3 ;
      RECT 201.951 283.338 201.969 283.392 ;
    END
  END r0_rd_out[467]
  PIN r0_rd_out[468]
    DIRECTION OUTPUT ;
    USE SIGNAL ;
    SHAPE ABUTMENT ;
    PORT
      LAYER M3 ;
      RECT 202.383 283.338 202.401 283.392 ;
    END
  END r0_rd_out[468]
  PIN r0_rd_out[469]
    DIRECTION OUTPUT ;
    USE SIGNAL ;
    SHAPE ABUTMENT ;
    PORT
      LAYER M3 ;
      RECT 202.815 283.338 202.833 283.392 ;
    END
  END r0_rd_out[469]
  PIN r0_rd_out[470]
    DIRECTION OUTPUT ;
    USE SIGNAL ;
    SHAPE ABUTMENT ;
    PORT
      LAYER M3 ;
      RECT 203.247 283.338 203.265 283.392 ;
    END
  END r0_rd_out[470]
  PIN r0_rd_out[471]
    DIRECTION OUTPUT ;
    USE SIGNAL ;
    SHAPE ABUTMENT ;
    PORT
      LAYER M3 ;
      RECT 203.679 283.338 203.697 283.392 ;
    END
  END r0_rd_out[471]
  PIN r0_rd_out[472]
    DIRECTION OUTPUT ;
    USE SIGNAL ;
    SHAPE ABUTMENT ;
    PORT
      LAYER M3 ;
      RECT 204.111 283.338 204.129 283.392 ;
    END
  END r0_rd_out[472]
  PIN r0_rd_out[473]
    DIRECTION OUTPUT ;
    USE SIGNAL ;
    SHAPE ABUTMENT ;
    PORT
      LAYER M3 ;
      RECT 204.543 283.338 204.561 283.392 ;
    END
  END r0_rd_out[473]
  PIN r0_rd_out[474]
    DIRECTION OUTPUT ;
    USE SIGNAL ;
    SHAPE ABUTMENT ;
    PORT
      LAYER M3 ;
      RECT 204.975 283.338 204.993 283.392 ;
    END
  END r0_rd_out[474]
  PIN r0_rd_out[475]
    DIRECTION OUTPUT ;
    USE SIGNAL ;
    SHAPE ABUTMENT ;
    PORT
      LAYER M3 ;
      RECT 205.407 283.338 205.425 283.392 ;
    END
  END r0_rd_out[475]
  PIN r0_rd_out[476]
    DIRECTION OUTPUT ;
    USE SIGNAL ;
    SHAPE ABUTMENT ;
    PORT
      LAYER M3 ;
      RECT 205.839 283.338 205.857 283.392 ;
    END
  END r0_rd_out[476]
  PIN r0_rd_out[477]
    DIRECTION OUTPUT ;
    USE SIGNAL ;
    SHAPE ABUTMENT ;
    PORT
      LAYER M3 ;
      RECT 206.271 283.338 206.289 283.392 ;
    END
  END r0_rd_out[477]
  PIN r0_rd_out[478]
    DIRECTION OUTPUT ;
    USE SIGNAL ;
    SHAPE ABUTMENT ;
    PORT
      LAYER M3 ;
      RECT 206.703 283.338 206.721 283.392 ;
    END
  END r0_rd_out[478]
  PIN r0_rd_out[479]
    DIRECTION OUTPUT ;
    USE SIGNAL ;
    SHAPE ABUTMENT ;
    PORT
      LAYER M3 ;
      RECT 207.135 283.338 207.153 283.392 ;
    END
  END r0_rd_out[479]
  PIN r0_rd_out[480]
    DIRECTION OUTPUT ;
    USE SIGNAL ;
    SHAPE ABUTMENT ;
    PORT
      LAYER M3 ;
      RECT 207.567 283.338 207.585 283.392 ;
    END
  END r0_rd_out[480]
  PIN r0_rd_out[481]
    DIRECTION OUTPUT ;
    USE SIGNAL ;
    SHAPE ABUTMENT ;
    PORT
      LAYER M3 ;
      RECT 207.999 283.338 208.017 283.392 ;
    END
  END r0_rd_out[481]
  PIN r0_rd_out[482]
    DIRECTION OUTPUT ;
    USE SIGNAL ;
    SHAPE ABUTMENT ;
    PORT
      LAYER M3 ;
      RECT 208.431 283.338 208.449 283.392 ;
    END
  END r0_rd_out[482]
  PIN r0_rd_out[483]
    DIRECTION OUTPUT ;
    USE SIGNAL ;
    SHAPE ABUTMENT ;
    PORT
      LAYER M3 ;
      RECT 208.863 283.338 208.881 283.392 ;
    END
  END r0_rd_out[483]
  PIN r0_rd_out[484]
    DIRECTION OUTPUT ;
    USE SIGNAL ;
    SHAPE ABUTMENT ;
    PORT
      LAYER M3 ;
      RECT 209.295 283.338 209.313 283.392 ;
    END
  END r0_rd_out[484]
  PIN r0_rd_out[485]
    DIRECTION OUTPUT ;
    USE SIGNAL ;
    SHAPE ABUTMENT ;
    PORT
      LAYER M3 ;
      RECT 209.727 283.338 209.745 283.392 ;
    END
  END r0_rd_out[485]
  PIN r0_rd_out[486]
    DIRECTION OUTPUT ;
    USE SIGNAL ;
    SHAPE ABUTMENT ;
    PORT
      LAYER M3 ;
      RECT 210.159 283.338 210.177 283.392 ;
    END
  END r0_rd_out[486]
  PIN r0_rd_out[487]
    DIRECTION OUTPUT ;
    USE SIGNAL ;
    SHAPE ABUTMENT ;
    PORT
      LAYER M3 ;
      RECT 210.591 283.338 210.609 283.392 ;
    END
  END r0_rd_out[487]
  PIN r0_rd_out[488]
    DIRECTION OUTPUT ;
    USE SIGNAL ;
    SHAPE ABUTMENT ;
    PORT
      LAYER M3 ;
      RECT 211.023 283.338 211.041 283.392 ;
    END
  END r0_rd_out[488]
  PIN r0_rd_out[489]
    DIRECTION OUTPUT ;
    USE SIGNAL ;
    SHAPE ABUTMENT ;
    PORT
      LAYER M3 ;
      RECT 211.455 283.338 211.473 283.392 ;
    END
  END r0_rd_out[489]
  PIN r0_rd_out[490]
    DIRECTION OUTPUT ;
    USE SIGNAL ;
    SHAPE ABUTMENT ;
    PORT
      LAYER M3 ;
      RECT 211.887 283.338 211.905 283.392 ;
    END
  END r0_rd_out[490]
  PIN r0_rd_out[491]
    DIRECTION OUTPUT ;
    USE SIGNAL ;
    SHAPE ABUTMENT ;
    PORT
      LAYER M3 ;
      RECT 212.319 283.338 212.337 283.392 ;
    END
  END r0_rd_out[491]
  PIN r0_rd_out[492]
    DIRECTION OUTPUT ;
    USE SIGNAL ;
    SHAPE ABUTMENT ;
    PORT
      LAYER M3 ;
      RECT 212.751 283.338 212.769 283.392 ;
    END
  END r0_rd_out[492]
  PIN r0_rd_out[493]
    DIRECTION OUTPUT ;
    USE SIGNAL ;
    SHAPE ABUTMENT ;
    PORT
      LAYER M3 ;
      RECT 213.183 283.338 213.201 283.392 ;
    END
  END r0_rd_out[493]
  PIN r0_rd_out[494]
    DIRECTION OUTPUT ;
    USE SIGNAL ;
    SHAPE ABUTMENT ;
    PORT
      LAYER M3 ;
      RECT 213.615 283.338 213.633 283.392 ;
    END
  END r0_rd_out[494]
  PIN r0_rd_out[495]
    DIRECTION OUTPUT ;
    USE SIGNAL ;
    SHAPE ABUTMENT ;
    PORT
      LAYER M3 ;
      RECT 214.047 283.338 214.065 283.392 ;
    END
  END r0_rd_out[495]
  PIN r0_rd_out[496]
    DIRECTION OUTPUT ;
    USE SIGNAL ;
    SHAPE ABUTMENT ;
    PORT
      LAYER M3 ;
      RECT 214.479 283.338 214.497 283.392 ;
    END
  END r0_rd_out[496]
  PIN r0_rd_out[497]
    DIRECTION OUTPUT ;
    USE SIGNAL ;
    SHAPE ABUTMENT ;
    PORT
      LAYER M3 ;
      RECT 214.911 283.338 214.929 283.392 ;
    END
  END r0_rd_out[497]
  PIN r0_rd_out[498]
    DIRECTION OUTPUT ;
    USE SIGNAL ;
    SHAPE ABUTMENT ;
    PORT
      LAYER M3 ;
      RECT 215.343 283.338 215.361 283.392 ;
    END
  END r0_rd_out[498]
  PIN r0_rd_out[499]
    DIRECTION OUTPUT ;
    USE SIGNAL ;
    SHAPE ABUTMENT ;
    PORT
      LAYER M3 ;
      RECT 215.775 283.338 215.793 283.392 ;
    END
  END r0_rd_out[499]
  PIN r0_rd_out[500]
    DIRECTION OUTPUT ;
    USE SIGNAL ;
    SHAPE ABUTMENT ;
    PORT
      LAYER M3 ;
      RECT 216.207 283.338 216.225 283.392 ;
    END
  END r0_rd_out[500]
  PIN r0_rd_out[501]
    DIRECTION OUTPUT ;
    USE SIGNAL ;
    SHAPE ABUTMENT ;
    PORT
      LAYER M3 ;
      RECT 216.639 283.338 216.657 283.392 ;
    END
  END r0_rd_out[501]
  PIN r0_rd_out[502]
    DIRECTION OUTPUT ;
    USE SIGNAL ;
    SHAPE ABUTMENT ;
    PORT
      LAYER M3 ;
      RECT 217.071 283.338 217.089 283.392 ;
    END
  END r0_rd_out[502]
  PIN r0_rd_out[503]
    DIRECTION OUTPUT ;
    USE SIGNAL ;
    SHAPE ABUTMENT ;
    PORT
      LAYER M3 ;
      RECT 217.503 283.338 217.521 283.392 ;
    END
  END r0_rd_out[503]
  PIN r0_rd_out[504]
    DIRECTION OUTPUT ;
    USE SIGNAL ;
    SHAPE ABUTMENT ;
    PORT
      LAYER M3 ;
      RECT 217.935 283.338 217.953 283.392 ;
    END
  END r0_rd_out[504]
  PIN r0_rd_out[505]
    DIRECTION OUTPUT ;
    USE SIGNAL ;
    SHAPE ABUTMENT ;
    PORT
      LAYER M3 ;
      RECT 218.367 283.338 218.385 283.392 ;
    END
  END r0_rd_out[505]
  PIN r0_rd_out[506]
    DIRECTION OUTPUT ;
    USE SIGNAL ;
    SHAPE ABUTMENT ;
    PORT
      LAYER M3 ;
      RECT 218.799 283.338 218.817 283.392 ;
    END
  END r0_rd_out[506]
  PIN r0_rd_out[507]
    DIRECTION OUTPUT ;
    USE SIGNAL ;
    SHAPE ABUTMENT ;
    PORT
      LAYER M3 ;
      RECT 219.231 283.338 219.249 283.392 ;
    END
  END r0_rd_out[507]
  PIN r0_rd_out[508]
    DIRECTION OUTPUT ;
    USE SIGNAL ;
    SHAPE ABUTMENT ;
    PORT
      LAYER M3 ;
      RECT 219.663 283.338 219.681 283.392 ;
    END
  END r0_rd_out[508]
  PIN r0_rd_out[509]
    DIRECTION OUTPUT ;
    USE SIGNAL ;
    SHAPE ABUTMENT ;
    PORT
      LAYER M3 ;
      RECT 220.095 283.338 220.113 283.392 ;
    END
  END r0_rd_out[509]
  PIN r0_rd_out[510]
    DIRECTION OUTPUT ;
    USE SIGNAL ;
    SHAPE ABUTMENT ;
    PORT
      LAYER M3 ;
      RECT 220.527 283.338 220.545 283.392 ;
    END
  END r0_rd_out[510]
  PIN r0_rd_out[511]
    DIRECTION OUTPUT ;
    USE SIGNAL ;
    SHAPE ABUTMENT ;
    PORT
      LAYER M3 ;
      RECT 220.959 283.338 220.977 283.392 ;
    END
  END r0_rd_out[511]
  PIN w0_addr_in[0]
    DIRECTION INPUT ;
    USE SIGNAL ;
    SHAPE ABUTMENT ;
    PORT
      LAYER M4 ;
      RECT 0.000 270.612 0.072 270.636 ;
    END
  END w0_addr_in[0]
  PIN w0_addr_in[1]
    DIRECTION INPUT ;
    USE SIGNAL ;
    SHAPE ABUTMENT ;
    PORT
      LAYER M4 ;
      RECT 0.000 271.668 0.072 271.692 ;
    END
  END w0_addr_in[1]
  PIN w0_addr_in[2]
    DIRECTION INPUT ;
    USE SIGNAL ;
    SHAPE ABUTMENT ;
    PORT
      LAYER M4 ;
      RECT 0.000 272.724 0.072 272.748 ;
    END
  END w0_addr_in[2]
  PIN w0_addr_in[3]
    DIRECTION INPUT ;
    USE SIGNAL ;
    SHAPE ABUTMENT ;
    PORT
      LAYER M4 ;
      RECT 0.000 273.780 0.072 273.804 ;
    END
  END w0_addr_in[3]
  PIN w0_addr_in[4]
    DIRECTION INPUT ;
    USE SIGNAL ;
    SHAPE ABUTMENT ;
    PORT
      LAYER M4 ;
      RECT 226.642 270.612 226.714 270.636 ;
    END
  END w0_addr_in[4]
  PIN w0_addr_in[5]
    DIRECTION INPUT ;
    USE SIGNAL ;
    SHAPE ABUTMENT ;
    PORT
      LAYER M4 ;
      RECT 226.642 271.668 226.714 271.692 ;
    END
  END w0_addr_in[5]
  PIN w0_addr_in[6]
    DIRECTION INPUT ;
    USE SIGNAL ;
    SHAPE ABUTMENT ;
    PORT
      LAYER M4 ;
      RECT 226.642 272.724 226.714 272.748 ;
    END
  END w0_addr_in[6]
  PIN w0_addr_in[7]
    DIRECTION INPUT ;
    USE SIGNAL ;
    SHAPE ABUTMENT ;
    PORT
      LAYER M4 ;
      RECT 226.642 273.780 226.714 273.804 ;
    END
  END w0_addr_in[7]
  PIN r0_addr_in[0]
    DIRECTION INPUT ;
    USE SIGNAL ;
    SHAPE ABUTMENT ;
    PORT
      LAYER M4 ;
      RECT 0.000 274.836 0.072 274.860 ;
    END
  END r0_addr_in[0]
  PIN r0_addr_in[1]
    DIRECTION INPUT ;
    USE SIGNAL ;
    SHAPE ABUTMENT ;
    PORT
      LAYER M4 ;
      RECT 0.000 275.892 0.072 275.916 ;
    END
  END r0_addr_in[1]
  PIN r0_addr_in[2]
    DIRECTION INPUT ;
    USE SIGNAL ;
    SHAPE ABUTMENT ;
    PORT
      LAYER M4 ;
      RECT 0.000 276.948 0.072 276.972 ;
    END
  END r0_addr_in[2]
  PIN r0_addr_in[3]
    DIRECTION INPUT ;
    USE SIGNAL ;
    SHAPE ABUTMENT ;
    PORT
      LAYER M4 ;
      RECT 0.000 278.004 0.072 278.028 ;
    END
  END r0_addr_in[3]
  PIN r0_addr_in[4]
    DIRECTION INPUT ;
    USE SIGNAL ;
    SHAPE ABUTMENT ;
    PORT
      LAYER M4 ;
      RECT 226.642 274.836 226.714 274.860 ;
    END
  END r0_addr_in[4]
  PIN r0_addr_in[5]
    DIRECTION INPUT ;
    USE SIGNAL ;
    SHAPE ABUTMENT ;
    PORT
      LAYER M4 ;
      RECT 226.642 275.892 226.714 275.916 ;
    END
  END r0_addr_in[5]
  PIN r0_addr_in[6]
    DIRECTION INPUT ;
    USE SIGNAL ;
    SHAPE ABUTMENT ;
    PORT
      LAYER M4 ;
      RECT 226.642 276.948 226.714 276.972 ;
    END
  END r0_addr_in[6]
  PIN r0_addr_in[7]
    DIRECTION INPUT ;
    USE SIGNAL ;
    SHAPE ABUTMENT ;
    PORT
      LAYER M4 ;
      RECT 226.642 278.004 226.714 278.028 ;
    END
  END r0_addr_in[7]
  PIN w0_we_in
    DIRECTION INPUT ;
    USE SIGNAL ;
    SHAPE ABUTMENT ;
    PORT
      LAYER M3 ;
      RECT 221.391 283.338 221.409 283.392 ;
    END
  END w0_we_in
  PIN w0_ce_in
    DIRECTION INPUT ;
    USE SIGNAL ;
    SHAPE ABUTMENT ;
    PORT
      LAYER M3 ;
      RECT 221.823 283.338 221.841 283.392 ;
    END
  END w0_ce_in
  PIN w0_clk
    DIRECTION INPUT ;
    USE SIGNAL ;
    SHAPE ABUTMENT ;
    PORT
      LAYER M3 ;
      RECT 222.255 283.338 222.273 283.392 ;
    END
  END w0_clk
  PIN r0_ce_in
    DIRECTION INPUT ;
    USE SIGNAL ;
    SHAPE ABUTMENT ;
    PORT
      LAYER M3 ;
      RECT 222.687 283.338 222.705 283.392 ;
    END
  END r0_ce_in
  PIN r0_clk
    DIRECTION INPUT ;
    USE SIGNAL ;
    SHAPE ABUTMENT ;
    PORT
      LAYER M3 ;
      RECT 223.119 283.338 223.137 283.392 ;
    END
  END r0_clk
  PIN VSS
    DIRECTION INOUT ;
    USE GROUND ;
    PORT
      LAYER M4 ;
      RECT 0.216 0.240 226.498 0.336 ;
      RECT 0.216 1.008 226.498 1.104 ;
      RECT 0.216 1.776 226.498 1.872 ;
      RECT 0.216 2.544 226.498 2.640 ;
      RECT 0.216 3.312 226.498 3.408 ;
      RECT 0.216 4.080 226.498 4.176 ;
      RECT 0.216 4.848 226.498 4.944 ;
      RECT 0.216 5.616 226.498 5.712 ;
      RECT 0.216 6.384 226.498 6.480 ;
      RECT 0.216 7.152 226.498 7.248 ;
      RECT 0.216 7.920 226.498 8.016 ;
      RECT 0.216 8.688 226.498 8.784 ;
      RECT 0.216 9.456 226.498 9.552 ;
      RECT 0.216 10.224 226.498 10.320 ;
      RECT 0.216 10.992 226.498 11.088 ;
      RECT 0.216 11.760 226.498 11.856 ;
      RECT 0.216 12.528 226.498 12.624 ;
      RECT 0.216 13.296 226.498 13.392 ;
      RECT 0.216 14.064 226.498 14.160 ;
      RECT 0.216 14.832 226.498 14.928 ;
      RECT 0.216 15.600 226.498 15.696 ;
      RECT 0.216 16.368 226.498 16.464 ;
      RECT 0.216 17.136 226.498 17.232 ;
      RECT 0.216 17.904 226.498 18.000 ;
      RECT 0.216 18.672 226.498 18.768 ;
      RECT 0.216 19.440 226.498 19.536 ;
      RECT 0.216 20.208 226.498 20.304 ;
      RECT 0.216 20.976 226.498 21.072 ;
      RECT 0.216 21.744 226.498 21.840 ;
      RECT 0.216 22.512 226.498 22.608 ;
      RECT 0.216 23.280 226.498 23.376 ;
      RECT 0.216 24.048 226.498 24.144 ;
      RECT 0.216 24.816 226.498 24.912 ;
      RECT 0.216 25.584 226.498 25.680 ;
      RECT 0.216 26.352 226.498 26.448 ;
      RECT 0.216 27.120 226.498 27.216 ;
      RECT 0.216 27.888 226.498 27.984 ;
      RECT 0.216 28.656 226.498 28.752 ;
      RECT 0.216 29.424 226.498 29.520 ;
      RECT 0.216 30.192 226.498 30.288 ;
      RECT 0.216 30.960 226.498 31.056 ;
      RECT 0.216 31.728 226.498 31.824 ;
      RECT 0.216 32.496 226.498 32.592 ;
      RECT 0.216 33.264 226.498 33.360 ;
      RECT 0.216 34.032 226.498 34.128 ;
      RECT 0.216 34.800 226.498 34.896 ;
      RECT 0.216 35.568 226.498 35.664 ;
      RECT 0.216 36.336 226.498 36.432 ;
      RECT 0.216 37.104 226.498 37.200 ;
      RECT 0.216 37.872 226.498 37.968 ;
      RECT 0.216 38.640 226.498 38.736 ;
      RECT 0.216 39.408 226.498 39.504 ;
      RECT 0.216 40.176 226.498 40.272 ;
      RECT 0.216 40.944 226.498 41.040 ;
      RECT 0.216 41.712 226.498 41.808 ;
      RECT 0.216 42.480 226.498 42.576 ;
      RECT 0.216 43.248 226.498 43.344 ;
      RECT 0.216 44.016 226.498 44.112 ;
      RECT 0.216 44.784 226.498 44.880 ;
      RECT 0.216 45.552 226.498 45.648 ;
      RECT 0.216 46.320 226.498 46.416 ;
      RECT 0.216 47.088 226.498 47.184 ;
      RECT 0.216 47.856 226.498 47.952 ;
      RECT 0.216 48.624 226.498 48.720 ;
      RECT 0.216 49.392 226.498 49.488 ;
      RECT 0.216 50.160 226.498 50.256 ;
      RECT 0.216 50.928 226.498 51.024 ;
      RECT 0.216 51.696 226.498 51.792 ;
      RECT 0.216 52.464 226.498 52.560 ;
      RECT 0.216 53.232 226.498 53.328 ;
      RECT 0.216 54.000 226.498 54.096 ;
      RECT 0.216 54.768 226.498 54.864 ;
      RECT 0.216 55.536 226.498 55.632 ;
      RECT 0.216 56.304 226.498 56.400 ;
      RECT 0.216 57.072 226.498 57.168 ;
      RECT 0.216 57.840 226.498 57.936 ;
      RECT 0.216 58.608 226.498 58.704 ;
      RECT 0.216 59.376 226.498 59.472 ;
      RECT 0.216 60.144 226.498 60.240 ;
      RECT 0.216 60.912 226.498 61.008 ;
      RECT 0.216 61.680 226.498 61.776 ;
      RECT 0.216 62.448 226.498 62.544 ;
      RECT 0.216 63.216 226.498 63.312 ;
      RECT 0.216 63.984 226.498 64.080 ;
      RECT 0.216 64.752 226.498 64.848 ;
      RECT 0.216 65.520 226.498 65.616 ;
      RECT 0.216 66.288 226.498 66.384 ;
      RECT 0.216 67.056 226.498 67.152 ;
      RECT 0.216 67.824 226.498 67.920 ;
      RECT 0.216 68.592 226.498 68.688 ;
      RECT 0.216 69.360 226.498 69.456 ;
      RECT 0.216 70.128 226.498 70.224 ;
      RECT 0.216 70.896 226.498 70.992 ;
      RECT 0.216 71.664 226.498 71.760 ;
      RECT 0.216 72.432 226.498 72.528 ;
      RECT 0.216 73.200 226.498 73.296 ;
      RECT 0.216 73.968 226.498 74.064 ;
      RECT 0.216 74.736 226.498 74.832 ;
      RECT 0.216 75.504 226.498 75.600 ;
      RECT 0.216 76.272 226.498 76.368 ;
      RECT 0.216 77.040 226.498 77.136 ;
      RECT 0.216 77.808 226.498 77.904 ;
      RECT 0.216 78.576 226.498 78.672 ;
      RECT 0.216 79.344 226.498 79.440 ;
      RECT 0.216 80.112 226.498 80.208 ;
      RECT 0.216 80.880 226.498 80.976 ;
      RECT 0.216 81.648 226.498 81.744 ;
      RECT 0.216 82.416 226.498 82.512 ;
      RECT 0.216 83.184 226.498 83.280 ;
      RECT 0.216 83.952 226.498 84.048 ;
      RECT 0.216 84.720 226.498 84.816 ;
      RECT 0.216 85.488 226.498 85.584 ;
      RECT 0.216 86.256 226.498 86.352 ;
      RECT 0.216 87.024 226.498 87.120 ;
      RECT 0.216 87.792 226.498 87.888 ;
      RECT 0.216 88.560 226.498 88.656 ;
      RECT 0.216 89.328 226.498 89.424 ;
      RECT 0.216 90.096 226.498 90.192 ;
      RECT 0.216 90.864 226.498 90.960 ;
      RECT 0.216 91.632 226.498 91.728 ;
      RECT 0.216 92.400 226.498 92.496 ;
      RECT 0.216 93.168 226.498 93.264 ;
      RECT 0.216 93.936 226.498 94.032 ;
      RECT 0.216 94.704 226.498 94.800 ;
      RECT 0.216 95.472 226.498 95.568 ;
      RECT 0.216 96.240 226.498 96.336 ;
      RECT 0.216 97.008 226.498 97.104 ;
      RECT 0.216 97.776 226.498 97.872 ;
      RECT 0.216 98.544 226.498 98.640 ;
      RECT 0.216 99.312 226.498 99.408 ;
      RECT 0.216 100.080 226.498 100.176 ;
      RECT 0.216 100.848 226.498 100.944 ;
      RECT 0.216 101.616 226.498 101.712 ;
      RECT 0.216 102.384 226.498 102.480 ;
      RECT 0.216 103.152 226.498 103.248 ;
      RECT 0.216 103.920 226.498 104.016 ;
      RECT 0.216 104.688 226.498 104.784 ;
      RECT 0.216 105.456 226.498 105.552 ;
      RECT 0.216 106.224 226.498 106.320 ;
      RECT 0.216 106.992 226.498 107.088 ;
      RECT 0.216 107.760 226.498 107.856 ;
      RECT 0.216 108.528 226.498 108.624 ;
      RECT 0.216 109.296 226.498 109.392 ;
      RECT 0.216 110.064 226.498 110.160 ;
      RECT 0.216 110.832 226.498 110.928 ;
      RECT 0.216 111.600 226.498 111.696 ;
      RECT 0.216 112.368 226.498 112.464 ;
      RECT 0.216 113.136 226.498 113.232 ;
      RECT 0.216 113.904 226.498 114.000 ;
      RECT 0.216 114.672 226.498 114.768 ;
      RECT 0.216 115.440 226.498 115.536 ;
      RECT 0.216 116.208 226.498 116.304 ;
      RECT 0.216 116.976 226.498 117.072 ;
      RECT 0.216 117.744 226.498 117.840 ;
      RECT 0.216 118.512 226.498 118.608 ;
      RECT 0.216 119.280 226.498 119.376 ;
      RECT 0.216 120.048 226.498 120.144 ;
      RECT 0.216 120.816 226.498 120.912 ;
      RECT 0.216 121.584 226.498 121.680 ;
      RECT 0.216 122.352 226.498 122.448 ;
      RECT 0.216 123.120 226.498 123.216 ;
      RECT 0.216 123.888 226.498 123.984 ;
      RECT 0.216 124.656 226.498 124.752 ;
      RECT 0.216 125.424 226.498 125.520 ;
      RECT 0.216 126.192 226.498 126.288 ;
      RECT 0.216 126.960 226.498 127.056 ;
      RECT 0.216 127.728 226.498 127.824 ;
      RECT 0.216 128.496 226.498 128.592 ;
      RECT 0.216 129.264 226.498 129.360 ;
      RECT 0.216 130.032 226.498 130.128 ;
      RECT 0.216 130.800 226.498 130.896 ;
      RECT 0.216 131.568 226.498 131.664 ;
      RECT 0.216 132.336 226.498 132.432 ;
      RECT 0.216 133.104 226.498 133.200 ;
      RECT 0.216 133.872 226.498 133.968 ;
      RECT 0.216 134.640 226.498 134.736 ;
      RECT 0.216 135.408 226.498 135.504 ;
      RECT 0.216 136.176 226.498 136.272 ;
      RECT 0.216 136.944 226.498 137.040 ;
      RECT 0.216 137.712 226.498 137.808 ;
      RECT 0.216 138.480 226.498 138.576 ;
      RECT 0.216 139.248 226.498 139.344 ;
      RECT 0.216 140.016 226.498 140.112 ;
      RECT 0.216 140.784 226.498 140.880 ;
      RECT 0.216 141.552 226.498 141.648 ;
      RECT 0.216 142.320 226.498 142.416 ;
      RECT 0.216 143.088 226.498 143.184 ;
      RECT 0.216 143.856 226.498 143.952 ;
      RECT 0.216 144.624 226.498 144.720 ;
      RECT 0.216 145.392 226.498 145.488 ;
      RECT 0.216 146.160 226.498 146.256 ;
      RECT 0.216 146.928 226.498 147.024 ;
      RECT 0.216 147.696 226.498 147.792 ;
      RECT 0.216 148.464 226.498 148.560 ;
      RECT 0.216 149.232 226.498 149.328 ;
      RECT 0.216 150.000 226.498 150.096 ;
      RECT 0.216 150.768 226.498 150.864 ;
      RECT 0.216 151.536 226.498 151.632 ;
      RECT 0.216 152.304 226.498 152.400 ;
      RECT 0.216 153.072 226.498 153.168 ;
      RECT 0.216 153.840 226.498 153.936 ;
      RECT 0.216 154.608 226.498 154.704 ;
      RECT 0.216 155.376 226.498 155.472 ;
      RECT 0.216 156.144 226.498 156.240 ;
      RECT 0.216 156.912 226.498 157.008 ;
      RECT 0.216 157.680 226.498 157.776 ;
      RECT 0.216 158.448 226.498 158.544 ;
      RECT 0.216 159.216 226.498 159.312 ;
      RECT 0.216 159.984 226.498 160.080 ;
      RECT 0.216 160.752 226.498 160.848 ;
      RECT 0.216 161.520 226.498 161.616 ;
      RECT 0.216 162.288 226.498 162.384 ;
      RECT 0.216 163.056 226.498 163.152 ;
      RECT 0.216 163.824 226.498 163.920 ;
      RECT 0.216 164.592 226.498 164.688 ;
      RECT 0.216 165.360 226.498 165.456 ;
      RECT 0.216 166.128 226.498 166.224 ;
      RECT 0.216 166.896 226.498 166.992 ;
      RECT 0.216 167.664 226.498 167.760 ;
      RECT 0.216 168.432 226.498 168.528 ;
      RECT 0.216 169.200 226.498 169.296 ;
      RECT 0.216 169.968 226.498 170.064 ;
      RECT 0.216 170.736 226.498 170.832 ;
      RECT 0.216 171.504 226.498 171.600 ;
      RECT 0.216 172.272 226.498 172.368 ;
      RECT 0.216 173.040 226.498 173.136 ;
      RECT 0.216 173.808 226.498 173.904 ;
      RECT 0.216 174.576 226.498 174.672 ;
      RECT 0.216 175.344 226.498 175.440 ;
      RECT 0.216 176.112 226.498 176.208 ;
      RECT 0.216 176.880 226.498 176.976 ;
      RECT 0.216 177.648 226.498 177.744 ;
      RECT 0.216 178.416 226.498 178.512 ;
      RECT 0.216 179.184 226.498 179.280 ;
      RECT 0.216 179.952 226.498 180.048 ;
      RECT 0.216 180.720 226.498 180.816 ;
      RECT 0.216 181.488 226.498 181.584 ;
      RECT 0.216 182.256 226.498 182.352 ;
      RECT 0.216 183.024 226.498 183.120 ;
      RECT 0.216 183.792 226.498 183.888 ;
      RECT 0.216 184.560 226.498 184.656 ;
      RECT 0.216 185.328 226.498 185.424 ;
      RECT 0.216 186.096 226.498 186.192 ;
      RECT 0.216 186.864 226.498 186.960 ;
      RECT 0.216 187.632 226.498 187.728 ;
      RECT 0.216 188.400 226.498 188.496 ;
      RECT 0.216 189.168 226.498 189.264 ;
      RECT 0.216 189.936 226.498 190.032 ;
      RECT 0.216 190.704 226.498 190.800 ;
      RECT 0.216 191.472 226.498 191.568 ;
      RECT 0.216 192.240 226.498 192.336 ;
      RECT 0.216 193.008 226.498 193.104 ;
      RECT 0.216 193.776 226.498 193.872 ;
      RECT 0.216 194.544 226.498 194.640 ;
      RECT 0.216 195.312 226.498 195.408 ;
      RECT 0.216 196.080 226.498 196.176 ;
      RECT 0.216 196.848 226.498 196.944 ;
      RECT 0.216 197.616 226.498 197.712 ;
      RECT 0.216 198.384 226.498 198.480 ;
      RECT 0.216 199.152 226.498 199.248 ;
      RECT 0.216 199.920 226.498 200.016 ;
      RECT 0.216 200.688 226.498 200.784 ;
      RECT 0.216 201.456 226.498 201.552 ;
      RECT 0.216 202.224 226.498 202.320 ;
      RECT 0.216 202.992 226.498 203.088 ;
      RECT 0.216 203.760 226.498 203.856 ;
      RECT 0.216 204.528 226.498 204.624 ;
      RECT 0.216 205.296 226.498 205.392 ;
      RECT 0.216 206.064 226.498 206.160 ;
      RECT 0.216 206.832 226.498 206.928 ;
      RECT 0.216 207.600 226.498 207.696 ;
      RECT 0.216 208.368 226.498 208.464 ;
      RECT 0.216 209.136 226.498 209.232 ;
      RECT 0.216 209.904 226.498 210.000 ;
      RECT 0.216 210.672 226.498 210.768 ;
      RECT 0.216 211.440 226.498 211.536 ;
      RECT 0.216 212.208 226.498 212.304 ;
      RECT 0.216 212.976 226.498 213.072 ;
      RECT 0.216 213.744 226.498 213.840 ;
      RECT 0.216 214.512 226.498 214.608 ;
      RECT 0.216 215.280 226.498 215.376 ;
      RECT 0.216 216.048 226.498 216.144 ;
      RECT 0.216 216.816 226.498 216.912 ;
      RECT 0.216 217.584 226.498 217.680 ;
      RECT 0.216 218.352 226.498 218.448 ;
      RECT 0.216 219.120 226.498 219.216 ;
      RECT 0.216 219.888 226.498 219.984 ;
      RECT 0.216 220.656 226.498 220.752 ;
      RECT 0.216 221.424 226.498 221.520 ;
      RECT 0.216 222.192 226.498 222.288 ;
      RECT 0.216 222.960 226.498 223.056 ;
      RECT 0.216 223.728 226.498 223.824 ;
      RECT 0.216 224.496 226.498 224.592 ;
      RECT 0.216 225.264 226.498 225.360 ;
      RECT 0.216 226.032 226.498 226.128 ;
      RECT 0.216 226.800 226.498 226.896 ;
      RECT 0.216 227.568 226.498 227.664 ;
      RECT 0.216 228.336 226.498 228.432 ;
      RECT 0.216 229.104 226.498 229.200 ;
      RECT 0.216 229.872 226.498 229.968 ;
      RECT 0.216 230.640 226.498 230.736 ;
      RECT 0.216 231.408 226.498 231.504 ;
      RECT 0.216 232.176 226.498 232.272 ;
      RECT 0.216 232.944 226.498 233.040 ;
      RECT 0.216 233.712 226.498 233.808 ;
      RECT 0.216 234.480 226.498 234.576 ;
      RECT 0.216 235.248 226.498 235.344 ;
      RECT 0.216 236.016 226.498 236.112 ;
      RECT 0.216 236.784 226.498 236.880 ;
      RECT 0.216 237.552 226.498 237.648 ;
      RECT 0.216 238.320 226.498 238.416 ;
      RECT 0.216 239.088 226.498 239.184 ;
      RECT 0.216 239.856 226.498 239.952 ;
      RECT 0.216 240.624 226.498 240.720 ;
      RECT 0.216 241.392 226.498 241.488 ;
      RECT 0.216 242.160 226.498 242.256 ;
      RECT 0.216 242.928 226.498 243.024 ;
      RECT 0.216 243.696 226.498 243.792 ;
      RECT 0.216 244.464 226.498 244.560 ;
      RECT 0.216 245.232 226.498 245.328 ;
      RECT 0.216 246.000 226.498 246.096 ;
      RECT 0.216 246.768 226.498 246.864 ;
      RECT 0.216 247.536 226.498 247.632 ;
      RECT 0.216 248.304 226.498 248.400 ;
      RECT 0.216 249.072 226.498 249.168 ;
      RECT 0.216 249.840 226.498 249.936 ;
      RECT 0.216 250.608 226.498 250.704 ;
      RECT 0.216 251.376 226.498 251.472 ;
      RECT 0.216 252.144 226.498 252.240 ;
      RECT 0.216 252.912 226.498 253.008 ;
      RECT 0.216 253.680 226.498 253.776 ;
      RECT 0.216 254.448 226.498 254.544 ;
      RECT 0.216 255.216 226.498 255.312 ;
      RECT 0.216 255.984 226.498 256.080 ;
      RECT 0.216 256.752 226.498 256.848 ;
      RECT 0.216 257.520 226.498 257.616 ;
      RECT 0.216 258.288 226.498 258.384 ;
      RECT 0.216 259.056 226.498 259.152 ;
      RECT 0.216 259.824 226.498 259.920 ;
      RECT 0.216 260.592 226.498 260.688 ;
      RECT 0.216 261.360 226.498 261.456 ;
      RECT 0.216 262.128 226.498 262.224 ;
      RECT 0.216 262.896 226.498 262.992 ;
      RECT 0.216 263.664 226.498 263.760 ;
      RECT 0.216 264.432 226.498 264.528 ;
      RECT 0.216 265.200 226.498 265.296 ;
      RECT 0.216 265.968 226.498 266.064 ;
      RECT 0.216 266.736 226.498 266.832 ;
      RECT 0.216 267.504 226.498 267.600 ;
      RECT 0.216 268.272 226.498 268.368 ;
      RECT 0.216 269.040 226.498 269.136 ;
      RECT 0.216 269.808 226.498 269.904 ;
      RECT 0.216 270.576 226.498 270.672 ;
      RECT 0.216 271.344 226.498 271.440 ;
      RECT 0.216 272.112 226.498 272.208 ;
      RECT 0.216 272.880 226.498 272.976 ;
      RECT 0.216 273.648 226.498 273.744 ;
      RECT 0.216 274.416 226.498 274.512 ;
      RECT 0.216 275.184 226.498 275.280 ;
      RECT 0.216 275.952 226.498 276.048 ;
      RECT 0.216 276.720 226.498 276.816 ;
      RECT 0.216 277.488 226.498 277.584 ;
      RECT 0.216 278.256 226.498 278.352 ;
      RECT 0.216 279.024 226.498 279.120 ;
      RECT 0.216 279.792 226.498 279.888 ;
      RECT 0.216 280.560 226.498 280.656 ;
      RECT 0.216 281.328 226.498 281.424 ;
      RECT 0.216 282.096 226.498 282.192 ;
      RECT 0.216 282.864 226.498 282.960 ;
    END
  END VSS
  PIN VDD
    DIRECTION INOUT ;
    USE POWER ;
    PORT
      LAYER M4 ;
      RECT 0.216 0.624 226.498 0.720 ;
      RECT 0.216 1.392 226.498 1.488 ;
      RECT 0.216 2.160 226.498 2.256 ;
      RECT 0.216 2.928 226.498 3.024 ;
      RECT 0.216 3.696 226.498 3.792 ;
      RECT 0.216 4.464 226.498 4.560 ;
      RECT 0.216 5.232 226.498 5.328 ;
      RECT 0.216 6.000 226.498 6.096 ;
      RECT 0.216 6.768 226.498 6.864 ;
      RECT 0.216 7.536 226.498 7.632 ;
      RECT 0.216 8.304 226.498 8.400 ;
      RECT 0.216 9.072 226.498 9.168 ;
      RECT 0.216 9.840 226.498 9.936 ;
      RECT 0.216 10.608 226.498 10.704 ;
      RECT 0.216 11.376 226.498 11.472 ;
      RECT 0.216 12.144 226.498 12.240 ;
      RECT 0.216 12.912 226.498 13.008 ;
      RECT 0.216 13.680 226.498 13.776 ;
      RECT 0.216 14.448 226.498 14.544 ;
      RECT 0.216 15.216 226.498 15.312 ;
      RECT 0.216 15.984 226.498 16.080 ;
      RECT 0.216 16.752 226.498 16.848 ;
      RECT 0.216 17.520 226.498 17.616 ;
      RECT 0.216 18.288 226.498 18.384 ;
      RECT 0.216 19.056 226.498 19.152 ;
      RECT 0.216 19.824 226.498 19.920 ;
      RECT 0.216 20.592 226.498 20.688 ;
      RECT 0.216 21.360 226.498 21.456 ;
      RECT 0.216 22.128 226.498 22.224 ;
      RECT 0.216 22.896 226.498 22.992 ;
      RECT 0.216 23.664 226.498 23.760 ;
      RECT 0.216 24.432 226.498 24.528 ;
      RECT 0.216 25.200 226.498 25.296 ;
      RECT 0.216 25.968 226.498 26.064 ;
      RECT 0.216 26.736 226.498 26.832 ;
      RECT 0.216 27.504 226.498 27.600 ;
      RECT 0.216 28.272 226.498 28.368 ;
      RECT 0.216 29.040 226.498 29.136 ;
      RECT 0.216 29.808 226.498 29.904 ;
      RECT 0.216 30.576 226.498 30.672 ;
      RECT 0.216 31.344 226.498 31.440 ;
      RECT 0.216 32.112 226.498 32.208 ;
      RECT 0.216 32.880 226.498 32.976 ;
      RECT 0.216 33.648 226.498 33.744 ;
      RECT 0.216 34.416 226.498 34.512 ;
      RECT 0.216 35.184 226.498 35.280 ;
      RECT 0.216 35.952 226.498 36.048 ;
      RECT 0.216 36.720 226.498 36.816 ;
      RECT 0.216 37.488 226.498 37.584 ;
      RECT 0.216 38.256 226.498 38.352 ;
      RECT 0.216 39.024 226.498 39.120 ;
      RECT 0.216 39.792 226.498 39.888 ;
      RECT 0.216 40.560 226.498 40.656 ;
      RECT 0.216 41.328 226.498 41.424 ;
      RECT 0.216 42.096 226.498 42.192 ;
      RECT 0.216 42.864 226.498 42.960 ;
      RECT 0.216 43.632 226.498 43.728 ;
      RECT 0.216 44.400 226.498 44.496 ;
      RECT 0.216 45.168 226.498 45.264 ;
      RECT 0.216 45.936 226.498 46.032 ;
      RECT 0.216 46.704 226.498 46.800 ;
      RECT 0.216 47.472 226.498 47.568 ;
      RECT 0.216 48.240 226.498 48.336 ;
      RECT 0.216 49.008 226.498 49.104 ;
      RECT 0.216 49.776 226.498 49.872 ;
      RECT 0.216 50.544 226.498 50.640 ;
      RECT 0.216 51.312 226.498 51.408 ;
      RECT 0.216 52.080 226.498 52.176 ;
      RECT 0.216 52.848 226.498 52.944 ;
      RECT 0.216 53.616 226.498 53.712 ;
      RECT 0.216 54.384 226.498 54.480 ;
      RECT 0.216 55.152 226.498 55.248 ;
      RECT 0.216 55.920 226.498 56.016 ;
      RECT 0.216 56.688 226.498 56.784 ;
      RECT 0.216 57.456 226.498 57.552 ;
      RECT 0.216 58.224 226.498 58.320 ;
      RECT 0.216 58.992 226.498 59.088 ;
      RECT 0.216 59.760 226.498 59.856 ;
      RECT 0.216 60.528 226.498 60.624 ;
      RECT 0.216 61.296 226.498 61.392 ;
      RECT 0.216 62.064 226.498 62.160 ;
      RECT 0.216 62.832 226.498 62.928 ;
      RECT 0.216 63.600 226.498 63.696 ;
      RECT 0.216 64.368 226.498 64.464 ;
      RECT 0.216 65.136 226.498 65.232 ;
      RECT 0.216 65.904 226.498 66.000 ;
      RECT 0.216 66.672 226.498 66.768 ;
      RECT 0.216 67.440 226.498 67.536 ;
      RECT 0.216 68.208 226.498 68.304 ;
      RECT 0.216 68.976 226.498 69.072 ;
      RECT 0.216 69.744 226.498 69.840 ;
      RECT 0.216 70.512 226.498 70.608 ;
      RECT 0.216 71.280 226.498 71.376 ;
      RECT 0.216 72.048 226.498 72.144 ;
      RECT 0.216 72.816 226.498 72.912 ;
      RECT 0.216 73.584 226.498 73.680 ;
      RECT 0.216 74.352 226.498 74.448 ;
      RECT 0.216 75.120 226.498 75.216 ;
      RECT 0.216 75.888 226.498 75.984 ;
      RECT 0.216 76.656 226.498 76.752 ;
      RECT 0.216 77.424 226.498 77.520 ;
      RECT 0.216 78.192 226.498 78.288 ;
      RECT 0.216 78.960 226.498 79.056 ;
      RECT 0.216 79.728 226.498 79.824 ;
      RECT 0.216 80.496 226.498 80.592 ;
      RECT 0.216 81.264 226.498 81.360 ;
      RECT 0.216 82.032 226.498 82.128 ;
      RECT 0.216 82.800 226.498 82.896 ;
      RECT 0.216 83.568 226.498 83.664 ;
      RECT 0.216 84.336 226.498 84.432 ;
      RECT 0.216 85.104 226.498 85.200 ;
      RECT 0.216 85.872 226.498 85.968 ;
      RECT 0.216 86.640 226.498 86.736 ;
      RECT 0.216 87.408 226.498 87.504 ;
      RECT 0.216 88.176 226.498 88.272 ;
      RECT 0.216 88.944 226.498 89.040 ;
      RECT 0.216 89.712 226.498 89.808 ;
      RECT 0.216 90.480 226.498 90.576 ;
      RECT 0.216 91.248 226.498 91.344 ;
      RECT 0.216 92.016 226.498 92.112 ;
      RECT 0.216 92.784 226.498 92.880 ;
      RECT 0.216 93.552 226.498 93.648 ;
      RECT 0.216 94.320 226.498 94.416 ;
      RECT 0.216 95.088 226.498 95.184 ;
      RECT 0.216 95.856 226.498 95.952 ;
      RECT 0.216 96.624 226.498 96.720 ;
      RECT 0.216 97.392 226.498 97.488 ;
      RECT 0.216 98.160 226.498 98.256 ;
      RECT 0.216 98.928 226.498 99.024 ;
      RECT 0.216 99.696 226.498 99.792 ;
      RECT 0.216 100.464 226.498 100.560 ;
      RECT 0.216 101.232 226.498 101.328 ;
      RECT 0.216 102.000 226.498 102.096 ;
      RECT 0.216 102.768 226.498 102.864 ;
      RECT 0.216 103.536 226.498 103.632 ;
      RECT 0.216 104.304 226.498 104.400 ;
      RECT 0.216 105.072 226.498 105.168 ;
      RECT 0.216 105.840 226.498 105.936 ;
      RECT 0.216 106.608 226.498 106.704 ;
      RECT 0.216 107.376 226.498 107.472 ;
      RECT 0.216 108.144 226.498 108.240 ;
      RECT 0.216 108.912 226.498 109.008 ;
      RECT 0.216 109.680 226.498 109.776 ;
      RECT 0.216 110.448 226.498 110.544 ;
      RECT 0.216 111.216 226.498 111.312 ;
      RECT 0.216 111.984 226.498 112.080 ;
      RECT 0.216 112.752 226.498 112.848 ;
      RECT 0.216 113.520 226.498 113.616 ;
      RECT 0.216 114.288 226.498 114.384 ;
      RECT 0.216 115.056 226.498 115.152 ;
      RECT 0.216 115.824 226.498 115.920 ;
      RECT 0.216 116.592 226.498 116.688 ;
      RECT 0.216 117.360 226.498 117.456 ;
      RECT 0.216 118.128 226.498 118.224 ;
      RECT 0.216 118.896 226.498 118.992 ;
      RECT 0.216 119.664 226.498 119.760 ;
      RECT 0.216 120.432 226.498 120.528 ;
      RECT 0.216 121.200 226.498 121.296 ;
      RECT 0.216 121.968 226.498 122.064 ;
      RECT 0.216 122.736 226.498 122.832 ;
      RECT 0.216 123.504 226.498 123.600 ;
      RECT 0.216 124.272 226.498 124.368 ;
      RECT 0.216 125.040 226.498 125.136 ;
      RECT 0.216 125.808 226.498 125.904 ;
      RECT 0.216 126.576 226.498 126.672 ;
      RECT 0.216 127.344 226.498 127.440 ;
      RECT 0.216 128.112 226.498 128.208 ;
      RECT 0.216 128.880 226.498 128.976 ;
      RECT 0.216 129.648 226.498 129.744 ;
      RECT 0.216 130.416 226.498 130.512 ;
      RECT 0.216 131.184 226.498 131.280 ;
      RECT 0.216 131.952 226.498 132.048 ;
      RECT 0.216 132.720 226.498 132.816 ;
      RECT 0.216 133.488 226.498 133.584 ;
      RECT 0.216 134.256 226.498 134.352 ;
      RECT 0.216 135.024 226.498 135.120 ;
      RECT 0.216 135.792 226.498 135.888 ;
      RECT 0.216 136.560 226.498 136.656 ;
      RECT 0.216 137.328 226.498 137.424 ;
      RECT 0.216 138.096 226.498 138.192 ;
      RECT 0.216 138.864 226.498 138.960 ;
      RECT 0.216 139.632 226.498 139.728 ;
      RECT 0.216 140.400 226.498 140.496 ;
      RECT 0.216 141.168 226.498 141.264 ;
      RECT 0.216 141.936 226.498 142.032 ;
      RECT 0.216 142.704 226.498 142.800 ;
      RECT 0.216 143.472 226.498 143.568 ;
      RECT 0.216 144.240 226.498 144.336 ;
      RECT 0.216 145.008 226.498 145.104 ;
      RECT 0.216 145.776 226.498 145.872 ;
      RECT 0.216 146.544 226.498 146.640 ;
      RECT 0.216 147.312 226.498 147.408 ;
      RECT 0.216 148.080 226.498 148.176 ;
      RECT 0.216 148.848 226.498 148.944 ;
      RECT 0.216 149.616 226.498 149.712 ;
      RECT 0.216 150.384 226.498 150.480 ;
      RECT 0.216 151.152 226.498 151.248 ;
      RECT 0.216 151.920 226.498 152.016 ;
      RECT 0.216 152.688 226.498 152.784 ;
      RECT 0.216 153.456 226.498 153.552 ;
      RECT 0.216 154.224 226.498 154.320 ;
      RECT 0.216 154.992 226.498 155.088 ;
      RECT 0.216 155.760 226.498 155.856 ;
      RECT 0.216 156.528 226.498 156.624 ;
      RECT 0.216 157.296 226.498 157.392 ;
      RECT 0.216 158.064 226.498 158.160 ;
      RECT 0.216 158.832 226.498 158.928 ;
      RECT 0.216 159.600 226.498 159.696 ;
      RECT 0.216 160.368 226.498 160.464 ;
      RECT 0.216 161.136 226.498 161.232 ;
      RECT 0.216 161.904 226.498 162.000 ;
      RECT 0.216 162.672 226.498 162.768 ;
      RECT 0.216 163.440 226.498 163.536 ;
      RECT 0.216 164.208 226.498 164.304 ;
      RECT 0.216 164.976 226.498 165.072 ;
      RECT 0.216 165.744 226.498 165.840 ;
      RECT 0.216 166.512 226.498 166.608 ;
      RECT 0.216 167.280 226.498 167.376 ;
      RECT 0.216 168.048 226.498 168.144 ;
      RECT 0.216 168.816 226.498 168.912 ;
      RECT 0.216 169.584 226.498 169.680 ;
      RECT 0.216 170.352 226.498 170.448 ;
      RECT 0.216 171.120 226.498 171.216 ;
      RECT 0.216 171.888 226.498 171.984 ;
      RECT 0.216 172.656 226.498 172.752 ;
      RECT 0.216 173.424 226.498 173.520 ;
      RECT 0.216 174.192 226.498 174.288 ;
      RECT 0.216 174.960 226.498 175.056 ;
      RECT 0.216 175.728 226.498 175.824 ;
      RECT 0.216 176.496 226.498 176.592 ;
      RECT 0.216 177.264 226.498 177.360 ;
      RECT 0.216 178.032 226.498 178.128 ;
      RECT 0.216 178.800 226.498 178.896 ;
      RECT 0.216 179.568 226.498 179.664 ;
      RECT 0.216 180.336 226.498 180.432 ;
      RECT 0.216 181.104 226.498 181.200 ;
      RECT 0.216 181.872 226.498 181.968 ;
      RECT 0.216 182.640 226.498 182.736 ;
      RECT 0.216 183.408 226.498 183.504 ;
      RECT 0.216 184.176 226.498 184.272 ;
      RECT 0.216 184.944 226.498 185.040 ;
      RECT 0.216 185.712 226.498 185.808 ;
      RECT 0.216 186.480 226.498 186.576 ;
      RECT 0.216 187.248 226.498 187.344 ;
      RECT 0.216 188.016 226.498 188.112 ;
      RECT 0.216 188.784 226.498 188.880 ;
      RECT 0.216 189.552 226.498 189.648 ;
      RECT 0.216 190.320 226.498 190.416 ;
      RECT 0.216 191.088 226.498 191.184 ;
      RECT 0.216 191.856 226.498 191.952 ;
      RECT 0.216 192.624 226.498 192.720 ;
      RECT 0.216 193.392 226.498 193.488 ;
      RECT 0.216 194.160 226.498 194.256 ;
      RECT 0.216 194.928 226.498 195.024 ;
      RECT 0.216 195.696 226.498 195.792 ;
      RECT 0.216 196.464 226.498 196.560 ;
      RECT 0.216 197.232 226.498 197.328 ;
      RECT 0.216 198.000 226.498 198.096 ;
      RECT 0.216 198.768 226.498 198.864 ;
      RECT 0.216 199.536 226.498 199.632 ;
      RECT 0.216 200.304 226.498 200.400 ;
      RECT 0.216 201.072 226.498 201.168 ;
      RECT 0.216 201.840 226.498 201.936 ;
      RECT 0.216 202.608 226.498 202.704 ;
      RECT 0.216 203.376 226.498 203.472 ;
      RECT 0.216 204.144 226.498 204.240 ;
      RECT 0.216 204.912 226.498 205.008 ;
      RECT 0.216 205.680 226.498 205.776 ;
      RECT 0.216 206.448 226.498 206.544 ;
      RECT 0.216 207.216 226.498 207.312 ;
      RECT 0.216 207.984 226.498 208.080 ;
      RECT 0.216 208.752 226.498 208.848 ;
      RECT 0.216 209.520 226.498 209.616 ;
      RECT 0.216 210.288 226.498 210.384 ;
      RECT 0.216 211.056 226.498 211.152 ;
      RECT 0.216 211.824 226.498 211.920 ;
      RECT 0.216 212.592 226.498 212.688 ;
      RECT 0.216 213.360 226.498 213.456 ;
      RECT 0.216 214.128 226.498 214.224 ;
      RECT 0.216 214.896 226.498 214.992 ;
      RECT 0.216 215.664 226.498 215.760 ;
      RECT 0.216 216.432 226.498 216.528 ;
      RECT 0.216 217.200 226.498 217.296 ;
      RECT 0.216 217.968 226.498 218.064 ;
      RECT 0.216 218.736 226.498 218.832 ;
      RECT 0.216 219.504 226.498 219.600 ;
      RECT 0.216 220.272 226.498 220.368 ;
      RECT 0.216 221.040 226.498 221.136 ;
      RECT 0.216 221.808 226.498 221.904 ;
      RECT 0.216 222.576 226.498 222.672 ;
      RECT 0.216 223.344 226.498 223.440 ;
      RECT 0.216 224.112 226.498 224.208 ;
      RECT 0.216 224.880 226.498 224.976 ;
      RECT 0.216 225.648 226.498 225.744 ;
      RECT 0.216 226.416 226.498 226.512 ;
      RECT 0.216 227.184 226.498 227.280 ;
      RECT 0.216 227.952 226.498 228.048 ;
      RECT 0.216 228.720 226.498 228.816 ;
      RECT 0.216 229.488 226.498 229.584 ;
      RECT 0.216 230.256 226.498 230.352 ;
      RECT 0.216 231.024 226.498 231.120 ;
      RECT 0.216 231.792 226.498 231.888 ;
      RECT 0.216 232.560 226.498 232.656 ;
      RECT 0.216 233.328 226.498 233.424 ;
      RECT 0.216 234.096 226.498 234.192 ;
      RECT 0.216 234.864 226.498 234.960 ;
      RECT 0.216 235.632 226.498 235.728 ;
      RECT 0.216 236.400 226.498 236.496 ;
      RECT 0.216 237.168 226.498 237.264 ;
      RECT 0.216 237.936 226.498 238.032 ;
      RECT 0.216 238.704 226.498 238.800 ;
      RECT 0.216 239.472 226.498 239.568 ;
      RECT 0.216 240.240 226.498 240.336 ;
      RECT 0.216 241.008 226.498 241.104 ;
      RECT 0.216 241.776 226.498 241.872 ;
      RECT 0.216 242.544 226.498 242.640 ;
      RECT 0.216 243.312 226.498 243.408 ;
      RECT 0.216 244.080 226.498 244.176 ;
      RECT 0.216 244.848 226.498 244.944 ;
      RECT 0.216 245.616 226.498 245.712 ;
      RECT 0.216 246.384 226.498 246.480 ;
      RECT 0.216 247.152 226.498 247.248 ;
      RECT 0.216 247.920 226.498 248.016 ;
      RECT 0.216 248.688 226.498 248.784 ;
      RECT 0.216 249.456 226.498 249.552 ;
      RECT 0.216 250.224 226.498 250.320 ;
      RECT 0.216 250.992 226.498 251.088 ;
      RECT 0.216 251.760 226.498 251.856 ;
      RECT 0.216 252.528 226.498 252.624 ;
      RECT 0.216 253.296 226.498 253.392 ;
      RECT 0.216 254.064 226.498 254.160 ;
      RECT 0.216 254.832 226.498 254.928 ;
      RECT 0.216 255.600 226.498 255.696 ;
      RECT 0.216 256.368 226.498 256.464 ;
      RECT 0.216 257.136 226.498 257.232 ;
      RECT 0.216 257.904 226.498 258.000 ;
      RECT 0.216 258.672 226.498 258.768 ;
      RECT 0.216 259.440 226.498 259.536 ;
      RECT 0.216 260.208 226.498 260.304 ;
      RECT 0.216 260.976 226.498 261.072 ;
      RECT 0.216 261.744 226.498 261.840 ;
      RECT 0.216 262.512 226.498 262.608 ;
      RECT 0.216 263.280 226.498 263.376 ;
      RECT 0.216 264.048 226.498 264.144 ;
      RECT 0.216 264.816 226.498 264.912 ;
      RECT 0.216 265.584 226.498 265.680 ;
      RECT 0.216 266.352 226.498 266.448 ;
      RECT 0.216 267.120 226.498 267.216 ;
      RECT 0.216 267.888 226.498 267.984 ;
      RECT 0.216 268.656 226.498 268.752 ;
      RECT 0.216 269.424 226.498 269.520 ;
      RECT 0.216 270.192 226.498 270.288 ;
      RECT 0.216 270.960 226.498 271.056 ;
      RECT 0.216 271.728 226.498 271.824 ;
      RECT 0.216 272.496 226.498 272.592 ;
      RECT 0.216 273.264 226.498 273.360 ;
      RECT 0.216 274.032 226.498 274.128 ;
      RECT 0.216 274.800 226.498 274.896 ;
      RECT 0.216 275.568 226.498 275.664 ;
      RECT 0.216 276.336 226.498 276.432 ;
      RECT 0.216 277.104 226.498 277.200 ;
      RECT 0.216 277.872 226.498 277.968 ;
      RECT 0.216 278.640 226.498 278.736 ;
      RECT 0.216 279.408 226.498 279.504 ;
      RECT 0.216 280.176 226.498 280.272 ;
      RECT 0.216 280.944 226.498 281.040 ;
      RECT 0.216 281.712 226.498 281.808 ;
      RECT 0.216 282.480 226.498 282.576 ;
      RECT 0.216 283.248 226.498 283.344 ;
    END
  END VDD
  OBS
    LAYER M1 ;
    RECT 0 0 226.714 283.392 ;
    LAYER M2 ;
    RECT 0 0 226.714 283.392 ;
    LAYER M3 ;
    RECT 0 0 226.714 283.392 ;
    LAYER M4 ;
    RECT 0 0 226.714 283.392 ;
  END
END fakeram_512x256_1r1w

END LIBRARY
